VERSION 5.8 ;
BUSBITCHARS "[]" ;
DIVIDERCHAR "/" ;
UNITS
    DATABASE MICRONS 1000 ;
END UNITS

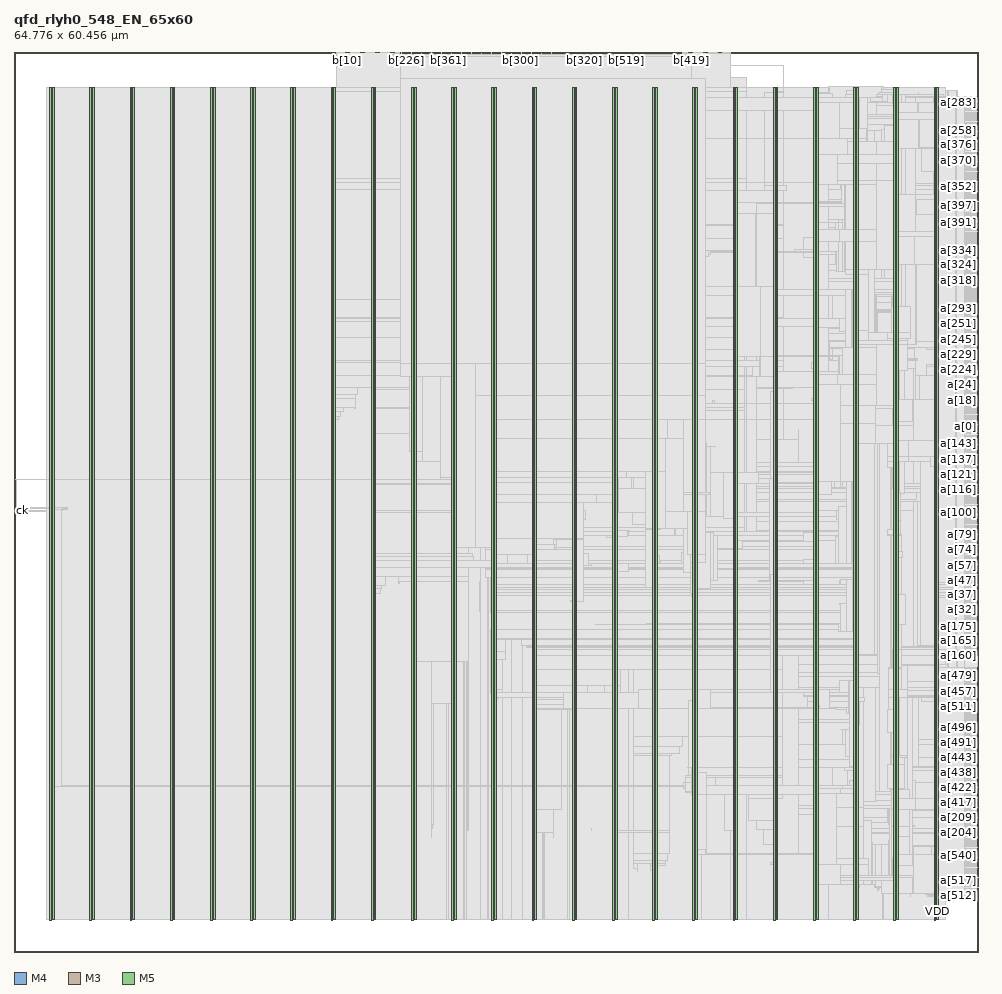
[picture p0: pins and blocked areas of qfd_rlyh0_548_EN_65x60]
MACRO qfd_rlyh0_548_EN_65x60
  FOREIGN qfd_rlyh0_548_EN_65x60 0 0 ;
  CLASS BLOCK ;
  SIZE 64.776 BY 60.456 ;
  PIN a[0]
    DIRECTION INPUT ;
    USE SIGNAL ;
    PORT
      LAYER M4 ;
        RECT  64.692 35.28 64.776 35.304 ;
    END
  END a[0]
  PIN a[100]
    DIRECTION INPUT ;
    USE SIGNAL ;
    PORT
      LAYER M4 ;
        RECT  64.692 29.52 64.776 29.544 ;
    END
  END a[100]
  PIN a[101]
    DIRECTION INPUT ;
    USE SIGNAL ;
    PORT
      LAYER M4 ;
        RECT  64.692 29.616 64.776 29.64 ;
    END
  END a[101]
  PIN a[102]
    DIRECTION INPUT ;
    USE SIGNAL ;
    PORT
      LAYER M4 ;
        RECT  64.692 29.712 64.776 29.736 ;
    END
  END a[102]
  PIN a[103]
    DIRECTION INPUT ;
    USE SIGNAL ;
    PORT
      LAYER M4 ;
        RECT  64.692 29.808 64.776 29.832 ;
    END
  END a[103]
  PIN a[104]
    DIRECTION INPUT ;
    USE SIGNAL ;
    PORT
      LAYER M4 ;
        RECT  64.692 29.904 64.776 29.928 ;
    END
  END a[104]
  PIN a[105]
    DIRECTION INPUT ;
    USE SIGNAL ;
    PORT
      LAYER M4 ;
        RECT  64.692 30 64.776 30.024 ;
    END
  END a[105]
  PIN a[106]
    DIRECTION INPUT ;
    USE SIGNAL ;
    PORT
      LAYER M4 ;
        RECT  64.692 30.096 64.776 30.12 ;
    END
  END a[106]
  PIN a[107]
    DIRECTION INPUT ;
    USE SIGNAL ;
    PORT
      LAYER M4 ;
        RECT  64.692 30.192 64.776 30.216 ;
    END
  END a[107]
  PIN a[108]
    DIRECTION INPUT ;
    USE SIGNAL ;
    PORT
      LAYER M4 ;
        RECT  64.692 30.288 64.776 30.312 ;
    END
  END a[108]
  PIN a[109]
    DIRECTION INPUT ;
    USE SIGNAL ;
    PORT
      LAYER M4 ;
        RECT  64.692 30.384 64.776 30.408 ;
    END
  END a[109]
  PIN a[10]
    DIRECTION INPUT ;
    USE SIGNAL ;
    PORT
      LAYER M4 ;
        RECT  64.692 36.24 64.776 36.264 ;
    END
  END a[10]
  PIN a[110]
    DIRECTION INPUT ;
    USE SIGNAL ;
    PORT
      LAYER M4 ;
        RECT  64.692 30.48 64.776 30.504 ;
    END
  END a[110]
  PIN a[111]
    DIRECTION INPUT ;
    USE SIGNAL ;
    PORT
      LAYER M4 ;
        RECT  64.692 30.576 64.776 30.6 ;
    END
  END a[111]
  PIN a[112]
    DIRECTION INPUT ;
    USE SIGNAL ;
    PORT
      LAYER M4 ;
        RECT  64.692 30.672 64.776 30.696 ;
    END
  END a[112]
  PIN a[113]
    DIRECTION INPUT ;
    USE SIGNAL ;
    PORT
      LAYER M4 ;
        RECT  64.692 30.768 64.776 30.792 ;
    END
  END a[113]
  PIN a[114]
    DIRECTION INPUT ;
    USE SIGNAL ;
    PORT
      LAYER M4 ;
        RECT  64.692 30.864 64.776 30.888 ;
    END
  END a[114]
  PIN a[115]
    DIRECTION INPUT ;
    USE SIGNAL ;
    PORT
      LAYER M4 ;
        RECT  64.692 30.96 64.776 30.984 ;
    END
  END a[115]
  PIN a[116]
    DIRECTION INPUT ;
    USE SIGNAL ;
    PORT
      LAYER M4 ;
        RECT  64.692 31.056 64.776 31.08 ;
    END
  END a[116]
  PIN a[117]
    DIRECTION INPUT ;
    USE SIGNAL ;
    PORT
      LAYER M4 ;
        RECT  64.692 31.152 64.776 31.176 ;
    END
  END a[117]
  PIN a[118]
    DIRECTION INPUT ;
    USE SIGNAL ;
    PORT
      LAYER M4 ;
        RECT  64.692 31.248 64.776 31.272 ;
    END
  END a[118]
  PIN a[119]
    DIRECTION INPUT ;
    USE SIGNAL ;
    PORT
      LAYER M4 ;
        RECT  64.692 31.344 64.776 31.368 ;
    END
  END a[119]
  PIN a[11]
    DIRECTION INPUT ;
    USE SIGNAL ;
    PORT
      LAYER M4 ;
        RECT  64.692 36.336 64.776 36.36 ;
    END
  END a[11]
  PIN a[120]
    DIRECTION INPUT ;
    USE SIGNAL ;
    PORT
      LAYER M4 ;
        RECT  64.692 31.44 64.776 31.464 ;
    END
  END a[120]
  PIN a[121]
    DIRECTION INPUT ;
    USE SIGNAL ;
    PORT
      LAYER M4 ;
        RECT  64.692 31.536 64.776 31.56 ;
    END
  END a[121]
  PIN a[122]
    DIRECTION INPUT ;
    USE SIGNAL ;
    PORT
      LAYER M4 ;
        RECT  64.692 31.632 64.776 31.656 ;
    END
  END a[122]
  PIN a[123]
    DIRECTION INPUT ;
    USE SIGNAL ;
    PORT
      LAYER M4 ;
        RECT  64.692 31.728 64.776 31.752 ;
    END
  END a[123]
  PIN a[124]
    DIRECTION INPUT ;
    USE SIGNAL ;
    PORT
      LAYER M4 ;
        RECT  64.692 31.824 64.776 31.848 ;
    END
  END a[124]
  PIN a[125]
    DIRECTION INPUT ;
    USE SIGNAL ;
    PORT
      LAYER M4 ;
        RECT  64.692 31.92 64.776 31.944 ;
    END
  END a[125]
  PIN a[126]
    DIRECTION INPUT ;
    USE SIGNAL ;
    PORT
      LAYER M4 ;
        RECT  64.692 32.016 64.776 32.04 ;
    END
  END a[126]
  PIN a[127]
    DIRECTION INPUT ;
    USE SIGNAL ;
    PORT
      LAYER M4 ;
        RECT  64.692 32.112 64.776 32.136 ;
    END
  END a[127]
  PIN a[128]
    DIRECTION INPUT ;
    USE SIGNAL ;
    PORT
      LAYER M4 ;
        RECT  64.692 32.208 64.776 32.232 ;
    END
  END a[128]
  PIN a[129]
    DIRECTION INPUT ;
    USE SIGNAL ;
    PORT
      LAYER M4 ;
        RECT  64.692 32.304 64.776 32.328 ;
    END
  END a[129]
  PIN a[12]
    DIRECTION INPUT ;
    USE SIGNAL ;
    PORT
      LAYER M4 ;
        RECT  64.692 36.432 64.776 36.456 ;
    END
  END a[12]
  PIN a[130]
    DIRECTION INPUT ;
    USE SIGNAL ;
    PORT
      LAYER M4 ;
        RECT  64.692 32.4 64.776 32.424 ;
    END
  END a[130]
  PIN a[131]
    DIRECTION INPUT ;
    USE SIGNAL ;
    PORT
      LAYER M4 ;
        RECT  64.692 32.496 64.776 32.52 ;
    END
  END a[131]
  PIN a[132]
    DIRECTION INPUT ;
    USE SIGNAL ;
    PORT
      LAYER M4 ;
        RECT  64.692 32.592 64.776 32.616 ;
    END
  END a[132]
  PIN a[133]
    DIRECTION INPUT ;
    USE SIGNAL ;
    PORT
      LAYER M4 ;
        RECT  64.692 32.688 64.776 32.712 ;
    END
  END a[133]
  PIN a[134]
    DIRECTION INPUT ;
    USE SIGNAL ;
    PORT
      LAYER M4 ;
        RECT  64.692 32.784 64.776 32.808 ;
    END
  END a[134]
  PIN a[135]
    DIRECTION INPUT ;
    USE SIGNAL ;
    PORT
      LAYER M4 ;
        RECT  64.692 32.88 64.776 32.904 ;
    END
  END a[135]
  PIN a[136]
    DIRECTION INPUT ;
    USE SIGNAL ;
    PORT
      LAYER M4 ;
        RECT  64.692 32.976 64.776 33 ;
    END
  END a[136]
  PIN a[137]
    DIRECTION INPUT ;
    USE SIGNAL ;
    PORT
      LAYER M4 ;
        RECT  64.692 33.072 64.776 33.096 ;
    END
  END a[137]
  PIN a[138]
    DIRECTION INPUT ;
    USE SIGNAL ;
    PORT
      LAYER M4 ;
        RECT  64.692 33.168 64.776 33.192 ;
    END
  END a[138]
  PIN a[139]
    DIRECTION INPUT ;
    USE SIGNAL ;
    PORT
      LAYER M4 ;
        RECT  64.692 33.264 64.776 33.288 ;
    END
  END a[139]
  PIN a[13]
    DIRECTION INPUT ;
    USE SIGNAL ;
    PORT
      LAYER M4 ;
        RECT  64.692 36.528 64.776 36.552 ;
    END
  END a[13]
  PIN a[140]
    DIRECTION INPUT ;
    USE SIGNAL ;
    PORT
      LAYER M4 ;
        RECT  64.692 33.36 64.776 33.384 ;
    END
  END a[140]
  PIN a[141]
    DIRECTION INPUT ;
    USE SIGNAL ;
    PORT
      LAYER M4 ;
        RECT  64.692 33.456 64.776 33.48 ;
    END
  END a[141]
  PIN a[142]
    DIRECTION INPUT ;
    USE SIGNAL ;
    PORT
      LAYER M4 ;
        RECT  64.692 33.552 64.776 33.576 ;
    END
  END a[142]
  PIN a[143]
    DIRECTION INPUT ;
    USE SIGNAL ;
    PORT
      LAYER M4 ;
        RECT  64.692 33.648 64.776 33.672 ;
    END
  END a[143]
  PIN a[144]
    DIRECTION INPUT ;
    USE SIGNAL ;
    PORT
      LAYER M4 ;
        RECT  64.692 33.744 64.776 33.768 ;
    END
  END a[144]
  PIN a[145]
    DIRECTION INPUT ;
    USE SIGNAL ;
    PORT
      LAYER M4 ;
        RECT  64.692 33.84 64.776 33.864 ;
    END
  END a[145]
  PIN a[146]
    DIRECTION INPUT ;
    USE SIGNAL ;
    PORT
      LAYER M4 ;
        RECT  64.692 33.936 64.776 33.96 ;
    END
  END a[146]
  PIN a[147]
    DIRECTION INPUT ;
    USE SIGNAL ;
    PORT
      LAYER M4 ;
        RECT  64.692 34.032 64.776 34.056 ;
    END
  END a[147]
  PIN a[148]
    DIRECTION INPUT ;
    USE SIGNAL ;
    PORT
      LAYER M4 ;
        RECT  64.692 34.128 64.776 34.152 ;
    END
  END a[148]
  PIN a[149]
    DIRECTION INPUT ;
    USE SIGNAL ;
    PORT
      LAYER M4 ;
        RECT  64.692 34.224 64.776 34.248 ;
    END
  END a[149]
  PIN a[14]
    DIRECTION INPUT ;
    USE SIGNAL ;
    PORT
      LAYER M4 ;
        RECT  64.692 36.624 64.776 36.648 ;
    END
  END a[14]
  PIN a[150]
    DIRECTION INPUT ;
    USE SIGNAL ;
    PORT
      LAYER M4 ;
        RECT  64.692 34.32 64.776 34.344 ;
    END
  END a[150]
  PIN a[151]
    DIRECTION INPUT ;
    USE SIGNAL ;
    PORT
      LAYER M4 ;
        RECT  64.692 34.416 64.776 34.44 ;
    END
  END a[151]
  PIN a[152]
    DIRECTION INPUT ;
    USE SIGNAL ;
    PORT
      LAYER M4 ;
        RECT  64.692 34.512 64.776 34.536 ;
    END
  END a[152]
  PIN a[153]
    DIRECTION INPUT ;
    USE SIGNAL ;
    PORT
      LAYER M4 ;
        RECT  64.692 34.608 64.776 34.632 ;
    END
  END a[153]
  PIN a[154]
    DIRECTION INPUT ;
    USE SIGNAL ;
    PORT
      LAYER M4 ;
        RECT  64.692 34.704 64.776 34.728 ;
    END
  END a[154]
  PIN a[155]
    DIRECTION INPUT ;
    USE SIGNAL ;
    PORT
      LAYER M4 ;
        RECT  64.692 34.8 64.776 34.824 ;
    END
  END a[155]
  PIN a[156]
    DIRECTION INPUT ;
    USE SIGNAL ;
    PORT
      LAYER M4 ;
        RECT  64.692 34.896 64.776 34.92 ;
    END
  END a[156]
  PIN a[157]
    DIRECTION INPUT ;
    USE SIGNAL ;
    PORT
      LAYER M4 ;
        RECT  64.692 34.992 64.776 35.016 ;
    END
  END a[157]
  PIN a[158]
    DIRECTION INPUT ;
    USE SIGNAL ;
    PORT
      LAYER M4 ;
        RECT  64.692 35.088 64.776 35.112 ;
    END
  END a[158]
  PIN a[159]
    DIRECTION INPUT ;
    USE SIGNAL ;
    PORT
      LAYER M4 ;
        RECT  64.692 35.184 64.776 35.208 ;
    END
  END a[159]
  PIN a[15]
    DIRECTION INPUT ;
    USE SIGNAL ;
    PORT
      LAYER M4 ;
        RECT  64.692 36.72 64.776 36.744 ;
    END
  END a[15]
  PIN a[160]
    DIRECTION INPUT ;
    USE SIGNAL ;
    PORT
      LAYER M4 ;
        RECT  64.692 19.92 64.776 19.944 ;
    END
  END a[160]
  PIN a[161]
    DIRECTION INPUT ;
    USE SIGNAL ;
    PORT
      LAYER M4 ;
        RECT  64.692 20.016 64.776 20.04 ;
    END
  END a[161]
  PIN a[162]
    DIRECTION INPUT ;
    USE SIGNAL ;
    PORT
      LAYER M4 ;
        RECT  64.692 20.112 64.776 20.136 ;
    END
  END a[162]
  PIN a[163]
    DIRECTION INPUT ;
    USE SIGNAL ;
    PORT
      LAYER M4 ;
        RECT  64.692 20.208 64.776 20.232 ;
    END
  END a[163]
  PIN a[164]
    DIRECTION INPUT ;
    USE SIGNAL ;
    PORT
      LAYER M4 ;
        RECT  64.692 20.304 64.776 20.328 ;
    END
  END a[164]
  PIN a[165]
    DIRECTION INPUT ;
    USE SIGNAL ;
    PORT
      LAYER M4 ;
        RECT  64.692 20.4 64.776 20.424 ;
    END
  END a[165]
  PIN a[166]
    DIRECTION INPUT ;
    USE SIGNAL ;
    PORT
      LAYER M4 ;
        RECT  64.692 20.496 64.776 20.52 ;
    END
  END a[166]
  PIN a[167]
    DIRECTION INPUT ;
    USE SIGNAL ;
    PORT
      LAYER M4 ;
        RECT  64.692 20.592 64.776 20.616 ;
    END
  END a[167]
  PIN a[168]
    DIRECTION INPUT ;
    USE SIGNAL ;
    PORT
      LAYER M4 ;
        RECT  64.692 20.688 64.776 20.712 ;
    END
  END a[168]
  PIN a[169]
    DIRECTION INPUT ;
    USE SIGNAL ;
    PORT
      LAYER M4 ;
        RECT  64.692 20.784 64.776 20.808 ;
    END
  END a[169]
  PIN a[16]
    DIRECTION INPUT ;
    USE SIGNAL ;
    PORT
      LAYER M4 ;
        RECT  64.692 36.816 64.776 36.84 ;
    END
  END a[16]
  PIN a[170]
    DIRECTION INPUT ;
    USE SIGNAL ;
    PORT
      LAYER M4 ;
        RECT  64.692 20.88 64.776 20.904 ;
    END
  END a[170]
  PIN a[171]
    DIRECTION INPUT ;
    USE SIGNAL ;
    PORT
      LAYER M4 ;
        RECT  64.692 20.976 64.776 21 ;
    END
  END a[171]
  PIN a[172]
    DIRECTION INPUT ;
    USE SIGNAL ;
    PORT
      LAYER M4 ;
        RECT  64.692 21.072 64.776 21.096 ;
    END
  END a[172]
  PIN a[173]
    DIRECTION INPUT ;
    USE SIGNAL ;
    PORT
      LAYER M4 ;
        RECT  64.692 21.168 64.776 21.192 ;
    END
  END a[173]
  PIN a[174]
    DIRECTION INPUT ;
    USE SIGNAL ;
    PORT
      LAYER M4 ;
        RECT  64.692 21.264 64.776 21.288 ;
    END
  END a[174]
  PIN a[175]
    DIRECTION INPUT ;
    USE SIGNAL ;
    PORT
      LAYER M4 ;
        RECT  64.692 21.36 64.776 21.384 ;
    END
  END a[175]
  PIN a[176]
    DIRECTION INPUT ;
    USE SIGNAL ;
    PORT
      LAYER M4 ;
        RECT  64.692 21.456 64.776 21.48 ;
    END
  END a[176]
  PIN a[177]
    DIRECTION INPUT ;
    USE SIGNAL ;
    PORT
      LAYER M4 ;
        RECT  64.692 21.552 64.776 21.576 ;
    END
  END a[177]
  PIN a[178]
    DIRECTION INPUT ;
    USE SIGNAL ;
    PORT
      LAYER M4 ;
        RECT  64.692 21.648 64.776 21.672 ;
    END
  END a[178]
  PIN a[179]
    DIRECTION INPUT ;
    USE SIGNAL ;
    PORT
      LAYER M4 ;
        RECT  64.692 21.744 64.776 21.768 ;
    END
  END a[179]
  PIN a[17]
    DIRECTION INPUT ;
    USE SIGNAL ;
    PORT
      LAYER M4 ;
        RECT  64.692 36.912 64.776 36.936 ;
    END
  END a[17]
  PIN a[180]
    DIRECTION INPUT ;
    USE SIGNAL ;
    PORT
      LAYER M4 ;
        RECT  64.692 21.84 64.776 21.864 ;
    END
  END a[180]
  PIN a[181]
    DIRECTION INPUT ;
    USE SIGNAL ;
    PORT
      LAYER M4 ;
        RECT  64.692 21.936 64.776 21.96 ;
    END
  END a[181]
  PIN a[182]
    DIRECTION INPUT ;
    USE SIGNAL ;
    PORT
      LAYER M4 ;
        RECT  64.692 22.032 64.776 22.056 ;
    END
  END a[182]
  PIN a[183]
    DIRECTION INPUT ;
    USE SIGNAL ;
    PORT
      LAYER M4 ;
        RECT  64.692 22.128 64.776 22.152 ;
    END
  END a[183]
  PIN a[184]
    DIRECTION INPUT ;
    USE SIGNAL ;
    PORT
      LAYER M4 ;
        RECT  64.692 22.224 64.776 22.248 ;
    END
  END a[184]
  PIN a[185]
    DIRECTION INPUT ;
    USE SIGNAL ;
    PORT
      LAYER M4 ;
        RECT  64.692 22.32 64.776 22.344 ;
    END
  END a[185]
  PIN a[186]
    DIRECTION INPUT ;
    USE SIGNAL ;
    PORT
      LAYER M4 ;
        RECT  64.692 22.416 64.776 22.44 ;
    END
  END a[186]
  PIN a[187]
    DIRECTION INPUT ;
    USE SIGNAL ;
    PORT
      LAYER M4 ;
        RECT  64.692 22.512 64.776 22.536 ;
    END
  END a[187]
  PIN a[188]
    DIRECTION INPUT ;
    USE SIGNAL ;
    PORT
      LAYER M4 ;
        RECT  64.692 22.608 64.776 22.632 ;
    END
  END a[188]
  PIN a[189]
    DIRECTION INPUT ;
    USE SIGNAL ;
    PORT
      LAYER M4 ;
        RECT  64.692 22.704 64.776 22.728 ;
    END
  END a[189]
  PIN a[18]
    DIRECTION INPUT ;
    USE SIGNAL ;
    PORT
      LAYER M4 ;
        RECT  64.692 37.008 64.776 37.032 ;
    END
  END a[18]
  PIN a[190]
    DIRECTION INPUT ;
    USE SIGNAL ;
    PORT
      LAYER M4 ;
        RECT  64.692 22.8 64.776 22.824 ;
    END
  END a[190]
  PIN a[191]
    DIRECTION INPUT ;
    USE SIGNAL ;
    PORT
      LAYER M4 ;
        RECT  64.692 22.896 64.776 22.92 ;
    END
  END a[191]
  PIN a[192]
    DIRECTION INPUT ;
    USE SIGNAL ;
    PORT
      LAYER M4 ;
        RECT  64.692 6.864 64.776 6.888 ;
    END
  END a[192]
  PIN a[193]
    DIRECTION INPUT ;
    USE SIGNAL ;
    PORT
      LAYER M4 ;
        RECT  64.692 6.96 64.776 6.984 ;
    END
  END a[193]
  PIN a[194]
    DIRECTION INPUT ;
    USE SIGNAL ;
    PORT
      LAYER M4 ;
        RECT  64.692 7.056 64.776 7.08 ;
    END
  END a[194]
  PIN a[195]
    DIRECTION INPUT ;
    USE SIGNAL ;
    PORT
      LAYER M4 ;
        RECT  64.692 7.152 64.776 7.176 ;
    END
  END a[195]
  PIN a[196]
    DIRECTION INPUT ;
    USE SIGNAL ;
    PORT
      LAYER M4 ;
        RECT  64.692 7.248 64.776 7.272 ;
    END
  END a[196]
  PIN a[197]
    DIRECTION INPUT ;
    USE SIGNAL ;
    PORT
      LAYER M4 ;
        RECT  64.692 7.344 64.776 7.368 ;
    END
  END a[197]
  PIN a[198]
    DIRECTION INPUT ;
    USE SIGNAL ;
    PORT
      LAYER M4 ;
        RECT  64.692 7.44 64.776 7.464 ;
    END
  END a[198]
  PIN a[199]
    DIRECTION INPUT ;
    USE SIGNAL ;
    PORT
      LAYER M4 ;
        RECT  64.692 7.536 64.776 7.56 ;
    END
  END a[199]
  PIN a[19]
    DIRECTION INPUT ;
    USE SIGNAL ;
    PORT
      LAYER M4 ;
        RECT  64.692 37.104 64.776 37.128 ;
    END
  END a[19]
  PIN a[1]
    DIRECTION INPUT ;
    USE SIGNAL ;
    PORT
      LAYER M4 ;
        RECT  64.692 35.376 64.776 35.4 ;
    END
  END a[1]
  PIN a[200]
    DIRECTION INPUT ;
    USE SIGNAL ;
    PORT
      LAYER M4 ;
        RECT  64.692 7.632 64.776 7.656 ;
    END
  END a[200]
  PIN a[201]
    DIRECTION INPUT ;
    USE SIGNAL ;
    PORT
      LAYER M4 ;
        RECT  64.692 7.728 64.776 7.752 ;
    END
  END a[201]
  PIN a[202]
    DIRECTION INPUT ;
    USE SIGNAL ;
    PORT
      LAYER M4 ;
        RECT  64.692 7.824 64.776 7.848 ;
    END
  END a[202]
  PIN a[203]
    DIRECTION INPUT ;
    USE SIGNAL ;
    PORT
      LAYER M4 ;
        RECT  64.692 7.92 64.776 7.944 ;
    END
  END a[203]
  PIN a[204]
    DIRECTION INPUT ;
    USE SIGNAL ;
    PORT
      LAYER M4 ;
        RECT  64.692 8.016 64.776 8.04 ;
    END
  END a[204]
  PIN a[205]
    DIRECTION INPUT ;
    USE SIGNAL ;
    PORT
      LAYER M4 ;
        RECT  64.692 8.112 64.776 8.136 ;
    END
  END a[205]
  PIN a[206]
    DIRECTION INPUT ;
    USE SIGNAL ;
    PORT
      LAYER M4 ;
        RECT  64.692 8.208 64.776 8.232 ;
    END
  END a[206]
  PIN a[207]
    DIRECTION INPUT ;
    USE SIGNAL ;
    PORT
      LAYER M4 ;
        RECT  64.692 8.304 64.776 8.328 ;
    END
  END a[207]
  PIN a[208]
    DIRECTION INPUT ;
    USE SIGNAL ;
    PORT
      LAYER M4 ;
        RECT  64.692 8.4 64.776 8.424 ;
    END
  END a[208]
  PIN a[209]
    DIRECTION INPUT ;
    USE SIGNAL ;
    PORT
      LAYER M4 ;
        RECT  64.692 8.496 64.776 8.52 ;
    END
  END a[209]
  PIN a[20]
    DIRECTION INPUT ;
    USE SIGNAL ;
    PORT
      LAYER M4 ;
        RECT  64.692 37.2 64.776 37.224 ;
    END
  END a[20]
  PIN a[210]
    DIRECTION INPUT ;
    USE SIGNAL ;
    PORT
      LAYER M4 ;
        RECT  64.692 8.592 64.776 8.616 ;
    END
  END a[210]
  PIN a[211]
    DIRECTION INPUT ;
    USE SIGNAL ;
    PORT
      LAYER M4 ;
        RECT  64.692 8.688 64.776 8.712 ;
    END
  END a[211]
  PIN a[212]
    DIRECTION INPUT ;
    USE SIGNAL ;
    PORT
      LAYER M4 ;
        RECT  64.692 8.784 64.776 8.808 ;
    END
  END a[212]
  PIN a[213]
    DIRECTION INPUT ;
    USE SIGNAL ;
    PORT
      LAYER M4 ;
        RECT  64.692 8.88 64.776 8.904 ;
    END
  END a[213]
  PIN a[214]
    DIRECTION INPUT ;
    USE SIGNAL ;
    PORT
      LAYER M4 ;
        RECT  64.692 8.976 64.776 9 ;
    END
  END a[214]
  PIN a[215]
    DIRECTION INPUT ;
    USE SIGNAL ;
    PORT
      LAYER M4 ;
        RECT  64.692 9.072 64.776 9.096 ;
    END
  END a[215]
  PIN a[216]
    DIRECTION INPUT ;
    USE SIGNAL ;
    PORT
      LAYER M4 ;
        RECT  64.692 9.168 64.776 9.192 ;
    END
  END a[216]
  PIN a[217]
    DIRECTION INPUT ;
    USE SIGNAL ;
    PORT
      LAYER M4 ;
        RECT  64.692 9.264 64.776 9.288 ;
    END
  END a[217]
  PIN a[218]
    DIRECTION INPUT ;
    USE SIGNAL ;
    PORT
      LAYER M4 ;
        RECT  64.692 9.36 64.776 9.384 ;
    END
  END a[218]
  PIN a[219]
    DIRECTION INPUT ;
    USE SIGNAL ;
    PORT
      LAYER M4 ;
        RECT  64.692 9.456 64.776 9.48 ;
    END
  END a[219]
  PIN a[21]
    DIRECTION INPUT ;
    USE SIGNAL ;
    PORT
      LAYER M4 ;
        RECT  64.692 37.296 64.776 37.32 ;
    END
  END a[21]
  PIN a[220]
    DIRECTION INPUT ;
    USE SIGNAL ;
    PORT
      LAYER M4 ;
        RECT  64.692 9.552 64.776 9.576 ;
    END
  END a[220]
  PIN a[221]
    DIRECTION INPUT ;
    USE SIGNAL ;
    PORT
      LAYER M4 ;
        RECT  64.692 9.648 64.776 9.672 ;
    END
  END a[221]
  PIN a[222]
    DIRECTION INPUT ;
    USE SIGNAL ;
    PORT
      LAYER M4 ;
        RECT  64.692 9.744 64.776 9.768 ;
    END
  END a[222]
  PIN a[223]
    DIRECTION INPUT ;
    USE SIGNAL ;
    PORT
      LAYER M4 ;
        RECT  64.692 9.84 64.776 9.864 ;
    END
  END a[223]
  PIN a[224]
    DIRECTION INPUT ;
    USE SIGNAL ;
    PORT
      LAYER M4 ;
        RECT  64.692 39.12 64.776 39.144 ;
    END
  END a[224]
  PIN a[225]
    DIRECTION INPUT ;
    USE SIGNAL ;
    PORT
      LAYER M4 ;
        RECT  64.692 39.216 64.776 39.24 ;
    END
  END a[225]
  PIN a[226]
    DIRECTION INPUT ;
    USE SIGNAL ;
    PORT
      LAYER M4 ;
        RECT  64.692 39.312 64.776 39.336 ;
    END
  END a[226]
  PIN a[227]
    DIRECTION INPUT ;
    USE SIGNAL ;
    PORT
      LAYER M4 ;
        RECT  64.692 39.408 64.776 39.432 ;
    END
  END a[227]
  PIN a[228]
    DIRECTION INPUT ;
    USE SIGNAL ;
    PORT
      LAYER M4 ;
        RECT  64.692 39.504 64.776 39.528 ;
    END
  END a[228]
  PIN a[229]
    DIRECTION INPUT ;
    USE SIGNAL ;
    PORT
      LAYER M4 ;
        RECT  64.692 39.6 64.776 39.624 ;
    END
  END a[229]
  PIN a[22]
    DIRECTION INPUT ;
    USE SIGNAL ;
    PORT
      LAYER M4 ;
        RECT  64.692 37.392 64.776 37.416 ;
    END
  END a[22]
  PIN a[230]
    DIRECTION INPUT ;
    USE SIGNAL ;
    PORT
      LAYER M4 ;
        RECT  64.692 39.696 64.776 39.72 ;
    END
  END a[230]
  PIN a[231]
    DIRECTION INPUT ;
    USE SIGNAL ;
    PORT
      LAYER M4 ;
        RECT  64.692 39.792 64.776 39.816 ;
    END
  END a[231]
  PIN a[232]
    DIRECTION INPUT ;
    USE SIGNAL ;
    PORT
      LAYER M4 ;
        RECT  64.692 39.888 64.776 39.912 ;
    END
  END a[232]
  PIN a[233]
    DIRECTION INPUT ;
    USE SIGNAL ;
    PORT
      LAYER M4 ;
        RECT  64.692 39.984 64.776 40.008 ;
    END
  END a[233]
  PIN a[234]
    DIRECTION INPUT ;
    USE SIGNAL ;
    PORT
      LAYER M4 ;
        RECT  64.692 40.08 64.776 40.104 ;
    END
  END a[234]
  PIN a[235]
    DIRECTION INPUT ;
    USE SIGNAL ;
    PORT
      LAYER M4 ;
        RECT  64.692 40.176 64.776 40.2 ;
    END
  END a[235]
  PIN a[236]
    DIRECTION INPUT ;
    USE SIGNAL ;
    PORT
      LAYER M4 ;
        RECT  64.692 40.272 64.776 40.296 ;
    END
  END a[236]
  PIN a[237]
    DIRECTION INPUT ;
    USE SIGNAL ;
    PORT
      LAYER M4 ;
        RECT  64.692 40.368 64.776 40.392 ;
    END
  END a[237]
  PIN a[238]
    DIRECTION INPUT ;
    USE SIGNAL ;
    PORT
      LAYER M4 ;
        RECT  64.692 40.464 64.776 40.488 ;
    END
  END a[238]
  PIN a[239]
    DIRECTION INPUT ;
    USE SIGNAL ;
    PORT
      LAYER M4 ;
        RECT  64.692 40.56 64.776 40.584 ;
    END
  END a[239]
  PIN a[23]
    DIRECTION INPUT ;
    USE SIGNAL ;
    PORT
      LAYER M4 ;
        RECT  64.692 37.488 64.776 37.512 ;
    END
  END a[23]
  PIN a[240]
    DIRECTION INPUT ;
    USE SIGNAL ;
    PORT
      LAYER M4 ;
        RECT  64.692 40.656 64.776 40.68 ;
    END
  END a[240]
  PIN a[241]
    DIRECTION INPUT ;
    USE SIGNAL ;
    PORT
      LAYER M4 ;
        RECT  64.692 40.752 64.776 40.776 ;
    END
  END a[241]
  PIN a[242]
    DIRECTION INPUT ;
    USE SIGNAL ;
    PORT
      LAYER M4 ;
        RECT  64.692 40.848 64.776 40.872 ;
    END
  END a[242]
  PIN a[243]
    DIRECTION INPUT ;
    USE SIGNAL ;
    PORT
      LAYER M4 ;
        RECT  64.692 40.944 64.776 40.968 ;
    END
  END a[243]
  PIN a[244]
    DIRECTION INPUT ;
    USE SIGNAL ;
    PORT
      LAYER M4 ;
        RECT  64.692 41.04 64.776 41.064 ;
    END
  END a[244]
  PIN a[245]
    DIRECTION INPUT ;
    USE SIGNAL ;
    PORT
      LAYER M4 ;
        RECT  64.692 41.136 64.776 41.16 ;
    END
  END a[245]
  PIN a[246]
    DIRECTION INPUT ;
    USE SIGNAL ;
    PORT
      LAYER M4 ;
        RECT  64.692 41.232 64.776 41.256 ;
    END
  END a[246]
  PIN a[247]
    DIRECTION INPUT ;
    USE SIGNAL ;
    PORT
      LAYER M4 ;
        RECT  64.692 41.328 64.776 41.352 ;
    END
  END a[247]
  PIN a[248]
    DIRECTION INPUT ;
    USE SIGNAL ;
    PORT
      LAYER M4 ;
        RECT  64.692 41.424 64.776 41.448 ;
    END
  END a[248]
  PIN a[249]
    DIRECTION INPUT ;
    USE SIGNAL ;
    PORT
      LAYER M4 ;
        RECT  64.692 41.52 64.776 41.544 ;
    END
  END a[249]
  PIN a[24]
    DIRECTION INPUT ;
    USE SIGNAL ;
    PORT
      LAYER M4 ;
        RECT  64.692 37.584 64.776 37.608 ;
    END
  END a[24]
  PIN a[250]
    DIRECTION INPUT ;
    USE SIGNAL ;
    PORT
      LAYER M4 ;
        RECT  64.692 41.616 64.776 41.64 ;
    END
  END a[250]
  PIN a[251]
    DIRECTION INPUT ;
    USE SIGNAL ;
    PORT
      LAYER M4 ;
        RECT  64.692 41.712 64.776 41.736 ;
    END
  END a[251]
  PIN a[252]
    DIRECTION INPUT ;
    USE SIGNAL ;
    PORT
      LAYER M4 ;
        RECT  64.692 41.808 64.776 41.832 ;
    END
  END a[252]
  PIN a[253]
    DIRECTION INPUT ;
    USE SIGNAL ;
    PORT
      LAYER M4 ;
        RECT  64.692 41.904 64.776 41.928 ;
    END
  END a[253]
  PIN a[254]
    DIRECTION INPUT ;
    USE SIGNAL ;
    PORT
      LAYER M4 ;
        RECT  64.692 42 64.776 42.024 ;
    END
  END a[254]
  PIN a[255]
    DIRECTION INPUT ;
    USE SIGNAL ;
    PORT
      LAYER M4 ;
        RECT  64.692 42.096 64.776 42.12 ;
    END
  END a[255]
  PIN a[256]
    DIRECTION INPUT ;
    USE SIGNAL ;
    PORT
      LAYER M4 ;
        RECT  64.692 54.48 64.776 54.504 ;
    END
  END a[256]
  PIN a[257]
    DIRECTION INPUT ;
    USE SIGNAL ;
    PORT
      LAYER M4 ;
        RECT  64.692 54.576 64.776 54.6 ;
    END
  END a[257]
  PIN a[258]
    DIRECTION INPUT ;
    USE SIGNAL ;
    PORT
      LAYER M4 ;
        RECT  64.692 54.672 64.776 54.696 ;
    END
  END a[258]
  PIN a[259]
    DIRECTION INPUT ;
    USE SIGNAL ;
    PORT
      LAYER M4 ;
        RECT  64.692 54.768 64.776 54.792 ;
    END
  END a[259]
  PIN a[25]
    DIRECTION INPUT ;
    USE SIGNAL ;
    PORT
      LAYER M4 ;
        RECT  64.692 37.68 64.776 37.704 ;
    END
  END a[25]
  PIN a[260]
    DIRECTION INPUT ;
    USE SIGNAL ;
    PORT
      LAYER M4 ;
        RECT  64.692 54.864 64.776 54.888 ;
    END
  END a[260]
  PIN a[261]
    DIRECTION INPUT ;
    USE SIGNAL ;
    PORT
      LAYER M4 ;
        RECT  64.692 54.96 64.776 54.984 ;
    END
  END a[261]
  PIN a[262]
    DIRECTION INPUT ;
    USE SIGNAL ;
    PORT
      LAYER M4 ;
        RECT  64.692 55.056 64.776 55.08 ;
    END
  END a[262]
  PIN a[263]
    DIRECTION INPUT ;
    USE SIGNAL ;
    PORT
      LAYER M4 ;
        RECT  64.692 55.152 64.776 55.176 ;
    END
  END a[263]
  PIN a[264]
    DIRECTION INPUT ;
    USE SIGNAL ;
    PORT
      LAYER M4 ;
        RECT  64.692 55.248 64.776 55.272 ;
    END
  END a[264]
  PIN a[265]
    DIRECTION INPUT ;
    USE SIGNAL ;
    PORT
      LAYER M4 ;
        RECT  64.692 55.344 64.776 55.368 ;
    END
  END a[265]
  PIN a[266]
    DIRECTION INPUT ;
    USE SIGNAL ;
    PORT
      LAYER M4 ;
        RECT  64.692 55.44 64.776 55.464 ;
    END
  END a[266]
  PIN a[267]
    DIRECTION INPUT ;
    USE SIGNAL ;
    PORT
      LAYER M4 ;
        RECT  64.692 55.536 64.776 55.56 ;
    END
  END a[267]
  PIN a[268]
    DIRECTION INPUT ;
    USE SIGNAL ;
    PORT
      LAYER M4 ;
        RECT  64.692 55.632 64.776 55.656 ;
    END
  END a[268]
  PIN a[269]
    DIRECTION INPUT ;
    USE SIGNAL ;
    PORT
      LAYER M4 ;
        RECT  64.692 55.728 64.776 55.752 ;
    END
  END a[269]
  PIN a[26]
    DIRECTION INPUT ;
    USE SIGNAL ;
    PORT
      LAYER M4 ;
        RECT  64.692 37.776 64.776 37.8 ;
    END
  END a[26]
  PIN a[270]
    DIRECTION INPUT ;
    USE SIGNAL ;
    PORT
      LAYER M4 ;
        RECT  64.692 55.824 64.776 55.848 ;
    END
  END a[270]
  PIN a[271]
    DIRECTION INPUT ;
    USE SIGNAL ;
    PORT
      LAYER M4 ;
        RECT  64.692 55.92 64.776 55.944 ;
    END
  END a[271]
  PIN a[272]
    DIRECTION INPUT ;
    USE SIGNAL ;
    PORT
      LAYER M4 ;
        RECT  64.692 56.016 64.776 56.04 ;
    END
  END a[272]
  PIN a[273]
    DIRECTION INPUT ;
    USE SIGNAL ;
    PORT
      LAYER M4 ;
        RECT  64.692 56.112 64.776 56.136 ;
    END
  END a[273]
  PIN a[274]
    DIRECTION INPUT ;
    USE SIGNAL ;
    PORT
      LAYER M4 ;
        RECT  64.692 56.208 64.776 56.232 ;
    END
  END a[274]
  PIN a[275]
    DIRECTION INPUT ;
    USE SIGNAL ;
    PORT
      LAYER M4 ;
        RECT  64.692 56.304 64.776 56.328 ;
    END
  END a[275]
  PIN a[276]
    DIRECTION INPUT ;
    USE SIGNAL ;
    PORT
      LAYER M4 ;
        RECT  64.692 56.4 64.776 56.424 ;
    END
  END a[276]
  PIN a[277]
    DIRECTION INPUT ;
    USE SIGNAL ;
    PORT
      LAYER M4 ;
        RECT  64.692 56.496 64.776 56.52 ;
    END
  END a[277]
  PIN a[278]
    DIRECTION INPUT ;
    USE SIGNAL ;
    PORT
      LAYER M4 ;
        RECT  64.692 56.592 64.776 56.616 ;
    END
  END a[278]
  PIN a[279]
    DIRECTION INPUT ;
    USE SIGNAL ;
    PORT
      LAYER M4 ;
        RECT  64.692 56.688 64.776 56.712 ;
    END
  END a[279]
  PIN a[27]
    DIRECTION INPUT ;
    USE SIGNAL ;
    PORT
      LAYER M4 ;
        RECT  64.692 37.872 64.776 37.896 ;
    END
  END a[27]
  PIN a[280]
    DIRECTION INPUT ;
    USE SIGNAL ;
    PORT
      LAYER M4 ;
        RECT  64.692 56.784 64.776 56.808 ;
    END
  END a[280]
  PIN a[281]
    DIRECTION INPUT ;
    USE SIGNAL ;
    PORT
      LAYER M4 ;
        RECT  64.692 56.88 64.776 56.904 ;
    END
  END a[281]
  PIN a[282]
    DIRECTION INPUT ;
    USE SIGNAL ;
    PORT
      LAYER M4 ;
        RECT  64.692 56.976 64.776 57 ;
    END
  END a[282]
  PIN a[283]
    DIRECTION INPUT ;
    USE SIGNAL ;
    PORT
      LAYER M4 ;
        RECT  64.692 57.072 64.776 57.096 ;
    END
  END a[283]
  PIN a[284]
    DIRECTION INPUT ;
    USE SIGNAL ;
    PORT
      LAYER M4 ;
        RECT  64.692 57.168 64.776 57.192 ;
    END
  END a[284]
  PIN a[285]
    DIRECTION INPUT ;
    USE SIGNAL ;
    PORT
      LAYER M4 ;
        RECT  64.692 57.264 64.776 57.288 ;
    END
  END a[285]
  PIN a[286]
    DIRECTION INPUT ;
    USE SIGNAL ;
    PORT
      LAYER M4 ;
        RECT  64.692 57.36 64.776 57.384 ;
    END
  END a[286]
  PIN a[287]
    DIRECTION INPUT ;
    USE SIGNAL ;
    PORT
      LAYER M4 ;
        RECT  64.692 57.456 64.776 57.48 ;
    END
  END a[287]
  PIN a[288]
    DIRECTION INPUT ;
    USE SIGNAL ;
    PORT
      LAYER M4 ;
        RECT  64.692 42.192 64.776 42.216 ;
    END
  END a[288]
  PIN a[289]
    DIRECTION INPUT ;
    USE SIGNAL ;
    PORT
      LAYER M4 ;
        RECT  64.692 42.288 64.776 42.312 ;
    END
  END a[289]
  PIN a[28]
    DIRECTION INPUT ;
    USE SIGNAL ;
    PORT
      LAYER M4 ;
        RECT  64.692 37.968 64.776 37.992 ;
    END
  END a[28]
  PIN a[290]
    DIRECTION INPUT ;
    USE SIGNAL ;
    PORT
      LAYER M4 ;
        RECT  64.692 42.384 64.776 42.408 ;
    END
  END a[290]
  PIN a[291]
    DIRECTION INPUT ;
    USE SIGNAL ;
    PORT
      LAYER M4 ;
        RECT  64.692 42.48 64.776 42.504 ;
    END
  END a[291]
  PIN a[292]
    DIRECTION INPUT ;
    USE SIGNAL ;
    PORT
      LAYER M4 ;
        RECT  64.692 42.576 64.776 42.6 ;
    END
  END a[292]
  PIN a[293]
    DIRECTION INPUT ;
    USE SIGNAL ;
    PORT
      LAYER M4 ;
        RECT  64.692 42.672 64.776 42.696 ;
    END
  END a[293]
  PIN a[294]
    DIRECTION INPUT ;
    USE SIGNAL ;
    PORT
      LAYER M4 ;
        RECT  64.692 42.768 64.776 42.792 ;
    END
  END a[294]
  PIN a[295]
    DIRECTION INPUT ;
    USE SIGNAL ;
    PORT
      LAYER M4 ;
        RECT  64.692 42.864 64.776 42.888 ;
    END
  END a[295]
  PIN a[296]
    DIRECTION INPUT ;
    USE SIGNAL ;
    PORT
      LAYER M4 ;
        RECT  64.692 42.96 64.776 42.984 ;
    END
  END a[296]
  PIN a[297]
    DIRECTION INPUT ;
    USE SIGNAL ;
    PORT
      LAYER M4 ;
        RECT  64.692 43.056 64.776 43.08 ;
    END
  END a[297]
  PIN a[298]
    DIRECTION INPUT ;
    USE SIGNAL ;
    PORT
      LAYER M4 ;
        RECT  64.692 43.152 64.776 43.176 ;
    END
  END a[298]
  PIN a[299]
    DIRECTION INPUT ;
    USE SIGNAL ;
    PORT
      LAYER M4 ;
        RECT  64.692 43.248 64.776 43.272 ;
    END
  END a[299]
  PIN a[29]
    DIRECTION INPUT ;
    USE SIGNAL ;
    PORT
      LAYER M4 ;
        RECT  64.692 38.064 64.776 38.088 ;
    END
  END a[29]
  PIN a[2]
    DIRECTION INPUT ;
    USE SIGNAL ;
    PORT
      LAYER M4 ;
        RECT  64.692 35.472 64.776 35.496 ;
    END
  END a[2]
  PIN a[300]
    DIRECTION INPUT ;
    USE SIGNAL ;
    PORT
      LAYER M4 ;
        RECT  64.692 43.344 64.776 43.368 ;
    END
  END a[300]
  PIN a[301]
    DIRECTION INPUT ;
    USE SIGNAL ;
    PORT
      LAYER M4 ;
        RECT  64.692 43.44 64.776 43.464 ;
    END
  END a[301]
  PIN a[302]
    DIRECTION INPUT ;
    USE SIGNAL ;
    PORT
      LAYER M4 ;
        RECT  64.692 43.536 64.776 43.56 ;
    END
  END a[302]
  PIN a[303]
    DIRECTION INPUT ;
    USE SIGNAL ;
    PORT
      LAYER M4 ;
        RECT  64.692 43.632 64.776 43.656 ;
    END
  END a[303]
  PIN a[304]
    DIRECTION INPUT ;
    USE SIGNAL ;
    PORT
      LAYER M4 ;
        RECT  64.692 43.728 64.776 43.752 ;
    END
  END a[304]
  PIN a[305]
    DIRECTION INPUT ;
    USE SIGNAL ;
    PORT
      LAYER M4 ;
        RECT  64.692 43.824 64.776 43.848 ;
    END
  END a[305]
  PIN a[306]
    DIRECTION INPUT ;
    USE SIGNAL ;
    PORT
      LAYER M4 ;
        RECT  64.692 43.92 64.776 43.944 ;
    END
  END a[306]
  PIN a[307]
    DIRECTION INPUT ;
    USE SIGNAL ;
    PORT
      LAYER M4 ;
        RECT  64.692 44.016 64.776 44.04 ;
    END
  END a[307]
  PIN a[308]
    DIRECTION INPUT ;
    USE SIGNAL ;
    PORT
      LAYER M4 ;
        RECT  64.692 44.112 64.776 44.136 ;
    END
  END a[308]
  PIN a[309]
    DIRECTION INPUT ;
    USE SIGNAL ;
    PORT
      LAYER M4 ;
        RECT  64.692 44.208 64.776 44.232 ;
    END
  END a[309]
  PIN a[30]
    DIRECTION INPUT ;
    USE SIGNAL ;
    PORT
      LAYER M4 ;
        RECT  64.692 38.16 64.776 38.184 ;
    END
  END a[30]
  PIN a[310]
    DIRECTION INPUT ;
    USE SIGNAL ;
    PORT
      LAYER M4 ;
        RECT  64.692 44.304 64.776 44.328 ;
    END
  END a[310]
  PIN a[311]
    DIRECTION INPUT ;
    USE SIGNAL ;
    PORT
      LAYER M4 ;
        RECT  64.692 44.4 64.776 44.424 ;
    END
  END a[311]
  PIN a[312]
    DIRECTION INPUT ;
    USE SIGNAL ;
    PORT
      LAYER M4 ;
        RECT  64.692 44.496 64.776 44.52 ;
    END
  END a[312]
  PIN a[313]
    DIRECTION INPUT ;
    USE SIGNAL ;
    PORT
      LAYER M4 ;
        RECT  64.692 44.592 64.776 44.616 ;
    END
  END a[313]
  PIN a[314]
    DIRECTION INPUT ;
    USE SIGNAL ;
    PORT
      LAYER M4 ;
        RECT  64.692 44.688 64.776 44.712 ;
    END
  END a[314]
  PIN a[315]
    DIRECTION INPUT ;
    USE SIGNAL ;
    PORT
      LAYER M4 ;
        RECT  64.692 44.784 64.776 44.808 ;
    END
  END a[315]
  PIN a[316]
    DIRECTION INPUT ;
    USE SIGNAL ;
    PORT
      LAYER M4 ;
        RECT  64.692 44.88 64.776 44.904 ;
    END
  END a[316]
  PIN a[317]
    DIRECTION INPUT ;
    USE SIGNAL ;
    PORT
      LAYER M4 ;
        RECT  64.692 44.976 64.776 45 ;
    END
  END a[317]
  PIN a[318]
    DIRECTION INPUT ;
    USE SIGNAL ;
    PORT
      LAYER M4 ;
        RECT  64.692 45.072 64.776 45.096 ;
    END
  END a[318]
  PIN a[319]
    DIRECTION INPUT ;
    USE SIGNAL ;
    PORT
      LAYER M4 ;
        RECT  64.692 45.168 64.776 45.192 ;
    END
  END a[319]
  PIN a[31]
    DIRECTION INPUT ;
    USE SIGNAL ;
    PORT
      LAYER M4 ;
        RECT  64.692 38.256 64.776 38.28 ;
    END
  END a[31]
  PIN a[320]
    DIRECTION INPUT ;
    USE SIGNAL ;
    PORT
      LAYER M4 ;
        RECT  64.692 45.264 64.776 45.288 ;
    END
  END a[320]
  PIN a[321]
    DIRECTION INPUT ;
    USE SIGNAL ;
    PORT
      LAYER M4 ;
        RECT  64.692 45.36 64.776 45.384 ;
    END
  END a[321]
  PIN a[322]
    DIRECTION INPUT ;
    USE SIGNAL ;
    PORT
      LAYER M4 ;
        RECT  64.692 45.456 64.776 45.48 ;
    END
  END a[322]
  PIN a[323]
    DIRECTION INPUT ;
    USE SIGNAL ;
    PORT
      LAYER M4 ;
        RECT  64.692 45.552 64.776 45.576 ;
    END
  END a[323]
  PIN a[324]
    DIRECTION INPUT ;
    USE SIGNAL ;
    PORT
      LAYER M4 ;
        RECT  64.692 45.648 64.776 45.672 ;
    END
  END a[324]
  PIN a[325]
    DIRECTION INPUT ;
    USE SIGNAL ;
    PORT
      LAYER M4 ;
        RECT  64.692 45.744 64.776 45.768 ;
    END
  END a[325]
  PIN a[326]
    DIRECTION INPUT ;
    USE SIGNAL ;
    PORT
      LAYER M4 ;
        RECT  64.692 45.84 64.776 45.864 ;
    END
  END a[326]
  PIN a[327]
    DIRECTION INPUT ;
    USE SIGNAL ;
    PORT
      LAYER M4 ;
        RECT  64.692 45.936 64.776 45.96 ;
    END
  END a[327]
  PIN a[328]
    DIRECTION INPUT ;
    USE SIGNAL ;
    PORT
      LAYER M4 ;
        RECT  64.692 46.032 64.776 46.056 ;
    END
  END a[328]
  PIN a[329]
    DIRECTION INPUT ;
    USE SIGNAL ;
    PORT
      LAYER M4 ;
        RECT  64.692 46.128 64.776 46.152 ;
    END
  END a[329]
  PIN a[32]
    DIRECTION INPUT ;
    USE SIGNAL ;
    PORT
      LAYER M4 ;
        RECT  64.692 22.992 64.776 23.016 ;
    END
  END a[32]
  PIN a[330]
    DIRECTION INPUT ;
    USE SIGNAL ;
    PORT
      LAYER M4 ;
        RECT  64.692 46.224 64.776 46.248 ;
    END
  END a[330]
  PIN a[331]
    DIRECTION INPUT ;
    USE SIGNAL ;
    PORT
      LAYER M4 ;
        RECT  64.692 46.32 64.776 46.344 ;
    END
  END a[331]
  PIN a[332]
    DIRECTION INPUT ;
    USE SIGNAL ;
    PORT
      LAYER M4 ;
        RECT  64.692 46.416 64.776 46.44 ;
    END
  END a[332]
  PIN a[333]
    DIRECTION INPUT ;
    USE SIGNAL ;
    PORT
      LAYER M4 ;
        RECT  64.692 46.512 64.776 46.536 ;
    END
  END a[333]
  PIN a[334]
    DIRECTION INPUT ;
    USE SIGNAL ;
    PORT
      LAYER M4 ;
        RECT  64.692 46.608 64.776 46.632 ;
    END
  END a[334]
  PIN a[335]
    DIRECTION INPUT ;
    USE SIGNAL ;
    PORT
      LAYER M4 ;
        RECT  64.692 46.704 64.776 46.728 ;
    END
  END a[335]
  PIN a[336]
    DIRECTION INPUT ;
    USE SIGNAL ;
    PORT
      LAYER M4 ;
        RECT  64.692 46.8 64.776 46.824 ;
    END
  END a[336]
  PIN a[337]
    DIRECTION INPUT ;
    USE SIGNAL ;
    PORT
      LAYER M4 ;
        RECT  64.692 46.896 64.776 46.92 ;
    END
  END a[337]
  PIN a[338]
    DIRECTION INPUT ;
    USE SIGNAL ;
    PORT
      LAYER M4 ;
        RECT  64.692 46.992 64.776 47.016 ;
    END
  END a[338]
  PIN a[339]
    DIRECTION INPUT ;
    USE SIGNAL ;
    PORT
      LAYER M4 ;
        RECT  64.692 47.088 64.776 47.112 ;
    END
  END a[339]
  PIN a[33]
    DIRECTION INPUT ;
    USE SIGNAL ;
    PORT
      LAYER M4 ;
        RECT  64.692 23.088 64.776 23.112 ;
    END
  END a[33]
  PIN a[340]
    DIRECTION INPUT ;
    USE SIGNAL ;
    PORT
      LAYER M4 ;
        RECT  64.692 47.184 64.776 47.208 ;
    END
  END a[340]
  PIN a[341]
    DIRECTION INPUT ;
    USE SIGNAL ;
    PORT
      LAYER M4 ;
        RECT  64.692 47.28 64.776 47.304 ;
    END
  END a[341]
  PIN a[342]
    DIRECTION INPUT ;
    USE SIGNAL ;
    PORT
      LAYER M4 ;
        RECT  64.692 47.376 64.776 47.4 ;
    END
  END a[342]
  PIN a[343]
    DIRECTION INPUT ;
    USE SIGNAL ;
    PORT
      LAYER M4 ;
        RECT  64.692 47.472 64.776 47.496 ;
    END
  END a[343]
  PIN a[344]
    DIRECTION INPUT ;
    USE SIGNAL ;
    PORT
      LAYER M4 ;
        RECT  64.692 47.568 64.776 47.592 ;
    END
  END a[344]
  PIN a[345]
    DIRECTION INPUT ;
    USE SIGNAL ;
    PORT
      LAYER M4 ;
        RECT  64.692 47.664 64.776 47.688 ;
    END
  END a[345]
  PIN a[346]
    DIRECTION INPUT ;
    USE SIGNAL ;
    PORT
      LAYER M4 ;
        RECT  64.692 47.76 64.776 47.784 ;
    END
  END a[346]
  PIN a[347]
    DIRECTION INPUT ;
    USE SIGNAL ;
    PORT
      LAYER M4 ;
        RECT  64.692 47.856 64.776 47.88 ;
    END
  END a[347]
  PIN a[348]
    DIRECTION INPUT ;
    USE SIGNAL ;
    PORT
      LAYER M4 ;
        RECT  64.692 47.952 64.776 47.976 ;
    END
  END a[348]
  PIN a[349]
    DIRECTION INPUT ;
    USE SIGNAL ;
    PORT
      LAYER M4 ;
        RECT  64.692 48.048 64.776 48.072 ;
    END
  END a[349]
  PIN a[34]
    DIRECTION INPUT ;
    USE SIGNAL ;
    PORT
      LAYER M4 ;
        RECT  64.692 23.184 64.776 23.208 ;
    END
  END a[34]
  PIN a[350]
    DIRECTION INPUT ;
    USE SIGNAL ;
    PORT
      LAYER M4 ;
        RECT  64.692 48.144 64.776 48.168 ;
    END
  END a[350]
  PIN a[351]
    DIRECTION INPUT ;
    USE SIGNAL ;
    PORT
      LAYER M4 ;
        RECT  64.692 48.24 64.776 48.264 ;
    END
  END a[351]
  PIN a[352]
    DIRECTION INPUT ;
    USE SIGNAL ;
    PORT
      LAYER M4 ;
        RECT  64.692 51.408 64.776 51.432 ;
    END
  END a[352]
  PIN a[353]
    DIRECTION INPUT ;
    USE SIGNAL ;
    PORT
      LAYER M4 ;
        RECT  64.692 51.504 64.776 51.528 ;
    END
  END a[353]
  PIN a[354]
    DIRECTION INPUT ;
    USE SIGNAL ;
    PORT
      LAYER M4 ;
        RECT  64.692 51.6 64.776 51.624 ;
    END
  END a[354]
  PIN a[355]
    DIRECTION INPUT ;
    USE SIGNAL ;
    PORT
      LAYER M4 ;
        RECT  64.692 51.696 64.776 51.72 ;
    END
  END a[355]
  PIN a[356]
    DIRECTION INPUT ;
    USE SIGNAL ;
    PORT
      LAYER M4 ;
        RECT  64.692 51.792 64.776 51.816 ;
    END
  END a[356]
  PIN a[357]
    DIRECTION INPUT ;
    USE SIGNAL ;
    PORT
      LAYER M4 ;
        RECT  64.692 51.888 64.776 51.912 ;
    END
  END a[357]
  PIN a[358]
    DIRECTION INPUT ;
    USE SIGNAL ;
    PORT
      LAYER M4 ;
        RECT  64.692 51.984 64.776 52.008 ;
    END
  END a[358]
  PIN a[359]
    DIRECTION INPUT ;
    USE SIGNAL ;
    PORT
      LAYER M4 ;
        RECT  64.692 52.08 64.776 52.104 ;
    END
  END a[359]
  PIN a[35]
    DIRECTION INPUT ;
    USE SIGNAL ;
    PORT
      LAYER M4 ;
        RECT  64.692 23.28 64.776 23.304 ;
    END
  END a[35]
  PIN a[360]
    DIRECTION INPUT ;
    USE SIGNAL ;
    PORT
      LAYER M4 ;
        RECT  64.692 52.176 64.776 52.2 ;
    END
  END a[360]
  PIN a[361]
    DIRECTION INPUT ;
    USE SIGNAL ;
    PORT
      LAYER M4 ;
        RECT  64.692 52.272 64.776 52.296 ;
    END
  END a[361]
  PIN a[362]
    DIRECTION INPUT ;
    USE SIGNAL ;
    PORT
      LAYER M4 ;
        RECT  64.692 52.368 64.776 52.392 ;
    END
  END a[362]
  PIN a[363]
    DIRECTION INPUT ;
    USE SIGNAL ;
    PORT
      LAYER M4 ;
        RECT  64.692 52.464 64.776 52.488 ;
    END
  END a[363]
  PIN a[364]
    DIRECTION INPUT ;
    USE SIGNAL ;
    PORT
      LAYER M4 ;
        RECT  64.692 52.56 64.776 52.584 ;
    END
  END a[364]
  PIN a[365]
    DIRECTION INPUT ;
    USE SIGNAL ;
    PORT
      LAYER M4 ;
        RECT  64.692 52.656 64.776 52.68 ;
    END
  END a[365]
  PIN a[366]
    DIRECTION INPUT ;
    USE SIGNAL ;
    PORT
      LAYER M4 ;
        RECT  64.692 52.752 64.776 52.776 ;
    END
  END a[366]
  PIN a[367]
    DIRECTION INPUT ;
    USE SIGNAL ;
    PORT
      LAYER M4 ;
        RECT  64.692 52.848 64.776 52.872 ;
    END
  END a[367]
  PIN a[368]
    DIRECTION INPUT ;
    USE SIGNAL ;
    PORT
      LAYER M4 ;
        RECT  64.692 52.944 64.776 52.968 ;
    END
  END a[368]
  PIN a[369]
    DIRECTION INPUT ;
    USE SIGNAL ;
    PORT
      LAYER M4 ;
        RECT  64.692 53.04 64.776 53.064 ;
    END
  END a[369]
  PIN a[36]
    DIRECTION INPUT ;
    USE SIGNAL ;
    PORT
      LAYER M4 ;
        RECT  64.692 23.376 64.776 23.4 ;
    END
  END a[36]
  PIN a[370]
    DIRECTION INPUT ;
    USE SIGNAL ;
    PORT
      LAYER M4 ;
        RECT  64.692 53.136 64.776 53.16 ;
    END
  END a[370]
  PIN a[371]
    DIRECTION INPUT ;
    USE SIGNAL ;
    PORT
      LAYER M4 ;
        RECT  64.692 53.232 64.776 53.256 ;
    END
  END a[371]
  PIN a[372]
    DIRECTION INPUT ;
    USE SIGNAL ;
    PORT
      LAYER M4 ;
        RECT  64.692 53.328 64.776 53.352 ;
    END
  END a[372]
  PIN a[373]
    DIRECTION INPUT ;
    USE SIGNAL ;
    PORT
      LAYER M4 ;
        RECT  64.692 53.424 64.776 53.448 ;
    END
  END a[373]
  PIN a[374]
    DIRECTION INPUT ;
    USE SIGNAL ;
    PORT
      LAYER M4 ;
        RECT  64.692 53.52 64.776 53.544 ;
    END
  END a[374]
  PIN a[375]
    DIRECTION INPUT ;
    USE SIGNAL ;
    PORT
      LAYER M4 ;
        RECT  64.692 53.616 64.776 53.64 ;
    END
  END a[375]
  PIN a[376]
    DIRECTION INPUT ;
    USE SIGNAL ;
    PORT
      LAYER M4 ;
        RECT  64.692 53.712 64.776 53.736 ;
    END
  END a[376]
  PIN a[377]
    DIRECTION INPUT ;
    USE SIGNAL ;
    PORT
      LAYER M4 ;
        RECT  64.692 53.808 64.776 53.832 ;
    END
  END a[377]
  PIN a[378]
    DIRECTION INPUT ;
    USE SIGNAL ;
    PORT
      LAYER M4 ;
        RECT  64.692 53.904 64.776 53.928 ;
    END
  END a[378]
  PIN a[379]
    DIRECTION INPUT ;
    USE SIGNAL ;
    PORT
      LAYER M4 ;
        RECT  64.692 54 64.776 54.024 ;
    END
  END a[379]
  PIN a[37]
    DIRECTION INPUT ;
    USE SIGNAL ;
    PORT
      LAYER M4 ;
        RECT  64.692 23.472 64.776 23.496 ;
    END
  END a[37]
  PIN a[380]
    DIRECTION INPUT ;
    USE SIGNAL ;
    PORT
      LAYER M4 ;
        RECT  64.692 54.096 64.776 54.12 ;
    END
  END a[380]
  PIN a[381]
    DIRECTION INPUT ;
    USE SIGNAL ;
    PORT
      LAYER M4 ;
        RECT  64.692 54.192 64.776 54.216 ;
    END
  END a[381]
  PIN a[382]
    DIRECTION INPUT ;
    USE SIGNAL ;
    PORT
      LAYER M4 ;
        RECT  64.692 54.288 64.776 54.312 ;
    END
  END a[382]
  PIN a[383]
    DIRECTION INPUT ;
    USE SIGNAL ;
    PORT
      LAYER M4 ;
        RECT  64.692 54.384 64.776 54.408 ;
    END
  END a[383]
  PIN a[384]
    DIRECTION INPUT ;
    USE SIGNAL ;
    PORT
      LAYER M4 ;
        RECT  64.692 48.336 64.776 48.36 ;
    END
  END a[384]
  PIN a[385]
    DIRECTION INPUT ;
    USE SIGNAL ;
    PORT
      LAYER M4 ;
        RECT  64.692 48.432 64.776 48.456 ;
    END
  END a[385]
  PIN a[386]
    DIRECTION INPUT ;
    USE SIGNAL ;
    PORT
      LAYER M4 ;
        RECT  64.692 48.528 64.776 48.552 ;
    END
  END a[386]
  PIN a[387]
    DIRECTION INPUT ;
    USE SIGNAL ;
    PORT
      LAYER M4 ;
        RECT  64.692 48.624 64.776 48.648 ;
    END
  END a[387]
  PIN a[388]
    DIRECTION INPUT ;
    USE SIGNAL ;
    PORT
      LAYER M4 ;
        RECT  64.692 48.72 64.776 48.744 ;
    END
  END a[388]
  PIN a[389]
    DIRECTION INPUT ;
    USE SIGNAL ;
    PORT
      LAYER M4 ;
        RECT  64.692 48.816 64.776 48.84 ;
    END
  END a[389]
  PIN a[38]
    DIRECTION INPUT ;
    USE SIGNAL ;
    PORT
      LAYER M4 ;
        RECT  64.692 23.568 64.776 23.592 ;
    END
  END a[38]
  PIN a[390]
    DIRECTION INPUT ;
    USE SIGNAL ;
    PORT
      LAYER M4 ;
        RECT  64.692 48.912 64.776 48.936 ;
    END
  END a[390]
  PIN a[391]
    DIRECTION INPUT ;
    USE SIGNAL ;
    PORT
      LAYER M4 ;
        RECT  64.692 49.008 64.776 49.032 ;
    END
  END a[391]
  PIN a[392]
    DIRECTION INPUT ;
    USE SIGNAL ;
    PORT
      LAYER M4 ;
        RECT  64.692 49.104 64.776 49.128 ;
    END
  END a[392]
  PIN a[393]
    DIRECTION INPUT ;
    USE SIGNAL ;
    PORT
      LAYER M4 ;
        RECT  64.692 49.2 64.776 49.224 ;
    END
  END a[393]
  PIN a[394]
    DIRECTION INPUT ;
    USE SIGNAL ;
    PORT
      LAYER M4 ;
        RECT  64.692 49.296 64.776 49.32 ;
    END
  END a[394]
  PIN a[395]
    DIRECTION INPUT ;
    USE SIGNAL ;
    PORT
      LAYER M4 ;
        RECT  64.692 49.392 64.776 49.416 ;
    END
  END a[395]
  PIN a[396]
    DIRECTION INPUT ;
    USE SIGNAL ;
    PORT
      LAYER M4 ;
        RECT  64.692 49.488 64.776 49.512 ;
    END
  END a[396]
  PIN a[397]
    DIRECTION INPUT ;
    USE SIGNAL ;
    PORT
      LAYER M4 ;
        RECT  64.692 49.584 64.776 49.608 ;
    END
  END a[397]
  PIN a[398]
    DIRECTION INPUT ;
    USE SIGNAL ;
    PORT
      LAYER M4 ;
        RECT  64.692 49.68 64.776 49.704 ;
    END
  END a[398]
  PIN a[399]
    DIRECTION INPUT ;
    USE SIGNAL ;
    PORT
      LAYER M4 ;
        RECT  64.692 49.776 64.776 49.8 ;
    END
  END a[399]
  PIN a[39]
    DIRECTION INPUT ;
    USE SIGNAL ;
    PORT
      LAYER M4 ;
        RECT  64.692 23.664 64.776 23.688 ;
    END
  END a[39]
  PIN a[3]
    DIRECTION INPUT ;
    USE SIGNAL ;
    PORT
      LAYER M4 ;
        RECT  64.692 35.568 64.776 35.592 ;
    END
  END a[3]
  PIN a[400]
    DIRECTION INPUT ;
    USE SIGNAL ;
    PORT
      LAYER M4 ;
        RECT  64.692 49.872 64.776 49.896 ;
    END
  END a[400]
  PIN a[401]
    DIRECTION INPUT ;
    USE SIGNAL ;
    PORT
      LAYER M4 ;
        RECT  64.692 49.968 64.776 49.992 ;
    END
  END a[401]
  PIN a[402]
    DIRECTION INPUT ;
    USE SIGNAL ;
    PORT
      LAYER M4 ;
        RECT  64.692 50.064 64.776 50.088 ;
    END
  END a[402]
  PIN a[403]
    DIRECTION INPUT ;
    USE SIGNAL ;
    PORT
      LAYER M4 ;
        RECT  64.692 50.16 64.776 50.184 ;
    END
  END a[403]
  PIN a[404]
    DIRECTION INPUT ;
    USE SIGNAL ;
    PORT
      LAYER M4 ;
        RECT  64.692 50.256 64.776 50.28 ;
    END
  END a[404]
  PIN a[405]
    DIRECTION INPUT ;
    USE SIGNAL ;
    PORT
      LAYER M4 ;
        RECT  64.692 50.352 64.776 50.376 ;
    END
  END a[405]
  PIN a[406]
    DIRECTION INPUT ;
    USE SIGNAL ;
    PORT
      LAYER M4 ;
        RECT  64.692 50.448 64.776 50.472 ;
    END
  END a[406]
  PIN a[407]
    DIRECTION INPUT ;
    USE SIGNAL ;
    PORT
      LAYER M4 ;
        RECT  64.692 50.544 64.776 50.568 ;
    END
  END a[407]
  PIN a[408]
    DIRECTION INPUT ;
    USE SIGNAL ;
    PORT
      LAYER M4 ;
        RECT  64.692 50.64 64.776 50.664 ;
    END
  END a[408]
  PIN a[409]
    DIRECTION INPUT ;
    USE SIGNAL ;
    PORT
      LAYER M4 ;
        RECT  64.692 50.736 64.776 50.76 ;
    END
  END a[409]
  PIN a[40]
    DIRECTION INPUT ;
    USE SIGNAL ;
    PORT
      LAYER M4 ;
        RECT  64.692 23.76 64.776 23.784 ;
    END
  END a[40]
  PIN a[410]
    DIRECTION INPUT ;
    USE SIGNAL ;
    PORT
      LAYER M4 ;
        RECT  64.692 50.832 64.776 50.856 ;
    END
  END a[410]
  PIN a[411]
    DIRECTION INPUT ;
    USE SIGNAL ;
    PORT
      LAYER M4 ;
        RECT  64.692 50.928 64.776 50.952 ;
    END
  END a[411]
  PIN a[412]
    DIRECTION INPUT ;
    USE SIGNAL ;
    PORT
      LAYER M4 ;
        RECT  64.692 51.024 64.776 51.048 ;
    END
  END a[412]
  PIN a[413]
    DIRECTION INPUT ;
    USE SIGNAL ;
    PORT
      LAYER M4 ;
        RECT  64.692 51.12 64.776 51.144 ;
    END
  END a[413]
  PIN a[414]
    DIRECTION INPUT ;
    USE SIGNAL ;
    PORT
      LAYER M4 ;
        RECT  64.692 51.216 64.776 51.24 ;
    END
  END a[414]
  PIN a[415]
    DIRECTION INPUT ;
    USE SIGNAL ;
    PORT
      LAYER M4 ;
        RECT  64.692 51.312 64.776 51.336 ;
    END
  END a[415]
  PIN a[416]
    DIRECTION INPUT ;
    USE SIGNAL ;
    PORT
      LAYER M4 ;
        RECT  64.692 9.936 64.776 9.96 ;
    END
  END a[416]
  PIN a[417]
    DIRECTION INPUT ;
    USE SIGNAL ;
    PORT
      LAYER M4 ;
        RECT  64.692 10.032 64.776 10.056 ;
    END
  END a[417]
  PIN a[418]
    DIRECTION INPUT ;
    USE SIGNAL ;
    PORT
      LAYER M4 ;
        RECT  64.692 10.128 64.776 10.152 ;
    END
  END a[418]
  PIN a[419]
    DIRECTION INPUT ;
    USE SIGNAL ;
    PORT
      LAYER M4 ;
        RECT  64.692 10.224 64.776 10.248 ;
    END
  END a[419]
  PIN a[41]
    DIRECTION INPUT ;
    USE SIGNAL ;
    PORT
      LAYER M4 ;
        RECT  64.692 23.856 64.776 23.88 ;
    END
  END a[41]
  PIN a[420]
    DIRECTION INPUT ;
    USE SIGNAL ;
    PORT
      LAYER M4 ;
        RECT  64.692 10.32 64.776 10.344 ;
    END
  END a[420]
  PIN a[421]
    DIRECTION INPUT ;
    USE SIGNAL ;
    PORT
      LAYER M4 ;
        RECT  64.692 10.416 64.776 10.44 ;
    END
  END a[421]
  PIN a[422]
    DIRECTION INPUT ;
    USE SIGNAL ;
    PORT
      LAYER M4 ;
        RECT  64.692 10.512 64.776 10.536 ;
    END
  END a[422]
  PIN a[423]
    DIRECTION INPUT ;
    USE SIGNAL ;
    PORT
      LAYER M4 ;
        RECT  64.692 10.608 64.776 10.632 ;
    END
  END a[423]
  PIN a[424]
    DIRECTION INPUT ;
    USE SIGNAL ;
    PORT
      LAYER M4 ;
        RECT  64.692 10.704 64.776 10.728 ;
    END
  END a[424]
  PIN a[425]
    DIRECTION INPUT ;
    USE SIGNAL ;
    PORT
      LAYER M4 ;
        RECT  64.692 10.8 64.776 10.824 ;
    END
  END a[425]
  PIN a[426]
    DIRECTION INPUT ;
    USE SIGNAL ;
    PORT
      LAYER M4 ;
        RECT  64.692 10.896 64.776 10.92 ;
    END
  END a[426]
  PIN a[427]
    DIRECTION INPUT ;
    USE SIGNAL ;
    PORT
      LAYER M4 ;
        RECT  64.692 10.992 64.776 11.016 ;
    END
  END a[427]
  PIN a[428]
    DIRECTION INPUT ;
    USE SIGNAL ;
    PORT
      LAYER M4 ;
        RECT  64.692 11.088 64.776 11.112 ;
    END
  END a[428]
  PIN a[429]
    DIRECTION INPUT ;
    USE SIGNAL ;
    PORT
      LAYER M4 ;
        RECT  64.692 11.184 64.776 11.208 ;
    END
  END a[429]
  PIN a[42]
    DIRECTION INPUT ;
    USE SIGNAL ;
    PORT
      LAYER M4 ;
        RECT  64.692 23.952 64.776 23.976 ;
    END
  END a[42]
  PIN a[430]
    DIRECTION INPUT ;
    USE SIGNAL ;
    PORT
      LAYER M4 ;
        RECT  64.692 11.28 64.776 11.304 ;
    END
  END a[430]
  PIN a[431]
    DIRECTION INPUT ;
    USE SIGNAL ;
    PORT
      LAYER M4 ;
        RECT  64.692 11.376 64.776 11.4 ;
    END
  END a[431]
  PIN a[432]
    DIRECTION INPUT ;
    USE SIGNAL ;
    PORT
      LAYER M4 ;
        RECT  64.692 11.472 64.776 11.496 ;
    END
  END a[432]
  PIN a[433]
    DIRECTION INPUT ;
    USE SIGNAL ;
    PORT
      LAYER M4 ;
        RECT  64.692 11.568 64.776 11.592 ;
    END
  END a[433]
  PIN a[434]
    DIRECTION INPUT ;
    USE SIGNAL ;
    PORT
      LAYER M4 ;
        RECT  64.692 11.664 64.776 11.688 ;
    END
  END a[434]
  PIN a[435]
    DIRECTION INPUT ;
    USE SIGNAL ;
    PORT
      LAYER M4 ;
        RECT  64.692 11.76 64.776 11.784 ;
    END
  END a[435]
  PIN a[436]
    DIRECTION INPUT ;
    USE SIGNAL ;
    PORT
      LAYER M4 ;
        RECT  64.692 11.856 64.776 11.88 ;
    END
  END a[436]
  PIN a[437]
    DIRECTION INPUT ;
    USE SIGNAL ;
    PORT
      LAYER M4 ;
        RECT  64.692 11.952 64.776 11.976 ;
    END
  END a[437]
  PIN a[438]
    DIRECTION INPUT ;
    USE SIGNAL ;
    PORT
      LAYER M4 ;
        RECT  64.692 12.048 64.776 12.072 ;
    END
  END a[438]
  PIN a[439]
    DIRECTION INPUT ;
    USE SIGNAL ;
    PORT
      LAYER M4 ;
        RECT  64.692 12.144 64.776 12.168 ;
    END
  END a[439]
  PIN a[43]
    DIRECTION INPUT ;
    USE SIGNAL ;
    PORT
      LAYER M4 ;
        RECT  64.692 24.048 64.776 24.072 ;
    END
  END a[43]
  PIN a[440]
    DIRECTION INPUT ;
    USE SIGNAL ;
    PORT
      LAYER M4 ;
        RECT  64.692 12.24 64.776 12.264 ;
    END
  END a[440]
  PIN a[441]
    DIRECTION INPUT ;
    USE SIGNAL ;
    PORT
      LAYER M4 ;
        RECT  64.692 12.336 64.776 12.36 ;
    END
  END a[441]
  PIN a[442]
    DIRECTION INPUT ;
    USE SIGNAL ;
    PORT
      LAYER M4 ;
        RECT  64.692 12.432 64.776 12.456 ;
    END
  END a[442]
  PIN a[443]
    DIRECTION INPUT ;
    USE SIGNAL ;
    PORT
      LAYER M4 ;
        RECT  64.692 12.528 64.776 12.552 ;
    END
  END a[443]
  PIN a[444]
    DIRECTION INPUT ;
    USE SIGNAL ;
    PORT
      LAYER M4 ;
        RECT  64.692 12.624 64.776 12.648 ;
    END
  END a[444]
  PIN a[445]
    DIRECTION INPUT ;
    USE SIGNAL ;
    PORT
      LAYER M4 ;
        RECT  64.692 12.72 64.776 12.744 ;
    END
  END a[445]
  PIN a[446]
    DIRECTION INPUT ;
    USE SIGNAL ;
    PORT
      LAYER M4 ;
        RECT  64.692 12.816 64.776 12.84 ;
    END
  END a[446]
  PIN a[447]
    DIRECTION INPUT ;
    USE SIGNAL ;
    PORT
      LAYER M4 ;
        RECT  64.692 12.912 64.776 12.936 ;
    END
  END a[447]
  PIN a[448]
    DIRECTION INPUT ;
    USE SIGNAL ;
    PORT
      LAYER M4 ;
        RECT  64.692 16.08 64.776 16.104 ;
    END
  END a[448]
  PIN a[449]
    DIRECTION INPUT ;
    USE SIGNAL ;
    PORT
      LAYER M4 ;
        RECT  64.692 16.176 64.776 16.2 ;
    END
  END a[449]
  PIN a[44]
    DIRECTION INPUT ;
    USE SIGNAL ;
    PORT
      LAYER M4 ;
        RECT  64.692 24.144 64.776 24.168 ;
    END
  END a[44]
  PIN a[450]
    DIRECTION INPUT ;
    USE SIGNAL ;
    PORT
      LAYER M4 ;
        RECT  64.692 16.272 64.776 16.296 ;
    END
  END a[450]
  PIN a[451]
    DIRECTION INPUT ;
    USE SIGNAL ;
    PORT
      LAYER M4 ;
        RECT  64.692 16.368 64.776 16.392 ;
    END
  END a[451]
  PIN a[452]
    DIRECTION INPUT ;
    USE SIGNAL ;
    PORT
      LAYER M4 ;
        RECT  64.692 16.464 64.776 16.488 ;
    END
  END a[452]
  PIN a[453]
    DIRECTION INPUT ;
    USE SIGNAL ;
    PORT
      LAYER M4 ;
        RECT  64.692 16.56 64.776 16.584 ;
    END
  END a[453]
  PIN a[454]
    DIRECTION INPUT ;
    USE SIGNAL ;
    PORT
      LAYER M4 ;
        RECT  64.692 16.656 64.776 16.68 ;
    END
  END a[454]
  PIN a[455]
    DIRECTION INPUT ;
    USE SIGNAL ;
    PORT
      LAYER M4 ;
        RECT  64.692 16.752 64.776 16.776 ;
    END
  END a[455]
  PIN a[456]
    DIRECTION INPUT ;
    USE SIGNAL ;
    PORT
      LAYER M4 ;
        RECT  64.692 16.848 64.776 16.872 ;
    END
  END a[456]
  PIN a[457]
    DIRECTION INPUT ;
    USE SIGNAL ;
    PORT
      LAYER M4 ;
        RECT  64.692 16.944 64.776 16.968 ;
    END
  END a[457]
  PIN a[458]
    DIRECTION INPUT ;
    USE SIGNAL ;
    PORT
      LAYER M4 ;
        RECT  64.692 17.04 64.776 17.064 ;
    END
  END a[458]
  PIN a[459]
    DIRECTION INPUT ;
    USE SIGNAL ;
    PORT
      LAYER M4 ;
        RECT  64.692 17.136 64.776 17.16 ;
    END
  END a[459]
  PIN a[45]
    DIRECTION INPUT ;
    USE SIGNAL ;
    PORT
      LAYER M4 ;
        RECT  64.692 24.24 64.776 24.264 ;
    END
  END a[45]
  PIN a[460]
    DIRECTION INPUT ;
    USE SIGNAL ;
    PORT
      LAYER M4 ;
        RECT  64.692 17.232 64.776 17.256 ;
    END
  END a[460]
  PIN a[461]
    DIRECTION INPUT ;
    USE SIGNAL ;
    PORT
      LAYER M4 ;
        RECT  64.692 17.328 64.776 17.352 ;
    END
  END a[461]
  PIN a[462]
    DIRECTION INPUT ;
    USE SIGNAL ;
    PORT
      LAYER M4 ;
        RECT  64.692 17.424 64.776 17.448 ;
    END
  END a[462]
  PIN a[463]
    DIRECTION INPUT ;
    USE SIGNAL ;
    PORT
      LAYER M4 ;
        RECT  64.692 17.52 64.776 17.544 ;
    END
  END a[463]
  PIN a[464]
    DIRECTION INPUT ;
    USE SIGNAL ;
    PORT
      LAYER M4 ;
        RECT  64.692 17.616 64.776 17.64 ;
    END
  END a[464]
  PIN a[465]
    DIRECTION INPUT ;
    USE SIGNAL ;
    PORT
      LAYER M4 ;
        RECT  64.692 17.712 64.776 17.736 ;
    END
  END a[465]
  PIN a[466]
    DIRECTION INPUT ;
    USE SIGNAL ;
    PORT
      LAYER M4 ;
        RECT  64.692 17.808 64.776 17.832 ;
    END
  END a[466]
  PIN a[467]
    DIRECTION INPUT ;
    USE SIGNAL ;
    PORT
      LAYER M4 ;
        RECT  64.692 17.904 64.776 17.928 ;
    END
  END a[467]
  PIN a[468]
    DIRECTION INPUT ;
    USE SIGNAL ;
    PORT
      LAYER M4 ;
        RECT  64.692 18 64.776 18.024 ;
    END
  END a[468]
  PIN a[469]
    DIRECTION INPUT ;
    USE SIGNAL ;
    PORT
      LAYER M4 ;
        RECT  64.692 18.096 64.776 18.12 ;
    END
  END a[469]
  PIN a[46]
    DIRECTION INPUT ;
    USE SIGNAL ;
    PORT
      LAYER M4 ;
        RECT  64.692 24.336 64.776 24.36 ;
    END
  END a[46]
  PIN a[470]
    DIRECTION INPUT ;
    USE SIGNAL ;
    PORT
      LAYER M4 ;
        RECT  64.692 18.192 64.776 18.216 ;
    END
  END a[470]
  PIN a[471]
    DIRECTION INPUT ;
    USE SIGNAL ;
    PORT
      LAYER M4 ;
        RECT  64.692 18.288 64.776 18.312 ;
    END
  END a[471]
  PIN a[472]
    DIRECTION INPUT ;
    USE SIGNAL ;
    PORT
      LAYER M4 ;
        RECT  64.692 18.384 64.776 18.408 ;
    END
  END a[472]
  PIN a[473]
    DIRECTION INPUT ;
    USE SIGNAL ;
    PORT
      LAYER M4 ;
        RECT  64.692 18.48 64.776 18.504 ;
    END
  END a[473]
  PIN a[474]
    DIRECTION INPUT ;
    USE SIGNAL ;
    PORT
      LAYER M4 ;
        RECT  64.692 18.576 64.776 18.6 ;
    END
  END a[474]
  PIN a[475]
    DIRECTION INPUT ;
    USE SIGNAL ;
    PORT
      LAYER M4 ;
        RECT  64.692 18.672 64.776 18.696 ;
    END
  END a[475]
  PIN a[476]
    DIRECTION INPUT ;
    USE SIGNAL ;
    PORT
      LAYER M4 ;
        RECT  64.692 18.768 64.776 18.792 ;
    END
  END a[476]
  PIN a[477]
    DIRECTION INPUT ;
    USE SIGNAL ;
    PORT
      LAYER M4 ;
        RECT  64.692 18.864 64.776 18.888 ;
    END
  END a[477]
  PIN a[478]
    DIRECTION INPUT ;
    USE SIGNAL ;
    PORT
      LAYER M4 ;
        RECT  64.692 18.96 64.776 18.984 ;
    END
  END a[478]
  PIN a[479]
    DIRECTION INPUT ;
    USE SIGNAL ;
    PORT
      LAYER M4 ;
        RECT  64.692 19.056 64.776 19.08 ;
    END
  END a[479]
  PIN a[47]
    DIRECTION INPUT ;
    USE SIGNAL ;
    PORT
      LAYER M4 ;
        RECT  64.692 24.432 64.776 24.456 ;
    END
  END a[47]
  PIN a[480]
    DIRECTION INPUT ;
    USE SIGNAL ;
    PORT
      LAYER M4 ;
        RECT  64.692 13.008 64.776 13.032 ;
    END
  END a[480]
  PIN a[481]
    DIRECTION INPUT ;
    USE SIGNAL ;
    PORT
      LAYER M4 ;
        RECT  64.692 13.104 64.776 13.128 ;
    END
  END a[481]
  PIN a[482]
    DIRECTION INPUT ;
    USE SIGNAL ;
    PORT
      LAYER M4 ;
        RECT  64.692 13.2 64.776 13.224 ;
    END
  END a[482]
  PIN a[483]
    DIRECTION INPUT ;
    USE SIGNAL ;
    PORT
      LAYER M4 ;
        RECT  64.692 13.296 64.776 13.32 ;
    END
  END a[483]
  PIN a[484]
    DIRECTION INPUT ;
    USE SIGNAL ;
    PORT
      LAYER M4 ;
        RECT  64.692 13.392 64.776 13.416 ;
    END
  END a[484]
  PIN a[485]
    DIRECTION INPUT ;
    USE SIGNAL ;
    PORT
      LAYER M4 ;
        RECT  64.692 13.488 64.776 13.512 ;
    END
  END a[485]
  PIN a[486]
    DIRECTION INPUT ;
    USE SIGNAL ;
    PORT
      LAYER M4 ;
        RECT  64.692 13.584 64.776 13.608 ;
    END
  END a[486]
  PIN a[487]
    DIRECTION INPUT ;
    USE SIGNAL ;
    PORT
      LAYER M4 ;
        RECT  64.692 13.68 64.776 13.704 ;
    END
  END a[487]
  PIN a[488]
    DIRECTION INPUT ;
    USE SIGNAL ;
    PORT
      LAYER M4 ;
        RECT  64.692 13.776 64.776 13.8 ;
    END
  END a[488]
  PIN a[489]
    DIRECTION INPUT ;
    USE SIGNAL ;
    PORT
      LAYER M4 ;
        RECT  64.692 13.872 64.776 13.896 ;
    END
  END a[489]
  PIN a[48]
    DIRECTION INPUT ;
    USE SIGNAL ;
    PORT
      LAYER M4 ;
        RECT  64.692 24.528 64.776 24.552 ;
    END
  END a[48]
  PIN a[490]
    DIRECTION INPUT ;
    USE SIGNAL ;
    PORT
      LAYER M4 ;
        RECT  64.692 13.968 64.776 13.992 ;
    END
  END a[490]
  PIN a[491]
    DIRECTION INPUT ;
    USE SIGNAL ;
    PORT
      LAYER M4 ;
        RECT  64.692 14.064 64.776 14.088 ;
    END
  END a[491]
  PIN a[492]
    DIRECTION INPUT ;
    USE SIGNAL ;
    PORT
      LAYER M4 ;
        RECT  64.692 14.16 64.776 14.184 ;
    END
  END a[492]
  PIN a[493]
    DIRECTION INPUT ;
    USE SIGNAL ;
    PORT
      LAYER M4 ;
        RECT  64.692 14.256 64.776 14.28 ;
    END
  END a[493]
  PIN a[494]
    DIRECTION INPUT ;
    USE SIGNAL ;
    PORT
      LAYER M4 ;
        RECT  64.692 14.352 64.776 14.376 ;
    END
  END a[494]
  PIN a[495]
    DIRECTION INPUT ;
    USE SIGNAL ;
    PORT
      LAYER M4 ;
        RECT  64.692 14.448 64.776 14.472 ;
    END
  END a[495]
  PIN a[496]
    DIRECTION INPUT ;
    USE SIGNAL ;
    PORT
      LAYER M4 ;
        RECT  64.692 14.544 64.776 14.568 ;
    END
  END a[496]
  PIN a[497]
    DIRECTION INPUT ;
    USE SIGNAL ;
    PORT
      LAYER M4 ;
        RECT  64.692 14.64 64.776 14.664 ;
    END
  END a[497]
  PIN a[498]
    DIRECTION INPUT ;
    USE SIGNAL ;
    PORT
      LAYER M4 ;
        RECT  64.692 14.736 64.776 14.76 ;
    END
  END a[498]
  PIN a[499]
    DIRECTION INPUT ;
    USE SIGNAL ;
    PORT
      LAYER M4 ;
        RECT  64.692 14.832 64.776 14.856 ;
    END
  END a[499]
  PIN a[49]
    DIRECTION INPUT ;
    USE SIGNAL ;
    PORT
      LAYER M4 ;
        RECT  64.692 24.624 64.776 24.648 ;
    END
  END a[49]
  PIN a[4]
    DIRECTION INPUT ;
    USE SIGNAL ;
    PORT
      LAYER M4 ;
        RECT  64.692 35.664 64.776 35.688 ;
    END
  END a[4]
  PIN a[500]
    DIRECTION INPUT ;
    USE SIGNAL ;
    PORT
      LAYER M4 ;
        RECT  64.692 14.928 64.776 14.952 ;
    END
  END a[500]
  PIN a[501]
    DIRECTION INPUT ;
    USE SIGNAL ;
    PORT
      LAYER M4 ;
        RECT  64.692 15.024 64.776 15.048 ;
    END
  END a[501]
  PIN a[502]
    DIRECTION INPUT ;
    USE SIGNAL ;
    PORT
      LAYER M4 ;
        RECT  64.692 15.12 64.776 15.144 ;
    END
  END a[502]
  PIN a[503]
    DIRECTION INPUT ;
    USE SIGNAL ;
    PORT
      LAYER M4 ;
        RECT  64.692 15.216 64.776 15.24 ;
    END
  END a[503]
  PIN a[504]
    DIRECTION INPUT ;
    USE SIGNAL ;
    PORT
      LAYER M4 ;
        RECT  64.692 15.312 64.776 15.336 ;
    END
  END a[504]
  PIN a[505]
    DIRECTION INPUT ;
    USE SIGNAL ;
    PORT
      LAYER M4 ;
        RECT  64.692 15.408 64.776 15.432 ;
    END
  END a[505]
  PIN a[506]
    DIRECTION INPUT ;
    USE SIGNAL ;
    PORT
      LAYER M4 ;
        RECT  64.692 15.504 64.776 15.528 ;
    END
  END a[506]
  PIN a[507]
    DIRECTION INPUT ;
    USE SIGNAL ;
    PORT
      LAYER M4 ;
        RECT  64.692 15.6 64.776 15.624 ;
    END
  END a[507]
  PIN a[508]
    DIRECTION INPUT ;
    USE SIGNAL ;
    PORT
      LAYER M4 ;
        RECT  64.692 15.696 64.776 15.72 ;
    END
  END a[508]
  PIN a[509]
    DIRECTION INPUT ;
    USE SIGNAL ;
    PORT
      LAYER M4 ;
        RECT  64.692 15.792 64.776 15.816 ;
    END
  END a[509]
  PIN a[50]
    DIRECTION INPUT ;
    USE SIGNAL ;
    PORT
      LAYER M4 ;
        RECT  64.692 24.72 64.776 24.744 ;
    END
  END a[50]
  PIN a[510]
    DIRECTION INPUT ;
    USE SIGNAL ;
    PORT
      LAYER M4 ;
        RECT  64.692 15.888 64.776 15.912 ;
    END
  END a[510]
  PIN a[511]
    DIRECTION INPUT ;
    USE SIGNAL ;
    PORT
      LAYER M4 ;
        RECT  64.692 15.984 64.776 16.008 ;
    END
  END a[511]
  PIN a[512]
    DIRECTION INPUT ;
    USE SIGNAL ;
    PORT
      LAYER M4 ;
        RECT  64.692 3.792 64.776 3.816 ;
    END
  END a[512]
  PIN a[513]
    DIRECTION INPUT ;
    USE SIGNAL ;
    PORT
      LAYER M4 ;
        RECT  64.692 3.888 64.776 3.912 ;
    END
  END a[513]
  PIN a[514]
    DIRECTION INPUT ;
    USE SIGNAL ;
    PORT
      LAYER M4 ;
        RECT  64.692 3.984 64.776 4.008 ;
    END
  END a[514]
  PIN a[515]
    DIRECTION INPUT ;
    USE SIGNAL ;
    PORT
      LAYER M4 ;
        RECT  64.692 4.08 64.776 4.104 ;
    END
  END a[515]
  PIN a[516]
    DIRECTION INPUT ;
    USE SIGNAL ;
    PORT
      LAYER M4 ;
        RECT  64.692 4.176 64.776 4.2 ;
    END
  END a[516]
  PIN a[517]
    DIRECTION INPUT ;
    USE SIGNAL ;
    PORT
      LAYER M4 ;
        RECT  64.692 4.272 64.776 4.296 ;
    END
  END a[517]
  PIN a[518]
    DIRECTION INPUT ;
    USE SIGNAL ;
    PORT
      LAYER M4 ;
        RECT  64.692 4.368 64.776 4.392 ;
    END
  END a[518]
  PIN a[519]
    DIRECTION INPUT ;
    USE SIGNAL ;
    PORT
      LAYER M4 ;
        RECT  64.692 4.464 64.776 4.488 ;
    END
  END a[519]
  PIN a[51]
    DIRECTION INPUT ;
    USE SIGNAL ;
    PORT
      LAYER M4 ;
        RECT  64.692 24.816 64.776 24.84 ;
    END
  END a[51]
  PIN a[520]
    DIRECTION INPUT ;
    USE SIGNAL ;
    PORT
      LAYER M4 ;
        RECT  64.692 4.56 64.776 4.584 ;
    END
  END a[520]
  PIN a[521]
    DIRECTION INPUT ;
    USE SIGNAL ;
    PORT
      LAYER M4 ;
        RECT  64.692 4.656 64.776 4.68 ;
    END
  END a[521]
  PIN a[522]
    DIRECTION INPUT ;
    USE SIGNAL ;
    PORT
      LAYER M4 ;
        RECT  64.692 4.752 64.776 4.776 ;
    END
  END a[522]
  PIN a[523]
    DIRECTION INPUT ;
    USE SIGNAL ;
    PORT
      LAYER M4 ;
        RECT  64.692 4.848 64.776 4.872 ;
    END
  END a[523]
  PIN a[524]
    DIRECTION INPUT ;
    USE SIGNAL ;
    PORT
      LAYER M4 ;
        RECT  64.692 4.944 64.776 4.968 ;
    END
  END a[524]
  PIN a[525]
    DIRECTION INPUT ;
    USE SIGNAL ;
    PORT
      LAYER M4 ;
        RECT  64.692 5.04 64.776 5.064 ;
    END
  END a[525]
  PIN a[526]
    DIRECTION INPUT ;
    USE SIGNAL ;
    PORT
      LAYER M4 ;
        RECT  64.692 5.136 64.776 5.16 ;
    END
  END a[526]
  PIN a[527]
    DIRECTION INPUT ;
    USE SIGNAL ;
    PORT
      LAYER M4 ;
        RECT  64.692 5.232 64.776 5.256 ;
    END
  END a[527]
  PIN a[528]
    DIRECTION INPUT ;
    USE SIGNAL ;
    PORT
      LAYER M4 ;
        RECT  64.692 5.328 64.776 5.352 ;
    END
  END a[528]
  PIN a[529]
    DIRECTION INPUT ;
    USE SIGNAL ;
    PORT
      LAYER M4 ;
        RECT  64.692 5.424 64.776 5.448 ;
    END
  END a[529]
  PIN a[52]
    DIRECTION INPUT ;
    USE SIGNAL ;
    PORT
      LAYER M4 ;
        RECT  64.692 24.912 64.776 24.936 ;
    END
  END a[52]
  PIN a[530]
    DIRECTION INPUT ;
    USE SIGNAL ;
    PORT
      LAYER M4 ;
        RECT  64.692 5.52 64.776 5.544 ;
    END
  END a[530]
  PIN a[531]
    DIRECTION INPUT ;
    USE SIGNAL ;
    PORT
      LAYER M4 ;
        RECT  64.692 5.616 64.776 5.64 ;
    END
  END a[531]
  PIN a[532]
    DIRECTION INPUT ;
    USE SIGNAL ;
    PORT
      LAYER M4 ;
        RECT  64.692 5.712 64.776 5.736 ;
    END
  END a[532]
  PIN a[533]
    DIRECTION INPUT ;
    USE SIGNAL ;
    PORT
      LAYER M4 ;
        RECT  64.692 5.808 64.776 5.832 ;
    END
  END a[533]
  PIN a[534]
    DIRECTION INPUT ;
    USE SIGNAL ;
    PORT
      LAYER M4 ;
        RECT  64.692 5.904 64.776 5.928 ;
    END
  END a[534]
  PIN a[535]
    DIRECTION INPUT ;
    USE SIGNAL ;
    PORT
      LAYER M4 ;
        RECT  64.692 6 64.776 6.024 ;
    END
  END a[535]
  PIN a[536]
    DIRECTION INPUT ;
    USE SIGNAL ;
    PORT
      LAYER M4 ;
        RECT  64.692 6.096 64.776 6.12 ;
    END
  END a[536]
  PIN a[537]
    DIRECTION INPUT ;
    USE SIGNAL ;
    PORT
      LAYER M4 ;
        RECT  64.692 6.192 64.776 6.216 ;
    END
  END a[537]
  PIN a[538]
    DIRECTION INPUT ;
    USE SIGNAL ;
    PORT
      LAYER M4 ;
        RECT  64.692 6.288 64.776 6.312 ;
    END
  END a[538]
  PIN a[539]
    DIRECTION INPUT ;
    USE SIGNAL ;
    PORT
      LAYER M4 ;
        RECT  64.692 6.384 64.776 6.408 ;
    END
  END a[539]
  PIN a[53]
    DIRECTION INPUT ;
    USE SIGNAL ;
    PORT
      LAYER M4 ;
        RECT  64.692 25.008 64.776 25.032 ;
    END
  END a[53]
  PIN a[540]
    DIRECTION INPUT ;
    USE SIGNAL ;
    PORT
      LAYER M4 ;
        RECT  64.692 6.48 64.776 6.504 ;
    END
  END a[540]
  PIN a[541]
    DIRECTION INPUT ;
    USE SIGNAL ;
    PORT
      LAYER M4 ;
        RECT  64.692 6.576 64.776 6.6 ;
    END
  END a[541]
  PIN a[542]
    DIRECTION INPUT ;
    USE SIGNAL ;
    PORT
      LAYER M4 ;
        RECT  64.692 6.672 64.776 6.696 ;
    END
  END a[542]
  PIN a[543]
    DIRECTION INPUT ;
    USE SIGNAL ;
    PORT
      LAYER M4 ;
        RECT  64.692 6.768 64.776 6.792 ;
    END
  END a[543]
  PIN a[544]
    DIRECTION INPUT ;
    USE SIGNAL ;
    PORT
      LAYER M4 ;
        RECT  64.692 38.352 64.776 38.376 ;
    END
  END a[544]
  PIN a[545]
    DIRECTION INPUT ;
    USE SIGNAL ;
    PORT
      LAYER M4 ;
        RECT  64.692 38.448 64.776 38.472 ;
    END
  END a[545]
  PIN a[546]
    DIRECTION INPUT ;
    USE SIGNAL ;
    PORT
      LAYER M4 ;
        RECT  64.692 38.544 64.776 38.568 ;
    END
  END a[546]
  PIN a[547]
    DIRECTION INPUT ;
    USE SIGNAL ;
    PORT
      LAYER M4 ;
        RECT  64.692 38.64 64.776 38.664 ;
    END
  END a[547]
  PIN a[54]
    DIRECTION INPUT ;
    USE SIGNAL ;
    PORT
      LAYER M4 ;
        RECT  64.692 25.104 64.776 25.128 ;
    END
  END a[54]
  PIN a[55]
    DIRECTION INPUT ;
    USE SIGNAL ;
    PORT
      LAYER M4 ;
        RECT  64.692 25.2 64.776 25.224 ;
    END
  END a[55]
  PIN a[56]
    DIRECTION INPUT ;
    USE SIGNAL ;
    PORT
      LAYER M4 ;
        RECT  64.692 25.296 64.776 25.32 ;
    END
  END a[56]
  PIN a[57]
    DIRECTION INPUT ;
    USE SIGNAL ;
    PORT
      LAYER M4 ;
        RECT  64.692 25.392 64.776 25.416 ;
    END
  END a[57]
  PIN a[58]
    DIRECTION INPUT ;
    USE SIGNAL ;
    PORT
      LAYER M4 ;
        RECT  64.692 25.488 64.776 25.512 ;
    END
  END a[58]
  PIN a[59]
    DIRECTION INPUT ;
    USE SIGNAL ;
    PORT
      LAYER M4 ;
        RECT  64.692 25.584 64.776 25.608 ;
    END
  END a[59]
  PIN a[5]
    DIRECTION INPUT ;
    USE SIGNAL ;
    PORT
      LAYER M4 ;
        RECT  64.692 35.76 64.776 35.784 ;
    END
  END a[5]
  PIN a[60]
    DIRECTION INPUT ;
    USE SIGNAL ;
    PORT
      LAYER M4 ;
        RECT  64.692 25.68 64.776 25.704 ;
    END
  END a[60]
  PIN a[61]
    DIRECTION INPUT ;
    USE SIGNAL ;
    PORT
      LAYER M4 ;
        RECT  64.692 25.776 64.776 25.8 ;
    END
  END a[61]
  PIN a[62]
    DIRECTION INPUT ;
    USE SIGNAL ;
    PORT
      LAYER M4 ;
        RECT  64.692 25.872 64.776 25.896 ;
    END
  END a[62]
  PIN a[63]
    DIRECTION INPUT ;
    USE SIGNAL ;
    PORT
      LAYER M4 ;
        RECT  64.692 25.968 64.776 25.992 ;
    END
  END a[63]
  PIN a[64]
    DIRECTION INPUT ;
    USE SIGNAL ;
    PORT
      LAYER M4 ;
        RECT  64.692 26.064 64.776 26.088 ;
    END
  END a[64]
  PIN a[65]
    DIRECTION INPUT ;
    USE SIGNAL ;
    PORT
      LAYER M4 ;
        RECT  64.692 26.16 64.776 26.184 ;
    END
  END a[65]
  PIN a[66]
    DIRECTION INPUT ;
    USE SIGNAL ;
    PORT
      LAYER M4 ;
        RECT  64.692 26.256 64.776 26.28 ;
    END
  END a[66]
  PIN a[67]
    DIRECTION INPUT ;
    USE SIGNAL ;
    PORT
      LAYER M4 ;
        RECT  64.692 26.352 64.776 26.376 ;
    END
  END a[67]
  PIN a[68]
    DIRECTION INPUT ;
    USE SIGNAL ;
    PORT
      LAYER M4 ;
        RECT  64.692 26.448 64.776 26.472 ;
    END
  END a[68]
  PIN a[69]
    DIRECTION INPUT ;
    USE SIGNAL ;
    PORT
      LAYER M4 ;
        RECT  64.692 26.544 64.776 26.568 ;
    END
  END a[69]
  PIN a[6]
    DIRECTION INPUT ;
    USE SIGNAL ;
    PORT
      LAYER M4 ;
        RECT  64.692 35.856 64.776 35.88 ;
    END
  END a[6]
  PIN a[70]
    DIRECTION INPUT ;
    USE SIGNAL ;
    PORT
      LAYER M4 ;
        RECT  64.692 26.64 64.776 26.664 ;
    END
  END a[70]
  PIN a[71]
    DIRECTION INPUT ;
    USE SIGNAL ;
    PORT
      LAYER M4 ;
        RECT  64.692 26.736 64.776 26.76 ;
    END
  END a[71]
  PIN a[72]
    DIRECTION INPUT ;
    USE SIGNAL ;
    PORT
      LAYER M4 ;
        RECT  64.692 26.832 64.776 26.856 ;
    END
  END a[72]
  PIN a[73]
    DIRECTION INPUT ;
    USE SIGNAL ;
    PORT
      LAYER M4 ;
        RECT  64.692 26.928 64.776 26.952 ;
    END
  END a[73]
  PIN a[74]
    DIRECTION INPUT ;
    USE SIGNAL ;
    PORT
      LAYER M4 ;
        RECT  64.692 27.024 64.776 27.048 ;
    END
  END a[74]
  PIN a[75]
    DIRECTION INPUT ;
    USE SIGNAL ;
    PORT
      LAYER M4 ;
        RECT  64.692 27.12 64.776 27.144 ;
    END
  END a[75]
  PIN a[76]
    DIRECTION INPUT ;
    USE SIGNAL ;
    PORT
      LAYER M4 ;
        RECT  64.692 27.216 64.776 27.24 ;
    END
  END a[76]
  PIN a[77]
    DIRECTION INPUT ;
    USE SIGNAL ;
    PORT
      LAYER M4 ;
        RECT  64.692 27.312 64.776 27.336 ;
    END
  END a[77]
  PIN a[78]
    DIRECTION INPUT ;
    USE SIGNAL ;
    PORT
      LAYER M4 ;
        RECT  64.692 27.408 64.776 27.432 ;
    END
  END a[78]
  PIN a[79]
    DIRECTION INPUT ;
    USE SIGNAL ;
    PORT
      LAYER M4 ;
        RECT  64.692 27.504 64.776 27.528 ;
    END
  END a[79]
  PIN a[7]
    DIRECTION INPUT ;
    USE SIGNAL ;
    PORT
      LAYER M4 ;
        RECT  64.692 35.952 64.776 35.976 ;
    END
  END a[7]
  PIN a[80]
    DIRECTION INPUT ;
    USE SIGNAL ;
    PORT
      LAYER M4 ;
        RECT  64.692 27.6 64.776 27.624 ;
    END
  END a[80]
  PIN a[81]
    DIRECTION INPUT ;
    USE SIGNAL ;
    PORT
      LAYER M4 ;
        RECT  64.692 27.696 64.776 27.72 ;
    END
  END a[81]
  PIN a[82]
    DIRECTION INPUT ;
    USE SIGNAL ;
    PORT
      LAYER M4 ;
        RECT  64.692 27.792 64.776 27.816 ;
    END
  END a[82]
  PIN a[83]
    DIRECTION INPUT ;
    USE SIGNAL ;
    PORT
      LAYER M4 ;
        RECT  64.692 27.888 64.776 27.912 ;
    END
  END a[83]
  PIN a[84]
    DIRECTION INPUT ;
    USE SIGNAL ;
    PORT
      LAYER M4 ;
        RECT  64.692 27.984 64.776 28.008 ;
    END
  END a[84]
  PIN a[85]
    DIRECTION INPUT ;
    USE SIGNAL ;
    PORT
      LAYER M4 ;
        RECT  64.692 28.08 64.776 28.104 ;
    END
  END a[85]
  PIN a[86]
    DIRECTION INPUT ;
    USE SIGNAL ;
    PORT
      LAYER M4 ;
        RECT  64.692 28.176 64.776 28.2 ;
    END
  END a[86]
  PIN a[87]
    DIRECTION INPUT ;
    USE SIGNAL ;
    PORT
      LAYER M4 ;
        RECT  64.692 28.272 64.776 28.296 ;
    END
  END a[87]
  PIN a[88]
    DIRECTION INPUT ;
    USE SIGNAL ;
    PORT
      LAYER M4 ;
        RECT  64.692 28.368 64.776 28.392 ;
    END
  END a[88]
  PIN a[89]
    DIRECTION INPUT ;
    USE SIGNAL ;
    PORT
      LAYER M4 ;
        RECT  64.692 28.464 64.776 28.488 ;
    END
  END a[89]
  PIN a[8]
    DIRECTION INPUT ;
    USE SIGNAL ;
    PORT
      LAYER M4 ;
        RECT  64.692 36.048 64.776 36.072 ;
    END
  END a[8]
  PIN a[90]
    DIRECTION INPUT ;
    USE SIGNAL ;
    PORT
      LAYER M4 ;
        RECT  64.692 28.56 64.776 28.584 ;
    END
  END a[90]
  PIN a[91]
    DIRECTION INPUT ;
    USE SIGNAL ;
    PORT
      LAYER M4 ;
        RECT  64.692 28.656 64.776 28.68 ;
    END
  END a[91]
  PIN a[92]
    DIRECTION INPUT ;
    USE SIGNAL ;
    PORT
      LAYER M4 ;
        RECT  64.692 28.752 64.776 28.776 ;
    END
  END a[92]
  PIN a[93]
    DIRECTION INPUT ;
    USE SIGNAL ;
    PORT
      LAYER M4 ;
        RECT  64.692 28.848 64.776 28.872 ;
    END
  END a[93]
  PIN a[94]
    DIRECTION INPUT ;
    USE SIGNAL ;
    PORT
      LAYER M4 ;
        RECT  64.692 28.944 64.776 28.968 ;
    END
  END a[94]
  PIN a[95]
    DIRECTION INPUT ;
    USE SIGNAL ;
    PORT
      LAYER M4 ;
        RECT  64.692 29.04 64.776 29.064 ;
    END
  END a[95]
  PIN a[96]
    DIRECTION INPUT ;
    USE SIGNAL ;
    PORT
      LAYER M4 ;
        RECT  64.692 29.136 64.776 29.16 ;
    END
  END a[96]
  PIN a[97]
    DIRECTION INPUT ;
    USE SIGNAL ;
    PORT
      LAYER M4 ;
        RECT  64.692 29.232 64.776 29.256 ;
    END
  END a[97]
  PIN a[98]
    DIRECTION INPUT ;
    USE SIGNAL ;
    PORT
      LAYER M4 ;
        RECT  64.692 29.328 64.776 29.352 ;
    END
  END a[98]
  PIN a[99]
    DIRECTION INPUT ;
    USE SIGNAL ;
    PORT
      LAYER M4 ;
        RECT  64.692 29.424 64.776 29.448 ;
    END
  END a[99]
  PIN a[9]
    DIRECTION INPUT ;
    USE SIGNAL ;
    PORT
      LAYER M4 ;
        RECT  64.692 36.144 64.776 36.168 ;
    END
  END a[9]
  PIN b[0]
    DIRECTION OUTPUT ;
    USE SIGNAL ;
    PORT
      LAYER M3 ;
        RECT  21.636 60.419 21.654 60.456 ;
    END
  END b[0]
  PIN b[100]
    DIRECTION OUTPUT ;
    USE SIGNAL ;
    PORT
      LAYER M5 ;
        RECT  39.12 60.372 39.144 60.456 ;
    END
  END b[100]
  PIN b[101]
    DIRECTION OUTPUT ;
    USE SIGNAL ;
    PORT
      LAYER M5 ;
        RECT  39.216 60.372 39.24 60.456 ;
    END
  END b[101]
  PIN b[102]
    DIRECTION OUTPUT ;
    USE SIGNAL ;
    PORT
      LAYER M5 ;
        RECT  39.312 60.372 39.336 60.456 ;
    END
  END b[102]
  PIN b[103]
    DIRECTION OUTPUT ;
    USE SIGNAL ;
    PORT
      LAYER M5 ;
        RECT  39.408 60.372 39.432 60.456 ;
    END
  END b[103]
  PIN b[104]
    DIRECTION OUTPUT ;
    USE SIGNAL ;
    PORT
      LAYER M5 ;
        RECT  39.504 60.372 39.528 60.456 ;
    END
  END b[104]
  PIN b[105]
    DIRECTION OUTPUT ;
    USE SIGNAL ;
    PORT
      LAYER M5 ;
        RECT  39.6 60.372 39.624 60.456 ;
    END
  END b[105]
  PIN b[106]
    DIRECTION OUTPUT ;
    USE SIGNAL ;
    PORT
      LAYER M5 ;
        RECT  39.696 60.372 39.72 60.456 ;
    END
  END b[106]
  PIN b[107]
    DIRECTION OUTPUT ;
    USE SIGNAL ;
    PORT
      LAYER M5 ;
        RECT  39.792 60.372 39.816 60.456 ;
    END
  END b[107]
  PIN b[108]
    DIRECTION OUTPUT ;
    USE SIGNAL ;
    PORT
      LAYER M5 ;
        RECT  39.888 60.372 39.912 60.456 ;
    END
  END b[108]
  PIN b[109]
    DIRECTION OUTPUT ;
    USE SIGNAL ;
    PORT
      LAYER M5 ;
        RECT  39.984 60.372 40.008 60.456 ;
    END
  END b[109]
  PIN b[10]
    DIRECTION OUTPUT ;
    USE SIGNAL ;
    PORT
      LAYER M3 ;
        RECT  22.356 60.419 22.374 60.456 ;
    END
  END b[10]
  PIN b[110]
    DIRECTION OUTPUT ;
    USE SIGNAL ;
    PORT
      LAYER M5 ;
        RECT  40.08 60.372 40.104 60.456 ;
    END
  END b[110]
  PIN b[111]
    DIRECTION OUTPUT ;
    USE SIGNAL ;
    PORT
      LAYER M5 ;
        RECT  40.176 60.372 40.2 60.456 ;
    END
  END b[111]
  PIN b[112]
    DIRECTION OUTPUT ;
    USE SIGNAL ;
    PORT
      LAYER M5 ;
        RECT  40.272 60.372 40.296 60.456 ;
    END
  END b[112]
  PIN b[113]
    DIRECTION OUTPUT ;
    USE SIGNAL ;
    PORT
      LAYER M5 ;
        RECT  40.368 60.372 40.392 60.456 ;
    END
  END b[113]
  PIN b[114]
    DIRECTION OUTPUT ;
    USE SIGNAL ;
    PORT
      LAYER M5 ;
        RECT  40.464 60.372 40.488 60.456 ;
    END
  END b[114]
  PIN b[115]
    DIRECTION OUTPUT ;
    USE SIGNAL ;
    PORT
      LAYER M5 ;
        RECT  40.56 60.372 40.584 60.456 ;
    END
  END b[115]
  PIN b[116]
    DIRECTION OUTPUT ;
    USE SIGNAL ;
    PORT
      LAYER M5 ;
        RECT  40.656 60.372 40.68 60.456 ;
    END
  END b[116]
  PIN b[117]
    DIRECTION OUTPUT ;
    USE SIGNAL ;
    PORT
      LAYER M5 ;
        RECT  40.752 60.372 40.776 60.456 ;
    END
  END b[117]
  PIN b[118]
    DIRECTION OUTPUT ;
    USE SIGNAL ;
    PORT
      LAYER M5 ;
        RECT  40.848 60.372 40.872 60.456 ;
    END
  END b[118]
  PIN b[119]
    DIRECTION OUTPUT ;
    USE SIGNAL ;
    PORT
      LAYER M5 ;
        RECT  40.944 60.372 40.968 60.456 ;
    END
  END b[119]
  PIN b[11]
    DIRECTION OUTPUT ;
    USE SIGNAL ;
    PORT
      LAYER M3 ;
        RECT  22.428 60.419 22.446 60.456 ;
    END
  END b[11]
  PIN b[120]
    DIRECTION OUTPUT ;
    USE SIGNAL ;
    PORT
      LAYER M5 ;
        RECT  41.04 60.372 41.064 60.456 ;
    END
  END b[120]
  PIN b[121]
    DIRECTION OUTPUT ;
    USE SIGNAL ;
    PORT
      LAYER M5 ;
        RECT  41.136 60.372 41.16 60.456 ;
    END
  END b[121]
  PIN b[122]
    DIRECTION OUTPUT ;
    USE SIGNAL ;
    PORT
      LAYER M5 ;
        RECT  41.232 60.372 41.256 60.456 ;
    END
  END b[122]
  PIN b[123]
    DIRECTION OUTPUT ;
    USE SIGNAL ;
    PORT
      LAYER M5 ;
        RECT  41.328 60.372 41.352 60.456 ;
    END
  END b[123]
  PIN b[124]
    DIRECTION OUTPUT ;
    USE SIGNAL ;
    PORT
      LAYER M5 ;
        RECT  41.424 60.372 41.448 60.456 ;
    END
  END b[124]
  PIN b[125]
    DIRECTION OUTPUT ;
    USE SIGNAL ;
    PORT
      LAYER M5 ;
        RECT  41.52 60.372 41.544 60.456 ;
    END
  END b[125]
  PIN b[126]
    DIRECTION OUTPUT ;
    USE SIGNAL ;
    PORT
      LAYER M5 ;
        RECT  41.616 60.372 41.64 60.456 ;
    END
  END b[126]
  PIN b[127]
    DIRECTION OUTPUT ;
    USE SIGNAL ;
    PORT
      LAYER M5 ;
        RECT  41.712 60.372 41.736 60.456 ;
    END
  END b[127]
  PIN b[128]
    DIRECTION OUTPUT ;
    USE SIGNAL ;
    PORT
      LAYER M5 ;
        RECT  41.808 60.372 41.832 60.456 ;
    END
  END b[128]
  PIN b[129]
    DIRECTION OUTPUT ;
    USE SIGNAL ;
    PORT
      LAYER M5 ;
        RECT  41.904 60.372 41.928 60.456 ;
    END
  END b[129]
  PIN b[12]
    DIRECTION OUTPUT ;
    USE SIGNAL ;
    PORT
      LAYER M3 ;
        RECT  22.5 60.419 22.518 60.456 ;
    END
  END b[12]
  PIN b[130]
    DIRECTION OUTPUT ;
    USE SIGNAL ;
    PORT
      LAYER M5 ;
        RECT  42 60.372 42.024 60.456 ;
    END
  END b[130]
  PIN b[131]
    DIRECTION OUTPUT ;
    USE SIGNAL ;
    PORT
      LAYER M5 ;
        RECT  42.096 60.372 42.12 60.456 ;
    END
  END b[131]
  PIN b[132]
    DIRECTION OUTPUT ;
    USE SIGNAL ;
    PORT
      LAYER M5 ;
        RECT  42.192 60.372 42.216 60.456 ;
    END
  END b[132]
  PIN b[133]
    DIRECTION OUTPUT ;
    USE SIGNAL ;
    PORT
      LAYER M5 ;
        RECT  42.288 60.372 42.312 60.456 ;
    END
  END b[133]
  PIN b[134]
    DIRECTION OUTPUT ;
    USE SIGNAL ;
    PORT
      LAYER M5 ;
        RECT  42.384 60.372 42.408 60.456 ;
    END
  END b[134]
  PIN b[135]
    DIRECTION OUTPUT ;
    USE SIGNAL ;
    PORT
      LAYER M5 ;
        RECT  42.48 60.372 42.504 60.456 ;
    END
  END b[135]
  PIN b[136]
    DIRECTION OUTPUT ;
    USE SIGNAL ;
    PORT
      LAYER M5 ;
        RECT  42.576 60.372 42.6 60.456 ;
    END
  END b[136]
  PIN b[137]
    DIRECTION OUTPUT ;
    USE SIGNAL ;
    PORT
      LAYER M5 ;
        RECT  42.672 60.372 42.696 60.456 ;
    END
  END b[137]
  PIN b[138]
    DIRECTION OUTPUT ;
    USE SIGNAL ;
    PORT
      LAYER M5 ;
        RECT  42.768 60.372 42.792 60.456 ;
    END
  END b[138]
  PIN b[139]
    DIRECTION OUTPUT ;
    USE SIGNAL ;
    PORT
      LAYER M5 ;
        RECT  42.864 60.372 42.888 60.456 ;
    END
  END b[139]
  PIN b[13]
    DIRECTION OUTPUT ;
    USE SIGNAL ;
    PORT
      LAYER M3 ;
        RECT  22.572 60.419 22.59 60.456 ;
    END
  END b[13]
  PIN b[140]
    DIRECTION OUTPUT ;
    USE SIGNAL ;
    PORT
      LAYER M5 ;
        RECT  42.96 60.372 42.984 60.456 ;
    END
  END b[140]
  PIN b[141]
    DIRECTION OUTPUT ;
    USE SIGNAL ;
    PORT
      LAYER M5 ;
        RECT  43.056 60.372 43.08 60.456 ;
    END
  END b[141]
  PIN b[142]
    DIRECTION OUTPUT ;
    USE SIGNAL ;
    PORT
      LAYER M5 ;
        RECT  43.152 60.372 43.176 60.456 ;
    END
  END b[142]
  PIN b[143]
    DIRECTION OUTPUT ;
    USE SIGNAL ;
    PORT
      LAYER M5 ;
        RECT  43.248 60.372 43.272 60.456 ;
    END
  END b[143]
  PIN b[144]
    DIRECTION OUTPUT ;
    USE SIGNAL ;
    PORT
      LAYER M5 ;
        RECT  43.344 60.372 43.368 60.456 ;
    END
  END b[144]
  PIN b[145]
    DIRECTION OUTPUT ;
    USE SIGNAL ;
    PORT
      LAYER M5 ;
        RECT  43.44 60.372 43.464 60.456 ;
    END
  END b[145]
  PIN b[146]
    DIRECTION OUTPUT ;
    USE SIGNAL ;
    PORT
      LAYER M5 ;
        RECT  43.536 60.372 43.56 60.456 ;
    END
  END b[146]
  PIN b[147]
    DIRECTION OUTPUT ;
    USE SIGNAL ;
    PORT
      LAYER M5 ;
        RECT  43.632 60.372 43.656 60.456 ;
    END
  END b[147]
  PIN b[148]
    DIRECTION OUTPUT ;
    USE SIGNAL ;
    PORT
      LAYER M5 ;
        RECT  43.728 60.372 43.752 60.456 ;
    END
  END b[148]
  PIN b[149]
    DIRECTION OUTPUT ;
    USE SIGNAL ;
    PORT
      LAYER M5 ;
        RECT  43.824 60.372 43.848 60.456 ;
    END
  END b[149]
  PIN b[14]
    DIRECTION OUTPUT ;
    USE SIGNAL ;
    PORT
      LAYER M3 ;
        RECT  22.644 60.419 22.662 60.456 ;
    END
  END b[14]
  PIN b[150]
    DIRECTION OUTPUT ;
    USE SIGNAL ;
    PORT
      LAYER M5 ;
        RECT  43.92 60.372 43.944 60.456 ;
    END
  END b[150]
  PIN b[151]
    DIRECTION OUTPUT ;
    USE SIGNAL ;
    PORT
      LAYER M5 ;
        RECT  44.016 60.372 44.04 60.456 ;
    END
  END b[151]
  PIN b[152]
    DIRECTION OUTPUT ;
    USE SIGNAL ;
    PORT
      LAYER M5 ;
        RECT  44.112 60.372 44.136 60.456 ;
    END
  END b[152]
  PIN b[153]
    DIRECTION OUTPUT ;
    USE SIGNAL ;
    PORT
      LAYER M5 ;
        RECT  44.208 60.372 44.232 60.456 ;
    END
  END b[153]
  PIN b[154]
    DIRECTION OUTPUT ;
    USE SIGNAL ;
    PORT
      LAYER M5 ;
        RECT  44.304 60.372 44.328 60.456 ;
    END
  END b[154]
  PIN b[155]
    DIRECTION OUTPUT ;
    USE SIGNAL ;
    PORT
      LAYER M5 ;
        RECT  44.4 60.372 44.424 60.456 ;
    END
  END b[155]
  PIN b[156]
    DIRECTION OUTPUT ;
    USE SIGNAL ;
    PORT
      LAYER M5 ;
        RECT  44.496 60.372 44.52 60.456 ;
    END
  END b[156]
  PIN b[157]
    DIRECTION OUTPUT ;
    USE SIGNAL ;
    PORT
      LAYER M5 ;
        RECT  44.592 60.372 44.616 60.456 ;
    END
  END b[157]
  PIN b[158]
    DIRECTION OUTPUT ;
    USE SIGNAL ;
    PORT
      LAYER M5 ;
        RECT  44.688 60.372 44.712 60.456 ;
    END
  END b[158]
  PIN b[159]
    DIRECTION OUTPUT ;
    USE SIGNAL ;
    PORT
      LAYER M5 ;
        RECT  44.784 60.372 44.808 60.456 ;
    END
  END b[159]
  PIN b[15]
    DIRECTION OUTPUT ;
    USE SIGNAL ;
    PORT
      LAYER M3 ;
        RECT  22.716 60.419 22.734 60.456 ;
    END
  END b[15]
  PIN b[160]
    DIRECTION OUTPUT ;
    USE SIGNAL ;
    PORT
      LAYER M5 ;
        RECT  32.592 60.372 32.616 60.456 ;
    END
  END b[160]
  PIN b[161]
    DIRECTION OUTPUT ;
    USE SIGNAL ;
    PORT
      LAYER M5 ;
        RECT  32.688 60.372 32.712 60.456 ;
    END
  END b[161]
  PIN b[162]
    DIRECTION OUTPUT ;
    USE SIGNAL ;
    PORT
      LAYER M5 ;
        RECT  32.784 60.372 32.808 60.456 ;
    END
  END b[162]
  PIN b[163]
    DIRECTION OUTPUT ;
    USE SIGNAL ;
    PORT
      LAYER M5 ;
        RECT  32.88 60.372 32.904 60.456 ;
    END
  END b[163]
  PIN b[164]
    DIRECTION OUTPUT ;
    USE SIGNAL ;
    PORT
      LAYER M5 ;
        RECT  32.976 60.372 33 60.456 ;
    END
  END b[164]
  PIN b[165]
    DIRECTION OUTPUT ;
    USE SIGNAL ;
    PORT
      LAYER M5 ;
        RECT  33.072 60.372 33.096 60.456 ;
    END
  END b[165]
  PIN b[166]
    DIRECTION OUTPUT ;
    USE SIGNAL ;
    PORT
      LAYER M5 ;
        RECT  33.168 60.372 33.192 60.456 ;
    END
  END b[166]
  PIN b[167]
    DIRECTION OUTPUT ;
    USE SIGNAL ;
    PORT
      LAYER M5 ;
        RECT  33.264 60.372 33.288 60.456 ;
    END
  END b[167]
  PIN b[168]
    DIRECTION OUTPUT ;
    USE SIGNAL ;
    PORT
      LAYER M5 ;
        RECT  33.36 60.372 33.384 60.456 ;
    END
  END b[168]
  PIN b[169]
    DIRECTION OUTPUT ;
    USE SIGNAL ;
    PORT
      LAYER M5 ;
        RECT  33.456 60.372 33.48 60.456 ;
    END
  END b[169]
  PIN b[16]
    DIRECTION OUTPUT ;
    USE SIGNAL ;
    PORT
      LAYER M3 ;
        RECT  22.788 60.419 22.806 60.456 ;
    END
  END b[16]
  PIN b[170]
    DIRECTION OUTPUT ;
    USE SIGNAL ;
    PORT
      LAYER M5 ;
        RECT  33.552 60.372 33.576 60.456 ;
    END
  END b[170]
  PIN b[171]
    DIRECTION OUTPUT ;
    USE SIGNAL ;
    PORT
      LAYER M5 ;
        RECT  33.648 60.372 33.672 60.456 ;
    END
  END b[171]
  PIN b[172]
    DIRECTION OUTPUT ;
    USE SIGNAL ;
    PORT
      LAYER M5 ;
        RECT  33.744 60.372 33.768 60.456 ;
    END
  END b[172]
  PIN b[173]
    DIRECTION OUTPUT ;
    USE SIGNAL ;
    PORT
      LAYER M5 ;
        RECT  33.84 60.372 33.864 60.456 ;
    END
  END b[173]
  PIN b[174]
    DIRECTION OUTPUT ;
    USE SIGNAL ;
    PORT
      LAYER M5 ;
        RECT  33.936 60.372 33.96 60.456 ;
    END
  END b[174]
  PIN b[175]
    DIRECTION OUTPUT ;
    USE SIGNAL ;
    PORT
      LAYER M5 ;
        RECT  34.032 60.372 34.056 60.456 ;
    END
  END b[175]
  PIN b[176]
    DIRECTION OUTPUT ;
    USE SIGNAL ;
    PORT
      LAYER M5 ;
        RECT  34.128 60.372 34.152 60.456 ;
    END
  END b[176]
  PIN b[177]
    DIRECTION OUTPUT ;
    USE SIGNAL ;
    PORT
      LAYER M5 ;
        RECT  34.224 60.372 34.248 60.456 ;
    END
  END b[177]
  PIN b[178]
    DIRECTION OUTPUT ;
    USE SIGNAL ;
    PORT
      LAYER M5 ;
        RECT  34.32 60.372 34.344 60.456 ;
    END
  END b[178]
  PIN b[179]
    DIRECTION OUTPUT ;
    USE SIGNAL ;
    PORT
      LAYER M5 ;
        RECT  34.416 60.372 34.44 60.456 ;
    END
  END b[179]
  PIN b[17]
    DIRECTION OUTPUT ;
    USE SIGNAL ;
    PORT
      LAYER M3 ;
        RECT  22.86 60.419 22.878 60.456 ;
    END
  END b[17]
  PIN b[180]
    DIRECTION OUTPUT ;
    USE SIGNAL ;
    PORT
      LAYER M5 ;
        RECT  34.512 60.372 34.536 60.456 ;
    END
  END b[180]
  PIN b[181]
    DIRECTION OUTPUT ;
    USE SIGNAL ;
    PORT
      LAYER M5 ;
        RECT  34.608 60.372 34.632 60.456 ;
    END
  END b[181]
  PIN b[182]
    DIRECTION OUTPUT ;
    USE SIGNAL ;
    PORT
      LAYER M5 ;
        RECT  34.704 60.372 34.728 60.456 ;
    END
  END b[182]
  PIN b[183]
    DIRECTION OUTPUT ;
    USE SIGNAL ;
    PORT
      LAYER M5 ;
        RECT  34.8 60.372 34.824 60.456 ;
    END
  END b[183]
  PIN b[184]
    DIRECTION OUTPUT ;
    USE SIGNAL ;
    PORT
      LAYER M5 ;
        RECT  34.896 60.372 34.92 60.456 ;
    END
  END b[184]
  PIN b[185]
    DIRECTION OUTPUT ;
    USE SIGNAL ;
    PORT
      LAYER M5 ;
        RECT  34.992 60.372 35.016 60.456 ;
    END
  END b[185]
  PIN b[186]
    DIRECTION OUTPUT ;
    USE SIGNAL ;
    PORT
      LAYER M5 ;
        RECT  35.088 60.372 35.112 60.456 ;
    END
  END b[186]
  PIN b[187]
    DIRECTION OUTPUT ;
    USE SIGNAL ;
    PORT
      LAYER M5 ;
        RECT  35.184 60.372 35.208 60.456 ;
    END
  END b[187]
  PIN b[188]
    DIRECTION OUTPUT ;
    USE SIGNAL ;
    PORT
      LAYER M5 ;
        RECT  35.28 60.372 35.304 60.456 ;
    END
  END b[188]
  PIN b[189]
    DIRECTION OUTPUT ;
    USE SIGNAL ;
    PORT
      LAYER M5 ;
        RECT  35.376 60.372 35.4 60.456 ;
    END
  END b[189]
  PIN b[18]
    DIRECTION OUTPUT ;
    USE SIGNAL ;
    PORT
      LAYER M3 ;
        RECT  22.932 60.419 22.95 60.456 ;
    END
  END b[18]
  PIN b[190]
    DIRECTION OUTPUT ;
    USE SIGNAL ;
    PORT
      LAYER M5 ;
        RECT  35.472 60.372 35.496 60.456 ;
    END
  END b[190]
  PIN b[191]
    DIRECTION OUTPUT ;
    USE SIGNAL ;
    PORT
      LAYER M5 ;
        RECT  35.568 60.372 35.592 60.456 ;
    END
  END b[191]
  PIN b[192]
    DIRECTION OUTPUT ;
    USE SIGNAL ;
    PORT
      LAYER M5 ;
        RECT  26.448 60.372 26.472 60.456 ;
    END
  END b[192]
  PIN b[193]
    DIRECTION OUTPUT ;
    USE SIGNAL ;
    PORT
      LAYER M5 ;
        RECT  26.544 60.372 26.568 60.456 ;
    END
  END b[193]
  PIN b[194]
    DIRECTION OUTPUT ;
    USE SIGNAL ;
    PORT
      LAYER M5 ;
        RECT  26.64 60.372 26.664 60.456 ;
    END
  END b[194]
  PIN b[195]
    DIRECTION OUTPUT ;
    USE SIGNAL ;
    PORT
      LAYER M5 ;
        RECT  26.736 60.372 26.76 60.456 ;
    END
  END b[195]
  PIN b[196]
    DIRECTION OUTPUT ;
    USE SIGNAL ;
    PORT
      LAYER M5 ;
        RECT  26.832 60.372 26.856 60.456 ;
    END
  END b[196]
  PIN b[197]
    DIRECTION OUTPUT ;
    USE SIGNAL ;
    PORT
      LAYER M5 ;
        RECT  26.928 60.372 26.952 60.456 ;
    END
  END b[197]
  PIN b[198]
    DIRECTION OUTPUT ;
    USE SIGNAL ;
    PORT
      LAYER M5 ;
        RECT  27.024 60.372 27.048 60.456 ;
    END
  END b[198]
  PIN b[199]
    DIRECTION OUTPUT ;
    USE SIGNAL ;
    PORT
      LAYER M5 ;
        RECT  27.12 60.372 27.144 60.456 ;
    END
  END b[199]
  PIN b[19]
    DIRECTION OUTPUT ;
    USE SIGNAL ;
    PORT
      LAYER M3 ;
        RECT  23.004 60.419 23.022 60.456 ;
    END
  END b[19]
  PIN b[1]
    DIRECTION OUTPUT ;
    USE SIGNAL ;
    PORT
      LAYER M3 ;
        RECT  21.708 60.419 21.726 60.456 ;
    END
  END b[1]
  PIN b[200]
    DIRECTION OUTPUT ;
    USE SIGNAL ;
    PORT
      LAYER M5 ;
        RECT  27.216 60.372 27.24 60.456 ;
    END
  END b[200]
  PIN b[201]
    DIRECTION OUTPUT ;
    USE SIGNAL ;
    PORT
      LAYER M5 ;
        RECT  27.312 60.372 27.336 60.456 ;
    END
  END b[201]
  PIN b[202]
    DIRECTION OUTPUT ;
    USE SIGNAL ;
    PORT
      LAYER M5 ;
        RECT  27.408 60.372 27.432 60.456 ;
    END
  END b[202]
  PIN b[203]
    DIRECTION OUTPUT ;
    USE SIGNAL ;
    PORT
      LAYER M5 ;
        RECT  27.504 60.372 27.528 60.456 ;
    END
  END b[203]
  PIN b[204]
    DIRECTION OUTPUT ;
    USE SIGNAL ;
    PORT
      LAYER M5 ;
        RECT  27.6 60.372 27.624 60.456 ;
    END
  END b[204]
  PIN b[205]
    DIRECTION OUTPUT ;
    USE SIGNAL ;
    PORT
      LAYER M5 ;
        RECT  27.696 60.372 27.72 60.456 ;
    END
  END b[205]
  PIN b[206]
    DIRECTION OUTPUT ;
    USE SIGNAL ;
    PORT
      LAYER M5 ;
        RECT  27.792 60.372 27.816 60.456 ;
    END
  END b[206]
  PIN b[207]
    DIRECTION OUTPUT ;
    USE SIGNAL ;
    PORT
      LAYER M5 ;
        RECT  27.888 60.372 27.912 60.456 ;
    END
  END b[207]
  PIN b[208]
    DIRECTION OUTPUT ;
    USE SIGNAL ;
    PORT
      LAYER M5 ;
        RECT  27.984 60.372 28.008 60.456 ;
    END
  END b[208]
  PIN b[209]
    DIRECTION OUTPUT ;
    USE SIGNAL ;
    PORT
      LAYER M5 ;
        RECT  28.08 60.372 28.104 60.456 ;
    END
  END b[209]
  PIN b[20]
    DIRECTION OUTPUT ;
    USE SIGNAL ;
    PORT
      LAYER M3 ;
        RECT  23.076 60.419 23.094 60.456 ;
    END
  END b[20]
  PIN b[210]
    DIRECTION OUTPUT ;
    USE SIGNAL ;
    PORT
      LAYER M5 ;
        RECT  28.176 60.372 28.2 60.456 ;
    END
  END b[210]
  PIN b[211]
    DIRECTION OUTPUT ;
    USE SIGNAL ;
    PORT
      LAYER M5 ;
        RECT  28.272 60.372 28.296 60.456 ;
    END
  END b[211]
  PIN b[212]
    DIRECTION OUTPUT ;
    USE SIGNAL ;
    PORT
      LAYER M5 ;
        RECT  28.368 60.372 28.392 60.456 ;
    END
  END b[212]
  PIN b[213]
    DIRECTION OUTPUT ;
    USE SIGNAL ;
    PORT
      LAYER M5 ;
        RECT  28.464 60.372 28.488 60.456 ;
    END
  END b[213]
  PIN b[214]
    DIRECTION OUTPUT ;
    USE SIGNAL ;
    PORT
      LAYER M5 ;
        RECT  28.56 60.372 28.584 60.456 ;
    END
  END b[214]
  PIN b[215]
    DIRECTION OUTPUT ;
    USE SIGNAL ;
    PORT
      LAYER M5 ;
        RECT  28.656 60.372 28.68 60.456 ;
    END
  END b[215]
  PIN b[216]
    DIRECTION OUTPUT ;
    USE SIGNAL ;
    PORT
      LAYER M5 ;
        RECT  28.752 60.372 28.776 60.456 ;
    END
  END b[216]
  PIN b[217]
    DIRECTION OUTPUT ;
    USE SIGNAL ;
    PORT
      LAYER M5 ;
        RECT  28.848 60.372 28.872 60.456 ;
    END
  END b[217]
  PIN b[218]
    DIRECTION OUTPUT ;
    USE SIGNAL ;
    PORT
      LAYER M5 ;
        RECT  28.944 60.372 28.968 60.456 ;
    END
  END b[218]
  PIN b[219]
    DIRECTION OUTPUT ;
    USE SIGNAL ;
    PORT
      LAYER M5 ;
        RECT  29.04 60.372 29.064 60.456 ;
    END
  END b[219]
  PIN b[21]
    DIRECTION OUTPUT ;
    USE SIGNAL ;
    PORT
      LAYER M3 ;
        RECT  23.148 60.419 23.166 60.456 ;
    END
  END b[21]
  PIN b[220]
    DIRECTION OUTPUT ;
    USE SIGNAL ;
    PORT
      LAYER M5 ;
        RECT  29.136 60.372 29.16 60.456 ;
    END
  END b[220]
  PIN b[221]
    DIRECTION OUTPUT ;
    USE SIGNAL ;
    PORT
      LAYER M5 ;
        RECT  29.232 60.372 29.256 60.456 ;
    END
  END b[221]
  PIN b[222]
    DIRECTION OUTPUT ;
    USE SIGNAL ;
    PORT
      LAYER M5 ;
        RECT  29.328 60.372 29.352 60.456 ;
    END
  END b[222]
  PIN b[223]
    DIRECTION OUTPUT ;
    USE SIGNAL ;
    PORT
      LAYER M5 ;
        RECT  29.424 60.372 29.448 60.456 ;
    END
  END b[223]
  PIN b[224]
    DIRECTION OUTPUT ;
    USE SIGNAL ;
    PORT
      LAYER M3 ;
        RECT  26.244 60.419 26.262 60.456 ;
    END
  END b[224]
  PIN b[225]
    DIRECTION OUTPUT ;
    USE SIGNAL ;
    PORT
      LAYER M3 ;
        RECT  26.316 60.419 26.334 60.456 ;
    END
  END b[225]
  PIN b[226]
    DIRECTION OUTPUT ;
    USE SIGNAL ;
    PORT
      LAYER M3 ;
        RECT  26.388 60.419 26.406 60.456 ;
    END
  END b[226]
  PIN b[227]
    DIRECTION OUTPUT ;
    USE SIGNAL ;
    PORT
      LAYER M3 ;
        RECT  26.46 60.419 26.478 60.456 ;
    END
  END b[227]
  PIN b[228]
    DIRECTION OUTPUT ;
    USE SIGNAL ;
    PORT
      LAYER M3 ;
        RECT  26.532 60.419 26.55 60.456 ;
    END
  END b[228]
  PIN b[229]
    DIRECTION OUTPUT ;
    USE SIGNAL ;
    PORT
      LAYER M3 ;
        RECT  26.604 60.419 26.622 60.456 ;
    END
  END b[229]
  PIN b[22]
    DIRECTION OUTPUT ;
    USE SIGNAL ;
    PORT
      LAYER M3 ;
        RECT  23.22 60.419 23.238 60.456 ;
    END
  END b[22]
  PIN b[230]
    DIRECTION OUTPUT ;
    USE SIGNAL ;
    PORT
      LAYER M3 ;
        RECT  26.676 60.419 26.694 60.456 ;
    END
  END b[230]
  PIN b[231]
    DIRECTION OUTPUT ;
    USE SIGNAL ;
    PORT
      LAYER M3 ;
        RECT  26.748 60.419 26.766 60.456 ;
    END
  END b[231]
  PIN b[232]
    DIRECTION OUTPUT ;
    USE SIGNAL ;
    PORT
      LAYER M3 ;
        RECT  26.82 60.419 26.838 60.456 ;
    END
  END b[232]
  PIN b[233]
    DIRECTION OUTPUT ;
    USE SIGNAL ;
    PORT
      LAYER M3 ;
        RECT  26.892 60.419 26.91 60.456 ;
    END
  END b[233]
  PIN b[234]
    DIRECTION OUTPUT ;
    USE SIGNAL ;
    PORT
      LAYER M3 ;
        RECT  26.964 60.419 26.982 60.456 ;
    END
  END b[234]
  PIN b[235]
    DIRECTION OUTPUT ;
    USE SIGNAL ;
    PORT
      LAYER M3 ;
        RECT  27.036 60.419 27.054 60.456 ;
    END
  END b[235]
  PIN b[236]
    DIRECTION OUTPUT ;
    USE SIGNAL ;
    PORT
      LAYER M3 ;
        RECT  27.108 60.419 27.126 60.456 ;
    END
  END b[236]
  PIN b[237]
    DIRECTION OUTPUT ;
    USE SIGNAL ;
    PORT
      LAYER M3 ;
        RECT  27.18 60.419 27.198 60.456 ;
    END
  END b[237]
  PIN b[238]
    DIRECTION OUTPUT ;
    USE SIGNAL ;
    PORT
      LAYER M3 ;
        RECT  27.252 60.419 27.27 60.456 ;
    END
  END b[238]
  PIN b[239]
    DIRECTION OUTPUT ;
    USE SIGNAL ;
    PORT
      LAYER M3 ;
        RECT  27.324 60.419 27.342 60.456 ;
    END
  END b[239]
  PIN b[23]
    DIRECTION OUTPUT ;
    USE SIGNAL ;
    PORT
      LAYER M3 ;
        RECT  23.292 60.419 23.31 60.456 ;
    END
  END b[23]
  PIN b[240]
    DIRECTION OUTPUT ;
    USE SIGNAL ;
    PORT
      LAYER M3 ;
        RECT  27.396 60.419 27.414 60.456 ;
    END
  END b[240]
  PIN b[241]
    DIRECTION OUTPUT ;
    USE SIGNAL ;
    PORT
      LAYER M3 ;
        RECT  27.468 60.419 27.486 60.456 ;
    END
  END b[241]
  PIN b[242]
    DIRECTION OUTPUT ;
    USE SIGNAL ;
    PORT
      LAYER M3 ;
        RECT  27.54 60.419 27.558 60.456 ;
    END
  END b[242]
  PIN b[243]
    DIRECTION OUTPUT ;
    USE SIGNAL ;
    PORT
      LAYER M3 ;
        RECT  27.612 60.419 27.63 60.456 ;
    END
  END b[243]
  PIN b[244]
    DIRECTION OUTPUT ;
    USE SIGNAL ;
    PORT
      LAYER M3 ;
        RECT  27.684 60.419 27.702 60.456 ;
    END
  END b[244]
  PIN b[245]
    DIRECTION OUTPUT ;
    USE SIGNAL ;
    PORT
      LAYER M3 ;
        RECT  27.756 60.419 27.774 60.456 ;
    END
  END b[245]
  PIN b[246]
    DIRECTION OUTPUT ;
    USE SIGNAL ;
    PORT
      LAYER M3 ;
        RECT  27.828 60.419 27.846 60.456 ;
    END
  END b[246]
  PIN b[247]
    DIRECTION OUTPUT ;
    USE SIGNAL ;
    PORT
      LAYER M3 ;
        RECT  27.9 60.419 27.918 60.456 ;
    END
  END b[247]
  PIN b[248]
    DIRECTION OUTPUT ;
    USE SIGNAL ;
    PORT
      LAYER M3 ;
        RECT  27.972 60.419 27.99 60.456 ;
    END
  END b[248]
  PIN b[249]
    DIRECTION OUTPUT ;
    USE SIGNAL ;
    PORT
      LAYER M3 ;
        RECT  28.044 60.419 28.062 60.456 ;
    END
  END b[249]
  PIN b[24]
    DIRECTION OUTPUT ;
    USE SIGNAL ;
    PORT
      LAYER M3 ;
        RECT  23.364 60.419 23.382 60.456 ;
    END
  END b[24]
  PIN b[250]
    DIRECTION OUTPUT ;
    USE SIGNAL ;
    PORT
      LAYER M3 ;
        RECT  28.116 60.419 28.134 60.456 ;
    END
  END b[250]
  PIN b[251]
    DIRECTION OUTPUT ;
    USE SIGNAL ;
    PORT
      LAYER M3 ;
        RECT  28.188 60.419 28.206 60.456 ;
    END
  END b[251]
  PIN b[252]
    DIRECTION OUTPUT ;
    USE SIGNAL ;
    PORT
      LAYER M3 ;
        RECT  28.26 60.419 28.278 60.456 ;
    END
  END b[252]
  PIN b[253]
    DIRECTION OUTPUT ;
    USE SIGNAL ;
    PORT
      LAYER M3 ;
        RECT  28.332 60.419 28.35 60.456 ;
    END
  END b[253]
  PIN b[254]
    DIRECTION OUTPUT ;
    USE SIGNAL ;
    PORT
      LAYER M3 ;
        RECT  28.404 60.419 28.422 60.456 ;
    END
  END b[254]
  PIN b[255]
    DIRECTION OUTPUT ;
    USE SIGNAL ;
    PORT
      LAYER M3 ;
        RECT  28.476 60.419 28.494 60.456 ;
    END
  END b[255]
  PIN b[256]
    DIRECTION OUTPUT ;
    USE SIGNAL ;
    PORT
      LAYER M5 ;
        RECT  29.52 60.372 29.544 60.456 ;
    END
  END b[256]
  PIN b[257]
    DIRECTION OUTPUT ;
    USE SIGNAL ;
    PORT
      LAYER M5 ;
        RECT  29.616 60.372 29.64 60.456 ;
    END
  END b[257]
  PIN b[258]
    DIRECTION OUTPUT ;
    USE SIGNAL ;
    PORT
      LAYER M5 ;
        RECT  29.712 60.372 29.736 60.456 ;
    END
  END b[258]
  PIN b[259]
    DIRECTION OUTPUT ;
    USE SIGNAL ;
    PORT
      LAYER M5 ;
        RECT  29.808 60.372 29.832 60.456 ;
    END
  END b[259]
  PIN b[25]
    DIRECTION OUTPUT ;
    USE SIGNAL ;
    PORT
      LAYER M3 ;
        RECT  23.436 60.419 23.454 60.456 ;
    END
  END b[25]
  PIN b[260]
    DIRECTION OUTPUT ;
    USE SIGNAL ;
    PORT
      LAYER M5 ;
        RECT  29.904 60.372 29.928 60.456 ;
    END
  END b[260]
  PIN b[261]
    DIRECTION OUTPUT ;
    USE SIGNAL ;
    PORT
      LAYER M5 ;
        RECT  30 60.372 30.024 60.456 ;
    END
  END b[261]
  PIN b[262]
    DIRECTION OUTPUT ;
    USE SIGNAL ;
    PORT
      LAYER M5 ;
        RECT  30.096 60.372 30.12 60.456 ;
    END
  END b[262]
  PIN b[263]
    DIRECTION OUTPUT ;
    USE SIGNAL ;
    PORT
      LAYER M5 ;
        RECT  30.192 60.372 30.216 60.456 ;
    END
  END b[263]
  PIN b[264]
    DIRECTION OUTPUT ;
    USE SIGNAL ;
    PORT
      LAYER M5 ;
        RECT  30.288 60.372 30.312 60.456 ;
    END
  END b[264]
  PIN b[265]
    DIRECTION OUTPUT ;
    USE SIGNAL ;
    PORT
      LAYER M5 ;
        RECT  30.384 60.372 30.408 60.456 ;
    END
  END b[265]
  PIN b[266]
    DIRECTION OUTPUT ;
    USE SIGNAL ;
    PORT
      LAYER M5 ;
        RECT  30.48 60.372 30.504 60.456 ;
    END
  END b[266]
  PIN b[267]
    DIRECTION OUTPUT ;
    USE SIGNAL ;
    PORT
      LAYER M5 ;
        RECT  30.576 60.372 30.6 60.456 ;
    END
  END b[267]
  PIN b[268]
    DIRECTION OUTPUT ;
    USE SIGNAL ;
    PORT
      LAYER M5 ;
        RECT  30.672 60.372 30.696 60.456 ;
    END
  END b[268]
  PIN b[269]
    DIRECTION OUTPUT ;
    USE SIGNAL ;
    PORT
      LAYER M5 ;
        RECT  30.768 60.372 30.792 60.456 ;
    END
  END b[269]
  PIN b[26]
    DIRECTION OUTPUT ;
    USE SIGNAL ;
    PORT
      LAYER M3 ;
        RECT  23.508 60.419 23.526 60.456 ;
    END
  END b[26]
  PIN b[270]
    DIRECTION OUTPUT ;
    USE SIGNAL ;
    PORT
      LAYER M5 ;
        RECT  30.864 60.372 30.888 60.456 ;
    END
  END b[270]
  PIN b[271]
    DIRECTION OUTPUT ;
    USE SIGNAL ;
    PORT
      LAYER M5 ;
        RECT  30.96 60.372 30.984 60.456 ;
    END
  END b[271]
  PIN b[272]
    DIRECTION OUTPUT ;
    USE SIGNAL ;
    PORT
      LAYER M5 ;
        RECT  31.056 60.372 31.08 60.456 ;
    END
  END b[272]
  PIN b[273]
    DIRECTION OUTPUT ;
    USE SIGNAL ;
    PORT
      LAYER M5 ;
        RECT  31.152 60.372 31.176 60.456 ;
    END
  END b[273]
  PIN b[274]
    DIRECTION OUTPUT ;
    USE SIGNAL ;
    PORT
      LAYER M5 ;
        RECT  31.248 60.372 31.272 60.456 ;
    END
  END b[274]
  PIN b[275]
    DIRECTION OUTPUT ;
    USE SIGNAL ;
    PORT
      LAYER M5 ;
        RECT  31.344 60.372 31.368 60.456 ;
    END
  END b[275]
  PIN b[276]
    DIRECTION OUTPUT ;
    USE SIGNAL ;
    PORT
      LAYER M5 ;
        RECT  31.44 60.372 31.464 60.456 ;
    END
  END b[276]
  PIN b[277]
    DIRECTION OUTPUT ;
    USE SIGNAL ;
    PORT
      LAYER M5 ;
        RECT  31.536 60.372 31.56 60.456 ;
    END
  END b[277]
  PIN b[278]
    DIRECTION OUTPUT ;
    USE SIGNAL ;
    PORT
      LAYER M5 ;
        RECT  31.632 60.372 31.656 60.456 ;
    END
  END b[278]
  PIN b[279]
    DIRECTION OUTPUT ;
    USE SIGNAL ;
    PORT
      LAYER M5 ;
        RECT  31.728 60.372 31.752 60.456 ;
    END
  END b[279]
  PIN b[27]
    DIRECTION OUTPUT ;
    USE SIGNAL ;
    PORT
      LAYER M3 ;
        RECT  23.58 60.419 23.598 60.456 ;
    END
  END b[27]
  PIN b[280]
    DIRECTION OUTPUT ;
    USE SIGNAL ;
    PORT
      LAYER M5 ;
        RECT  31.824 60.372 31.848 60.456 ;
    END
  END b[280]
  PIN b[281]
    DIRECTION OUTPUT ;
    USE SIGNAL ;
    PORT
      LAYER M5 ;
        RECT  31.92 60.372 31.944 60.456 ;
    END
  END b[281]
  PIN b[282]
    DIRECTION OUTPUT ;
    USE SIGNAL ;
    PORT
      LAYER M5 ;
        RECT  32.016 60.372 32.04 60.456 ;
    END
  END b[282]
  PIN b[283]
    DIRECTION OUTPUT ;
    USE SIGNAL ;
    PORT
      LAYER M5 ;
        RECT  32.112 60.372 32.136 60.456 ;
    END
  END b[283]
  PIN b[284]
    DIRECTION OUTPUT ;
    USE SIGNAL ;
    PORT
      LAYER M5 ;
        RECT  32.208 60.372 32.232 60.456 ;
    END
  END b[284]
  PIN b[285]
    DIRECTION OUTPUT ;
    USE SIGNAL ;
    PORT
      LAYER M5 ;
        RECT  32.304 60.372 32.328 60.456 ;
    END
  END b[285]
  PIN b[286]
    DIRECTION OUTPUT ;
    USE SIGNAL ;
    PORT
      LAYER M5 ;
        RECT  32.4 60.372 32.424 60.456 ;
    END
  END b[286]
  PIN b[287]
    DIRECTION OUTPUT ;
    USE SIGNAL ;
    PORT
      LAYER M5 ;
        RECT  32.496 60.372 32.52 60.456 ;
    END
  END b[287]
  PIN b[288]
    DIRECTION OUTPUT ;
    USE SIGNAL ;
    PORT
      LAYER M3 ;
        RECT  33.156 60.419 33.174 60.456 ;
    END
  END b[288]
  PIN b[289]
    DIRECTION OUTPUT ;
    USE SIGNAL ;
    PORT
      LAYER M3 ;
        RECT  33.228 60.419 33.246 60.456 ;
    END
  END b[289]
  PIN b[28]
    DIRECTION OUTPUT ;
    USE SIGNAL ;
    PORT
      LAYER M3 ;
        RECT  23.652 60.419 23.67 60.456 ;
    END
  END b[28]
  PIN b[290]
    DIRECTION OUTPUT ;
    USE SIGNAL ;
    PORT
      LAYER M3 ;
        RECT  33.3 60.419 33.318 60.456 ;
    END
  END b[290]
  PIN b[291]
    DIRECTION OUTPUT ;
    USE SIGNAL ;
    PORT
      LAYER M3 ;
        RECT  33.372 60.419 33.39 60.456 ;
    END
  END b[291]
  PIN b[292]
    DIRECTION OUTPUT ;
    USE SIGNAL ;
    PORT
      LAYER M3 ;
        RECT  33.444 60.419 33.462 60.456 ;
    END
  END b[292]
  PIN b[293]
    DIRECTION OUTPUT ;
    USE SIGNAL ;
    PORT
      LAYER M3 ;
        RECT  33.516 60.419 33.534 60.456 ;
    END
  END b[293]
  PIN b[294]
    DIRECTION OUTPUT ;
    USE SIGNAL ;
    PORT
      LAYER M3 ;
        RECT  33.588 60.419 33.606 60.456 ;
    END
  END b[294]
  PIN b[295]
    DIRECTION OUTPUT ;
    USE SIGNAL ;
    PORT
      LAYER M3 ;
        RECT  33.66 60.419 33.678 60.456 ;
    END
  END b[295]
  PIN b[296]
    DIRECTION OUTPUT ;
    USE SIGNAL ;
    PORT
      LAYER M3 ;
        RECT  33.732 60.419 33.75 60.456 ;
    END
  END b[296]
  PIN b[297]
    DIRECTION OUTPUT ;
    USE SIGNAL ;
    PORT
      LAYER M3 ;
        RECT  33.804 60.419 33.822 60.456 ;
    END
  END b[297]
  PIN b[298]
    DIRECTION OUTPUT ;
    USE SIGNAL ;
    PORT
      LAYER M3 ;
        RECT  33.876 60.419 33.894 60.456 ;
    END
  END b[298]
  PIN b[299]
    DIRECTION OUTPUT ;
    USE SIGNAL ;
    PORT
      LAYER M3 ;
        RECT  33.948 60.419 33.966 60.456 ;
    END
  END b[299]
  PIN b[29]
    DIRECTION OUTPUT ;
    USE SIGNAL ;
    PORT
      LAYER M3 ;
        RECT  23.724 60.419 23.742 60.456 ;
    END
  END b[29]
  PIN b[2]
    DIRECTION OUTPUT ;
    USE SIGNAL ;
    PORT
      LAYER M3 ;
        RECT  21.78 60.419 21.798 60.456 ;
    END
  END b[2]
  PIN b[300]
    DIRECTION OUTPUT ;
    USE SIGNAL ;
    PORT
      LAYER M3 ;
        RECT  34.02 60.419 34.038 60.456 ;
    END
  END b[300]
  PIN b[301]
    DIRECTION OUTPUT ;
    USE SIGNAL ;
    PORT
      LAYER M3 ;
        RECT  34.092 60.419 34.11 60.456 ;
    END
  END b[301]
  PIN b[302]
    DIRECTION OUTPUT ;
    USE SIGNAL ;
    PORT
      LAYER M3 ;
        RECT  34.164 60.419 34.182 60.456 ;
    END
  END b[302]
  PIN b[303]
    DIRECTION OUTPUT ;
    USE SIGNAL ;
    PORT
      LAYER M3 ;
        RECT  34.236 60.419 34.254 60.456 ;
    END
  END b[303]
  PIN b[304]
    DIRECTION OUTPUT ;
    USE SIGNAL ;
    PORT
      LAYER M3 ;
        RECT  34.308 60.419 34.326 60.456 ;
    END
  END b[304]
  PIN b[305]
    DIRECTION OUTPUT ;
    USE SIGNAL ;
    PORT
      LAYER M3 ;
        RECT  34.38 60.419 34.398 60.456 ;
    END
  END b[305]
  PIN b[306]
    DIRECTION OUTPUT ;
    USE SIGNAL ;
    PORT
      LAYER M3 ;
        RECT  34.452 60.419 34.47 60.456 ;
    END
  END b[306]
  PIN b[307]
    DIRECTION OUTPUT ;
    USE SIGNAL ;
    PORT
      LAYER M3 ;
        RECT  34.524 60.419 34.542 60.456 ;
    END
  END b[307]
  PIN b[308]
    DIRECTION OUTPUT ;
    USE SIGNAL ;
    PORT
      LAYER M3 ;
        RECT  34.596 60.419 34.614 60.456 ;
    END
  END b[308]
  PIN b[309]
    DIRECTION OUTPUT ;
    USE SIGNAL ;
    PORT
      LAYER M3 ;
        RECT  34.668 60.419 34.686 60.456 ;
    END
  END b[309]
  PIN b[30]
    DIRECTION OUTPUT ;
    USE SIGNAL ;
    PORT
      LAYER M3 ;
        RECT  23.796 60.419 23.814 60.456 ;
    END
  END b[30]
  PIN b[310]
    DIRECTION OUTPUT ;
    USE SIGNAL ;
    PORT
      LAYER M3 ;
        RECT  34.74 60.419 34.758 60.456 ;
    END
  END b[310]
  PIN b[311]
    DIRECTION OUTPUT ;
    USE SIGNAL ;
    PORT
      LAYER M3 ;
        RECT  34.812 60.419 34.83 60.456 ;
    END
  END b[311]
  PIN b[312]
    DIRECTION OUTPUT ;
    USE SIGNAL ;
    PORT
      LAYER M3 ;
        RECT  34.884 60.419 34.902 60.456 ;
    END
  END b[312]
  PIN b[313]
    DIRECTION OUTPUT ;
    USE SIGNAL ;
    PORT
      LAYER M3 ;
        RECT  34.956 60.419 34.974 60.456 ;
    END
  END b[313]
  PIN b[314]
    DIRECTION OUTPUT ;
    USE SIGNAL ;
    PORT
      LAYER M3 ;
        RECT  35.028 60.419 35.046 60.456 ;
    END
  END b[314]
  PIN b[315]
    DIRECTION OUTPUT ;
    USE SIGNAL ;
    PORT
      LAYER M3 ;
        RECT  35.1 60.419 35.118 60.456 ;
    END
  END b[315]
  PIN b[316]
    DIRECTION OUTPUT ;
    USE SIGNAL ;
    PORT
      LAYER M3 ;
        RECT  35.172 60.419 35.19 60.456 ;
    END
  END b[316]
  PIN b[317]
    DIRECTION OUTPUT ;
    USE SIGNAL ;
    PORT
      LAYER M3 ;
        RECT  35.244 60.419 35.262 60.456 ;
    END
  END b[317]
  PIN b[318]
    DIRECTION OUTPUT ;
    USE SIGNAL ;
    PORT
      LAYER M3 ;
        RECT  35.316 60.419 35.334 60.456 ;
    END
  END b[318]
  PIN b[319]
    DIRECTION OUTPUT ;
    USE SIGNAL ;
    PORT
      LAYER M3 ;
        RECT  35.388 60.419 35.406 60.456 ;
    END
  END b[319]
  PIN b[31]
    DIRECTION OUTPUT ;
    USE SIGNAL ;
    PORT
      LAYER M3 ;
        RECT  23.868 60.419 23.886 60.456 ;
    END
  END b[31]
  PIN b[320]
    DIRECTION OUTPUT ;
    USE SIGNAL ;
    PORT
      LAYER M3 ;
        RECT  38.34 60.419 38.358 60.456 ;
    END
  END b[320]
  PIN b[321]
    DIRECTION OUTPUT ;
    USE SIGNAL ;
    PORT
      LAYER M3 ;
        RECT  38.412 60.419 38.43 60.456 ;
    END
  END b[321]
  PIN b[322]
    DIRECTION OUTPUT ;
    USE SIGNAL ;
    PORT
      LAYER M3 ;
        RECT  38.484 60.419 38.502 60.456 ;
    END
  END b[322]
  PIN b[323]
    DIRECTION OUTPUT ;
    USE SIGNAL ;
    PORT
      LAYER M3 ;
        RECT  38.556 60.419 38.574 60.456 ;
    END
  END b[323]
  PIN b[324]
    DIRECTION OUTPUT ;
    USE SIGNAL ;
    PORT
      LAYER M3 ;
        RECT  38.628 60.419 38.646 60.456 ;
    END
  END b[324]
  PIN b[325]
    DIRECTION OUTPUT ;
    USE SIGNAL ;
    PORT
      LAYER M3 ;
        RECT  38.7 60.419 38.718 60.456 ;
    END
  END b[325]
  PIN b[326]
    DIRECTION OUTPUT ;
    USE SIGNAL ;
    PORT
      LAYER M3 ;
        RECT  38.772 60.419 38.79 60.456 ;
    END
  END b[326]
  PIN b[327]
    DIRECTION OUTPUT ;
    USE SIGNAL ;
    PORT
      LAYER M3 ;
        RECT  38.844 60.419 38.862 60.456 ;
    END
  END b[327]
  PIN b[328]
    DIRECTION OUTPUT ;
    USE SIGNAL ;
    PORT
      LAYER M3 ;
        RECT  38.916 60.419 38.934 60.456 ;
    END
  END b[328]
  PIN b[329]
    DIRECTION OUTPUT ;
    USE SIGNAL ;
    PORT
      LAYER M3 ;
        RECT  38.988 60.419 39.006 60.456 ;
    END
  END b[329]
  PIN b[32]
    DIRECTION OUTPUT ;
    USE SIGNAL ;
    PORT
      LAYER M3 ;
        RECT  23.94 60.419 23.958 60.456 ;
    END
  END b[32]
  PIN b[330]
    DIRECTION OUTPUT ;
    USE SIGNAL ;
    PORT
      LAYER M3 ;
        RECT  39.06 60.419 39.078 60.456 ;
    END
  END b[330]
  PIN b[331]
    DIRECTION OUTPUT ;
    USE SIGNAL ;
    PORT
      LAYER M3 ;
        RECT  39.132 60.419 39.15 60.456 ;
    END
  END b[331]
  PIN b[332]
    DIRECTION OUTPUT ;
    USE SIGNAL ;
    PORT
      LAYER M3 ;
        RECT  39.204 60.419 39.222 60.456 ;
    END
  END b[332]
  PIN b[333]
    DIRECTION OUTPUT ;
    USE SIGNAL ;
    PORT
      LAYER M3 ;
        RECT  39.276 60.419 39.294 60.456 ;
    END
  END b[333]
  PIN b[334]
    DIRECTION OUTPUT ;
    USE SIGNAL ;
    PORT
      LAYER M3 ;
        RECT  39.348 60.419 39.366 60.456 ;
    END
  END b[334]
  PIN b[335]
    DIRECTION OUTPUT ;
    USE SIGNAL ;
    PORT
      LAYER M3 ;
        RECT  39.42 60.419 39.438 60.456 ;
    END
  END b[335]
  PIN b[336]
    DIRECTION OUTPUT ;
    USE SIGNAL ;
    PORT
      LAYER M3 ;
        RECT  39.492 60.419 39.51 60.456 ;
    END
  END b[336]
  PIN b[337]
    DIRECTION OUTPUT ;
    USE SIGNAL ;
    PORT
      LAYER M3 ;
        RECT  39.564 60.419 39.582 60.456 ;
    END
  END b[337]
  PIN b[338]
    DIRECTION OUTPUT ;
    USE SIGNAL ;
    PORT
      LAYER M3 ;
        RECT  39.636 60.419 39.654 60.456 ;
    END
  END b[338]
  PIN b[339]
    DIRECTION OUTPUT ;
    USE SIGNAL ;
    PORT
      LAYER M3 ;
        RECT  39.708 60.419 39.726 60.456 ;
    END
  END b[339]
  PIN b[33]
    DIRECTION OUTPUT ;
    USE SIGNAL ;
    PORT
      LAYER M3 ;
        RECT  24.012 60.419 24.03 60.456 ;
    END
  END b[33]
  PIN b[340]
    DIRECTION OUTPUT ;
    USE SIGNAL ;
    PORT
      LAYER M3 ;
        RECT  39.78 60.419 39.798 60.456 ;
    END
  END b[340]
  PIN b[341]
    DIRECTION OUTPUT ;
    USE SIGNAL ;
    PORT
      LAYER M3 ;
        RECT  39.852 60.419 39.87 60.456 ;
    END
  END b[341]
  PIN b[342]
    DIRECTION OUTPUT ;
    USE SIGNAL ;
    PORT
      LAYER M3 ;
        RECT  39.924 60.419 39.942 60.456 ;
    END
  END b[342]
  PIN b[343]
    DIRECTION OUTPUT ;
    USE SIGNAL ;
    PORT
      LAYER M3 ;
        RECT  39.996 60.419 40.014 60.456 ;
    END
  END b[343]
  PIN b[344]
    DIRECTION OUTPUT ;
    USE SIGNAL ;
    PORT
      LAYER M3 ;
        RECT  40.068 60.419 40.086 60.456 ;
    END
  END b[344]
  PIN b[345]
    DIRECTION OUTPUT ;
    USE SIGNAL ;
    PORT
      LAYER M3 ;
        RECT  40.14 60.419 40.158 60.456 ;
    END
  END b[345]
  PIN b[346]
    DIRECTION OUTPUT ;
    USE SIGNAL ;
    PORT
      LAYER M3 ;
        RECT  40.212 60.419 40.23 60.456 ;
    END
  END b[346]
  PIN b[347]
    DIRECTION OUTPUT ;
    USE SIGNAL ;
    PORT
      LAYER M3 ;
        RECT  40.284 60.419 40.302 60.456 ;
    END
  END b[347]
  PIN b[348]
    DIRECTION OUTPUT ;
    USE SIGNAL ;
    PORT
      LAYER M3 ;
        RECT  40.356 60.419 40.374 60.456 ;
    END
  END b[348]
  PIN b[349]
    DIRECTION OUTPUT ;
    USE SIGNAL ;
    PORT
      LAYER M3 ;
        RECT  40.428 60.419 40.446 60.456 ;
    END
  END b[349]
  PIN b[34]
    DIRECTION OUTPUT ;
    USE SIGNAL ;
    PORT
      LAYER M3 ;
        RECT  24.084 60.419 24.102 60.456 ;
    END
  END b[34]
  PIN b[350]
    DIRECTION OUTPUT ;
    USE SIGNAL ;
    PORT
      LAYER M3 ;
        RECT  40.5 60.419 40.518 60.456 ;
    END
  END b[350]
  PIN b[351]
    DIRECTION OUTPUT ;
    USE SIGNAL ;
    PORT
      LAYER M3 ;
        RECT  40.572 60.419 40.59 60.456 ;
    END
  END b[351]
  PIN b[352]
    DIRECTION OUTPUT ;
    USE SIGNAL ;
    PORT
      LAYER M3 ;
        RECT  28.548 60.419 28.566 60.456 ;
    END
  END b[352]
  PIN b[353]
    DIRECTION OUTPUT ;
    USE SIGNAL ;
    PORT
      LAYER M3 ;
        RECT  28.62 60.419 28.638 60.456 ;
    END
  END b[353]
  PIN b[354]
    DIRECTION OUTPUT ;
    USE SIGNAL ;
    PORT
      LAYER M3 ;
        RECT  28.692 60.419 28.71 60.456 ;
    END
  END b[354]
  PIN b[355]
    DIRECTION OUTPUT ;
    USE SIGNAL ;
    PORT
      LAYER M3 ;
        RECT  28.764 60.419 28.782 60.456 ;
    END
  END b[355]
  PIN b[356]
    DIRECTION OUTPUT ;
    USE SIGNAL ;
    PORT
      LAYER M3 ;
        RECT  28.836 60.419 28.854 60.456 ;
    END
  END b[356]
  PIN b[357]
    DIRECTION OUTPUT ;
    USE SIGNAL ;
    PORT
      LAYER M3 ;
        RECT  28.908 60.419 28.926 60.456 ;
    END
  END b[357]
  PIN b[358]
    DIRECTION OUTPUT ;
    USE SIGNAL ;
    PORT
      LAYER M3 ;
        RECT  28.98 60.419 28.998 60.456 ;
    END
  END b[358]
  PIN b[359]
    DIRECTION OUTPUT ;
    USE SIGNAL ;
    PORT
      LAYER M3 ;
        RECT  29.052 60.419 29.07 60.456 ;
    END
  END b[359]
  PIN b[35]
    DIRECTION OUTPUT ;
    USE SIGNAL ;
    PORT
      LAYER M3 ;
        RECT  24.156 60.419 24.174 60.456 ;
    END
  END b[35]
  PIN b[360]
    DIRECTION OUTPUT ;
    USE SIGNAL ;
    PORT
      LAYER M3 ;
        RECT  29.124 60.419 29.142 60.456 ;
    END
  END b[360]
  PIN b[361]
    DIRECTION OUTPUT ;
    USE SIGNAL ;
    PORT
      LAYER M3 ;
        RECT  29.196 60.419 29.214 60.456 ;
    END
  END b[361]
  PIN b[362]
    DIRECTION OUTPUT ;
    USE SIGNAL ;
    PORT
      LAYER M3 ;
        RECT  29.268 60.419 29.286 60.456 ;
    END
  END b[362]
  PIN b[363]
    DIRECTION OUTPUT ;
    USE SIGNAL ;
    PORT
      LAYER M3 ;
        RECT  29.34 60.419 29.358 60.456 ;
    END
  END b[363]
  PIN b[364]
    DIRECTION OUTPUT ;
    USE SIGNAL ;
    PORT
      LAYER M3 ;
        RECT  29.412 60.419 29.43 60.456 ;
    END
  END b[364]
  PIN b[365]
    DIRECTION OUTPUT ;
    USE SIGNAL ;
    PORT
      LAYER M3 ;
        RECT  29.484 60.419 29.502 60.456 ;
    END
  END b[365]
  PIN b[366]
    DIRECTION OUTPUT ;
    USE SIGNAL ;
    PORT
      LAYER M3 ;
        RECT  29.556 60.419 29.574 60.456 ;
    END
  END b[366]
  PIN b[367]
    DIRECTION OUTPUT ;
    USE SIGNAL ;
    PORT
      LAYER M3 ;
        RECT  29.628 60.419 29.646 60.456 ;
    END
  END b[367]
  PIN b[368]
    DIRECTION OUTPUT ;
    USE SIGNAL ;
    PORT
      LAYER M3 ;
        RECT  29.7 60.419 29.718 60.456 ;
    END
  END b[368]
  PIN b[369]
    DIRECTION OUTPUT ;
    USE SIGNAL ;
    PORT
      LAYER M3 ;
        RECT  29.772 60.419 29.79 60.456 ;
    END
  END b[369]
  PIN b[36]
    DIRECTION OUTPUT ;
    USE SIGNAL ;
    PORT
      LAYER M3 ;
        RECT  24.228 60.419 24.246 60.456 ;
    END
  END b[36]
  PIN b[370]
    DIRECTION OUTPUT ;
    USE SIGNAL ;
    PORT
      LAYER M3 ;
        RECT  29.844 60.419 29.862 60.456 ;
    END
  END b[370]
  PIN b[371]
    DIRECTION OUTPUT ;
    USE SIGNAL ;
    PORT
      LAYER M3 ;
        RECT  29.916 60.419 29.934 60.456 ;
    END
  END b[371]
  PIN b[372]
    DIRECTION OUTPUT ;
    USE SIGNAL ;
    PORT
      LAYER M3 ;
        RECT  29.988 60.419 30.006 60.456 ;
    END
  END b[372]
  PIN b[373]
    DIRECTION OUTPUT ;
    USE SIGNAL ;
    PORT
      LAYER M3 ;
        RECT  30.06 60.419 30.078 60.456 ;
    END
  END b[373]
  PIN b[374]
    DIRECTION OUTPUT ;
    USE SIGNAL ;
    PORT
      LAYER M3 ;
        RECT  30.132 60.419 30.15 60.456 ;
    END
  END b[374]
  PIN b[375]
    DIRECTION OUTPUT ;
    USE SIGNAL ;
    PORT
      LAYER M3 ;
        RECT  30.204 60.419 30.222 60.456 ;
    END
  END b[375]
  PIN b[376]
    DIRECTION OUTPUT ;
    USE SIGNAL ;
    PORT
      LAYER M3 ;
        RECT  30.276 60.419 30.294 60.456 ;
    END
  END b[376]
  PIN b[377]
    DIRECTION OUTPUT ;
    USE SIGNAL ;
    PORT
      LAYER M3 ;
        RECT  30.348 60.419 30.366 60.456 ;
    END
  END b[377]
  PIN b[378]
    DIRECTION OUTPUT ;
    USE SIGNAL ;
    PORT
      LAYER M3 ;
        RECT  30.42 60.419 30.438 60.456 ;
    END
  END b[378]
  PIN b[379]
    DIRECTION OUTPUT ;
    USE SIGNAL ;
    PORT
      LAYER M3 ;
        RECT  30.492 60.419 30.51 60.456 ;
    END
  END b[379]
  PIN b[37]
    DIRECTION OUTPUT ;
    USE SIGNAL ;
    PORT
      LAYER M3 ;
        RECT  24.3 60.419 24.318 60.456 ;
    END
  END b[37]
  PIN b[380]
    DIRECTION OUTPUT ;
    USE SIGNAL ;
    PORT
      LAYER M3 ;
        RECT  30.564 60.419 30.582 60.456 ;
    END
  END b[380]
  PIN b[381]
    DIRECTION OUTPUT ;
    USE SIGNAL ;
    PORT
      LAYER M3 ;
        RECT  30.636 60.419 30.654 60.456 ;
    END
  END b[381]
  PIN b[382]
    DIRECTION OUTPUT ;
    USE SIGNAL ;
    PORT
      LAYER M3 ;
        RECT  30.708 60.419 30.726 60.456 ;
    END
  END b[382]
  PIN b[383]
    DIRECTION OUTPUT ;
    USE SIGNAL ;
    PORT
      LAYER M3 ;
        RECT  30.78 60.419 30.798 60.456 ;
    END
  END b[383]
  PIN b[384]
    DIRECTION OUTPUT ;
    USE SIGNAL ;
    PORT
      LAYER M3 ;
        RECT  30.852 60.419 30.87 60.456 ;
    END
  END b[384]
  PIN b[385]
    DIRECTION OUTPUT ;
    USE SIGNAL ;
    PORT
      LAYER M3 ;
        RECT  30.924 60.419 30.942 60.456 ;
    END
  END b[385]
  PIN b[386]
    DIRECTION OUTPUT ;
    USE SIGNAL ;
    PORT
      LAYER M3 ;
        RECT  30.996 60.419 31.014 60.456 ;
    END
  END b[386]
  PIN b[387]
    DIRECTION OUTPUT ;
    USE SIGNAL ;
    PORT
      LAYER M3 ;
        RECT  31.068 60.419 31.086 60.456 ;
    END
  END b[387]
  PIN b[388]
    DIRECTION OUTPUT ;
    USE SIGNAL ;
    PORT
      LAYER M3 ;
        RECT  31.14 60.419 31.158 60.456 ;
    END
  END b[388]
  PIN b[389]
    DIRECTION OUTPUT ;
    USE SIGNAL ;
    PORT
      LAYER M3 ;
        RECT  31.212 60.419 31.23 60.456 ;
    END
  END b[389]
  PIN b[38]
    DIRECTION OUTPUT ;
    USE SIGNAL ;
    PORT
      LAYER M3 ;
        RECT  24.372 60.419 24.39 60.456 ;
    END
  END b[38]
  PIN b[390]
    DIRECTION OUTPUT ;
    USE SIGNAL ;
    PORT
      LAYER M3 ;
        RECT  31.284 60.419 31.302 60.456 ;
    END
  END b[390]
  PIN b[391]
    DIRECTION OUTPUT ;
    USE SIGNAL ;
    PORT
      LAYER M3 ;
        RECT  31.356 60.419 31.374 60.456 ;
    END
  END b[391]
  PIN b[392]
    DIRECTION OUTPUT ;
    USE SIGNAL ;
    PORT
      LAYER M3 ;
        RECT  31.428 60.419 31.446 60.456 ;
    END
  END b[392]
  PIN b[393]
    DIRECTION OUTPUT ;
    USE SIGNAL ;
    PORT
      LAYER M3 ;
        RECT  31.5 60.419 31.518 60.456 ;
    END
  END b[393]
  PIN b[394]
    DIRECTION OUTPUT ;
    USE SIGNAL ;
    PORT
      LAYER M3 ;
        RECT  31.572 60.419 31.59 60.456 ;
    END
  END b[394]
  PIN b[395]
    DIRECTION OUTPUT ;
    USE SIGNAL ;
    PORT
      LAYER M3 ;
        RECT  31.644 60.419 31.662 60.456 ;
    END
  END b[395]
  PIN b[396]
    DIRECTION OUTPUT ;
    USE SIGNAL ;
    PORT
      LAYER M3 ;
        RECT  31.716 60.419 31.734 60.456 ;
    END
  END b[396]
  PIN b[397]
    DIRECTION OUTPUT ;
    USE SIGNAL ;
    PORT
      LAYER M3 ;
        RECT  31.788 60.419 31.806 60.456 ;
    END
  END b[397]
  PIN b[398]
    DIRECTION OUTPUT ;
    USE SIGNAL ;
    PORT
      LAYER M3 ;
        RECT  31.86 60.419 31.878 60.456 ;
    END
  END b[398]
  PIN b[399]
    DIRECTION OUTPUT ;
    USE SIGNAL ;
    PORT
      LAYER M3 ;
        RECT  31.932 60.419 31.95 60.456 ;
    END
  END b[399]
  PIN b[39]
    DIRECTION OUTPUT ;
    USE SIGNAL ;
    PORT
      LAYER M3 ;
        RECT  24.444 60.419 24.462 60.456 ;
    END
  END b[39]
  PIN b[3]
    DIRECTION OUTPUT ;
    USE SIGNAL ;
    PORT
      LAYER M3 ;
        RECT  21.852 60.419 21.87 60.456 ;
    END
  END b[3]
  PIN b[400]
    DIRECTION OUTPUT ;
    USE SIGNAL ;
    PORT
      LAYER M3 ;
        RECT  32.004 60.419 32.022 60.456 ;
    END
  END b[400]
  PIN b[401]
    DIRECTION OUTPUT ;
    USE SIGNAL ;
    PORT
      LAYER M3 ;
        RECT  32.076 60.419 32.094 60.456 ;
    END
  END b[401]
  PIN b[402]
    DIRECTION OUTPUT ;
    USE SIGNAL ;
    PORT
      LAYER M3 ;
        RECT  32.148 60.419 32.166 60.456 ;
    END
  END b[402]
  PIN b[403]
    DIRECTION OUTPUT ;
    USE SIGNAL ;
    PORT
      LAYER M3 ;
        RECT  32.22 60.419 32.238 60.456 ;
    END
  END b[403]
  PIN b[404]
    DIRECTION OUTPUT ;
    USE SIGNAL ;
    PORT
      LAYER M3 ;
        RECT  32.292 60.419 32.31 60.456 ;
    END
  END b[404]
  PIN b[405]
    DIRECTION OUTPUT ;
    USE SIGNAL ;
    PORT
      LAYER M3 ;
        RECT  32.364 60.419 32.382 60.456 ;
    END
  END b[405]
  PIN b[406]
    DIRECTION OUTPUT ;
    USE SIGNAL ;
    PORT
      LAYER M3 ;
        RECT  32.436 60.419 32.454 60.456 ;
    END
  END b[406]
  PIN b[407]
    DIRECTION OUTPUT ;
    USE SIGNAL ;
    PORT
      LAYER M3 ;
        RECT  32.508 60.419 32.526 60.456 ;
    END
  END b[407]
  PIN b[408]
    DIRECTION OUTPUT ;
    USE SIGNAL ;
    PORT
      LAYER M3 ;
        RECT  32.58 60.419 32.598 60.456 ;
    END
  END b[408]
  PIN b[409]
    DIRECTION OUTPUT ;
    USE SIGNAL ;
    PORT
      LAYER M3 ;
        RECT  32.652 60.419 32.67 60.456 ;
    END
  END b[409]
  PIN b[40]
    DIRECTION OUTPUT ;
    USE SIGNAL ;
    PORT
      LAYER M3 ;
        RECT  24.516 60.419 24.534 60.456 ;
    END
  END b[40]
  PIN b[410]
    DIRECTION OUTPUT ;
    USE SIGNAL ;
    PORT
      LAYER M3 ;
        RECT  32.724 60.419 32.742 60.456 ;
    END
  END b[410]
  PIN b[411]
    DIRECTION OUTPUT ;
    USE SIGNAL ;
    PORT
      LAYER M3 ;
        RECT  32.796 60.419 32.814 60.456 ;
    END
  END b[411]
  PIN b[412]
    DIRECTION OUTPUT ;
    USE SIGNAL ;
    PORT
      LAYER M3 ;
        RECT  32.868 60.419 32.886 60.456 ;
    END
  END b[412]
  PIN b[413]
    DIRECTION OUTPUT ;
    USE SIGNAL ;
    PORT
      LAYER M3 ;
        RECT  32.94 60.419 32.958 60.456 ;
    END
  END b[413]
  PIN b[414]
    DIRECTION OUTPUT ;
    USE SIGNAL ;
    PORT
      LAYER M3 ;
        RECT  33.012 60.419 33.03 60.456 ;
    END
  END b[414]
  PIN b[415]
    DIRECTION OUTPUT ;
    USE SIGNAL ;
    PORT
      LAYER M3 ;
        RECT  33.084 60.419 33.102 60.456 ;
    END
  END b[415]
  PIN b[416]
    DIRECTION OUTPUT ;
    USE SIGNAL ;
    PORT
      LAYER M3 ;
        RECT  45.252 60.419 45.27 60.456 ;
    END
  END b[416]
  PIN b[417]
    DIRECTION OUTPUT ;
    USE SIGNAL ;
    PORT
      LAYER M3 ;
        RECT  45.324 60.419 45.342 60.456 ;
    END
  END b[417]
  PIN b[418]
    DIRECTION OUTPUT ;
    USE SIGNAL ;
    PORT
      LAYER M3 ;
        RECT  45.396 60.419 45.414 60.456 ;
    END
  END b[418]
  PIN b[419]
    DIRECTION OUTPUT ;
    USE SIGNAL ;
    PORT
      LAYER M3 ;
        RECT  45.468 60.419 45.486 60.456 ;
    END
  END b[419]
  PIN b[41]
    DIRECTION OUTPUT ;
    USE SIGNAL ;
    PORT
      LAYER M3 ;
        RECT  24.588 60.419 24.606 60.456 ;
    END
  END b[41]
  PIN b[420]
    DIRECTION OUTPUT ;
    USE SIGNAL ;
    PORT
      LAYER M3 ;
        RECT  45.54 60.419 45.558 60.456 ;
    END
  END b[420]
  PIN b[421]
    DIRECTION OUTPUT ;
    USE SIGNAL ;
    PORT
      LAYER M3 ;
        RECT  45.612 60.419 45.63 60.456 ;
    END
  END b[421]
  PIN b[422]
    DIRECTION OUTPUT ;
    USE SIGNAL ;
    PORT
      LAYER M3 ;
        RECT  45.684 60.419 45.702 60.456 ;
    END
  END b[422]
  PIN b[423]
    DIRECTION OUTPUT ;
    USE SIGNAL ;
    PORT
      LAYER M3 ;
        RECT  45.756 60.419 45.774 60.456 ;
    END
  END b[423]
  PIN b[424]
    DIRECTION OUTPUT ;
    USE SIGNAL ;
    PORT
      LAYER M3 ;
        RECT  45.828 60.419 45.846 60.456 ;
    END
  END b[424]
  PIN b[425]
    DIRECTION OUTPUT ;
    USE SIGNAL ;
    PORT
      LAYER M3 ;
        RECT  45.9 60.419 45.918 60.456 ;
    END
  END b[425]
  PIN b[426]
    DIRECTION OUTPUT ;
    USE SIGNAL ;
    PORT
      LAYER M3 ;
        RECT  45.972 60.419 45.99 60.456 ;
    END
  END b[426]
  PIN b[427]
    DIRECTION OUTPUT ;
    USE SIGNAL ;
    PORT
      LAYER M3 ;
        RECT  46.044 60.419 46.062 60.456 ;
    END
  END b[427]
  PIN b[428]
    DIRECTION OUTPUT ;
    USE SIGNAL ;
    PORT
      LAYER M3 ;
        RECT  46.116 60.419 46.134 60.456 ;
    END
  END b[428]
  PIN b[429]
    DIRECTION OUTPUT ;
    USE SIGNAL ;
    PORT
      LAYER M3 ;
        RECT  46.188 60.419 46.206 60.456 ;
    END
  END b[429]
  PIN b[42]
    DIRECTION OUTPUT ;
    USE SIGNAL ;
    PORT
      LAYER M3 ;
        RECT  24.66 60.419 24.678 60.456 ;
    END
  END b[42]
  PIN b[430]
    DIRECTION OUTPUT ;
    USE SIGNAL ;
    PORT
      LAYER M3 ;
        RECT  46.26 60.419 46.278 60.456 ;
    END
  END b[430]
  PIN b[431]
    DIRECTION OUTPUT ;
    USE SIGNAL ;
    PORT
      LAYER M3 ;
        RECT  46.332 60.419 46.35 60.456 ;
    END
  END b[431]
  PIN b[432]
    DIRECTION OUTPUT ;
    USE SIGNAL ;
    PORT
      LAYER M3 ;
        RECT  46.404 60.419 46.422 60.456 ;
    END
  END b[432]
  PIN b[433]
    DIRECTION OUTPUT ;
    USE SIGNAL ;
    PORT
      LAYER M3 ;
        RECT  46.476 60.419 46.494 60.456 ;
    END
  END b[433]
  PIN b[434]
    DIRECTION OUTPUT ;
    USE SIGNAL ;
    PORT
      LAYER M3 ;
        RECT  46.548 60.419 46.566 60.456 ;
    END
  END b[434]
  PIN b[435]
    DIRECTION OUTPUT ;
    USE SIGNAL ;
    PORT
      LAYER M3 ;
        RECT  46.62 60.419 46.638 60.456 ;
    END
  END b[435]
  PIN b[436]
    DIRECTION OUTPUT ;
    USE SIGNAL ;
    PORT
      LAYER M3 ;
        RECT  46.692 60.419 46.71 60.456 ;
    END
  END b[436]
  PIN b[437]
    DIRECTION OUTPUT ;
    USE SIGNAL ;
    PORT
      LAYER M3 ;
        RECT  46.764 60.419 46.782 60.456 ;
    END
  END b[437]
  PIN b[438]
    DIRECTION OUTPUT ;
    USE SIGNAL ;
    PORT
      LAYER M3 ;
        RECT  46.836 60.419 46.854 60.456 ;
    END
  END b[438]
  PIN b[439]
    DIRECTION OUTPUT ;
    USE SIGNAL ;
    PORT
      LAYER M3 ;
        RECT  46.908 60.419 46.926 60.456 ;
    END
  END b[439]
  PIN b[43]
    DIRECTION OUTPUT ;
    USE SIGNAL ;
    PORT
      LAYER M3 ;
        RECT  24.732 60.419 24.75 60.456 ;
    END
  END b[43]
  PIN b[440]
    DIRECTION OUTPUT ;
    USE SIGNAL ;
    PORT
      LAYER M3 ;
        RECT  46.98 60.419 46.998 60.456 ;
    END
  END b[440]
  PIN b[441]
    DIRECTION OUTPUT ;
    USE SIGNAL ;
    PORT
      LAYER M3 ;
        RECT  47.052 60.419 47.07 60.456 ;
    END
  END b[441]
  PIN b[442]
    DIRECTION OUTPUT ;
    USE SIGNAL ;
    PORT
      LAYER M3 ;
        RECT  47.124 60.419 47.142 60.456 ;
    END
  END b[442]
  PIN b[443]
    DIRECTION OUTPUT ;
    USE SIGNAL ;
    PORT
      LAYER M3 ;
        RECT  47.196 60.419 47.214 60.456 ;
    END
  END b[443]
  PIN b[444]
    DIRECTION OUTPUT ;
    USE SIGNAL ;
    PORT
      LAYER M3 ;
        RECT  47.268 60.419 47.286 60.456 ;
    END
  END b[444]
  PIN b[445]
    DIRECTION OUTPUT ;
    USE SIGNAL ;
    PORT
      LAYER M3 ;
        RECT  47.34 60.419 47.358 60.456 ;
    END
  END b[445]
  PIN b[446]
    DIRECTION OUTPUT ;
    USE SIGNAL ;
    PORT
      LAYER M3 ;
        RECT  47.412 60.419 47.43 60.456 ;
    END
  END b[446]
  PIN b[447]
    DIRECTION OUTPUT ;
    USE SIGNAL ;
    PORT
      LAYER M3 ;
        RECT  47.484 60.419 47.502 60.456 ;
    END
  END b[447]
  PIN b[448]
    DIRECTION OUTPUT ;
    USE SIGNAL ;
    PORT
      LAYER M3 ;
        RECT  36.036 60.419 36.054 60.456 ;
    END
  END b[448]
  PIN b[449]
    DIRECTION OUTPUT ;
    USE SIGNAL ;
    PORT
      LAYER M3 ;
        RECT  36.108 60.419 36.126 60.456 ;
    END
  END b[449]
  PIN b[44]
    DIRECTION OUTPUT ;
    USE SIGNAL ;
    PORT
      LAYER M3 ;
        RECT  24.804 60.419 24.822 60.456 ;
    END
  END b[44]
  PIN b[450]
    DIRECTION OUTPUT ;
    USE SIGNAL ;
    PORT
      LAYER M3 ;
        RECT  36.18 60.419 36.198 60.456 ;
    END
  END b[450]
  PIN b[451]
    DIRECTION OUTPUT ;
    USE SIGNAL ;
    PORT
      LAYER M3 ;
        RECT  36.252 60.419 36.27 60.456 ;
    END
  END b[451]
  PIN b[452]
    DIRECTION OUTPUT ;
    USE SIGNAL ;
    PORT
      LAYER M3 ;
        RECT  36.324 60.419 36.342 60.456 ;
    END
  END b[452]
  PIN b[453]
    DIRECTION OUTPUT ;
    USE SIGNAL ;
    PORT
      LAYER M3 ;
        RECT  36.396 60.419 36.414 60.456 ;
    END
  END b[453]
  PIN b[454]
    DIRECTION OUTPUT ;
    USE SIGNAL ;
    PORT
      LAYER M3 ;
        RECT  36.468 60.419 36.486 60.456 ;
    END
  END b[454]
  PIN b[455]
    DIRECTION OUTPUT ;
    USE SIGNAL ;
    PORT
      LAYER M3 ;
        RECT  36.54 60.419 36.558 60.456 ;
    END
  END b[455]
  PIN b[456]
    DIRECTION OUTPUT ;
    USE SIGNAL ;
    PORT
      LAYER M3 ;
        RECT  36.612 60.419 36.63 60.456 ;
    END
  END b[456]
  PIN b[457]
    DIRECTION OUTPUT ;
    USE SIGNAL ;
    PORT
      LAYER M3 ;
        RECT  36.684 60.419 36.702 60.456 ;
    END
  END b[457]
  PIN b[458]
    DIRECTION OUTPUT ;
    USE SIGNAL ;
    PORT
      LAYER M3 ;
        RECT  36.756 60.419 36.774 60.456 ;
    END
  END b[458]
  PIN b[459]
    DIRECTION OUTPUT ;
    USE SIGNAL ;
    PORT
      LAYER M3 ;
        RECT  36.828 60.419 36.846 60.456 ;
    END
  END b[459]
  PIN b[45]
    DIRECTION OUTPUT ;
    USE SIGNAL ;
    PORT
      LAYER M3 ;
        RECT  24.876 60.419 24.894 60.456 ;
    END
  END b[45]
  PIN b[460]
    DIRECTION OUTPUT ;
    USE SIGNAL ;
    PORT
      LAYER M3 ;
        RECT  36.9 60.419 36.918 60.456 ;
    END
  END b[460]
  PIN b[461]
    DIRECTION OUTPUT ;
    USE SIGNAL ;
    PORT
      LAYER M3 ;
        RECT  36.972 60.419 36.99 60.456 ;
    END
  END b[461]
  PIN b[462]
    DIRECTION OUTPUT ;
    USE SIGNAL ;
    PORT
      LAYER M3 ;
        RECT  37.044 60.419 37.062 60.456 ;
    END
  END b[462]
  PIN b[463]
    DIRECTION OUTPUT ;
    USE SIGNAL ;
    PORT
      LAYER M3 ;
        RECT  37.116 60.419 37.134 60.456 ;
    END
  END b[463]
  PIN b[464]
    DIRECTION OUTPUT ;
    USE SIGNAL ;
    PORT
      LAYER M3 ;
        RECT  37.188 60.419 37.206 60.456 ;
    END
  END b[464]
  PIN b[465]
    DIRECTION OUTPUT ;
    USE SIGNAL ;
    PORT
      LAYER M3 ;
        RECT  37.26 60.419 37.278 60.456 ;
    END
  END b[465]
  PIN b[466]
    DIRECTION OUTPUT ;
    USE SIGNAL ;
    PORT
      LAYER M3 ;
        RECT  37.332 60.419 37.35 60.456 ;
    END
  END b[466]
  PIN b[467]
    DIRECTION OUTPUT ;
    USE SIGNAL ;
    PORT
      LAYER M3 ;
        RECT  37.404 60.419 37.422 60.456 ;
    END
  END b[467]
  PIN b[468]
    DIRECTION OUTPUT ;
    USE SIGNAL ;
    PORT
      LAYER M3 ;
        RECT  37.476 60.419 37.494 60.456 ;
    END
  END b[468]
  PIN b[469]
    DIRECTION OUTPUT ;
    USE SIGNAL ;
    PORT
      LAYER M3 ;
        RECT  37.548 60.419 37.566 60.456 ;
    END
  END b[469]
  PIN b[46]
    DIRECTION OUTPUT ;
    USE SIGNAL ;
    PORT
      LAYER M3 ;
        RECT  24.948 60.419 24.966 60.456 ;
    END
  END b[46]
  PIN b[470]
    DIRECTION OUTPUT ;
    USE SIGNAL ;
    PORT
      LAYER M3 ;
        RECT  37.62 60.419 37.638 60.456 ;
    END
  END b[470]
  PIN b[471]
    DIRECTION OUTPUT ;
    USE SIGNAL ;
    PORT
      LAYER M3 ;
        RECT  37.692 60.419 37.71 60.456 ;
    END
  END b[471]
  PIN b[472]
    DIRECTION OUTPUT ;
    USE SIGNAL ;
    PORT
      LAYER M3 ;
        RECT  37.764 60.419 37.782 60.456 ;
    END
  END b[472]
  PIN b[473]
    DIRECTION OUTPUT ;
    USE SIGNAL ;
    PORT
      LAYER M3 ;
        RECT  37.836 60.419 37.854 60.456 ;
    END
  END b[473]
  PIN b[474]
    DIRECTION OUTPUT ;
    USE SIGNAL ;
    PORT
      LAYER M3 ;
        RECT  37.908 60.419 37.926 60.456 ;
    END
  END b[474]
  PIN b[475]
    DIRECTION OUTPUT ;
    USE SIGNAL ;
    PORT
      LAYER M3 ;
        RECT  37.98 60.419 37.998 60.456 ;
    END
  END b[475]
  PIN b[476]
    DIRECTION OUTPUT ;
    USE SIGNAL ;
    PORT
      LAYER M3 ;
        RECT  38.052 60.419 38.07 60.456 ;
    END
  END b[476]
  PIN b[477]
    DIRECTION OUTPUT ;
    USE SIGNAL ;
    PORT
      LAYER M3 ;
        RECT  38.124 60.419 38.142 60.456 ;
    END
  END b[477]
  PIN b[478]
    DIRECTION OUTPUT ;
    USE SIGNAL ;
    PORT
      LAYER M3 ;
        RECT  38.196 60.419 38.214 60.456 ;
    END
  END b[478]
  PIN b[479]
    DIRECTION OUTPUT ;
    USE SIGNAL ;
    PORT
      LAYER M3 ;
        RECT  38.268 60.419 38.286 60.456 ;
    END
  END b[479]
  PIN b[47]
    DIRECTION OUTPUT ;
    USE SIGNAL ;
    PORT
      LAYER M3 ;
        RECT  25.02 60.419 25.038 60.456 ;
    END
  END b[47]
  PIN b[480]
    DIRECTION OUTPUT ;
    USE SIGNAL ;
    PORT
      LAYER M3 ;
        RECT  42.948 60.419 42.966 60.456 ;
    END
  END b[480]
  PIN b[481]
    DIRECTION OUTPUT ;
    USE SIGNAL ;
    PORT
      LAYER M3 ;
        RECT  43.02 60.419 43.038 60.456 ;
    END
  END b[481]
  PIN b[482]
    DIRECTION OUTPUT ;
    USE SIGNAL ;
    PORT
      LAYER M3 ;
        RECT  43.092 60.419 43.11 60.456 ;
    END
  END b[482]
  PIN b[483]
    DIRECTION OUTPUT ;
    USE SIGNAL ;
    PORT
      LAYER M3 ;
        RECT  43.164 60.419 43.182 60.456 ;
    END
  END b[483]
  PIN b[484]
    DIRECTION OUTPUT ;
    USE SIGNAL ;
    PORT
      LAYER M3 ;
        RECT  43.236 60.419 43.254 60.456 ;
    END
  END b[484]
  PIN b[485]
    DIRECTION OUTPUT ;
    USE SIGNAL ;
    PORT
      LAYER M3 ;
        RECT  43.308 60.419 43.326 60.456 ;
    END
  END b[485]
  PIN b[486]
    DIRECTION OUTPUT ;
    USE SIGNAL ;
    PORT
      LAYER M3 ;
        RECT  43.38 60.419 43.398 60.456 ;
    END
  END b[486]
  PIN b[487]
    DIRECTION OUTPUT ;
    USE SIGNAL ;
    PORT
      LAYER M3 ;
        RECT  43.452 60.419 43.47 60.456 ;
    END
  END b[487]
  PIN b[488]
    DIRECTION OUTPUT ;
    USE SIGNAL ;
    PORT
      LAYER M3 ;
        RECT  43.524 60.419 43.542 60.456 ;
    END
  END b[488]
  PIN b[489]
    DIRECTION OUTPUT ;
    USE SIGNAL ;
    PORT
      LAYER M3 ;
        RECT  43.596 60.419 43.614 60.456 ;
    END
  END b[489]
  PIN b[48]
    DIRECTION OUTPUT ;
    USE SIGNAL ;
    PORT
      LAYER M3 ;
        RECT  25.092 60.419 25.11 60.456 ;
    END
  END b[48]
  PIN b[490]
    DIRECTION OUTPUT ;
    USE SIGNAL ;
    PORT
      LAYER M3 ;
        RECT  43.668 60.419 43.686 60.456 ;
    END
  END b[490]
  PIN b[491]
    DIRECTION OUTPUT ;
    USE SIGNAL ;
    PORT
      LAYER M3 ;
        RECT  43.74 60.419 43.758 60.456 ;
    END
  END b[491]
  PIN b[492]
    DIRECTION OUTPUT ;
    USE SIGNAL ;
    PORT
      LAYER M3 ;
        RECT  43.812 60.419 43.83 60.456 ;
    END
  END b[492]
  PIN b[493]
    DIRECTION OUTPUT ;
    USE SIGNAL ;
    PORT
      LAYER M3 ;
        RECT  43.884 60.419 43.902 60.456 ;
    END
  END b[493]
  PIN b[494]
    DIRECTION OUTPUT ;
    USE SIGNAL ;
    PORT
      LAYER M3 ;
        RECT  43.956 60.419 43.974 60.456 ;
    END
  END b[494]
  PIN b[495]
    DIRECTION OUTPUT ;
    USE SIGNAL ;
    PORT
      LAYER M3 ;
        RECT  44.028 60.419 44.046 60.456 ;
    END
  END b[495]
  PIN b[496]
    DIRECTION OUTPUT ;
    USE SIGNAL ;
    PORT
      LAYER M3 ;
        RECT  44.1 60.419 44.118 60.456 ;
    END
  END b[496]
  PIN b[497]
    DIRECTION OUTPUT ;
    USE SIGNAL ;
    PORT
      LAYER M3 ;
        RECT  44.172 60.419 44.19 60.456 ;
    END
  END b[497]
  PIN b[498]
    DIRECTION OUTPUT ;
    USE SIGNAL ;
    PORT
      LAYER M3 ;
        RECT  44.244 60.419 44.262 60.456 ;
    END
  END b[498]
  PIN b[499]
    DIRECTION OUTPUT ;
    USE SIGNAL ;
    PORT
      LAYER M3 ;
        RECT  44.316 60.419 44.334 60.456 ;
    END
  END b[499]
  PIN b[49]
    DIRECTION OUTPUT ;
    USE SIGNAL ;
    PORT
      LAYER M3 ;
        RECT  25.164 60.419 25.182 60.456 ;
    END
  END b[49]
  PIN b[4]
    DIRECTION OUTPUT ;
    USE SIGNAL ;
    PORT
      LAYER M3 ;
        RECT  21.924 60.419 21.942 60.456 ;
    END
  END b[4]
  PIN b[500]
    DIRECTION OUTPUT ;
    USE SIGNAL ;
    PORT
      LAYER M3 ;
        RECT  44.388 60.419 44.406 60.456 ;
    END
  END b[500]
  PIN b[501]
    DIRECTION OUTPUT ;
    USE SIGNAL ;
    PORT
      LAYER M3 ;
        RECT  44.46 60.419 44.478 60.456 ;
    END
  END b[501]
  PIN b[502]
    DIRECTION OUTPUT ;
    USE SIGNAL ;
    PORT
      LAYER M3 ;
        RECT  44.532 60.419 44.55 60.456 ;
    END
  END b[502]
  PIN b[503]
    DIRECTION OUTPUT ;
    USE SIGNAL ;
    PORT
      LAYER M3 ;
        RECT  44.604 60.419 44.622 60.456 ;
    END
  END b[503]
  PIN b[504]
    DIRECTION OUTPUT ;
    USE SIGNAL ;
    PORT
      LAYER M3 ;
        RECT  44.676 60.419 44.694 60.456 ;
    END
  END b[504]
  PIN b[505]
    DIRECTION OUTPUT ;
    USE SIGNAL ;
    PORT
      LAYER M3 ;
        RECT  44.748 60.419 44.766 60.456 ;
    END
  END b[505]
  PIN b[506]
    DIRECTION OUTPUT ;
    USE SIGNAL ;
    PORT
      LAYER M3 ;
        RECT  44.82 60.419 44.838 60.456 ;
    END
  END b[506]
  PIN b[507]
    DIRECTION OUTPUT ;
    USE SIGNAL ;
    PORT
      LAYER M3 ;
        RECT  44.892 60.419 44.91 60.456 ;
    END
  END b[507]
  PIN b[508]
    DIRECTION OUTPUT ;
    USE SIGNAL ;
    PORT
      LAYER M3 ;
        RECT  44.964 60.419 44.982 60.456 ;
    END
  END b[508]
  PIN b[509]
    DIRECTION OUTPUT ;
    USE SIGNAL ;
    PORT
      LAYER M3 ;
        RECT  45.036 60.419 45.054 60.456 ;
    END
  END b[509]
  PIN b[50]
    DIRECTION OUTPUT ;
    USE SIGNAL ;
    PORT
      LAYER M3 ;
        RECT  25.236 60.419 25.254 60.456 ;
    END
  END b[50]
  PIN b[510]
    DIRECTION OUTPUT ;
    USE SIGNAL ;
    PORT
      LAYER M3 ;
        RECT  45.108 60.419 45.126 60.456 ;
    END
  END b[510]
  PIN b[511]
    DIRECTION OUTPUT ;
    USE SIGNAL ;
    PORT
      LAYER M3 ;
        RECT  45.18 60.419 45.198 60.456 ;
    END
  END b[511]
  PIN b[512]
    DIRECTION OUTPUT ;
    USE SIGNAL ;
    PORT
      LAYER M3 ;
        RECT  40.644 60.419 40.662 60.456 ;
    END
  END b[512]
  PIN b[513]
    DIRECTION OUTPUT ;
    USE SIGNAL ;
    PORT
      LAYER M3 ;
        RECT  40.716 60.419 40.734 60.456 ;
    END
  END b[513]
  PIN b[514]
    DIRECTION OUTPUT ;
    USE SIGNAL ;
    PORT
      LAYER M3 ;
        RECT  40.788 60.419 40.806 60.456 ;
    END
  END b[514]
  PIN b[515]
    DIRECTION OUTPUT ;
    USE SIGNAL ;
    PORT
      LAYER M3 ;
        RECT  40.86 60.419 40.878 60.456 ;
    END
  END b[515]
  PIN b[516]
    DIRECTION OUTPUT ;
    USE SIGNAL ;
    PORT
      LAYER M3 ;
        RECT  40.932 60.419 40.95 60.456 ;
    END
  END b[516]
  PIN b[517]
    DIRECTION OUTPUT ;
    USE SIGNAL ;
    PORT
      LAYER M3 ;
        RECT  41.004 60.419 41.022 60.456 ;
    END
  END b[517]
  PIN b[518]
    DIRECTION OUTPUT ;
    USE SIGNAL ;
    PORT
      LAYER M3 ;
        RECT  41.076 60.419 41.094 60.456 ;
    END
  END b[518]
  PIN b[519]
    DIRECTION OUTPUT ;
    USE SIGNAL ;
    PORT
      LAYER M3 ;
        RECT  41.148 60.419 41.166 60.456 ;
    END
  END b[519]
  PIN b[51]
    DIRECTION OUTPUT ;
    USE SIGNAL ;
    PORT
      LAYER M3 ;
        RECT  25.308 60.419 25.326 60.456 ;
    END
  END b[51]
  PIN b[520]
    DIRECTION OUTPUT ;
    USE SIGNAL ;
    PORT
      LAYER M3 ;
        RECT  41.22 60.419 41.238 60.456 ;
    END
  END b[520]
  PIN b[521]
    DIRECTION OUTPUT ;
    USE SIGNAL ;
    PORT
      LAYER M3 ;
        RECT  41.292 60.419 41.31 60.456 ;
    END
  END b[521]
  PIN b[522]
    DIRECTION OUTPUT ;
    USE SIGNAL ;
    PORT
      LAYER M3 ;
        RECT  41.364 60.419 41.382 60.456 ;
    END
  END b[522]
  PIN b[523]
    DIRECTION OUTPUT ;
    USE SIGNAL ;
    PORT
      LAYER M3 ;
        RECT  41.436 60.419 41.454 60.456 ;
    END
  END b[523]
  PIN b[524]
    DIRECTION OUTPUT ;
    USE SIGNAL ;
    PORT
      LAYER M3 ;
        RECT  41.508 60.419 41.526 60.456 ;
    END
  END b[524]
  PIN b[525]
    DIRECTION OUTPUT ;
    USE SIGNAL ;
    PORT
      LAYER M3 ;
        RECT  41.58 60.419 41.598 60.456 ;
    END
  END b[525]
  PIN b[526]
    DIRECTION OUTPUT ;
    USE SIGNAL ;
    PORT
      LAYER M3 ;
        RECT  41.652 60.419 41.67 60.456 ;
    END
  END b[526]
  PIN b[527]
    DIRECTION OUTPUT ;
    USE SIGNAL ;
    PORT
      LAYER M3 ;
        RECT  41.724 60.419 41.742 60.456 ;
    END
  END b[527]
  PIN b[528]
    DIRECTION OUTPUT ;
    USE SIGNAL ;
    PORT
      LAYER M3 ;
        RECT  41.796 60.419 41.814 60.456 ;
    END
  END b[528]
  PIN b[529]
    DIRECTION OUTPUT ;
    USE SIGNAL ;
    PORT
      LAYER M3 ;
        RECT  41.868 60.419 41.886 60.456 ;
    END
  END b[529]
  PIN b[52]
    DIRECTION OUTPUT ;
    USE SIGNAL ;
    PORT
      LAYER M3 ;
        RECT  25.38 60.419 25.398 60.456 ;
    END
  END b[52]
  PIN b[530]
    DIRECTION OUTPUT ;
    USE SIGNAL ;
    PORT
      LAYER M3 ;
        RECT  41.94 60.419 41.958 60.456 ;
    END
  END b[530]
  PIN b[531]
    DIRECTION OUTPUT ;
    USE SIGNAL ;
    PORT
      LAYER M3 ;
        RECT  42.012 60.419 42.03 60.456 ;
    END
  END b[531]
  PIN b[532]
    DIRECTION OUTPUT ;
    USE SIGNAL ;
    PORT
      LAYER M3 ;
        RECT  42.084 60.419 42.102 60.456 ;
    END
  END b[532]
  PIN b[533]
    DIRECTION OUTPUT ;
    USE SIGNAL ;
    PORT
      LAYER M3 ;
        RECT  42.156 60.419 42.174 60.456 ;
    END
  END b[533]
  PIN b[534]
    DIRECTION OUTPUT ;
    USE SIGNAL ;
    PORT
      LAYER M3 ;
        RECT  42.228 60.419 42.246 60.456 ;
    END
  END b[534]
  PIN b[535]
    DIRECTION OUTPUT ;
    USE SIGNAL ;
    PORT
      LAYER M3 ;
        RECT  42.3 60.419 42.318 60.456 ;
    END
  END b[535]
  PIN b[536]
    DIRECTION OUTPUT ;
    USE SIGNAL ;
    PORT
      LAYER M3 ;
        RECT  42.372 60.419 42.39 60.456 ;
    END
  END b[536]
  PIN b[537]
    DIRECTION OUTPUT ;
    USE SIGNAL ;
    PORT
      LAYER M3 ;
        RECT  42.444 60.419 42.462 60.456 ;
    END
  END b[537]
  PIN b[538]
    DIRECTION OUTPUT ;
    USE SIGNAL ;
    PORT
      LAYER M3 ;
        RECT  42.516 60.419 42.534 60.456 ;
    END
  END b[538]
  PIN b[539]
    DIRECTION OUTPUT ;
    USE SIGNAL ;
    PORT
      LAYER M3 ;
        RECT  42.588 60.419 42.606 60.456 ;
    END
  END b[539]
  PIN b[53]
    DIRECTION OUTPUT ;
    USE SIGNAL ;
    PORT
      LAYER M3 ;
        RECT  25.452 60.419 25.47 60.456 ;
    END
  END b[53]
  PIN b[540]
    DIRECTION OUTPUT ;
    USE SIGNAL ;
    PORT
      LAYER M3 ;
        RECT  42.66 60.419 42.678 60.456 ;
    END
  END b[540]
  PIN b[541]
    DIRECTION OUTPUT ;
    USE SIGNAL ;
    PORT
      LAYER M3 ;
        RECT  42.732 60.419 42.75 60.456 ;
    END
  END b[541]
  PIN b[542]
    DIRECTION OUTPUT ;
    USE SIGNAL ;
    PORT
      LAYER M3 ;
        RECT  42.804 60.419 42.822 60.456 ;
    END
  END b[542]
  PIN b[543]
    DIRECTION OUTPUT ;
    USE SIGNAL ;
    PORT
      LAYER M3 ;
        RECT  42.876 60.419 42.894 60.456 ;
    END
  END b[543]
  PIN b[544]
    DIRECTION OUTPUT ;
    USE SIGNAL ;
    PORT
      LAYER M5 ;
        RECT  25.968 60.372 25.992 60.456 ;
    END
  END b[544]
  PIN b[545]
    DIRECTION OUTPUT ;
    USE SIGNAL ;
    PORT
      LAYER M5 ;
        RECT  26.064 60.372 26.088 60.456 ;
    END
  END b[545]
  PIN b[546]
    DIRECTION OUTPUT ;
    USE SIGNAL ;
    PORT
      LAYER M5 ;
        RECT  26.16 60.372 26.184 60.456 ;
    END
  END b[546]
  PIN b[547]
    DIRECTION OUTPUT ;
    USE SIGNAL ;
    PORT
      LAYER M5 ;
        RECT  26.256 60.372 26.28 60.456 ;
    END
  END b[547]
  PIN b[54]
    DIRECTION OUTPUT ;
    USE SIGNAL ;
    PORT
      LAYER M3 ;
        RECT  25.524 60.419 25.542 60.456 ;
    END
  END b[54]
  PIN b[55]
    DIRECTION OUTPUT ;
    USE SIGNAL ;
    PORT
      LAYER M3 ;
        RECT  25.596 60.419 25.614 60.456 ;
    END
  END b[55]
  PIN b[56]
    DIRECTION OUTPUT ;
    USE SIGNAL ;
    PORT
      LAYER M3 ;
        RECT  25.668 60.419 25.686 60.456 ;
    END
  END b[56]
  PIN b[57]
    DIRECTION OUTPUT ;
    USE SIGNAL ;
    PORT
      LAYER M3 ;
        RECT  25.74 60.419 25.758 60.456 ;
    END
  END b[57]
  PIN b[58]
    DIRECTION OUTPUT ;
    USE SIGNAL ;
    PORT
      LAYER M3 ;
        RECT  25.812 60.419 25.83 60.456 ;
    END
  END b[58]
  PIN b[59]
    DIRECTION OUTPUT ;
    USE SIGNAL ;
    PORT
      LAYER M3 ;
        RECT  25.884 60.419 25.902 60.456 ;
    END
  END b[59]
  PIN b[5]
    DIRECTION OUTPUT ;
    USE SIGNAL ;
    PORT
      LAYER M3 ;
        RECT  21.996 60.419 22.014 60.456 ;
    END
  END b[5]
  PIN b[60]
    DIRECTION OUTPUT ;
    USE SIGNAL ;
    PORT
      LAYER M3 ;
        RECT  25.956 60.419 25.974 60.456 ;
    END
  END b[60]
  PIN b[61]
    DIRECTION OUTPUT ;
    USE SIGNAL ;
    PORT
      LAYER M3 ;
        RECT  26.028 60.419 26.046 60.456 ;
    END
  END b[61]
  PIN b[62]
    DIRECTION OUTPUT ;
    USE SIGNAL ;
    PORT
      LAYER M3 ;
        RECT  26.1 60.419 26.118 60.456 ;
    END
  END b[62]
  PIN b[63]
    DIRECTION OUTPUT ;
    USE SIGNAL ;
    PORT
      LAYER M3 ;
        RECT  26.172 60.419 26.19 60.456 ;
    END
  END b[63]
  PIN b[64]
    DIRECTION OUTPUT ;
    USE SIGNAL ;
    PORT
      LAYER M5 ;
        RECT  35.664 60.372 35.688 60.456 ;
    END
  END b[64]
  PIN b[65]
    DIRECTION OUTPUT ;
    USE SIGNAL ;
    PORT
      LAYER M5 ;
        RECT  35.76 60.372 35.784 60.456 ;
    END
  END b[65]
  PIN b[66]
    DIRECTION OUTPUT ;
    USE SIGNAL ;
    PORT
      LAYER M5 ;
        RECT  35.856 60.372 35.88 60.456 ;
    END
  END b[66]
  PIN b[67]
    DIRECTION OUTPUT ;
    USE SIGNAL ;
    PORT
      LAYER M5 ;
        RECT  35.952 60.372 35.976 60.456 ;
    END
  END b[67]
  PIN b[68]
    DIRECTION OUTPUT ;
    USE SIGNAL ;
    PORT
      LAYER M5 ;
        RECT  36.048 60.372 36.072 60.456 ;
    END
  END b[68]
  PIN b[69]
    DIRECTION OUTPUT ;
    USE SIGNAL ;
    PORT
      LAYER M5 ;
        RECT  36.144 60.372 36.168 60.456 ;
    END
  END b[69]
  PIN b[6]
    DIRECTION OUTPUT ;
    USE SIGNAL ;
    PORT
      LAYER M3 ;
        RECT  22.068 60.419 22.086 60.456 ;
    END
  END b[6]
  PIN b[70]
    DIRECTION OUTPUT ;
    USE SIGNAL ;
    PORT
      LAYER M5 ;
        RECT  36.24 60.372 36.264 60.456 ;
    END
  END b[70]
  PIN b[71]
    DIRECTION OUTPUT ;
    USE SIGNAL ;
    PORT
      LAYER M5 ;
        RECT  36.336 60.372 36.36 60.456 ;
    END
  END b[71]
  PIN b[72]
    DIRECTION OUTPUT ;
    USE SIGNAL ;
    PORT
      LAYER M5 ;
        RECT  36.432 60.372 36.456 60.456 ;
    END
  END b[72]
  PIN b[73]
    DIRECTION OUTPUT ;
    USE SIGNAL ;
    PORT
      LAYER M5 ;
        RECT  36.528 60.372 36.552 60.456 ;
    END
  END b[73]
  PIN b[74]
    DIRECTION OUTPUT ;
    USE SIGNAL ;
    PORT
      LAYER M5 ;
        RECT  36.624 60.372 36.648 60.456 ;
    END
  END b[74]
  PIN b[75]
    DIRECTION OUTPUT ;
    USE SIGNAL ;
    PORT
      LAYER M5 ;
        RECT  36.72 60.372 36.744 60.456 ;
    END
  END b[75]
  PIN b[76]
    DIRECTION OUTPUT ;
    USE SIGNAL ;
    PORT
      LAYER M5 ;
        RECT  36.816 60.372 36.84 60.456 ;
    END
  END b[76]
  PIN b[77]
    DIRECTION OUTPUT ;
    USE SIGNAL ;
    PORT
      LAYER M5 ;
        RECT  36.912 60.372 36.936 60.456 ;
    END
  END b[77]
  PIN b[78]
    DIRECTION OUTPUT ;
    USE SIGNAL ;
    PORT
      LAYER M5 ;
        RECT  37.008 60.372 37.032 60.456 ;
    END
  END b[78]
  PIN b[79]
    DIRECTION OUTPUT ;
    USE SIGNAL ;
    PORT
      LAYER M5 ;
        RECT  37.104 60.372 37.128 60.456 ;
    END
  END b[79]
  PIN b[7]
    DIRECTION OUTPUT ;
    USE SIGNAL ;
    PORT
      LAYER M3 ;
        RECT  22.14 60.419 22.158 60.456 ;
    END
  END b[7]
  PIN b[80]
    DIRECTION OUTPUT ;
    USE SIGNAL ;
    PORT
      LAYER M5 ;
        RECT  37.2 60.372 37.224 60.456 ;
    END
  END b[80]
  PIN b[81]
    DIRECTION OUTPUT ;
    USE SIGNAL ;
    PORT
      LAYER M5 ;
        RECT  37.296 60.372 37.32 60.456 ;
    END
  END b[81]
  PIN b[82]
    DIRECTION OUTPUT ;
    USE SIGNAL ;
    PORT
      LAYER M5 ;
        RECT  37.392 60.372 37.416 60.456 ;
    END
  END b[82]
  PIN b[83]
    DIRECTION OUTPUT ;
    USE SIGNAL ;
    PORT
      LAYER M5 ;
        RECT  37.488 60.372 37.512 60.456 ;
    END
  END b[83]
  PIN b[84]
    DIRECTION OUTPUT ;
    USE SIGNAL ;
    PORT
      LAYER M5 ;
        RECT  37.584 60.372 37.608 60.456 ;
    END
  END b[84]
  PIN b[85]
    DIRECTION OUTPUT ;
    USE SIGNAL ;
    PORT
      LAYER M5 ;
        RECT  37.68 60.372 37.704 60.456 ;
    END
  END b[85]
  PIN b[86]
    DIRECTION OUTPUT ;
    USE SIGNAL ;
    PORT
      LAYER M5 ;
        RECT  37.776 60.372 37.8 60.456 ;
    END
  END b[86]
  PIN b[87]
    DIRECTION OUTPUT ;
    USE SIGNAL ;
    PORT
      LAYER M5 ;
        RECT  37.872 60.372 37.896 60.456 ;
    END
  END b[87]
  PIN b[88]
    DIRECTION OUTPUT ;
    USE SIGNAL ;
    PORT
      LAYER M5 ;
        RECT  37.968 60.372 37.992 60.456 ;
    END
  END b[88]
  PIN b[89]
    DIRECTION OUTPUT ;
    USE SIGNAL ;
    PORT
      LAYER M5 ;
        RECT  38.064 60.372 38.088 60.456 ;
    END
  END b[89]
  PIN b[8]
    DIRECTION OUTPUT ;
    USE SIGNAL ;
    PORT
      LAYER M3 ;
        RECT  22.212 60.419 22.23 60.456 ;
    END
  END b[8]
  PIN b[90]
    DIRECTION OUTPUT ;
    USE SIGNAL ;
    PORT
      LAYER M5 ;
        RECT  38.16 60.372 38.184 60.456 ;
    END
  END b[90]
  PIN b[91]
    DIRECTION OUTPUT ;
    USE SIGNAL ;
    PORT
      LAYER M5 ;
        RECT  38.256 60.372 38.28 60.456 ;
    END
  END b[91]
  PIN b[92]
    DIRECTION OUTPUT ;
    USE SIGNAL ;
    PORT
      LAYER M5 ;
        RECT  38.352 60.372 38.376 60.456 ;
    END
  END b[92]
  PIN b[93]
    DIRECTION OUTPUT ;
    USE SIGNAL ;
    PORT
      LAYER M5 ;
        RECT  38.448 60.372 38.472 60.456 ;
    END
  END b[93]
  PIN b[94]
    DIRECTION OUTPUT ;
    USE SIGNAL ;
    PORT
      LAYER M5 ;
        RECT  38.544 60.372 38.568 60.456 ;
    END
  END b[94]
  PIN b[95]
    DIRECTION OUTPUT ;
    USE SIGNAL ;
    PORT
      LAYER M5 ;
        RECT  38.64 60.372 38.664 60.456 ;
    END
  END b[95]
  PIN b[96]
    DIRECTION OUTPUT ;
    USE SIGNAL ;
    PORT
      LAYER M5 ;
        RECT  38.736 60.372 38.76 60.456 ;
    END
  END b[96]
  PIN b[97]
    DIRECTION OUTPUT ;
    USE SIGNAL ;
    PORT
      LAYER M5 ;
        RECT  38.832 60.372 38.856 60.456 ;
    END
  END b[97]
  PIN b[98]
    DIRECTION OUTPUT ;
    USE SIGNAL ;
    PORT
      LAYER M5 ;
        RECT  38.928 60.372 38.952 60.456 ;
    END
  END b[98]
  PIN b[99]
    DIRECTION OUTPUT ;
    USE SIGNAL ;
    PORT
      LAYER M5 ;
        RECT  39.024 60.372 39.048 60.456 ;
    END
  END b[99]
  PIN b[9]
    DIRECTION OUTPUT ;
    USE SIGNAL ;
    PORT
      LAYER M3 ;
        RECT  22.284 60.419 22.302 60.456 ;
    END
  END b[9]
  PIN ck
    DIRECTION INPUT ;
    USE SIGNAL ;
    PORT
      LAYER M4 ;
        RECT  0 29.616 0.084 29.64 ;
    END
  END ck
  PIN ck_o
    DIRECTION OUTPUT ;
    USE SIGNAL ;
    PORT
      LAYER M4 ;
        RECT  0 29.712 0.084 29.736 ;
    END
  END ck_o
  PIN eb
    DIRECTION OUTPUT ;
    USE SIGNAL ;
    PORT
      LAYER M5 ;
        RECT  26.352 60.372 26.376 60.456 ;
    END
  END eb
  PIN en
    DIRECTION INPUT ;
    USE SIGNAL ;
    PORT
      LAYER M4 ;
        RECT  0 29.808 0.084 29.832 ;
    END
  END en
  PIN VDD
    DIRECTION INOUT ;
    USE POWER ;
    PORT
      LAYER M5 ;
        RECT  61.992 2.151 62.112 58.073 ;
        RECT  59.292 2.151 59.412 58.073 ;
        RECT  56.592 2.151 56.712 58.073 ;
        RECT  53.892 2.151 54.012 58.073 ;
        RECT  51.192 2.151 51.312 58.073 ;
        RECT  48.492 2.151 48.612 58.073 ;
        RECT  45.792 2.151 45.912 58.073 ;
        RECT  43.092 2.151 43.212 58.073 ;
        RECT  40.392 2.151 40.512 58.073 ;
        RECT  37.692 2.151 37.812 58.073 ;
        RECT  34.992 2.151 35.112 58.073 ;
        RECT  32.292 2.151 32.412 58.073 ;
        RECT  29.592 2.151 29.712 58.073 ;
        RECT  26.892 2.151 27.012 58.073 ;
        RECT  24.192 2.151 24.312 58.073 ;
        RECT  21.492 2.151 21.612 58.073 ;
        RECT  18.792 2.151 18.912 58.073 ;
        RECT  16.092 2.151 16.212 58.073 ;
        RECT  13.392 2.151 13.512 58.073 ;
        RECT  10.692 2.151 10.812 58.073 ;
        RECT  7.992 2.151 8.112 58.073 ;
        RECT  5.292 2.151 5.412 58.073 ;
        RECT  2.592 2.151 2.712 58.073 ;
    END
  END VDD
  PIN VSS
    DIRECTION INOUT ;
    USE GROUND ;
    PORT
      LAYER M5 ;
        RECT  61.8 2.137 61.92 58.059 ;
        RECT  59.1 2.137 59.22 58.059 ;
        RECT  56.4 2.137 56.52 58.059 ;
        RECT  53.7 2.137 53.82 58.059 ;
        RECT  51 2.137 51.12 58.059 ;
        RECT  48.3 2.137 48.42 58.059 ;
        RECT  45.6 2.137 45.72 58.059 ;
        RECT  42.9 2.137 43.02 58.059 ;
        RECT  40.2 2.137 40.32 58.059 ;
        RECT  37.5 2.137 37.62 58.059 ;
        RECT  34.8 2.137 34.92 58.059 ;
        RECT  32.1 2.137 32.22 58.059 ;
        RECT  29.4 2.137 29.52 58.059 ;
        RECT  26.7 2.137 26.82 58.059 ;
        RECT  24 2.137 24.12 58.059 ;
        RECT  21.3 2.137 21.42 58.059 ;
        RECT  18.6 2.137 18.72 58.059 ;
        RECT  15.9 2.137 16.02 58.059 ;
        RECT  13.2 2.137 13.32 58.059 ;
        RECT  10.5 2.137 10.62 58.059 ;
        RECT  7.8 2.137 7.92 58.059 ;
        RECT  5.1 2.137 5.22 58.059 ;
        RECT  2.4 2.137 2.52 58.059 ;
    END
  END VSS
  # OT_OBS_CLOSED layer=M5 d_um=1.536 added=57
  OBS
    LAYER RVTN ;
     RECT  2.16 2.16 62.586 2.295 ;
     RECT  2.16 2.565 62.586 2.835 ;
     RECT  2.16 3.105 62.586 3.375 ;
     RECT  2.16 3.645 62.586 3.915 ;
     RECT  2.16 4.185 62.586 4.455 ;
     RECT  2.16 4.725 62.586 4.995 ;
     RECT  2.16 5.265 62.586 5.535 ;
     RECT  2.16 5.805 62.586 6.075 ;
     RECT  2.16 6.345 62.586 6.615 ;
     RECT  2.16 6.885 62.586 7.155 ;
     RECT  2.16 7.425 62.586 7.695 ;
     RECT  2.16 7.965 62.586 8.235 ;
     RECT  2.16 8.505 62.586 8.775 ;
     RECT  2.16 9.045 62.586 9.315 ;
     RECT  2.16 9.585 62.586 9.855 ;
     RECT  2.16 10.125 62.586 10.395 ;
     RECT  2.16 10.665 62.586 10.935 ;
     RECT  2.16 11.205 62.586 11.475 ;
     RECT  2.16 11.745 62.586 12.015 ;
     RECT  2.16 12.285 62.586 12.555 ;
     RECT  2.16 12.825 62.586 13.095 ;
     RECT  2.16 13.365 62.586 13.635 ;
     RECT  2.16 13.905 62.586 14.175 ;
     RECT  2.16 14.445 62.586 14.715 ;
     RECT  2.16 14.985 62.586 15.255 ;
     RECT  2.16 15.525 62.586 15.795 ;
     RECT  2.16 16.065 62.586 16.335 ;
     RECT  2.16 16.605 62.586 16.875 ;
     RECT  2.16 17.145 62.586 17.415 ;
     RECT  2.16 17.685 62.586 17.955 ;
     RECT  2.16 18.225 62.586 18.495 ;
     RECT  2.16 18.765 62.586 19.035 ;
     RECT  2.16 19.305 62.586 19.575 ;
     RECT  2.16 19.845 62.586 20.115 ;
     RECT  2.16 20.385 62.586 20.655 ;
     RECT  2.16 20.925 62.586 21.195 ;
     RECT  2.16 21.465 62.586 21.735 ;
     RECT  2.16 22.005 62.586 22.275 ;
     RECT  2.16 22.545 62.586 22.815 ;
     RECT  2.16 23.085 62.586 23.355 ;
     RECT  2.16 23.625 62.586 23.895 ;
     RECT  2.16 24.165 62.586 24.435 ;
     RECT  2.16 24.705 62.586 24.975 ;
     RECT  2.16 25.245 62.586 25.515 ;
     RECT  2.16 25.785 62.586 26.055 ;
     RECT  2.16 26.325 62.586 26.595 ;
     RECT  2.16 26.865 62.586 27.135 ;
     RECT  2.16 27.405 62.586 27.675 ;
     RECT  2.16 27.945 62.586 28.215 ;
     RECT  2.16 28.485 62.586 28.755 ;
     RECT  2.16 29.025 62.586 29.295 ;
     RECT  2.16 29.565 62.586 29.835 ;
     RECT  2.16 30.105 62.586 30.375 ;
     RECT  2.16 30.645 62.586 30.915 ;
     RECT  2.16 31.185 62.586 31.455 ;
     RECT  2.16 31.725 62.586 31.995 ;
     RECT  2.16 32.265 62.586 32.535 ;
     RECT  2.16 32.805 62.586 33.075 ;
     RECT  2.16 33.345 62.586 33.615 ;
     RECT  2.16 33.885 62.586 34.155 ;
     RECT  2.16 34.425 62.586 34.695 ;
     RECT  2.16 34.965 62.586 35.235 ;
     RECT  2.16 35.505 62.586 35.775 ;
     RECT  2.16 36.045 62.586 36.315 ;
     RECT  2.16 36.585 62.586 36.855 ;
     RECT  2.16 37.125 62.586 37.395 ;
     RECT  2.16 37.665 62.586 37.935 ;
     RECT  2.16 38.205 62.586 38.475 ;
     RECT  2.16 38.745 62.586 39.015 ;
     RECT  2.16 39.285 62.586 39.555 ;
     RECT  2.16 39.825 62.586 40.095 ;
     RECT  2.16 40.365 62.586 40.635 ;
     RECT  2.16 40.905 62.586 41.175 ;
     RECT  2.16 41.445 62.586 41.715 ;
     RECT  2.16 41.985 62.586 42.255 ;
     RECT  2.16 42.525 62.586 42.795 ;
     RECT  2.16 43.065 62.586 43.335 ;
     RECT  2.16 43.605 62.586 43.875 ;
     RECT  2.16 44.145 62.586 44.415 ;
     RECT  2.16 44.685 62.586 44.955 ;
     RECT  2.16 45.225 62.586 45.495 ;
     RECT  2.16 45.765 62.586 46.035 ;
     RECT  2.16 46.305 62.586 46.575 ;
     RECT  2.16 46.845 62.586 47.115 ;
     RECT  2.16 47.385 62.586 47.655 ;
     RECT  2.16 47.925 62.586 48.195 ;
     RECT  2.16 48.465 62.586 48.735 ;
     RECT  2.16 49.005 62.586 49.275 ;
     RECT  2.16 49.545 62.586 49.815 ;
     RECT  2.16 50.085 62.586 50.355 ;
     RECT  2.16 50.625 62.586 50.895 ;
     RECT  2.16 51.165 62.586 51.435 ;
     RECT  2.16 51.705 62.586 51.975 ;
     RECT  2.16 52.245 62.586 52.515 ;
     RECT  2.16 52.785 62.586 53.055 ;
     RECT  2.16 53.325 62.586 53.595 ;
     RECT  2.16 53.865 62.586 54.135 ;
     RECT  2.16 54.405 62.586 54.675 ;
     RECT  2.16 54.945 62.586 55.215 ;
     RECT  2.16 55.485 62.586 55.755 ;
     RECT  2.16 56.025 62.586 56.295 ;
     RECT  2.16 56.565 62.586 56.835 ;
     RECT  2.16 57.105 62.586 57.375 ;
     RECT  2.16 57.645 62.586 57.915 ;
    LAYER RVTP ;
     RECT  2.16 2.295 62.586 2.565 ;
     RECT  2.16 2.835 62.586 3.105 ;
     RECT  2.16 3.375 62.586 3.645 ;
     RECT  2.16 3.915 62.586 4.185 ;
     RECT  2.16 4.455 62.586 4.725 ;
     RECT  2.16 4.995 62.586 5.265 ;
     RECT  2.16 5.535 62.586 5.805 ;
     RECT  2.16 6.075 62.586 6.345 ;
     RECT  2.16 6.615 62.586 6.885 ;
     RECT  2.16 7.155 62.586 7.425 ;
     RECT  2.16 7.695 62.586 7.965 ;
     RECT  2.16 8.235 62.586 8.505 ;
     RECT  2.16 8.775 62.586 9.045 ;
     RECT  2.16 9.315 62.586 9.585 ;
     RECT  2.16 9.855 62.586 10.125 ;
     RECT  2.16 10.395 62.586 10.665 ;
     RECT  2.16 10.935 62.586 11.205 ;
     RECT  2.16 11.475 62.586 11.745 ;
     RECT  2.16 12.015 62.586 12.285 ;
     RECT  2.16 12.555 62.586 12.825 ;
     RECT  2.16 13.095 62.586 13.365 ;
     RECT  2.16 13.635 62.586 13.905 ;
     RECT  2.16 14.175 62.586 14.445 ;
     RECT  2.16 14.715 62.586 14.985 ;
     RECT  2.16 15.255 62.586 15.525 ;
     RECT  2.16 15.795 62.586 16.065 ;
     RECT  2.16 16.335 62.586 16.605 ;
     RECT  2.16 16.875 62.586 17.145 ;
     RECT  2.16 17.415 62.586 17.685 ;
     RECT  2.16 17.955 62.586 18.225 ;
     RECT  2.16 18.495 62.586 18.765 ;
     RECT  2.16 19.035 62.586 19.305 ;
     RECT  2.16 19.575 62.586 19.845 ;
     RECT  2.16 20.115 62.586 20.385 ;
     RECT  2.16 20.655 62.586 20.925 ;
     RECT  2.16 21.195 62.586 21.465 ;
     RECT  2.16 21.735 62.586 22.005 ;
     RECT  2.16 22.275 62.586 22.545 ;
     RECT  2.16 22.815 62.586 23.085 ;
     RECT  2.16 23.355 62.586 23.625 ;
     RECT  2.16 23.895 62.586 24.165 ;
     RECT  2.16 24.435 62.586 24.705 ;
     RECT  2.16 24.975 62.586 25.245 ;
     RECT  2.16 25.515 62.586 25.785 ;
     RECT  2.16 26.055 62.586 26.325 ;
     RECT  2.16 26.595 62.586 26.865 ;
     RECT  2.16 27.135 62.586 27.405 ;
     RECT  2.16 27.675 62.586 27.945 ;
     RECT  2.16 28.215 62.586 28.485 ;
     RECT  2.16 28.755 62.586 29.025 ;
     RECT  2.16 29.295 62.586 29.565 ;
     RECT  2.16 29.835 62.586 30.105 ;
     RECT  2.16 30.375 62.586 30.645 ;
     RECT  2.16 30.915 62.586 31.185 ;
     RECT  2.16 31.455 62.586 31.725 ;
     RECT  2.16 31.995 62.586 32.265 ;
     RECT  2.16 32.535 62.586 32.805 ;
     RECT  2.16 33.075 62.586 33.345 ;
     RECT  2.16 33.615 62.586 33.885 ;
     RECT  2.16 34.155 62.586 34.425 ;
     RECT  2.16 34.695 62.586 34.965 ;
     RECT  2.16 35.235 62.586 35.505 ;
     RECT  2.16 35.775 62.586 36.045 ;
     RECT  2.16 36.315 62.586 36.585 ;
     RECT  2.16 36.855 62.586 37.125 ;
     RECT  2.16 37.395 62.586 37.665 ;
     RECT  2.16 37.935 62.586 38.205 ;
     RECT  2.16 38.475 62.586 38.745 ;
     RECT  2.16 39.015 62.586 39.285 ;
     RECT  2.16 39.555 62.586 39.825 ;
     RECT  2.16 40.095 62.586 40.365 ;
     RECT  2.16 40.635 62.586 40.905 ;
     RECT  2.16 41.175 62.586 41.445 ;
     RECT  2.16 41.715 62.586 41.985 ;
     RECT  2.16 42.255 62.586 42.525 ;
     RECT  2.16 42.795 62.586 43.065 ;
     RECT  2.16 43.335 62.586 43.605 ;
     RECT  2.16 43.875 62.586 44.145 ;
     RECT  2.16 44.415 62.586 44.685 ;
     RECT  2.16 44.955 62.586 45.225 ;
     RECT  2.16 45.495 62.586 45.765 ;
     RECT  2.16 46.035 62.586 46.305 ;
     RECT  2.16 46.575 62.586 46.845 ;
     RECT  2.16 47.115 62.586 47.385 ;
     RECT  2.16 47.655 62.586 47.925 ;
     RECT  2.16 48.195 62.586 48.465 ;
     RECT  2.16 48.735 62.586 49.005 ;
     RECT  2.16 49.275 62.586 49.545 ;
     RECT  2.16 49.815 62.586 50.085 ;
     RECT  2.16 50.355 62.586 50.625 ;
     RECT  2.16 50.895 62.586 51.165 ;
     RECT  2.16 51.435 62.586 51.705 ;
     RECT  2.16 51.975 62.586 52.245 ;
     RECT  2.16 52.515 62.586 52.785 ;
     RECT  2.16 53.055 62.586 53.325 ;
     RECT  2.16 53.595 62.586 53.865 ;
     RECT  2.16 54.135 62.586 54.405 ;
     RECT  2.16 54.675 62.586 54.945 ;
     RECT  2.16 55.215 62.586 55.485 ;
     RECT  2.16 55.755 62.586 56.025 ;
     RECT  2.16 56.295 62.586 56.565 ;
     RECT  2.16 56.835 62.586 57.105 ;
     RECT  2.16 57.375 62.586 57.645 ;
     RECT  2.16 57.915 62.586 58.05 ;
    LAYER M1 ;
     RECT  2.16 2.151 62.586 58.059 ;
    LAYER M2 ;
     RECT  0.103 29.61 2.16 29.628 ;
     RECT  23.935 60.39 24.007 60.408 ;
     RECT  24.007 60.354 24.079 60.408 ;
     RECT  24.079 60.282 24.295 60.408 ;
     RECT  24.295 60.246 24.431 60.408 ;
     RECT  24.431 60.282 25.159 60.408 ;
     RECT  25.159 60.156 25.475 60.408 ;
     RECT  25.475 60.201 26.671 60.408 ;
     RECT  26.671 60.12 26.771 60.408 ;
     RECT  26.771 60.201 27.203 60.408 ;
     RECT  27.203 60.246 27.275 60.408 ;
     RECT  27.275 60.318 28.039 60.408 ;
     RECT  28.039 60.246 28.543 60.408 ;
     RECT  2.16 2.151 29.083 58.059 ;
     RECT  29.083 2.151 29.183 58.716 ;
     RECT  29.183 2.151 29.219 58.599 ;
     RECT  28.543 60.201 29.371 60.408 ;
     RECT  29.371 60.156 29.507 60.408 ;
     RECT  29.507 60.201 29.651 60.408 ;
     RECT  29.651 60.39 29.759 60.408 ;
     RECT  29.219 2.151 30.199 58.212 ;
     RECT  30.199 2.151 30.271 58.644 ;
     RECT  30.271 2.151 30.407 58.716 ;
     RECT  30.559 60.201 30.631 60.219 ;
     RECT  30.631 60.201 30.659 60.408 ;
     RECT  30.659 60.282 30.767 60.408 ;
     RECT  30.407 2.151 31.351 58.14 ;
     RECT  31.351 2.151 31.811 58.716 ;
     RECT  31.811 2.151 31.883 58.374 ;
     RECT  30.767 60.39 31.927 60.408 ;
     RECT  31.927 60.156 32.287 60.408 ;
     RECT  32.287 60.084 32.459 60.408 ;
     RECT  32.459 60.156 32.495 60.408 ;
     RECT  31.883 2.151 32.791 58.284 ;
     RECT  32.495 60.201 33.295 60.408 ;
     RECT  32.791 2.151 33.431 58.716 ;
     RECT  33.295 60.156 33.655 60.408 ;
     RECT  33.655 60.084 33.971 60.408 ;
     RECT  33.431 2.151 34.187 58.374 ;
     RECT  33.971 60.156 34.619 60.408 ;
     RECT  34.619 60.201 35.303 60.408 ;
     RECT  35.303 60.201 35.447 60.336 ;
     RECT  34.187 2.151 35.491 58.14 ;
     RECT  35.491 2.151 35.591 58.716 ;
     RECT  35.591 2.151 35.627 58.14 ;
     RECT  35.447 60.318 36.031 60.336 ;
     RECT  35.627 2.151 37.147 58.104 ;
     RECT  37.147 2.151 37.283 58.752 ;
     RECT  36.031 60.318 37.759 60.408 ;
     RECT  37.759 60.201 38.579 60.408 ;
     RECT  38.579 60.282 38.615 60.408 ;
     RECT  38.615 60.318 39.451 60.408 ;
     RECT  39.451 60.156 40.063 60.408 ;
     RECT  37.283 2.151 40.243 58.104 ;
     RECT  40.063 59.742 40.271 60.408 ;
     RECT  40.243 2.151 41.279 58.716 ;
     RECT  40.271 59.814 41.539 60.408 ;
     RECT  41.539 59.238 41.603 60.408 ;
     RECT  41.603 59.238 41.675 59.292 ;
     RECT  41.675 59.274 42.835 59.292 ;
     RECT  41.603 60.084 42.835 60.408 ;
     RECT  42.835 59.274 42.935 60.408 ;
     RECT  41.279 2.151 43.159 58.104 ;
     RECT  43.159 2.151 43.259 58.716 ;
     RECT  42.935 59.544 43.763 60.408 ;
     RECT  43.763 59.544 44.527 59.562 ;
     RECT  43.763 60.318 44.527 60.408 ;
     RECT  43.259 2.151 45.607 58.104 ;
     RECT  45.607 2.151 46.211 58.716 ;
     RECT  44.527 59.544 46.435 60.408 ;
     RECT  46.435 59.544 47.543 60.444 ;
     RECT  47.543 60.318 47.795 60.444 ;
     RECT  47.795 60.426 47.903 60.444 ;
     RECT  46.211 2.151 48.127 58.104 ;
     RECT  48.127 2.151 49.199 58.716 ;
     RECT  47.543 59.544 51.683 59.562 ;
     RECT  49.199 2.151 54.715 58.104 ;
     RECT  54.715 2.151 58.307 58.14 ;
     RECT  58.307 2.151 58.379 58.104 ;
     RECT  58.379 2.151 62.586 58.059 ;
     RECT  62.586 3.888 62.735 57.87 ;
     RECT  62.735 4.194 62.771 57.87 ;
     RECT  62.771 4.194 62.843 18.216 ;
     RECT  62.843 4.194 63.311 11.034 ;
     RECT  62.771 19.044 63.311 46.026 ;
     RECT  62.771 46.818 63.311 57.87 ;
     RECT  63.311 4.194 63.347 5.562 ;
     RECT  62.843 11.826 63.347 18.216 ;
     RECT  63.311 19.044 63.347 22.914 ;
     RECT  63.311 25.686 63.347 28.044 ;
     RECT  63.311 28.962 63.347 29.934 ;
     RECT  63.311 46.854 63.347 49.266 ;
     RECT  63.311 56.106 63.347 56.358 ;
     RECT  63.311 57.186 63.347 57.87 ;
     RECT  63.347 22.086 63.383 22.914 ;
     RECT  63.347 11.826 63.491 17.1 ;
     RECT  63.311 6.354 63.779 10.926 ;
     RECT  63.347 46.854 63.815 48.294 ;
     RECT  63.347 19.044 63.851 21.15 ;
     RECT  63.347 26.028 63.851 26.424 ;
     RECT  63.347 4.194 63.887 4.212 ;
     RECT  63.779 6.354 63.887 10.62 ;
     RECT  63.491 11.826 63.887 14.634 ;
     RECT  63.491 15.426 63.887 17.1 ;
     RECT  63.347 17.892 63.887 18.216 ;
     RECT  63.851 20.052 63.887 21.15 ;
     RECT  63.383 22.356 63.887 22.914 ;
     RECT  63.311 23.976 63.887 24.696 ;
     RECT  63.851 26.028 63.887 26.388 ;
     RECT  63.347 27.72 63.887 28.044 ;
     RECT  63.347 28.962 63.887 29.826 ;
     RECT  63.311 31.194 63.887 46.026 ;
     RECT  63.815 47.394 63.887 48.294 ;
     RECT  63.347 49.248 63.887 49.266 ;
     RECT  63.311 50.364 63.887 51.732 ;
     RECT  63.311 52.524 63.887 55.314 ;
     RECT  63.347 56.106 63.887 56.124 ;
     RECT  63.347 57.186 63.887 57.438 ;
     RECT  63.347 4.968 63.923 5.562 ;
     RECT  63.887 7.164 63.923 7.794 ;
     RECT  63.887 9.594 63.923 10.386 ;
     RECT  63.887 11.988 63.923 13.698 ;
     RECT  63.887 15.804 63.923 17.019 ;
     RECT  63.887 18.162 63.923 18.18 ;
     RECT  63.851 19.044 63.923 19.26 ;
     RECT  63.887 20.052 63.923 20.34 ;
     RECT  63.887 23.976 63.923 24.66 ;
     RECT  63.887 26.334 63.923 26.352 ;
     RECT  63.887 28.962 63.923 28.98 ;
     RECT  63.887 32.076 63.923 34.524 ;
     RECT  63.887 35.28 63.923 43.056 ;
     RECT  63.887 45.432 63.923 45.864 ;
     RECT  63.887 50.364 63.923 50.382 ;
     RECT  63.887 51.21 63.923 51.426 ;
     RECT  63.887 53.406 63.923 53.424 ;
     RECT  63.887 55.026 63.923 55.206 ;
     RECT  63.887 57.186 63.923 57.249 ;
     RECT  63.887 6.39 63.959 6.408 ;
     RECT  63.923 10.206 63.959 10.224 ;
     RECT  63.923 11.988 63.959 12.744 ;
     RECT  63.923 13.68 63.959 13.698 ;
     RECT  63.923 17.001 63.959 17.019 ;
     RECT  63.923 19.044 63.959 19.062 ;
     RECT  63.923 20.088 63.959 20.34 ;
     RECT  63.887 21.096 63.959 21.114 ;
     RECT  63.923 24.336 63.959 24.426 ;
     RECT  63.887 27.99 63.959 28.008 ;
     RECT  63.923 33.39 63.959 33.408 ;
     RECT  63.923 35.55 63.959 36.342 ;
     RECT  63.923 38.484 63.959 38.502 ;
     RECT  63.923 39.366 63.959 41.508 ;
     RECT  63.923 42.264 63.959 43.056 ;
     RECT  63.923 45.774 63.959 45.792 ;
     RECT  63.887 48.276 63.959 48.294 ;
     RECT  63.923 51.408 63.959 51.426 ;
     RECT  63.923 55.026 63.959 55.044 ;
     RECT  63.923 57.186 63.959 57.204 ;
     RECT  63.959 20.088 63.995 20.106 ;
     RECT  63.959 24.336 63.995 24.354 ;
     RECT  63.959 35.856 63.995 35.874 ;
     RECT  63.959 40.95 63.995 40.968 ;
     RECT  63.887 31.194 64.615 31.212 ;
     RECT  63.959 43.038 64.643 43.056 ;
     RECT  64.615 31.086 64.679 31.212 ;
     RECT  64.651 4.122 64.751 5.598 ;
     RECT  64.651 9.486 64.751 9.504 ;
     RECT  63.959 12.456 64.751 12.474 ;
     RECT  64.651 18.126 64.751 18.144 ;
     RECT  64.651 20.898 64.751 20.916 ;
     RECT  64.651 23.328 64.751 23.346 ;
     RECT  64.651 25.146 64.751 25.164 ;
     RECT  64.651 27.756 64.751 27.774 ;
     RECT  64.651 30.15 64.751 30.168 ;
     RECT  64.679 31.086 64.751 31.104 ;
     RECT  64.651 50.436 64.751 50.454 ;
    LAYER M3 ;
     RECT  2.415 2.143 2.505 2.413 ;
     RECT  5.115 2.143 5.205 2.413 ;
     RECT  7.815 2.143 7.905 2.413 ;
     RECT  10.515 2.143 10.605 2.413 ;
     RECT  13.215 2.143 13.305 2.413 ;
     RECT  15.915 2.143 16.005 2.413 ;
     RECT  18.615 2.143 18.705 2.413 ;
     RECT  21.315 2.143 21.405 2.413 ;
     RECT  24.015 2.143 24.105 2.413 ;
     RECT  26.715 2.143 26.805 2.413 ;
     RECT  29.415 2.143 29.505 2.413 ;
     RECT  32.115 2.143 32.205 2.413 ;
     RECT  34.815 2.143 34.905 2.413 ;
     RECT  37.515 2.143 37.605 2.413 ;
     RECT  40.215 2.143 40.305 2.413 ;
     RECT  42.915 2.143 43.005 2.413 ;
     RECT  45.615 2.143 45.705 2.413 ;
     RECT  48.315 2.143 48.405 2.413 ;
     RECT  51.015 2.143 51.105 2.413 ;
     RECT  53.715 2.143 53.805 2.413 ;
     RECT  56.415 2.143 56.505 2.413 ;
     RECT  59.115 2.143 59.205 2.413 ;
     RECT  61.815 2.143 61.905 2.413 ;
     RECT  61.815 2.413 62.097 3.721 ;
     RECT  61.344 3.721 62.097 3.787 ;
     RECT  61.344 3.787 62.73 3.847 ;
     RECT  59.115 2.413 59.397 3.883 ;
     RECT  61.2 3.847 62.73 3.883 ;
     RECT  59.115 3.883 59.454 3.931 ;
     RECT  60.228 3.721 60.246 3.931 ;
     RECT  61.2 3.883 63.306 3.979 ;
     RECT  61.2 3.979 63.882 3.983 ;
     RECT  59.112 3.931 59.454 3.991 ;
     RECT  60.228 3.931 60.426 3.991 ;
     RECT  64.656 4.075 64.674 4.117 ;
     RECT  56.415 2.413 56.697 4.261 ;
     RECT  58.032 4.117 58.05 4.261 ;
     RECT  59.112 3.991 60.426 4.261 ;
     RECT  56.415 4.261 56.754 4.351 ;
     RECT  58.032 4.261 58.122 4.351 ;
     RECT  59.112 4.261 60.822 4.351 ;
     RECT  56.415 4.351 56.826 4.507 ;
     RECT  57.78 4.351 60.822 4.507 ;
     RECT  56.415 4.507 60.822 4.531 ;
     RECT  55.404 4.507 55.422 4.559 ;
     RECT  61.668 3.983 63.882 4.747 ;
     RECT  61.668 4.747 63.918 4.891 ;
     RECT  56.34 4.531 60.822 4.927 ;
     RECT  61.56 4.891 63.918 4.927 ;
     RECT  54.72 4.729 54.738 5.305 ;
     RECT  55.476 5.269 55.494 5.305 ;
     RECT  42.915 2.413 43.197 5.503 ;
     RECT  54.72 5.305 55.494 5.575 ;
     RECT  56.34 4.927 63.918 5.575 ;
     RECT  64.656 4.117 64.746 5.603 ;
     RECT  41.868 5.431 41.886 5.611 ;
     RECT  64.656 5.603 64.674 5.645 ;
     RECT  42.732 5.503 43.197 5.809 ;
     RECT  51.015 2.413 51.297 5.881 ;
     RECT  41.616 5.611 41.886 5.971 ;
     RECT  42.732 5.809 43.794 5.971 ;
     RECT  50.796 5.881 51.297 5.999 ;
     RECT  54.72 5.575 63.918 6.091 ;
     RECT  41.616 5.971 43.794 6.151 ;
     RECT  54.72 6.091 63.954 6.221 ;
     RECT  53.715 2.413 53.997 6.241 ;
     RECT  54.72 6.221 62.766 6.241 ;
     RECT  63.828 6.221 63.954 6.413 ;
     RECT  41.616 6.151 43.866 6.583 ;
     RECT  53.715 6.241 62.766 6.845 ;
     RECT  55.908 6.845 62.766 6.961 ;
     RECT  63.828 6.413 63.882 6.961 ;
     RECT  55.908 6.961 63.882 7.079 ;
     RECT  56.34 7.079 63.882 7.159 ;
     RECT  51.015 5.999 51.297 7.195 ;
     RECT  56.34 7.159 63.918 7.949 ;
     RECT  56.34 7.949 63.882 7.963 ;
     RECT  34.815 2.413 35.097 8.005 ;
     RECT  36.216 7.663 36.234 8.005 ;
     RECT  56.304 7.963 63.882 8.005 ;
     RECT  40.215 2.413 40.497 8.041 ;
     RECT  41.616 6.583 44.046 8.041 ;
     RECT  48.315 2.413 48.597 8.131 ;
     RECT  40.215 8.041 44.046 8.159 ;
     RECT  53.715 6.845 54.81 8.195 ;
     RECT  50.364 7.195 51.297 8.203 ;
     RECT  38.772 8.167 38.79 8.267 ;
     RECT  53.715 8.195 54.666 8.267 ;
     RECT  55.944 8.005 63.882 8.275 ;
     RECT  28.044 7.699 28.062 8.311 ;
     RECT  28.044 8.311 28.134 8.581 ;
     RECT  49.86 8.203 51.297 8.851 ;
     RECT  55.872 8.275 63.882 9.067 ;
     RECT  52.704 6.691 52.722 9.211 ;
     RECT  53.715 8.267 54.63 9.211 ;
     RECT  52.704 9.211 54.63 9.247 ;
     RECT  29.415 2.413 29.697 9.319 ;
     RECT  64.656 9.451 64.674 9.481 ;
     RECT  64.656 9.481 64.746 9.509 ;
     RECT  64.728 9.509 64.746 9.533 ;
     RECT  34.815 8.005 36.234 9.589 ;
     RECT  52.704 9.247 54.99 9.625 ;
     RECT  55.872 9.067 63.918 9.625 ;
     RECT  52.704 9.625 63.918 9.851 ;
     RECT  45.615 2.413 45.897 10.201 ;
     RECT  55.8 9.851 63.918 10.201 ;
     RECT  49.32 8.851 51.297 10.327 ;
     RECT  52.704 9.851 54.99 10.597 ;
     RECT  55.8 10.201 63.954 10.597 ;
     RECT  45.615 10.201 46.062 10.741 ;
     RECT  47.7 8.131 48.597 10.741 ;
     RECT  49.32 10.327 51.642 10.741 ;
     RECT  52.704 10.597 63.954 10.829 ;
     RECT  45.108 10.741 46.062 10.843 ;
     RECT  52.704 10.829 63.882 10.859 ;
     RECT  45.108 10.843 46.782 10.973 ;
     RECT  45.108 10.973 46.062 11.011 ;
     RECT  47.7 10.741 51.642 11.011 ;
     RECT  56.016 10.859 63.882 11.039 ;
     RECT  45 11.011 46.062 11.131 ;
     RECT  44.964 11.131 46.062 11.171 ;
     RECT  45 11.171 46.062 11.405 ;
     RECT  45.108 11.405 46.062 11.749 ;
     RECT  47.124 11.011 51.642 11.749 ;
     RECT  45.108 11.749 51.642 11.849 ;
     RECT  63.864 11.039 63.882 11.983 ;
     RECT  56.016 11.039 62.838 12.181 ;
     RECT  52.704 10.859 54.99 12.361 ;
     RECT  55.764 12.181 62.838 12.361 ;
     RECT  45.288 11.849 51.642 12.413 ;
     RECT  63.864 11.983 63.954 12.427 ;
     RECT  63.864 12.427 64.674 12.451 ;
     RECT  63.864 12.451 64.746 12.479 ;
     RECT  64.728 12.479 64.746 12.509 ;
     RECT  52.704 12.361 62.838 12.941 ;
     RECT  41.616 8.159 44.046 13.171 ;
     RECT  41.616 13.171 44.154 13.333 ;
     RECT  63.864 12.479 63.954 13.567 ;
     RECT  63.828 13.567 63.954 13.703 ;
     RECT  41.616 13.333 44.73 13.837 ;
     RECT  52.704 12.941 62.766 13.963 ;
     RECT  63.828 13.703 63.882 13.963 ;
     RECT  41.616 13.837 44.874 14.449 ;
     RECT  45.615 12.413 51.642 14.449 ;
     RECT  52.704 13.963 63.882 15.403 ;
     RECT  52.704 15.403 63.918 15.593 ;
     RECT  63.828 15.593 63.918 15.821 ;
     RECT  34.815 9.589 36.774 16.267 ;
     RECT  37.515 2.413 37.797 16.267 ;
     RECT  34.815 16.267 37.797 16.363 ;
     RECT  52.704 15.593 62.766 16.367 ;
     RECT  34.815 16.363 37.89 16.375 ;
     RECT  34.815 16.375 37.998 16.609 ;
     RECT  38.772 16.363 38.79 16.609 ;
     RECT  28.044 8.581 28.206 16.681 ;
     RECT  29.376 9.319 29.697 16.681 ;
     RECT  53.28 16.367 62.766 16.843 ;
     RECT  34.815 16.609 38.79 16.973 ;
     RECT  63.864 15.821 63.918 16.978 ;
     RECT  32.115 2.413 32.397 17.041 ;
     RECT  32.115 17.041 32.526 17.077 ;
     RECT  32.115 17.077 33.138 17.117 ;
     RECT  53.28 16.843 62.802 17.149 ;
     RECT  63.864 16.978 63.954 17.165 ;
     RECT  40.215 8.159 40.497 17.185 ;
     RECT  39.636 17.185 40.497 17.221 ;
     RECT  53.028 17.149 62.802 17.221 ;
     RECT  63.864 17.165 63.918 17.221 ;
     RECT  32.115 17.117 32.814 17.347 ;
     RECT  32.112 17.347 32.814 17.383 ;
     RECT  53.028 17.221 63.918 17.581 ;
     RECT  32.04 17.383 32.814 17.609 ;
     RECT  52.704 17.581 63.918 17.741 ;
     RECT  34.815 16.973 38.502 17.923 ;
     RECT  39.636 17.221 40.734 17.923 ;
     RECT  64.656 18.091 64.674 18.121 ;
     RECT  64.656 18.121 64.746 18.149 ;
     RECT  64.728 18.149 64.746 18.173 ;
     RECT  52.704 17.741 62.73 18.475 ;
     RECT  63.864 17.741 63.918 18.571 ;
     RECT  52.704 18.475 62.766 18.797 ;
     RECT  63.828 18.571 63.918 18.859 ;
     RECT  34.815 17.923 40.734 19.003 ;
     RECT  41.616 14.449 51.642 19.003 ;
     RECT  63.828 18.859 63.954 19.067 ;
     RECT  63.828 19.067 63.918 19.265 ;
     RECT  52.704 18.797 62.694 19.337 ;
     RECT  63.828 19.265 63.882 19.373 ;
     RECT  28.044 16.681 29.697 19.507 ;
     RECT  30.492 8.167 30.51 19.507 ;
     RECT  26.715 2.413 26.997 19.543 ;
     RECT  28.044 19.507 30.51 19.543 ;
     RECT  32.04 17.609 32.397 19.615 ;
     RECT  34.815 19.003 51.642 19.885 ;
     RECT  52.704 19.337 62.097 19.885 ;
     RECT  63.864 19.373 63.882 20.011 ;
     RECT  63.864 20.011 63.918 20.083 ;
     RECT  32.04 19.615 32.994 20.191 ;
     RECT  34.815 19.885 62.097 20.299 ;
     RECT  63.864 20.083 63.99 20.345 ;
     RECT  34.815 20.299 62.73 20.425 ;
     RECT  34.416 20.425 62.73 20.491 ;
     RECT  63.864 20.345 63.882 20.491 ;
     RECT  34.416 20.491 63.882 20.587 ;
     RECT  64.656 20.875 64.674 20.893 ;
     RECT  64.656 20.893 64.746 20.921 ;
     RECT  64.728 20.921 64.746 20.957 ;
     RECT  32.04 20.191 33.03 21.001 ;
     RECT  34.092 20.587 63.882 21.001 ;
     RECT  32.04 21.001 63.882 21.091 ;
     RECT  32.04 21.091 63.954 21.677 ;
     RECT  32.04 21.677 63.882 21.695 ;
     RECT  32.076 21.695 63.882 22.819 ;
     RECT  32.004 22.819 63.882 22.925 ;
     RECT  64.656 23.275 64.674 23.323 ;
     RECT  64.656 23.323 64.746 23.351 ;
     RECT  64.728 23.351 64.746 23.36 ;
     RECT  32.004 22.925 63.306 23.947 ;
     RECT  32.004 23.947 63.882 23.971 ;
     RECT  24.015 2.413 24.297 24.061 ;
     RECT  32.004 23.971 63.918 24.139 ;
     RECT  32.004 24.139 63.954 24.331 ;
     RECT  24.015 24.061 24.606 24.403 ;
     RECT  32.004 24.331 63.99 24.461 ;
     RECT  24.015 24.403 24.678 24.601 ;
     RECT  32.004 24.461 63.918 24.665 ;
     RECT  32.004 24.665 63.882 24.701 ;
     RECT  25.848 24.781 25.866 24.871 ;
     RECT  26.715 19.543 30.51 24.871 ;
     RECT  31.248 22.855 31.266 24.899 ;
     RECT  32.004 24.701 63.306 25.141 ;
     RECT  64.656 25.099 64.674 25.141 ;
     RECT  64.656 25.141 64.746 25.169 ;
     RECT  64.728 25.169 64.746 25.181 ;
     RECT  24.015 24.601 24.966 25.249 ;
     RECT  25.848 24.871 30.51 25.249 ;
     RECT  31.68 25.141 63.306 25.675 ;
     RECT  31.68 25.675 63.342 25.771 ;
     RECT  31.68 25.771 63.882 25.853 ;
     RECT  24.015 25.249 30.51 25.861 ;
     RECT  31.68 25.853 62.766 25.861 ;
     RECT  63.828 25.853 63.882 26.05 ;
     RECT  24.015 25.861 62.766 26.285 ;
     RECT  63.828 26.05 63.918 26.357 ;
     RECT  63.828 26.357 63.882 26.393 ;
     RECT  63.828 26.393 63.846 26.429 ;
     RECT  24.015 26.285 30.834 26.591 ;
     RECT  24.015 26.591 30.798 26.789 ;
     RECT  31.68 26.285 62.766 27.019 ;
     RECT  31.68 27.019 63.342 27.211 ;
     RECT  64.728 27.739 64.746 27.751 ;
     RECT  64.656 27.751 64.746 27.779 ;
     RECT  64.656 27.779 64.674 27.821 ;
     RECT  31.68 27.211 63.882 27.985 ;
     RECT  31.68 27.985 63.954 28.247 ;
     RECT  49.86 28.247 63.954 28.301 ;
     RECT  49.86 28.301 63.918 28.319 ;
     RECT  31.68 28.247 49.086 28.489 ;
     RECT  49.86 28.319 62.73 28.949 ;
     RECT  61.2 28.949 62.73 29.131 ;
     RECT  63.864 28.319 63.918 29.131 ;
     RECT  61.2 29.131 63.918 29.255 ;
     RECT  61.524 29.255 63.918 29.261 ;
     RECT  24.015 26.789 30.51 29.533 ;
     RECT  24.015 29.533 30.798 29.633 ;
     RECT  2.415 2.413 2.697 29.659 ;
     RECT  0.108 29.605 0.126 29.707 ;
     RECT  2.415 29.659 3.186 29.731 ;
     RECT  2.415 29.731 3.582 29.759 ;
     RECT  3.42 29.759 3.582 29.831 ;
     RECT  61.524 29.261 63.882 29.831 ;
     RECT  0.108 29.707 0.342 29.837 ;
     RECT  3.564 29.831 3.582 29.837 ;
     RECT  2.415 29.759 2.697 29.911 ;
     RECT  2.376 29.911 2.697 30.065 ;
     RECT  61.524 29.831 63.342 30.125 ;
     RECT  61.524 30.125 63.306 30.139 ;
     RECT  64.728 30.136 64.746 30.145 ;
     RECT  64.656 30.145 64.746 30.173 ;
     RECT  49.86 28.949 60.426 30.235 ;
     RECT  49.86 30.235 60.498 30.415 ;
     RECT  49.86 30.415 60.642 30.883 ;
     RECT  61.416 30.139 63.306 30.883 ;
     RECT  64.656 30.173 64.674 31.051 ;
     RECT  64.62 31.051 64.674 31.081 ;
     RECT  64.62 31.081 64.746 31.109 ;
     RECT  64.656 31.109 64.746 31.133 ;
     RECT  49.86 30.883 63.306 31.147 ;
     RECT  64.656 31.133 64.674 31.217 ;
     RECT  49.86 31.147 63.378 31.243 ;
     RECT  24.015 29.633 30.51 31.387 ;
     RECT  24.015 31.387 30.798 31.487 ;
     RECT  49.86 31.243 63.882 32.071 ;
     RECT  31.608 28.489 49.086 32.225 ;
     RECT  49.86 32.071 63.918 32.225 ;
     RECT  49.86 32.225 62.802 32.297 ;
     RECT  49.86 32.297 62.73 32.639 ;
     RECT  49.86 32.639 53.997 32.873 ;
     RECT  54.72 32.639 62.73 33.259 ;
     RECT  63.864 32.225 63.918 33.385 ;
     RECT  54.72 33.259 62.766 33.413 ;
     RECT  53.715 32.873 53.997 33.421 ;
     RECT  54.72 33.413 60.534 33.421 ;
     RECT  61.272 33.413 62.766 33.449 ;
     RECT  53.715 33.421 60.534 33.647 ;
     RECT  54.72 33.647 60.534 33.725 ;
     RECT  54.72 33.725 60.426 33.809 ;
     RECT  63.864 33.385 63.954 33.869 ;
     RECT  54.72 33.809 60.39 33.989 ;
     RECT  54.792 33.989 60.39 34.151 ;
     RECT  54.972 34.151 60.39 34.205 ;
     RECT  61.272 33.449 62.73 34.259 ;
     RECT  61.815 34.259 62.73 34.315 ;
     RECT  63.864 33.869 63.918 34.315 ;
     RECT  61.815 34.315 63.918 34.385 ;
     RECT  49.86 32.873 52.722 34.421 ;
     RECT  56.124 34.205 60.39 34.627 ;
     RECT  24.015 31.487 30.51 34.799 ;
     RECT  56.124 34.627 61.002 34.799 ;
     RECT  61.815 34.385 62.766 34.961 ;
     RECT  54.972 34.205 54.99 34.969 ;
     RECT  54.828 34.969 54.99 35.005 ;
     RECT  52.704 34.421 52.722 35.069 ;
     RECT  63.864 34.385 63.918 35.083 ;
     RECT  56.196 34.799 61.002 35.437 ;
     RECT  61.815 34.961 62.73 35.437 ;
     RECT  56.196 35.437 62.73 35.453 ;
     RECT  63.864 35.083 63.954 35.467 ;
     RECT  56.196 35.453 56.826 35.671 ;
     RECT  63.864 35.467 63.99 35.707 ;
     RECT  21.315 2.413 21.597 35.743 ;
     RECT  21.315 35.743 21.654 35.779 ;
     RECT  63.828 35.707 63.99 35.879 ;
     RECT  21.315 35.779 21.798 35.941 ;
     RECT  57.564 35.453 62.73 35.947 ;
     RECT  63.828 35.879 63.954 35.947 ;
     RECT  55.872 35.671 56.826 35.995 ;
     RECT  55.728 35.995 56.826 36.041 ;
     RECT  57.564 35.947 63.954 36.239 ;
     RECT  21.315 35.941 21.942 36.283 ;
     RECT  55.8 36.041 56.826 36.331 ;
     RECT  57.564 36.239 62.766 36.331 ;
     RECT  63.864 36.239 63.954 36.347 ;
     RECT  31.68 32.225 49.086 36.391 ;
     RECT  24.015 34.799 30.438 36.481 ;
     RECT  55.8 36.331 62.766 36.509 ;
     RECT  24.015 36.481 30.726 36.553 ;
     RECT  31.464 36.391 49.086 36.553 ;
     RECT  21.315 36.283 22.158 36.589 ;
     RECT  22.896 36.517 22.914 36.589 ;
     RECT  54.72 35.005 54.99 36.931 ;
     RECT  55.8 36.509 60.426 36.931 ;
     RECT  53.715 33.647 53.997 37.021 ;
     RECT  61.2 36.509 62.766 37.099 ;
     RECT  63.864 36.347 63.918 37.099 ;
     RECT  53.604 37.021 53.997 37.193 ;
     RECT  21.315 36.589 22.914 37.201 ;
     RECT  54.72 36.931 60.426 37.435 ;
     RECT  61.2 37.099 63.918 37.435 ;
     RECT  54.72 37.435 63.918 37.463 ;
     RECT  21.315 37.201 22.95 37.471 ;
     RECT  24.015 36.553 49.086 37.769 ;
     RECT  49.86 34.421 51.678 37.831 ;
     RECT  54.72 37.463 62.73 37.859 ;
     RECT  54.756 37.859 62.73 37.931 ;
     RECT  21.315 37.471 23.094 37.939 ;
     RECT  24.015 37.769 30.582 37.939 ;
     RECT  49.86 37.831 52.29 37.949 ;
     RECT  63.864 37.463 63.918 38.059 ;
     RECT  54.972 37.931 62.73 38.251 ;
     RECT  63.864 38.059 63.954 38.251 ;
     RECT  54.972 38.251 63.954 38.471 ;
     RECT  54.972 38.471 62.19 38.477 ;
     RECT  63.288 38.471 63.954 38.507 ;
     RECT  61.308 38.477 62.19 38.573 ;
     RECT  21.315 37.939 30.582 38.741 ;
     RECT  31.356 37.769 49.086 38.741 ;
     RECT  30.492 38.741 30.582 38.785 ;
     RECT  54.972 38.477 60.534 38.821 ;
     RECT  30.492 38.785 30.942 39.119 ;
     RECT  53.715 37.193 53.997 39.181 ;
     RECT  31.68 38.741 49.086 39.307 ;
     RECT  49.86 37.949 51.678 39.307 ;
     RECT  61.308 38.573 62.097 39.325 ;
     RECT  61.308 39.325 62.154 39.361 ;
     RECT  63.288 38.507 63.918 39.361 ;
     RECT  61.308 39.361 62.226 39.479 ;
     RECT  21.315 38.741 29.697 39.595 ;
     RECT  30.492 39.119 30.762 39.595 ;
     RECT  53.604 39.181 53.997 39.623 ;
     RECT  54.72 38.821 60.534 39.721 ;
     RECT  21.315 39.595 30.762 39.749 ;
     RECT  31.68 39.307 51.678 39.749 ;
     RECT  54.72 39.721 60.714 39.749 ;
     RECT  54.756 39.749 54.99 39.785 ;
     RECT  55.872 39.749 60.714 39.785 ;
     RECT  57.6 39.785 60.714 39.857 ;
     RECT  30.492 39.749 30.762 39.901 ;
     RECT  63.288 39.361 63.954 40.163 ;
     RECT  61.815 39.479 62.226 40.171 ;
     RECT  30.492 39.901 30.87 40.441 ;
     RECT  31.68 39.749 49.086 40.441 ;
     RECT  61.815 40.171 62.73 40.441 ;
     RECT  55.872 39.785 56.754 40.531 ;
     RECT  57.6 39.857 60.498 40.531 ;
     RECT  54.792 39.785 54.99 40.555 ;
     RECT  55.872 40.531 60.498 40.555 ;
     RECT  54.792 40.555 60.498 40.603 ;
     RECT  61.272 40.441 62.73 40.603 ;
     RECT  63.864 40.163 63.954 40.651 ;
     RECT  63.864 40.651 63.99 40.973 ;
     RECT  54.792 40.603 62.73 41.035 ;
     RECT  63.864 40.973 63.954 41.035 ;
     RECT  54.792 41.035 63.954 41.071 ;
     RECT  21.315 39.749 29.697 41.251 ;
     RECT  30.492 40.441 49.086 41.251 ;
     RECT  54.72 41.071 63.954 41.549 ;
     RECT  54.72 41.549 62.097 41.909 ;
     RECT  55.728 41.909 62.097 41.981 ;
     RECT  21.315 41.251 49.086 42.323 ;
     RECT  53.715 39.623 53.997 42.427 ;
     RECT  54.72 41.909 54.99 42.427 ;
     RECT  21.315 42.323 30.798 42.557 ;
     RECT  53.715 42.427 54.99 42.557 ;
     RECT  63.288 41.549 63.954 42.571 ;
     RECT  21.315 42.557 30.51 42.593 ;
     RECT  31.68 42.323 49.086 42.601 ;
     RECT  49.86 39.749 51.678 42.601 ;
     RECT  55.944 41.981 62.097 42.691 ;
     RECT  63.288 42.571 64.638 42.691 ;
     RECT  55.944 42.691 64.638 43.033 ;
     RECT  55.872 43.033 64.638 43.061 ;
     RECT  55.872 43.061 63.954 43.181 ;
     RECT  55.872 43.181 63.882 43.661 ;
     RECT  21.315 42.593 29.697 43.835 ;
     RECT  54.72 42.557 54.99 44.311 ;
     RECT  55.872 43.661 62.334 44.311 ;
     RECT  54.72 44.311 62.334 44.491 ;
     RECT  63.288 43.661 63.882 44.491 ;
     RECT  54.72 44.491 63.882 45.067 ;
     RECT  54.72 45.067 63.918 45.259 ;
     RECT  54.72 45.259 63.954 45.797 ;
     RECT  54.72 45.797 63.918 46.157 ;
     RECT  53.715 42.557 53.997 46.651 ;
     RECT  54.72 46.157 63.81 46.891 ;
     RECT  31.68 42.601 51.678 47.011 ;
     RECT  53.028 46.651 53.997 47.011 ;
     RECT  31.68 47.011 53.997 47.075 ;
     RECT  29.376 43.835 29.697 47.083 ;
     RECT  30.492 42.593 30.51 47.083 ;
     RECT  52.416 47.075 53.997 47.183 ;
     RECT  29.376 47.083 30.51 47.213 ;
     RECT  54.72 46.891 63.882 47.741 ;
     RECT  55.728 47.741 63.882 47.849 ;
     RECT  31.68 47.075 51.678 47.929 ;
     RECT  53.028 47.183 53.997 47.993 ;
     RECT  56.016 47.849 63.882 48.271 ;
     RECT  56.016 48.271 63.954 48.389 ;
     RECT  56.124 48.389 63.954 48.461 ;
     RECT  54.72 47.741 54.99 48.475 ;
     RECT  54.72 48.475 55.242 48.667 ;
     RECT  31.5 47.929 51.678 48.811 ;
     RECT  30.492 47.213 30.51 48.901 ;
     RECT  31.248 48.811 51.678 48.901 ;
     RECT  54.72 48.667 55.386 49.171 ;
     RECT  56.124 48.461 63.918 49.171 ;
     RECT  53.715 47.993 53.997 50.089 ;
     RECT  54.72 49.171 63.918 50.089 ;
     RECT  53.715 50.089 63.918 50.387 ;
     RECT  64.728 50.395 64.746 50.431 ;
     RECT  64.656 50.431 64.746 50.459 ;
     RECT  64.656 50.459 64.674 50.477 ;
     RECT  54.72 50.387 63.918 50.573 ;
     RECT  63.864 50.573 63.918 51.019 ;
     RECT  30.492 48.901 51.678 51.125 ;
     RECT  50.436 51.125 51.678 51.169 ;
     RECT  54.72 50.573 62.946 51.197 ;
     RECT  21.315 43.835 28.494 51.241 ;
     RECT  63.864 51.019 63.954 51.431 ;
     RECT  56.415 51.197 62.946 51.499 ;
     RECT  63.864 51.431 63.882 51.499 ;
     RECT  50.436 51.169 51.894 51.503 ;
     RECT  54.72 51.197 55.53 51.581 ;
     RECT  21.315 51.241 28.53 51.691 ;
     RECT  29.376 47.213 29.697 51.691 ;
     RECT  21.315 51.691 29.697 51.943 ;
     RECT  30.492 51.125 49.194 51.943 ;
     RECT  56.415 51.499 63.882 52.171 ;
     RECT  56.088 52.171 63.882 52.439 ;
     RECT  54.72 51.581 54.99 52.459 ;
     RECT  56.088 52.439 62.766 52.507 ;
     RECT  54.72 52.459 55.098 52.549 ;
     RECT  54.72 52.549 55.242 52.555 ;
     RECT  56.052 52.507 62.766 52.555 ;
     RECT  63.828 52.439 63.882 52.589 ;
     RECT  54.72 52.555 62.766 52.619 ;
     RECT  55.728 52.619 62.766 53.087 ;
     RECT  63.864 52.589 63.882 53.131 ;
     RECT  63.864 53.131 63.918 53.429 ;
     RECT  54.72 52.619 54.99 53.563 ;
     RECT  55.728 53.087 60.894 53.563 ;
     RECT  61.815 53.087 62.766 53.611 ;
     RECT  63.864 53.429 63.882 53.611 ;
     RECT  54.72 53.563 60.894 53.995 ;
     RECT  54.72 53.995 61.002 54.211 ;
     RECT  61.815 53.611 63.882 54.211 ;
     RECT  54.72 54.211 63.882 54.365 ;
     RECT  61.815 54.365 63.882 54.401 ;
     RECT  54.72 54.365 61.038 54.653 ;
     RECT  54.72 54.653 60.894 54.671 ;
     RECT  61.815 54.401 62.766 54.701 ;
     RECT  63.864 54.401 63.882 54.955 ;
     RECT  54.72 54.671 60.858 54.977 ;
     RECT  63.864 54.955 63.918 55.021 ;
     RECT  55.728 54.977 60.858 55.175 ;
     RECT  63.864 55.021 63.954 55.373 ;
     RECT  61.815 54.701 62.73 55.531 ;
     RECT  63.864 55.373 63.882 55.531 ;
     RECT  55.764 55.175 60.858 55.553 ;
     RECT  61.815 55.531 63.882 55.921 ;
     RECT  55.944 55.553 60.858 55.957 ;
     RECT  61.596 55.921 63.882 55.957 ;
     RECT  55.944 55.957 63.882 56.129 ;
     RECT  55.944 56.129 63.342 56.255 ;
     RECT  53.715 50.387 53.997 56.569 ;
     RECT  53.604 56.569 53.997 56.641 ;
     RECT  54.72 54.977 54.99 56.641 ;
     RECT  57.924 56.255 63.342 56.875 ;
     RECT  53.604 56.641 54.99 57.001 ;
     RECT  55.944 56.255 57.15 57.001 ;
     RECT  53.604 57.001 57.15 57.067 ;
     RECT  57.924 56.875 63.882 57.067 ;
     RECT  53.604 57.067 63.882 57.101 ;
     RECT  53.715 57.101 63.882 57.163 ;
     RECT  53.715 57.163 63.918 57.181 ;
     RECT  53.715 57.181 63.954 57.299 ;
     RECT  55.8 57.299 56.697 57.371 ;
     RECT  57.564 57.299 63.954 57.371 ;
     RECT  57.924 57.371 63.954 57.389 ;
     RECT  57.924 57.389 63.882 57.443 ;
     RECT  63.288 57.443 63.342 57.479 ;
     RECT  55.836 57.371 56.697 57.569 ;
     RECT  57.924 57.443 62.442 57.569 ;
     RECT  58.104 57.569 59.85 57.629 ;
     RECT  53.715 57.299 54.99 57.641 ;
     RECT  50.436 51.503 51.678 57.713 ;
     RECT  58.104 57.629 59.397 57.713 ;
     RECT  60.732 57.569 60.75 57.713 ;
     RECT  53.715 57.641 54.81 57.749 ;
     RECT  2.415 30.065 2.697 57.797 ;
     RECT  5.115 2.413 5.397 57.797 ;
     RECT  7.815 2.413 8.097 57.797 ;
     RECT  10.515 2.413 10.797 57.797 ;
     RECT  13.215 2.413 13.497 57.797 ;
     RECT  15.915 2.413 16.197 57.797 ;
     RECT  18.615 2.413 18.897 57.797 ;
     RECT  21.315 51.943 49.194 57.797 ;
     RECT  51.015 57.713 51.678 57.797 ;
     RECT  53.715 57.749 53.997 57.797 ;
     RECT  61.815 57.569 62.097 57.797 ;
     RECT  55.944 57.569 56.697 57.875 ;
     RECT  63.324 57.479 63.342 57.875 ;
     RECT  58.284 57.713 59.397 57.947 ;
     RECT  54.72 57.749 54.81 58.019 ;
     RECT  2.607 57.797 2.697 58.067 ;
     RECT  5.307 57.797 5.397 58.067 ;
     RECT  8.007 57.797 8.097 58.067 ;
     RECT  10.707 57.797 10.797 58.067 ;
     RECT  13.407 57.797 13.497 58.067 ;
     RECT  16.107 57.797 16.197 58.067 ;
     RECT  18.807 57.797 18.897 58.067 ;
     RECT  21.507 57.797 49.194 58.067 ;
     RECT  51.207 57.797 51.678 58.067 ;
     RECT  53.907 57.797 53.997 58.067 ;
     RECT  56.607 57.875 56.697 58.067 ;
     RECT  59.307 57.947 59.397 58.067 ;
     RECT  62.007 57.797 62.097 58.067 ;
     RECT  58.284 57.947 58.374 58.109 ;
     RECT  54.72 58.019 54.738 58.145 ;
     RECT  58.284 58.109 58.302 58.145 ;
     RECT  49.176 58.067 49.194 58.721 ;
     RECT  51.66 58.067 51.678 59.567 ;
     RECT  21.636 58.067 48.15 60.413 ;
     RECT  21.636 60.413 47.898 60.419 ;
     RECT  21.654 60.419 21.708 60.444 ;
     RECT  21.726 60.419 21.78 60.444 ;
     RECT  21.798 60.419 21.852 60.444 ;
     RECT  21.87 60.419 21.924 60.444 ;
     RECT  21.942 60.419 21.996 60.444 ;
     RECT  22.014 60.419 22.068 60.444 ;
     RECT  22.086 60.419 22.14 60.444 ;
     RECT  22.158 60.419 22.212 60.444 ;
     RECT  22.23 60.419 22.284 60.444 ;
     RECT  22.302 60.419 22.356 60.444 ;
     RECT  22.374 60.419 22.428 60.444 ;
     RECT  22.446 60.419 22.5 60.444 ;
     RECT  22.518 60.419 22.572 60.444 ;
     RECT  22.59 60.419 22.644 60.444 ;
     RECT  22.662 60.419 22.716 60.444 ;
     RECT  22.734 60.419 22.788 60.444 ;
     RECT  22.806 60.419 22.86 60.444 ;
     RECT  22.878 60.419 22.932 60.444 ;
     RECT  22.95 60.419 23.004 60.444 ;
     RECT  23.022 60.419 23.076 60.444 ;
     RECT  23.094 60.419 23.148 60.444 ;
     RECT  23.166 60.419 23.22 60.444 ;
     RECT  23.238 60.419 23.292 60.444 ;
     RECT  23.31 60.419 23.364 60.444 ;
     RECT  23.382 60.419 23.436 60.444 ;
     RECT  23.454 60.419 23.508 60.444 ;
     RECT  23.526 60.419 23.58 60.444 ;
     RECT  23.598 60.419 23.652 60.444 ;
     RECT  23.67 60.419 23.724 60.444 ;
     RECT  23.742 60.419 23.796 60.444 ;
     RECT  23.814 60.419 23.868 60.444 ;
     RECT  23.886 60.419 23.94 60.444 ;
     RECT  23.958 60.419 24.012 60.444 ;
     RECT  24.03 60.419 24.084 60.444 ;
     RECT  24.102 60.419 24.156 60.444 ;
     RECT  24.174 60.419 24.228 60.444 ;
     RECT  24.246 60.419 24.3 60.444 ;
     RECT  24.318 60.419 24.372 60.444 ;
     RECT  24.39 60.419 24.444 60.444 ;
     RECT  24.462 60.419 24.516 60.444 ;
     RECT  24.534 60.419 24.588 60.444 ;
     RECT  24.606 60.419 24.66 60.444 ;
     RECT  24.678 60.419 24.732 60.444 ;
     RECT  24.75 60.419 24.804 60.444 ;
     RECT  24.822 60.419 24.876 60.444 ;
     RECT  24.894 60.419 24.948 60.444 ;
     RECT  24.966 60.419 25.02 60.444 ;
     RECT  25.038 60.419 25.092 60.444 ;
     RECT  25.11 60.419 25.164 60.444 ;
     RECT  25.182 60.419 25.236 60.444 ;
     RECT  25.254 60.419 25.308 60.444 ;
     RECT  25.326 60.419 25.38 60.444 ;
     RECT  25.398 60.419 25.452 60.444 ;
     RECT  25.47 60.419 25.524 60.444 ;
     RECT  25.542 60.419 25.596 60.444 ;
     RECT  25.614 60.419 25.668 60.444 ;
     RECT  25.686 60.419 25.74 60.444 ;
     RECT  25.758 60.419 25.812 60.444 ;
     RECT  25.83 60.419 25.884 60.444 ;
     RECT  25.902 60.419 25.956 60.444 ;
     RECT  25.974 60.419 26.028 60.444 ;
     RECT  26.046 60.419 26.1 60.444 ;
     RECT  26.118 60.419 26.172 60.444 ;
     RECT  26.19 60.419 26.244 60.444 ;
     RECT  26.262 60.419 26.316 60.444 ;
     RECT  26.334 60.419 26.388 60.444 ;
     RECT  26.406 60.419 26.46 60.444 ;
     RECT  26.478 60.419 26.532 60.444 ;
     RECT  26.55 60.419 26.604 60.444 ;
     RECT  26.622 60.419 26.676 60.444 ;
     RECT  26.694 60.419 26.748 60.444 ;
     RECT  26.766 60.419 26.82 60.444 ;
     RECT  26.838 60.419 26.892 60.444 ;
     RECT  26.91 60.419 26.964 60.444 ;
     RECT  26.982 60.419 27.036 60.444 ;
     RECT  27.054 60.419 27.108 60.444 ;
     RECT  27.126 60.419 27.18 60.444 ;
     RECT  27.198 60.419 27.252 60.444 ;
     RECT  27.27 60.419 27.324 60.444 ;
     RECT  27.342 60.419 27.396 60.444 ;
     RECT  27.414 60.419 27.468 60.444 ;
     RECT  27.486 60.419 27.54 60.444 ;
     RECT  27.558 60.419 27.612 60.444 ;
     RECT  27.63 60.419 27.684 60.444 ;
     RECT  27.702 60.419 27.756 60.444 ;
     RECT  27.774 60.419 27.828 60.444 ;
     RECT  27.846 60.419 27.9 60.444 ;
     RECT  27.918 60.419 27.972 60.444 ;
     RECT  27.99 60.419 28.044 60.444 ;
     RECT  28.062 60.419 28.116 60.444 ;
     RECT  28.134 60.419 28.188 60.444 ;
     RECT  28.206 60.419 28.26 60.444 ;
     RECT  28.278 60.419 28.332 60.444 ;
     RECT  28.35 60.419 28.404 60.444 ;
     RECT  28.422 60.419 28.476 60.444 ;
     RECT  28.494 60.419 28.548 60.444 ;
     RECT  28.566 60.419 28.62 60.444 ;
     RECT  28.638 60.419 28.692 60.444 ;
     RECT  28.71 60.419 28.764 60.444 ;
     RECT  28.782 60.419 28.836 60.444 ;
     RECT  28.854 60.419 28.908 60.444 ;
     RECT  28.926 60.419 28.98 60.444 ;
     RECT  28.998 60.419 29.052 60.444 ;
     RECT  29.07 60.419 29.124 60.444 ;
     RECT  29.142 60.419 29.196 60.444 ;
     RECT  29.214 60.419 29.268 60.444 ;
     RECT  29.286 60.419 29.34 60.444 ;
     RECT  29.358 60.419 29.412 60.444 ;
     RECT  29.43 60.419 29.484 60.444 ;
     RECT  29.502 60.419 29.556 60.444 ;
     RECT  29.574 60.419 29.628 60.444 ;
     RECT  29.646 60.419 29.7 60.444 ;
     RECT  29.718 60.419 29.772 60.444 ;
     RECT  29.79 60.419 29.844 60.444 ;
     RECT  29.862 60.419 29.916 60.444 ;
     RECT  29.934 60.419 29.988 60.444 ;
     RECT  30.006 60.419 30.06 60.444 ;
     RECT  30.078 60.419 30.132 60.444 ;
     RECT  30.15 60.419 30.204 60.444 ;
     RECT  30.222 60.419 30.276 60.444 ;
     RECT  30.294 60.419 30.348 60.444 ;
     RECT  30.366 60.419 30.42 60.444 ;
     RECT  30.438 60.419 30.492 60.444 ;
     RECT  30.51 60.419 30.564 60.444 ;
     RECT  30.582 60.419 30.636 60.444 ;
     RECT  30.654 60.419 30.708 60.444 ;
     RECT  30.726 60.419 30.78 60.444 ;
     RECT  30.798 60.419 30.852 60.444 ;
     RECT  30.87 60.419 30.924 60.444 ;
     RECT  30.942 60.419 30.996 60.444 ;
     RECT  31.014 60.419 31.068 60.444 ;
     RECT  31.086 60.419 31.14 60.444 ;
     RECT  31.158 60.419 31.212 60.444 ;
     RECT  31.23 60.419 31.284 60.444 ;
     RECT  31.302 60.419 31.356 60.444 ;
     RECT  31.374 60.419 31.428 60.444 ;
     RECT  31.446 60.419 31.5 60.444 ;
     RECT  31.518 60.419 31.572 60.444 ;
     RECT  31.59 60.419 31.644 60.444 ;
     RECT  31.662 60.419 31.716 60.444 ;
     RECT  31.734 60.419 31.788 60.444 ;
     RECT  31.806 60.419 31.86 60.444 ;
     RECT  31.878 60.419 31.932 60.444 ;
     RECT  31.95 60.419 32.004 60.444 ;
     RECT  32.022 60.419 32.076 60.444 ;
     RECT  32.094 60.419 32.148 60.444 ;
     RECT  32.166 60.419 32.22 60.444 ;
     RECT  32.238 60.419 32.292 60.444 ;
     RECT  32.31 60.419 32.364 60.444 ;
     RECT  32.382 60.419 32.436 60.444 ;
     RECT  32.454 60.419 32.508 60.444 ;
     RECT  32.526 60.419 32.58 60.444 ;
     RECT  32.598 60.419 32.652 60.444 ;
     RECT  32.67 60.419 32.724 60.444 ;
     RECT  32.742 60.419 32.796 60.444 ;
     RECT  32.814 60.419 32.868 60.444 ;
     RECT  32.886 60.419 32.94 60.444 ;
     RECT  32.958 60.419 33.012 60.444 ;
     RECT  33.03 60.419 33.084 60.444 ;
     RECT  33.102 60.419 33.156 60.444 ;
     RECT  33.174 60.419 33.228 60.444 ;
     RECT  33.246 60.419 33.3 60.444 ;
     RECT  33.318 60.419 33.372 60.444 ;
     RECT  33.39 60.419 33.444 60.444 ;
     RECT  33.462 60.419 33.516 60.444 ;
     RECT  33.534 60.419 33.588 60.444 ;
     RECT  33.606 60.419 33.66 60.444 ;
     RECT  33.678 60.419 33.732 60.444 ;
     RECT  33.75 60.419 33.804 60.444 ;
     RECT  33.822 60.419 33.876 60.444 ;
     RECT  33.894 60.419 33.948 60.444 ;
     RECT  33.966 60.419 34.02 60.444 ;
     RECT  34.038 60.419 34.092 60.444 ;
     RECT  34.11 60.419 34.164 60.444 ;
     RECT  34.182 60.419 34.236 60.444 ;
     RECT  34.254 60.419 34.308 60.444 ;
     RECT  34.326 60.419 34.38 60.444 ;
     RECT  34.398 60.419 34.452 60.444 ;
     RECT  34.47 60.419 34.524 60.444 ;
     RECT  34.542 60.419 34.596 60.444 ;
     RECT  34.614 60.419 34.668 60.444 ;
     RECT  34.686 60.419 34.74 60.444 ;
     RECT  34.758 60.419 34.812 60.444 ;
     RECT  34.83 60.419 34.884 60.444 ;
     RECT  34.902 60.419 34.956 60.444 ;
     RECT  34.974 60.419 35.028 60.444 ;
     RECT  35.046 60.419 35.1 60.444 ;
     RECT  35.118 60.419 35.172 60.444 ;
     RECT  35.19 60.419 35.244 60.444 ;
     RECT  35.262 60.419 35.316 60.444 ;
     RECT  35.334 60.419 35.388 60.444 ;
     RECT  35.406 60.419 36.036 60.444 ;
     RECT  36.054 60.419 36.108 60.444 ;
     RECT  36.126 60.419 36.18 60.444 ;
     RECT  36.198 60.419 36.252 60.444 ;
     RECT  36.27 60.419 36.324 60.444 ;
     RECT  36.342 60.419 36.396 60.444 ;
     RECT  36.414 60.419 36.468 60.444 ;
     RECT  36.486 60.419 36.54 60.444 ;
     RECT  36.558 60.419 36.612 60.444 ;
     RECT  36.63 60.419 36.684 60.444 ;
     RECT  36.702 60.419 36.756 60.444 ;
     RECT  36.774 60.419 36.828 60.444 ;
     RECT  36.846 60.419 36.9 60.444 ;
     RECT  36.918 60.419 36.972 60.444 ;
     RECT  36.99 60.419 37.044 60.444 ;
     RECT  37.062 60.419 37.116 60.444 ;
     RECT  37.134 60.419 37.188 60.444 ;
     RECT  37.206 60.419 37.26 60.444 ;
     RECT  37.278 60.419 37.332 60.444 ;
     RECT  37.35 60.419 37.404 60.444 ;
     RECT  37.422 60.419 37.476 60.444 ;
     RECT  37.494 60.419 37.548 60.444 ;
     RECT  37.566 60.419 37.62 60.444 ;
     RECT  37.638 60.419 37.692 60.444 ;
     RECT  37.71 60.419 37.764 60.444 ;
     RECT  37.782 60.419 37.836 60.444 ;
     RECT  37.854 60.419 37.908 60.444 ;
     RECT  37.926 60.419 37.98 60.444 ;
     RECT  37.998 60.419 38.052 60.444 ;
     RECT  38.07 60.419 38.124 60.444 ;
     RECT  38.142 60.419 38.196 60.444 ;
     RECT  38.214 60.419 38.268 60.444 ;
     RECT  38.286 60.419 38.34 60.444 ;
     RECT  38.358 60.419 38.412 60.444 ;
     RECT  38.43 60.419 38.484 60.444 ;
     RECT  38.502 60.419 38.556 60.444 ;
     RECT  38.574 60.419 38.628 60.444 ;
     RECT  38.646 60.419 38.7 60.444 ;
     RECT  38.718 60.419 38.772 60.444 ;
     RECT  38.79 60.419 38.844 60.444 ;
     RECT  38.862 60.419 38.916 60.444 ;
     RECT  38.934 60.419 38.988 60.444 ;
     RECT  39.006 60.419 39.06 60.444 ;
     RECT  39.078 60.419 39.132 60.444 ;
     RECT  39.15 60.419 39.204 60.444 ;
     RECT  39.222 60.419 39.276 60.444 ;
     RECT  39.294 60.419 39.348 60.444 ;
     RECT  39.366 60.419 39.42 60.444 ;
     RECT  39.438 60.419 39.492 60.444 ;
     RECT  39.51 60.419 39.564 60.444 ;
     RECT  39.582 60.419 39.636 60.444 ;
     RECT  39.654 60.419 39.708 60.444 ;
     RECT  39.726 60.419 39.78 60.444 ;
     RECT  39.798 60.419 39.852 60.444 ;
     RECT  39.87 60.419 39.924 60.444 ;
     RECT  39.942 60.419 39.996 60.444 ;
     RECT  40.014 60.419 40.068 60.444 ;
     RECT  40.086 60.419 40.14 60.444 ;
     RECT  40.158 60.419 40.212 60.444 ;
     RECT  40.23 60.419 40.284 60.444 ;
     RECT  40.302 60.419 40.356 60.444 ;
     RECT  40.374 60.419 40.428 60.444 ;
     RECT  40.446 60.419 40.5 60.444 ;
     RECT  40.518 60.419 40.572 60.444 ;
     RECT  40.59 60.419 40.644 60.444 ;
     RECT  40.662 60.419 40.716 60.444 ;
     RECT  40.734 60.419 40.788 60.444 ;
     RECT  40.806 60.419 40.86 60.444 ;
     RECT  40.878 60.419 40.932 60.444 ;
     RECT  40.95 60.419 41.004 60.444 ;
     RECT  41.022 60.419 41.076 60.444 ;
     RECT  41.094 60.419 41.148 60.444 ;
     RECT  41.166 60.419 41.22 60.444 ;
     RECT  41.238 60.419 41.292 60.444 ;
     RECT  41.31 60.419 41.364 60.444 ;
     RECT  41.382 60.419 41.436 60.444 ;
     RECT  41.454 60.419 41.508 60.444 ;
     RECT  41.526 60.419 41.58 60.444 ;
     RECT  41.598 60.419 41.652 60.444 ;
     RECT  41.67 60.419 41.724 60.444 ;
     RECT  41.742 60.419 41.796 60.444 ;
     RECT  41.814 60.419 41.868 60.444 ;
     RECT  41.886 60.419 41.94 60.444 ;
     RECT  41.958 60.419 42.012 60.444 ;
     RECT  42.03 60.419 42.084 60.444 ;
     RECT  42.102 60.419 42.156 60.444 ;
     RECT  42.174 60.419 42.228 60.444 ;
     RECT  42.246 60.419 42.3 60.444 ;
     RECT  42.318 60.419 42.372 60.444 ;
     RECT  42.39 60.419 42.444 60.444 ;
     RECT  42.462 60.419 42.516 60.444 ;
     RECT  42.534 60.419 42.588 60.444 ;
     RECT  42.606 60.419 42.66 60.444 ;
     RECT  42.678 60.419 42.732 60.444 ;
     RECT  42.75 60.419 42.804 60.444 ;
     RECT  42.822 60.419 42.876 60.444 ;
     RECT  42.894 60.419 42.948 60.444 ;
     RECT  42.966 60.419 43.02 60.444 ;
     RECT  43.038 60.419 43.092 60.444 ;
     RECT  43.11 60.419 43.164 60.444 ;
     RECT  43.182 60.419 43.236 60.444 ;
     RECT  43.254 60.419 43.308 60.444 ;
     RECT  43.326 60.419 43.38 60.444 ;
     RECT  43.398 60.419 43.452 60.444 ;
     RECT  43.47 60.419 43.524 60.444 ;
     RECT  43.542 60.419 43.596 60.444 ;
     RECT  43.614 60.419 43.668 60.444 ;
     RECT  43.686 60.419 43.74 60.444 ;
     RECT  43.758 60.419 43.812 60.444 ;
     RECT  43.83 60.419 43.884 60.444 ;
     RECT  43.902 60.419 43.956 60.444 ;
     RECT  43.974 60.419 44.028 60.444 ;
     RECT  44.046 60.419 44.1 60.444 ;
     RECT  44.118 60.419 44.172 60.444 ;
     RECT  44.19 60.419 44.244 60.444 ;
     RECT  44.262 60.419 44.316 60.444 ;
     RECT  44.334 60.419 44.388 60.444 ;
     RECT  44.406 60.419 44.46 60.444 ;
     RECT  44.478 60.419 44.532 60.444 ;
     RECT  44.55 60.419 44.604 60.444 ;
     RECT  44.622 60.419 44.676 60.444 ;
     RECT  44.694 60.419 44.748 60.444 ;
     RECT  44.766 60.419 44.82 60.444 ;
     RECT  44.838 60.419 44.892 60.444 ;
     RECT  44.91 60.419 44.964 60.444 ;
     RECT  44.982 60.419 45.036 60.444 ;
     RECT  45.054 60.419 45.108 60.444 ;
     RECT  45.126 60.419 45.18 60.444 ;
     RECT  45.198 60.419 45.252 60.444 ;
     RECT  45.27 60.419 45.324 60.444 ;
     RECT  45.342 60.419 45.396 60.444 ;
     RECT  45.414 60.419 45.468 60.444 ;
     RECT  45.486 60.419 45.54 60.444 ;
     RECT  45.558 60.419 45.612 60.444 ;
     RECT  45.63 60.419 45.684 60.444 ;
     RECT  45.702 60.419 45.756 60.444 ;
     RECT  45.774 60.419 45.828 60.444 ;
     RECT  45.846 60.419 45.9 60.444 ;
     RECT  45.918 60.419 45.972 60.444 ;
     RECT  45.99 60.419 46.044 60.444 ;
     RECT  46.062 60.419 46.116 60.444 ;
     RECT  46.134 60.419 46.188 60.444 ;
     RECT  46.206 60.419 46.26 60.444 ;
     RECT  46.278 60.419 46.332 60.444 ;
     RECT  46.35 60.419 46.404 60.444 ;
     RECT  46.422 60.419 46.476 60.444 ;
     RECT  46.494 60.419 46.548 60.444 ;
     RECT  46.566 60.419 46.62 60.444 ;
     RECT  46.638 60.419 46.692 60.444 ;
     RECT  46.71 60.419 46.764 60.444 ;
     RECT  46.782 60.419 46.836 60.444 ;
     RECT  46.854 60.419 46.908 60.444 ;
     RECT  46.926 60.419 46.98 60.444 ;
     RECT  46.998 60.419 47.052 60.444 ;
     RECT  47.07 60.419 47.124 60.444 ;
     RECT  47.142 60.419 47.196 60.444 ;
     RECT  47.214 60.419 47.268 60.444 ;
     RECT  47.286 60.419 47.34 60.444 ;
     RECT  47.358 60.419 47.412 60.444 ;
     RECT  47.43 60.419 47.484 60.444 ;
     RECT  47.502 60.419 47.898 60.444 ;
     RECT  46.44 60.444 46.458 60.449 ;
     RECT  47.88 60.444 47.898 60.449 ;
    LAYER M4 ;
     RECT  0.084 29.616 0.179 29.64 ;
     RECT  0.06 29.64 0.179 29.712 ;
     RECT  0.084 29.712 0.179 29.736 ;
     RECT  0.06 29.736 0.179 29.808 ;
     RECT  0.084 29.808 0.179 29.832 ;
     RECT  0.179 29.712 0.353 29.832 ;
     RECT  0.353 29.808 2.408 29.832 ;
     RECT  0.133 31.728 2.408 31.752 ;
     RECT  2.408 2.148 2.512 57.792 ;
     RECT  2.512 2.418 2.6 57.792 ;
     RECT  2.6 2.418 2.704 58.062 ;
     RECT  2.704 29.664 3.241 29.832 ;
     RECT  3.241 29.808 3.593 29.832 ;
     RECT  2.704 11.136 5.108 11.16 ;
     RECT  2.704 31.728 5.108 31.752 ;
     RECT  5.108 2.148 5.212 57.792 ;
     RECT  5.212 2.418 5.3 57.792 ;
     RECT  5.3 2.418 5.404 58.062 ;
     RECT  5.404 11.136 7.808 11.16 ;
     RECT  5.404 31.728 7.808 31.752 ;
     RECT  7.808 2.148 7.912 57.792 ;
     RECT  7.912 2.418 8 57.792 ;
     RECT  8 2.418 8.104 58.062 ;
     RECT  8.104 11.136 10.508 11.16 ;
     RECT  8.104 31.728 10.508 31.752 ;
     RECT  10.508 2.148 10.612 57.792 ;
     RECT  10.612 2.418 10.7 57.792 ;
     RECT  10.7 2.418 10.804 58.062 ;
     RECT  10.804 11.136 13.208 11.16 ;
     RECT  10.804 31.728 13.208 31.752 ;
     RECT  13.208 2.148 13.312 57.792 ;
     RECT  13.312 2.418 13.4 57.792 ;
     RECT  13.4 2.418 13.504 58.062 ;
     RECT  13.504 11.136 15.908 11.16 ;
     RECT  13.504 31.728 15.908 31.752 ;
     RECT  15.908 2.148 16.012 57.792 ;
     RECT  16.012 2.418 16.1 57.792 ;
     RECT  16.1 2.418 16.204 58.062 ;
     RECT  16.204 11.136 18.608 11.16 ;
     RECT  16.204 31.728 18.608 31.752 ;
     RECT  18.608 2.148 18.712 57.792 ;
     RECT  18.712 2.418 18.8 57.792 ;
     RECT  18.8 2.418 18.904 58.062 ;
     RECT  18.904 11.136 21.308 11.16 ;
     RECT  18.904 31.728 21.308 31.752 ;
     RECT  21.308 2.148 21.412 57.792 ;
     RECT  21.412 2.418 21.5 57.792 ;
     RECT  21.5 2.418 21.604 58.062 ;
     RECT  21.604 11.136 24.008 11.16 ;
     RECT  21.604 31.728 24.008 31.752 ;
     RECT  24.008 2.148 24.112 57.792 ;
     RECT  24.112 2.418 24.2 57.792 ;
     RECT  24.2 2.418 24.304 58.062 ;
     RECT  25.436 60.288 25.469 60.312 ;
     RECT  25.469 60.192 25.553 60.312 ;
     RECT  25.957 38.688 26.045 38.712 ;
     RECT  25.553 60.24 26.197 60.312 ;
     RECT  26.449 56.496 26.533 56.52 ;
     RECT  26.341 57.792 26.533 57.816 ;
     RECT  26.197 60.24 26.581 60.36 ;
     RECT  24.304 11.136 26.708 11.16 ;
     RECT  24.304 31.728 26.708 31.752 ;
     RECT  26.581 33.648 26.708 33.672 ;
     RECT  26.045 38.688 26.708 39.336 ;
     RECT  26.245 41.472 26.708 41.496 ;
     RECT  26.437 43.008 26.708 43.032 ;
     RECT  26.389 55.44 26.708 55.464 ;
     RECT  26.533 56.496 26.708 57.816 ;
     RECT  26.708 2.148 26.812 57.816 ;
     RECT  26.812 2.418 26.9 57.816 ;
     RECT  26.9 2.418 27.004 58.062 ;
     RECT  26.581 60.192 27.025 60.36 ;
     RECT  27.025 60.192 27.245 60.408 ;
     RECT  27.004 41.472 27.317 41.496 ;
     RECT  27.004 32.976 27.353 33.672 ;
     RECT  27.245 60.192 27.685 60.312 ;
     RECT  27.353 32.976 27.929 33 ;
     RECT  27.004 55.44 27.929 55.464 ;
     RECT  27.089 58.656 27.929 58.68 ;
     RECT  27.004 38.688 27.973 40.44 ;
     RECT  27.004 56.496 28.069 57.432 ;
     RECT  27.004 43.008 28.105 44.184 ;
     RECT  27.997 46.704 28.145 46.728 ;
     RECT  28.105 42.192 28.429 44.184 ;
     RECT  27.004 31.728 28.637 31.752 ;
     RECT  28.261 52.416 28.753 52.44 ;
     RECT  28.141 36.816 29.005 36.84 ;
     RECT  29.005 36.432 29.041 36.84 ;
     RECT  27.973 38.64 29.125 40.44 ;
     RECT  27.004 54.384 29.173 54.408 ;
     RECT  28.069 56.496 29.213 58.296 ;
     RECT  28.753 51.696 29.269 52.44 ;
     RECT  27.004 11.136 29.408 11.16 ;
     RECT  28.637 31.728 29.408 31.896 ;
     RECT  29.041 35.76 29.408 36.84 ;
     RECT  29.125 38.64 29.408 40.968 ;
     RECT  28.429 42 29.408 44.184 ;
     RECT  28.357 47.088 29.408 47.112 ;
     RECT  28.165 49.248 29.408 49.272 ;
     RECT  29.269 51.216 29.408 52.44 ;
     RECT  29.173 54.384 29.408 55.176 ;
     RECT  29.213 56.496 29.408 58.68 ;
     RECT  27.685 59.808 29.437 60.312 ;
     RECT  29.408 2.148 29.512 58.68 ;
     RECT  29.512 2.418 29.704 58.68 ;
     RECT  29.704 47.088 29.801 47.208 ;
     RECT  29.704 38.64 30.233 39.576 ;
     RECT  29.704 54.384 30.524 58.68 ;
     RECT  29.437 59.808 30.524 60.408 ;
     RECT  30.524 54.384 30.611 60.408 ;
     RECT  29.704 42 30.709 43.032 ;
     RECT  30.709 41.088 30.845 43.032 ;
     RECT  30.611 59.808 30.917 60.408 ;
     RECT  30.611 54.384 30.947 58.776 ;
     RECT  30.917 60.24 30.947 60.408 ;
     RECT  30.947 54.384 30.949 58.68 ;
     RECT  30.949 53.808 31.601 58.68 ;
     RECT  29.704 51.216 31.669 51.72 ;
     RECT  31.669 50.736 31.705 51.72 ;
     RECT  29.704 36.816 31.717 36.84 ;
     RECT  30.947 60.288 31.957 60.408 ;
     RECT  31.957 60.24 32.101 60.408 ;
     RECT  29.704 11.136 32.108 11.16 ;
     RECT  30.997 27.168 32.108 27.192 ;
     RECT  29.704 31.728 32.108 31.752 ;
     RECT  29.704 35.76 32.108 35.784 ;
     RECT  31.717 36.816 32.108 37.416 ;
     RECT  30.233 38.688 32.108 39.576 ;
     RECT  30.845 41.184 32.108 43.032 ;
     RECT  29.704 44.16 32.108 44.184 ;
     RECT  29.801 47.184 32.108 47.208 ;
     RECT  29.704 49.248 32.108 49.272 ;
     RECT  31.705 50.304 32.108 51.72 ;
     RECT  31.601 53.808 32.108 58.296 ;
     RECT  32.108 2.148 32.212 58.296 ;
     RECT  32.212 2.418 32.404 58.296 ;
     RECT  32.404 29.568 33.077 30.264 ;
     RECT  32.404 26.064 33.149 27.912 ;
     RECT  33.077 29.568 33.221 29.64 ;
     RECT  32.404 50.304 33.365 50.328 ;
     RECT  33.149 27.888 33.541 27.912 ;
     RECT  33.221 29.568 33.617 29.592 ;
     RECT  32.404 56.304 33.637 58.296 ;
     RECT  32.101 59.76 33.637 60.408 ;
     RECT  33.541 27.888 33.725 28.44 ;
     RECT  33.637 56.304 33.725 60.408 ;
     RECT  33.725 27.888 33.761 27.912 ;
     RECT  32.404 31.728 33.829 31.896 ;
     RECT  32.404 47.088 34.261 47.112 ;
     RECT  33.149 26.064 34.501 26.76 ;
     RECT  33.829 30.864 34.597 31.896 ;
     RECT  34.405 33.072 34.597 33.096 ;
     RECT  34.597 30.864 34.693 33.096 ;
     RECT  32.404 11.136 34.808 11.16 ;
     RECT  32.404 17.088 34.808 17.448 ;
     RECT  34.501 26.064 34.808 27.192 ;
     RECT  34.693 30.864 34.808 33.576 ;
     RECT  32.404 35.76 34.808 35.784 ;
     RECT  32.404 36.816 34.808 37.416 ;
     RECT  32.404 38.688 34.808 39.576 ;
     RECT  32.404 41.184 34.808 43.032 ;
     RECT  32.404 44.16 34.808 44.184 ;
     RECT  33.925 45.552 34.808 45.576 ;
     RECT  34.261 46.752 34.808 47.112 ;
     RECT  32.404 49.248 34.808 49.272 ;
     RECT  32.404 51.696 34.808 51.72 ;
     RECT  34.261 52.944 34.808 52.968 ;
     RECT  32.404 54.384 34.808 55.272 ;
     RECT  33.725 56.304 34.808 58.296 ;
     RECT  34.808 2.148 34.885 58.296 ;
     RECT  34.885 2.148 34.912 58.68 ;
     RECT  33.725 60.192 34.981 60.408 ;
     RECT  34.981 60.096 35.077 60.408 ;
     RECT  34.912 2.418 35.104 58.68 ;
     RECT  35.104 31.008 35.201 33.624 ;
     RECT  35.077 60 35.267 60.408 ;
     RECT  35.104 27.168 35.309 27.912 ;
     RECT  35.201 31.008 35.356 31.944 ;
     RECT  35.104 56.496 35.365 58.68 ;
     RECT  35.104 51.696 35.411 53.016 ;
     RECT  35.104 54.384 35.411 54.792 ;
     RECT  35.365 56.496 35.453 59.256 ;
     RECT  35.453 56.496 35.525 57.672 ;
     RECT  35.453 58.656 35.525 59.256 ;
     RECT  35.525 58.656 35.561 58.68 ;
     RECT  35.356 31.488 35.597 31.944 ;
     RECT  35.201 33.072 35.849 33.624 ;
     RECT  35.849 33.072 35.921 33.096 ;
     RECT  35.104 44.16 36.205 44.184 ;
     RECT  35.104 35.328 36.317 35.784 ;
     RECT  35.309 27.36 36.325 27.912 ;
     RECT  36.205 44.16 36.461 45 ;
     RECT  36.461 44.16 36.497 44.184 ;
     RECT  36.325 27.072 36.613 27.912 ;
     RECT  35.597 31.488 36.709 31.512 ;
     RECT  35.104 17.088 36.925 17.448 ;
     RECT  35.267 60.24 37.052 60.408 ;
     RECT  37.105 58.704 37.177 58.728 ;
     RECT  35.104 49.248 37.189 49.272 ;
     RECT  35.411 51.696 37.213 51.72 ;
     RECT  37.177 58.656 37.289 58.728 ;
     RECT  37.285 29.616 37.381 29.64 ;
     RECT  35.104 11.136 37.508 11.16 ;
     RECT  36.925 16.368 37.508 17.448 ;
     RECT  37.357 23.568 37.508 23.592 ;
     RECT  35.104 26.064 37.508 26.088 ;
     RECT  36.613 27.072 37.508 28.488 ;
     RECT  37.381 29.52 37.508 29.64 ;
     RECT  36.709 31.488 37.508 32.328 ;
     RECT  36.317 35.424 37.508 35.784 ;
     RECT  35.104 36.816 37.508 37.416 ;
     RECT  35.104 38.688 37.508 39.576 ;
     RECT  35.104 41.184 37.508 43.032 ;
     RECT  37.189 49.248 37.508 49.32 ;
     RECT  37.213 50.832 37.508 51.72 ;
     RECT  35.411 54.384 37.508 54.648 ;
     RECT  35.525 56.496 37.508 57.432 ;
     RECT  37.289 58.656 37.508 58.68 ;
     RECT  37.508 2.148 37.612 58.68 ;
     RECT  37.052 59.856 37.765 60.408 ;
     RECT  37.612 2.418 37.804 58.68 ;
     RECT  37.804 38.688 37.829 39.576 ;
     RECT  37.804 25.968 38.081 27.72 ;
     RECT  37.804 34.8 38.117 35.784 ;
     RECT  38.081 25.968 38.189 27.192 ;
     RECT  37.804 23.568 38.243 23.592 ;
     RECT  37.804 58.656 38.243 58.68 ;
     RECT  37.765 59.808 38.3 60.408 ;
     RECT  37.804 29.04 38.369 29.64 ;
     RECT  37.804 56.496 38.549 57.576 ;
     RECT  38.189 25.968 38.585 26.76 ;
     RECT  37.804 50.688 38.729 50.712 ;
     RECT  37.804 40.992 38.765 43.128 ;
     RECT  37.829 38.688 38.797 39.48 ;
     RECT  38.585 25.968 38.801 26.088 ;
     RECT  37.804 36.816 38.833 37.32 ;
     RECT  38.765 40.992 38.909 42.552 ;
     RECT  37.804 31.488 39.013 33.336 ;
     RECT  37.804 49.248 39.125 49.32 ;
     RECT  39.013 30.192 39.205 30.36 ;
     RECT  39.013 31.392 39.205 33.336 ;
     RECT  39.205 30.192 39.233 33.336 ;
     RECT  38.3 59.232 39.493 60.408 ;
     RECT  37.804 46.416 39.553 47.016 ;
     RECT  39.373 27.984 39.805 28.008 ;
     RECT  39.233 32.976 40.013 33.336 ;
     RECT  37.804 11.136 40.208 11.16 ;
     RECT  37.804 16.368 40.208 17.448 ;
     RECT  39.085 21.984 40.208 22.008 ;
     RECT  38.801 26.064 40.208 26.088 ;
     RECT  39.805 27.84 40.208 28.008 ;
     RECT  39.233 30.192 40.208 31.8 ;
     RECT  40.013 32.976 40.208 34.2 ;
     RECT  38.117 35.424 40.208 35.784 ;
     RECT  38.833 36.816 40.208 37.416 ;
     RECT  38.797 38.688 40.208 39.576 ;
     RECT  38.909 41.184 40.208 42.552 ;
     RECT  39.553 46.416 40.208 47.352 ;
     RECT  39.125 49.296 40.208 49.32 ;
     RECT  37.804 51.696 40.208 51.72 ;
     RECT  37.804 54.384 40.208 54.648 ;
     RECT  38.549 56.496 40.208 57.432 ;
     RECT  39.493 58.656 40.208 60.408 ;
     RECT  40.208 2.148 40.307 60.408 ;
     RECT  40.307 2.148 40.312 58.68 ;
     RECT  40.307 59.808 40.403 60.408 ;
     RECT  40.312 2.418 40.504 58.68 ;
     RECT  40.504 29.52 40.637 34.776 ;
     RECT  40.504 54.624 40.835 57.432 ;
     RECT  40.835 55.824 40.997 57.432 ;
     RECT  40.403 60.096 41.033 60.408 ;
     RECT  40.504 27.888 41.213 28.296 ;
     RECT  40.504 25.536 41.285 26.088 ;
     RECT  41.213 27.984 41.285 28.296 ;
     RECT  41.285 28.272 41.321 28.296 ;
     RECT  40.504 48.672 41.321 48.84 ;
     RECT  40.997 56.448 41.363 57.432 ;
     RECT  40.637 31.104 41.509 34.776 ;
     RECT  40.504 35.76 41.509 37.416 ;
     RECT  40.637 29.52 41.569 29.544 ;
     RECT  40.504 44.112 41.569 44.136 ;
     RECT  41.569 44.112 41.605 44.184 ;
     RECT  41.509 31.104 41.609 37.416 ;
     RECT  40.504 46.752 41.713 47.352 ;
     RECT  41.605 44.112 41.857 44.808 ;
     RECT  41.321 48.672 41.861 48.696 ;
     RECT  40.504 16.368 41.965 17.448 ;
     RECT  41.363 56.496 42.325 57.432 ;
     RECT  40.504 58.656 42.325 58.68 ;
     RECT  41.033 60.336 42.361 60.408 ;
     RECT  41.285 26.064 42.469 26.088 ;
     RECT  41.569 28.704 42.469 29.544 ;
     RECT  41.609 31.104 42.469 35.784 ;
     RECT  40.504 21.984 42.505 22.008 ;
     RECT  42.325 56.496 42.613 58.68 ;
     RECT  40.835 54.624 42.677 54.648 ;
     RECT  42.613 55.824 42.709 58.68 ;
     RECT  40.504 38.688 42.721 39.576 ;
     RECT  40.504 41.04 42.721 42.552 ;
     RECT  42.469 28.128 42.757 35.784 ;
     RECT  42.613 52.8 42.793 52.824 ;
     RECT  42.361 60.288 42.805 60.408 ;
     RECT  42.805 60.24 42.853 60.408 ;
     RECT  42.853 59.808 42.901 60.408 ;
     RECT  40.504 11.136 42.908 11.16 ;
     RECT  41.965 16.368 42.908 17.64 ;
     RECT  42.505 21.984 42.908 22.056 ;
     RECT  42.421 24.48 42.908 24.504 ;
     RECT  42.469 26.064 42.908 26.328 ;
     RECT  42.757 28.128 42.908 35.832 ;
     RECT  41.609 36.816 42.908 37.416 ;
     RECT  42.721 38.688 42.908 42.552 ;
     RECT  41.857 44.112 42.908 45.192 ;
     RECT  41.713 46.752 42.908 47.64 ;
     RECT  42.709 49.056 42.908 49.08 ;
     RECT  40.504 51.696 42.908 51.72 ;
     RECT  42.793 52.8 42.908 53.016 ;
     RECT  42.677 54.624 42.908 54.744 ;
     RECT  42.709 55.728 42.908 58.68 ;
     RECT  42.901 59.712 42.988 60.408 ;
     RECT  42.908 2.148 43.012 58.68 ;
     RECT  43.012 2.418 43.204 58.68 ;
     RECT  43.204 29.472 43.265 37.032 ;
     RECT  43.204 38.688 43.331 42.552 ;
     RECT  43.204 44.112 43.331 45.192 ;
     RECT  43.204 52.8 43.331 53.016 ;
     RECT  43.204 26.064 43.337 26.664 ;
     RECT  43.204 46.848 43.373 47.112 ;
     RECT  43.337 26.064 43.409 26.328 ;
     RECT  43.331 52.896 43.409 53.016 ;
     RECT  43.265 31.2 43.523 37.032 ;
     RECT  43.204 54.624 43.523 54.696 ;
     RECT  43.331 44.112 43.571 45.096 ;
     RECT  43.409 52.896 43.571 52.92 ;
     RECT  43.523 31.2 43.589 34.728 ;
     RECT  43.204 55.824 43.733 58.68 ;
     RECT  43.589 33.504 44.129 34.728 ;
     RECT  43.733 56.496 44.165 58.68 ;
     RECT  43.331 40.848 44.293 42.552 ;
     RECT  43.204 27.984 44.377 28.488 ;
     RECT  43.265 29.472 44.377 30.216 ;
     RECT  44.377 27.984 44.417 30.216 ;
     RECT  44.129 34.176 44.665 34.728 ;
     RECT  43.523 35.76 44.665 37.032 ;
     RECT  43.589 31.2 44.737 32.472 ;
     RECT  43.409 26.064 44.845 26.088 ;
     RECT  44.845 26.064 44.953 26.856 ;
     RECT  44.417 27.984 44.953 29.64 ;
     RECT  43.204 11.136 44.989 11.16 ;
     RECT  44.989 11.136 45.097 11.4 ;
     RECT  45.445 24.096 45.485 24.12 ;
     RECT  45.097 10.752 45.493 11.4 ;
     RECT  45.26 12.384 45.493 12.408 ;
     RECT  45.493 10.608 45.608 12.408 ;
     RECT  43.204 16.368 45.608 17.64 ;
     RECT  43.204 21.984 45.608 22.056 ;
     RECT  45.485 23.904 45.608 24.12 ;
     RECT  44.953 25.488 45.608 29.64 ;
     RECT  44.737 30.72 45.608 32.472 ;
     RECT  44.665 34.176 45.608 37.032 ;
     RECT  43.331 38.688 45.608 38.712 ;
     RECT  44.293 40.416 45.608 42.552 ;
     RECT  43.571 44.112 45.608 44.712 ;
     RECT  43.373 47.088 45.608 47.112 ;
     RECT  43.204 51.696 45.608 51.72 ;
     RECT  43.523 54.624 45.608 54.648 ;
     RECT  44.165 56.496 45.608 57.432 ;
     RECT  44.165 58.656 45.608 58.68 ;
     RECT  45.608 2.148 45.712 58.68 ;
     RECT  45.712 2.418 45.904 58.68 ;
     RECT  45.904 29.232 46.163 36.84 ;
     RECT  46.163 35.76 46.189 36.84 ;
     RECT  45.904 58.656 46.451 58.68 ;
     RECT  46.163 29.232 46.505 34.2 ;
     RECT  42.988 59.808 46.541 60.408 ;
     RECT  45.904 6.576 46.547 6.888 ;
     RECT  45.904 10.608 46.547 12.024 ;
     RECT  45.904 46.752 46.649 47.112 ;
     RECT  45.904 24.384 46.757 28.2 ;
     RECT  46.505 29.232 46.757 33.96 ;
     RECT  46.649 46.848 46.757 47.112 ;
     RECT  45.904 16.368 46.793 17.64 ;
     RECT  46.189 36.816 46.933 36.84 ;
     RECT  46.757 24.96 46.973 28.2 ;
     RECT  46.933 36.816 47.081 37.032 ;
     RECT  46.757 33.936 47.117 33.96 ;
     RECT  46.973 24.96 47.225 28.008 ;
     RECT  47.225 25.776 47.261 28.008 ;
     RECT  46.541 60.336 47.549 60.408 ;
     RECT  46.757 29.232 47.689 32.232 ;
     RECT  47.549 60.384 48.161 60.408 ;
     RECT  46.547 6.576 48.308 6.6 ;
     RECT  46.547 10.608 48.308 11.16 ;
     RECT  46.793 16.368 48.308 16.392 ;
     RECT  46.793 17.424 48.308 17.64 ;
     RECT  45.904 21.984 48.308 22.056 ;
     RECT  47.261 25.776 48.308 26.088 ;
     RECT  47.261 27.072 48.308 28.008 ;
     RECT  47.689 29.088 48.308 32.232 ;
     RECT  46.189 35.76 48.308 35.784 ;
     RECT  47.081 36.816 48.308 36.84 ;
     RECT  45.904 38.688 48.308 38.712 ;
     RECT  45.904 42 48.308 42.552 ;
     RECT  45.904 44.112 48.308 44.712 ;
     RECT  46.757 47.088 48.308 47.112 ;
     RECT  45.904 51.696 48.308 51.72 ;
     RECT  45.904 54.624 48.308 54.648 ;
     RECT  45.904 56.496 48.308 57.432 ;
     RECT  48.308 2.148 48.412 57.792 ;
     RECT  48.412 2.418 48.5 57.792 ;
     RECT  48.5 2.418 48.604 58.062 ;
     RECT  48.604 27.072 48.917 27.624 ;
     RECT  48.604 38.688 49.633 38.712 ;
     RECT  48.604 47.088 49.813 47.112 ;
     RECT  48.604 49.584 49.859 50.328 ;
     RECT  49.813 47.04 49.961 47.112 ;
     RECT  48.604 31.44 49.997 32.232 ;
     RECT  49.633 38.688 50.101 39.336 ;
     RECT  50.101 38.688 50.137 40.056 ;
     RECT  49.993 24.912 50.725 24.936 ;
     RECT  48.604 26.064 50.725 26.088 ;
     RECT  48.604 36.816 50.821 36.84 ;
     RECT  48.604 6.576 51.008 6.6 ;
     RECT  48.604 10.608 51.008 11.16 ;
     RECT  48.604 16.368 51.008 16.392 ;
     RECT  48.604 17.424 51.008 17.64 ;
     RECT  48.604 21.984 51.008 22.056 ;
     RECT  50.725 24.912 51.008 26.088 ;
     RECT  48.917 27.6 51.008 27.624 ;
     RECT  48.604 29.232 51.008 29.544 ;
     RECT  49.997 31.44 51.008 31.8 ;
     RECT  48.604 35.76 51.008 35.784 ;
     RECT  50.821 36.816 51.008 37.656 ;
     RECT  50.137 38.688 51.008 40.152 ;
     RECT  48.604 42 51.008 42.552 ;
     RECT  48.604 44.112 51.008 44.712 ;
     RECT  49.961 47.04 51.008 47.064 ;
     RECT  49.859 50.304 51.008 50.328 ;
     RECT  48.604 51.696 51.008 51.72 ;
     RECT  48.604 54.624 51.008 54.648 ;
     RECT  48.604 56.496 51.008 57.432 ;
     RECT  51.008 2.148 51.112 57.792 ;
     RECT  51.112 2.418 51.2 57.792 ;
     RECT  51.2 2.418 51.304 58.062 ;
     RECT  51.304 24.912 53.017 24.936 ;
     RECT  51.304 27.6 53.017 27.624 ;
     RECT  51.304 26.064 53.053 26.088 ;
     RECT  51.304 6.576 53.708 6.6 ;
     RECT  51.304 10.608 53.708 11.16 ;
     RECT  51.304 16.368 53.708 16.392 ;
     RECT  51.304 17.424 53.708 17.64 ;
     RECT  51.304 21.984 53.708 22.056 ;
     RECT  53.017 24.672 53.708 24.936 ;
     RECT  53.053 26.064 53.708 26.376 ;
     RECT  53.017 27.6 53.708 28.152 ;
     RECT  51.304 29.232 53.708 29.544 ;
     RECT  51.304 31.44 53.708 31.512 ;
     RECT  51.304 35.76 53.708 35.784 ;
     RECT  51.304 36.816 53.708 36.84 ;
     RECT  51.304 37.92 53.708 39 ;
     RECT  51.304 40.032 53.708 40.056 ;
     RECT  51.304 42 53.708 42.552 ;
     RECT  51.304 44.112 53.708 44.472 ;
     RECT  51.304 47.04 53.708 47.064 ;
     RECT  51.304 50.304 53.708 50.328 ;
     RECT  51.304 51.696 53.708 51.72 ;
     RECT  51.304 54.624 53.708 54.648 ;
     RECT  51.304 56.496 53.708 57.432 ;
     RECT  53.708 2.148 53.812 57.792 ;
     RECT  53.812 2.418 53.9 57.792 ;
     RECT  53.9 2.418 54.004 58.062 ;
     RECT  54.004 16.368 54.749 17.64 ;
     RECT  54.004 30.72 54.929 31.608 ;
     RECT  54.004 51.648 55.069 51.72 ;
     RECT  54.929 31.2 55.141 31.608 ;
     RECT  54.004 46.848 55.177 47.064 ;
     RECT  54.004 6.576 55.196 6.6 ;
     RECT  55.196 6.576 55.213 6.84 ;
     RECT  54.004 26.064 55.213 27.624 ;
     RECT  54.004 49.008 55.213 49.032 ;
     RECT  55.069 51.648 55.213 52.488 ;
     RECT  54.749 16.368 55.249 16.392 ;
     RECT  54.004 29.232 55.249 29.64 ;
     RECT  55.177 46.272 55.249 47.064 ;
     RECT  55.213 51.648 55.285 52.584 ;
     RECT  54.004 21.984 55.357 22.056 ;
     RECT  55.213 26.064 55.357 27.912 ;
     RECT  55.249 29.04 55.357 29.64 ;
     RECT  55.249 45.696 55.357 47.064 ;
     RECT  55.213 48.48 55.357 49.032 ;
     RECT  54.004 54.624 55.357 54.648 ;
     RECT  55.357 26.064 55.393 29.64 ;
     RECT  54.004 37.92 55.393 39 ;
     RECT  54.004 40.032 55.393 40.056 ;
     RECT  54.749 17.424 55.429 17.64 ;
     RECT  54.004 24.672 55.429 24.696 ;
     RECT  54.004 41.952 55.429 42.552 ;
     RECT  55.393 4.512 55.465 4.536 ;
     RECT  55.213 5.712 55.465 6.84 ;
     RECT  55.357 34.128 55.465 34.152 ;
     RECT  55.465 34.08 55.484 34.152 ;
     RECT  55.393 37.92 55.484 40.056 ;
     RECT  55.357 21.504 55.501 22.056 ;
     RECT  55.465 23.376 55.501 23.4 ;
     RECT  55.429 24.672 55.501 24.984 ;
     RECT  55.141 31.2 55.501 31.704 ;
     RECT  55.501 31.2 55.525 31.896 ;
     RECT  54.004 50.304 55.609 50.328 ;
     RECT  55.285 51.552 55.609 52.584 ;
     RECT  55.357 54.624 55.609 54.696 ;
     RECT  55.525 31.2 55.621 32.856 ;
     RECT  55.484 34.08 55.621 34.2 ;
     RECT  54.004 36.816 55.628 36.84 ;
     RECT  55.484 37.824 55.628 40.056 ;
     RECT  54.004 13.92 55.645 13.944 ;
     RECT  55.609 14.928 55.645 14.952 ;
     RECT  55.357 45.696 55.645 49.032 ;
     RECT  54.004 35.76 55.717 35.784 ;
     RECT  55.628 36.816 55.717 40.584 ;
     RECT  55.645 45.696 55.82 49.224 ;
     RECT  55.609 50.304 55.82 52.584 ;
     RECT  54.004 10.608 55.825 11.16 ;
     RECT  55.645 13.92 55.825 14.952 ;
     RECT  55.717 35.76 55.825 40.584 ;
     RECT  55.429 41.664 55.825 42.552 ;
     RECT  55.825 35.76 55.861 42.552 ;
     RECT  54.004 44.112 55.861 44.472 ;
     RECT  55.82 45.696 55.861 52.584 ;
     RECT  55.501 21.504 55.897 23.4 ;
     RECT  55.501 24.672 55.897 25.032 ;
     RECT  55.609 54.624 55.897 54.936 ;
     RECT  55.249 16.272 55.933 16.392 ;
     RECT  55.393 26.064 55.933 29.928 ;
     RECT  55.621 31.2 55.933 34.2 ;
     RECT  55.933 8.016 56.041 8.04 ;
     RECT  55.933 16.032 56.041 16.392 ;
     RECT  55.429 17.424 56.041 18.264 ;
     RECT  55.285 53.568 56.041 53.592 ;
     RECT  55.897 54.624 56.041 54.984 ;
     RECT  55.825 13.152 56.113 14.952 ;
     RECT  55.825 10.08 56.149 11.16 ;
     RECT  56.113 12.48 56.149 14.952 ;
     RECT  56.041 16.032 56.149 18.264 ;
     RECT  55.933 26.064 56.245 34.2 ;
     RECT  56.245 26.064 56.257 34.584 ;
     RECT  55.861 35.76 56.257 44.472 ;
     RECT  56.041 8.016 56.293 8.328 ;
     RECT  55.897 21.504 56.329 25.032 ;
     RECT  56.257 26.064 56.329 44.472 ;
     RECT  55.465 4.512 56.408 6.84 ;
     RECT  56.293 7.968 56.408 8.328 ;
     RECT  56.149 10.08 56.408 11.496 ;
     RECT  56.149 12.48 56.408 18.264 ;
     RECT  56.329 21.504 56.408 44.472 ;
     RECT  55.861 45.552 56.408 52.584 ;
     RECT  56.041 53.568 56.408 54.984 ;
     RECT  54.004 56.496 56.408 57.432 ;
     RECT  56.408 2.148 56.512 57.792 ;
     RECT  56.512 2.418 56.6 57.792 ;
     RECT  56.6 2.418 56.704 58.062 ;
     RECT  56.704 40.32 56.819 57.432 ;
     RECT  56.704 4.512 57.059 17.736 ;
     RECT  56.819 40.464 57.305 57.432 ;
     RECT  57.305 56.208 57.341 57.432 ;
     RECT  57.341 57.072 57.521 57.432 ;
     RECT  56.704 35.328 57.539 38.712 ;
     RECT  57.059 4.512 57.593 8.856 ;
     RECT  57.593 8.688 57.629 8.856 ;
     RECT  57.593 4.512 57.701 7.368 ;
     RECT  56.704 19.968 57.805 34.344 ;
     RECT  57.539 35.328 57.805 37.08 ;
     RECT  57.305 40.464 57.809 55.176 ;
     RECT  57.059 10.08 57.845 17.736 ;
     RECT  57.701 4.512 57.877 7.224 ;
     RECT  57.809 40.464 57.877 44.136 ;
     RECT  57.877 40.416 57.913 44.136 ;
     RECT  57.913 39.888 57.917 44.136 ;
     RECT  57.985 18.72 58.021 18.744 ;
     RECT  57.805 19.968 58.021 37.08 ;
     RECT  57.917 39.888 58.021 42.984 ;
     RECT  57.845 10.8 58.129 17.736 ;
     RECT  58.021 18.72 58.129 37.08 ;
     RECT  57.877 4.416 58.261 7.224 ;
     RECT  57.809 45.216 58.273 55.176 ;
     RECT  57.521 57.12 58.309 57.432 ;
     RECT  58.273 45.216 58.489 55.224 ;
     RECT  57.629 8.688 58.669 8.712 ;
     RECT  58.309 57.12 58.705 57.624 ;
     RECT  58.261 3.936 58.741 7.224 ;
     RECT  58.669 8.688 58.741 9.624 ;
     RECT  58.741 3.936 58.813 7.464 ;
     RECT  58.741 8.544 58.813 9.624 ;
     RECT  58.129 10.8 58.849 37.08 ;
     RECT  58.813 3.936 58.921 9.624 ;
     RECT  58.849 10.8 58.921 37.416 ;
     RECT  58.021 39.744 58.921 42.984 ;
     RECT  57.917 44.064 58.921 44.136 ;
     RECT  58.705 57.072 58.993 57.624 ;
     RECT  58.921 3.936 59.065 37.416 ;
     RECT  57.539 38.496 59.065 38.712 ;
     RECT  59.065 3.936 59.108 38.712 ;
     RECT  58.921 39.744 59.108 44.136 ;
     RECT  58.489 45.216 59.108 55.512 ;
     RECT  58.993 57.024 59.108 57.624 ;
     RECT  59.108 2.148 59.212 57.792 ;
     RECT  59.212 2.418 59.3 57.792 ;
     RECT  59.3 2.418 59.404 58.062 ;
     RECT  59.404 20.544 59.429 39.48 ;
     RECT  59.404 3.936 59.501 19.272 ;
     RECT  59.429 30.816 59.501 39.48 ;
     RECT  59.404 40.56 59.609 57.624 ;
     RECT  59.501 30.816 59.789 39.192 ;
     RECT  59.609 40.656 59.861 57.624 ;
     RECT  59.861 40.656 59.897 57.432 ;
     RECT  59.501 3.936 60.035 19.224 ;
     RECT  60.035 3.936 60.329 17.16 ;
     RECT  59.429 20.544 60.397 29.64 ;
     RECT  59.789 31.44 60.419 39.192 ;
     RECT  60.329 3.936 60.437 7.08 ;
     RECT  60.329 8.448 60.473 8.472 ;
     RECT  60.329 9.504 60.545 11.496 ;
     RECT  60.419 35.136 60.545 39.192 ;
     RECT  59.897 40.8 60.563 57.432 ;
     RECT  60.563 40.8 60.611 50.616 ;
     RECT  60.611 40.8 60.653 48.984 ;
     RECT  60.397 20.544 60.689 30.264 ;
     RECT  60.329 12.48 60.761 17.16 ;
     RECT  60.545 35.136 60.833 38.712 ;
     RECT  60.689 20.592 60.901 30.264 ;
     RECT  60.419 31.44 60.901 34.152 ;
     RECT  60.437 4.512 61.657 7.08 ;
     RECT  60.611 50.016 61.765 50.616 ;
     RECT  60.563 51.648 61.765 57.432 ;
     RECT  61.657 4.128 61.808 7.08 ;
     RECT  60.545 9.504 61.808 11.4 ;
     RECT  60.761 12.48 61.808 13.08 ;
     RECT  60.761 14.256 61.808 17.16 ;
     RECT  60.035 18.144 61.808 19.224 ;
     RECT  60.901 20.592 61.808 34.152 ;
     RECT  60.833 35.184 61.808 38.712 ;
     RECT  60.653 40.992 61.808 48.984 ;
     RECT  61.765 50.016 61.808 57.432 ;
     RECT  61.808 2.148 61.912 57.792 ;
     RECT  61.912 2.418 62 57.792 ;
     RECT  62 2.418 62.104 58.062 ;
     RECT  62.104 20.304 63.277 23.784 ;
     RECT  62.104 24.816 63.277 57.432 ;
     RECT  63.277 20.304 63.313 57.432 ;
     RECT  62.104 3.792 63.853 19.08 ;
     RECT  63.313 20.304 63.853 57.48 ;
     RECT  63.853 3.792 64.692 3.816 ;
     RECT  63.853 3.816 64.716 3.888 ;
     RECT  63.853 3.888 64.692 3.912 ;
     RECT  63.853 3.912 64.716 3.984 ;
     RECT  63.853 3.984 64.692 4.008 ;
     RECT  63.853 4.008 64.716 4.08 ;
     RECT  63.853 4.08 64.692 4.104 ;
     RECT  63.853 4.104 64.716 4.176 ;
     RECT  63.853 4.176 64.692 4.2 ;
     RECT  63.853 4.2 64.716 4.272 ;
     RECT  63.853 4.272 64.692 4.296 ;
     RECT  63.853 4.296 64.716 4.368 ;
     RECT  63.853 4.368 64.692 4.392 ;
     RECT  63.853 4.392 64.716 4.464 ;
     RECT  63.853 4.464 64.692 4.488 ;
     RECT  63.853 4.488 64.716 4.56 ;
     RECT  63.853 4.56 64.692 4.584 ;
     RECT  63.853 4.584 64.716 4.656 ;
     RECT  63.853 4.656 64.692 4.68 ;
     RECT  63.853 4.68 64.716 4.752 ;
     RECT  63.853 4.752 64.692 4.776 ;
     RECT  63.853 4.776 64.716 4.848 ;
     RECT  63.853 4.848 64.692 4.872 ;
     RECT  63.853 4.872 64.716 4.944 ;
     RECT  63.853 4.944 64.692 4.968 ;
     RECT  63.853 4.968 64.716 5.04 ;
     RECT  63.853 5.04 64.692 5.064 ;
     RECT  63.853 5.064 64.716 5.136 ;
     RECT  63.853 5.136 64.692 5.16 ;
     RECT  63.853 5.16 64.716 5.232 ;
     RECT  63.853 5.232 64.692 5.256 ;
     RECT  63.853 5.256 64.716 5.328 ;
     RECT  63.853 5.328 64.692 5.352 ;
     RECT  63.853 5.352 64.716 5.424 ;
     RECT  63.853 5.424 64.692 5.448 ;
     RECT  63.853 5.448 64.716 5.52 ;
     RECT  63.853 5.52 64.692 5.544 ;
     RECT  63.853 5.544 64.716 5.616 ;
     RECT  63.853 5.616 64.692 5.64 ;
     RECT  63.853 5.64 64.716 5.712 ;
     RECT  63.853 5.712 64.692 5.736 ;
     RECT  63.853 5.736 64.716 5.808 ;
     RECT  63.853 5.808 64.692 5.832 ;
     RECT  63.853 5.832 64.716 5.904 ;
     RECT  63.853 5.904 64.692 5.928 ;
     RECT  63.853 5.928 64.716 6 ;
     RECT  63.853 6 64.692 6.024 ;
     RECT  63.853 6.024 64.716 6.096 ;
     RECT  63.853 6.096 64.692 6.12 ;
     RECT  63.853 6.12 64.716 6.192 ;
     RECT  63.853 6.192 64.692 6.216 ;
     RECT  63.853 6.216 64.716 6.288 ;
     RECT  63.853 6.288 64.692 6.312 ;
     RECT  63.853 6.312 64.716 6.384 ;
     RECT  63.853 6.384 64.692 6.408 ;
     RECT  63.853 6.408 64.716 6.48 ;
     RECT  63.853 6.48 64.692 6.504 ;
     RECT  63.853 6.504 64.716 6.576 ;
     RECT  63.853 6.576 64.692 6.6 ;
     RECT  63.853 6.6 64.716 6.672 ;
     RECT  63.853 6.672 64.692 6.696 ;
     RECT  63.853 6.696 64.716 6.768 ;
     RECT  63.853 6.768 64.692 6.792 ;
     RECT  63.853 6.792 64.716 6.864 ;
     RECT  63.853 6.864 64.692 6.888 ;
     RECT  63.853 6.888 64.716 6.96 ;
     RECT  63.853 6.96 64.692 6.984 ;
     RECT  63.853 6.984 64.716 7.056 ;
     RECT  63.853 7.056 64.692 7.08 ;
     RECT  63.853 7.08 64.716 7.152 ;
     RECT  63.853 7.152 64.692 7.176 ;
     RECT  63.853 7.176 64.716 7.248 ;
     RECT  63.853 7.248 64.692 7.272 ;
     RECT  63.853 7.272 64.716 7.344 ;
     RECT  63.853 7.344 64.692 7.368 ;
     RECT  63.853 7.368 64.716 7.44 ;
     RECT  63.853 7.44 64.692 7.464 ;
     RECT  63.853 7.464 64.716 7.536 ;
     RECT  63.853 7.536 64.692 7.56 ;
     RECT  63.853 7.56 64.716 7.632 ;
     RECT  63.853 7.632 64.692 7.656 ;
     RECT  63.853 7.656 64.716 7.728 ;
     RECT  63.853 7.728 64.692 7.752 ;
     RECT  63.853 7.752 64.716 7.824 ;
     RECT  63.853 7.824 64.692 7.848 ;
     RECT  63.853 7.848 64.716 7.92 ;
     RECT  63.853 7.92 64.692 7.944 ;
     RECT  63.853 7.944 64.716 8.016 ;
     RECT  63.853 8.016 64.692 8.04 ;
     RECT  63.853 8.04 64.716 8.112 ;
     RECT  63.853 8.112 64.692 8.136 ;
     RECT  63.853 8.136 64.716 8.208 ;
     RECT  63.853 8.208 64.692 8.232 ;
     RECT  63.853 8.232 64.716 8.304 ;
     RECT  63.853 8.304 64.692 8.328 ;
     RECT  63.853 8.328 64.716 8.4 ;
     RECT  63.853 8.4 64.692 8.424 ;
     RECT  63.853 8.424 64.716 8.496 ;
     RECT  63.853 8.496 64.692 8.52 ;
     RECT  63.853 8.52 64.716 8.592 ;
     RECT  63.853 8.592 64.692 8.616 ;
     RECT  63.853 8.616 64.716 8.688 ;
     RECT  63.853 8.688 64.692 8.712 ;
     RECT  63.853 8.712 64.716 8.784 ;
     RECT  63.853 8.784 64.692 8.808 ;
     RECT  63.853 8.808 64.716 8.88 ;
     RECT  63.853 8.88 64.692 8.904 ;
     RECT  63.853 8.904 64.716 8.976 ;
     RECT  63.853 8.976 64.692 9 ;
     RECT  63.853 9 64.716 9.072 ;
     RECT  63.853 9.072 64.692 9.096 ;
     RECT  63.853 9.096 64.716 9.168 ;
     RECT  63.853 9.168 64.692 9.192 ;
     RECT  63.853 9.192 64.716 9.264 ;
     RECT  63.853 9.264 64.692 9.288 ;
     RECT  63.853 9.288 64.716 9.36 ;
     RECT  63.853 9.36 64.692 9.384 ;
     RECT  63.853 9.384 64.716 9.456 ;
     RECT  63.853 9.456 64.692 9.48 ;
     RECT  63.853 9.48 64.716 9.552 ;
     RECT  63.853 9.552 64.692 9.576 ;
     RECT  63.853 9.576 64.716 9.648 ;
     RECT  63.853 9.648 64.692 9.672 ;
     RECT  63.853 9.672 64.716 9.744 ;
     RECT  63.853 9.744 64.692 9.768 ;
     RECT  63.853 9.768 64.716 9.84 ;
     RECT  63.853 9.84 64.692 9.864 ;
     RECT  63.853 9.864 64.716 9.936 ;
     RECT  63.853 9.936 64.692 9.96 ;
     RECT  63.853 9.96 64.716 10.032 ;
     RECT  63.853 10.032 64.692 10.056 ;
     RECT  63.853 10.056 64.716 10.128 ;
     RECT  63.853 10.128 64.692 10.152 ;
     RECT  63.853 10.152 64.716 10.224 ;
     RECT  63.853 10.224 64.692 10.248 ;
     RECT  63.853 10.248 64.716 10.32 ;
     RECT  63.853 10.32 64.692 10.344 ;
     RECT  63.853 10.344 64.716 10.416 ;
     RECT  63.853 10.416 64.692 10.44 ;
     RECT  63.853 10.44 64.716 10.512 ;
     RECT  63.853 10.512 64.692 10.536 ;
     RECT  63.853 10.536 64.716 10.608 ;
     RECT  63.853 10.608 64.692 10.632 ;
     RECT  63.853 10.632 64.716 10.704 ;
     RECT  63.853 10.704 64.692 10.728 ;
     RECT  63.853 10.728 64.716 10.8 ;
     RECT  63.853 10.8 64.692 10.824 ;
     RECT  63.853 10.824 64.716 10.896 ;
     RECT  63.853 10.896 64.692 10.92 ;
     RECT  63.853 10.92 64.716 10.992 ;
     RECT  63.853 10.992 64.692 11.016 ;
     RECT  63.853 11.016 64.716 11.088 ;
     RECT  63.853 11.088 64.692 11.112 ;
     RECT  63.853 11.112 64.716 11.184 ;
     RECT  63.853 11.184 64.692 11.208 ;
     RECT  63.853 11.208 64.716 11.28 ;
     RECT  63.853 11.28 64.692 11.304 ;
     RECT  63.853 11.304 64.716 11.376 ;
     RECT  63.853 11.376 64.692 11.4 ;
     RECT  63.853 11.4 64.716 11.472 ;
     RECT  63.853 11.472 64.692 11.496 ;
     RECT  63.853 11.496 64.716 11.568 ;
     RECT  63.853 11.568 64.692 11.592 ;
     RECT  63.853 11.592 64.716 11.664 ;
     RECT  63.853 11.664 64.692 11.688 ;
     RECT  63.853 11.688 64.716 11.76 ;
     RECT  63.853 11.76 64.692 11.784 ;
     RECT  63.853 11.784 64.716 11.856 ;
     RECT  63.853 11.856 64.692 11.88 ;
     RECT  63.853 11.88 64.716 11.952 ;
     RECT  63.853 11.952 64.692 11.976 ;
     RECT  63.853 11.976 64.716 12.048 ;
     RECT  63.853 12.048 64.692 12.072 ;
     RECT  63.853 12.072 64.716 12.144 ;
     RECT  63.853 12.144 64.692 12.168 ;
     RECT  63.853 12.168 64.716 12.24 ;
     RECT  63.853 12.24 64.692 12.264 ;
     RECT  63.853 12.264 64.716 12.336 ;
     RECT  63.853 12.336 64.692 12.36 ;
     RECT  63.853 12.36 64.716 12.432 ;
     RECT  63.853 12.432 64.692 12.456 ;
     RECT  63.853 12.456 64.716 12.528 ;
     RECT  63.853 12.528 64.692 12.552 ;
     RECT  63.853 12.552 64.716 12.624 ;
     RECT  63.853 12.624 64.692 12.648 ;
     RECT  63.853 12.648 64.716 12.72 ;
     RECT  63.853 12.72 64.692 12.744 ;
     RECT  63.853 12.744 64.716 12.816 ;
     RECT  63.853 12.816 64.692 12.84 ;
     RECT  63.853 12.84 64.716 12.912 ;
     RECT  63.853 12.912 64.692 12.936 ;
     RECT  63.853 12.936 64.716 13.008 ;
     RECT  63.853 13.008 64.692 13.032 ;
     RECT  63.853 13.032 64.716 13.104 ;
     RECT  63.853 13.104 64.692 13.128 ;
     RECT  63.853 13.128 64.716 13.2 ;
     RECT  63.853 13.2 64.692 13.224 ;
     RECT  63.853 13.224 64.716 13.296 ;
     RECT  63.853 13.296 64.692 13.32 ;
     RECT  63.853 13.32 64.716 13.392 ;
     RECT  63.853 13.392 64.692 13.416 ;
     RECT  63.853 13.416 64.716 13.488 ;
     RECT  63.853 13.488 64.692 13.512 ;
     RECT  63.853 13.512 64.716 13.584 ;
     RECT  63.853 13.584 64.692 13.608 ;
     RECT  63.853 13.608 64.716 13.68 ;
     RECT  63.853 13.68 64.692 13.704 ;
     RECT  63.853 13.704 64.716 13.776 ;
     RECT  63.853 13.776 64.692 13.8 ;
     RECT  63.853 13.8 64.716 13.872 ;
     RECT  63.853 13.872 64.692 13.896 ;
     RECT  63.853 13.896 64.716 13.968 ;
     RECT  63.853 13.968 64.692 13.992 ;
     RECT  63.853 13.992 64.716 14.064 ;
     RECT  63.853 14.064 64.692 14.088 ;
     RECT  63.853 14.088 64.716 14.16 ;
     RECT  63.853 14.16 64.692 14.184 ;
     RECT  63.853 14.184 64.716 14.256 ;
     RECT  63.853 14.256 64.692 14.28 ;
     RECT  63.853 14.28 64.716 14.352 ;
     RECT  63.853 14.352 64.692 14.376 ;
     RECT  63.853 14.376 64.716 14.448 ;
     RECT  63.853 14.448 64.692 14.472 ;
     RECT  63.853 14.472 64.716 14.544 ;
     RECT  63.853 14.544 64.692 14.568 ;
     RECT  63.853 14.568 64.716 14.64 ;
     RECT  63.853 14.64 64.692 14.664 ;
     RECT  63.853 14.664 64.716 14.736 ;
     RECT  63.853 14.736 64.692 14.76 ;
     RECT  63.853 14.76 64.716 14.832 ;
     RECT  63.853 14.832 64.692 14.856 ;
     RECT  63.853 14.856 64.716 14.928 ;
     RECT  63.853 14.928 64.692 14.952 ;
     RECT  63.853 14.952 64.716 15.024 ;
     RECT  63.853 15.024 64.692 15.048 ;
     RECT  63.853 15.048 64.716 15.12 ;
     RECT  63.853 15.12 64.692 15.144 ;
     RECT  63.853 15.144 64.716 15.216 ;
     RECT  63.853 15.216 64.692 15.24 ;
     RECT  63.853 15.24 64.716 15.312 ;
     RECT  63.853 15.312 64.692 15.336 ;
     RECT  63.853 15.336 64.716 15.408 ;
     RECT  63.853 15.408 64.692 15.432 ;
     RECT  63.853 15.432 64.716 15.504 ;
     RECT  63.853 15.504 64.692 15.528 ;
     RECT  63.853 15.528 64.716 15.6 ;
     RECT  63.853 15.6 64.692 15.624 ;
     RECT  63.853 15.624 64.716 15.696 ;
     RECT  63.853 15.696 64.692 15.72 ;
     RECT  63.853 15.72 64.716 15.792 ;
     RECT  63.853 15.792 64.692 15.816 ;
     RECT  63.853 15.816 64.716 15.888 ;
     RECT  63.853 15.888 64.692 15.912 ;
     RECT  63.853 15.912 64.716 15.984 ;
     RECT  63.853 15.984 64.692 16.008 ;
     RECT  63.853 16.008 64.716 16.08 ;
     RECT  63.853 16.08 64.692 16.104 ;
     RECT  63.853 16.104 64.716 16.176 ;
     RECT  63.853 16.176 64.692 16.2 ;
     RECT  63.853 16.2 64.716 16.272 ;
     RECT  63.853 16.272 64.692 16.296 ;
     RECT  63.853 16.296 64.716 16.368 ;
     RECT  63.853 16.368 64.692 16.392 ;
     RECT  63.853 16.392 64.716 16.464 ;
     RECT  63.853 16.464 64.692 16.488 ;
     RECT  63.853 16.488 64.716 16.56 ;
     RECT  63.853 16.56 64.692 16.584 ;
     RECT  63.853 16.584 64.716 16.656 ;
     RECT  63.853 16.656 64.692 16.68 ;
     RECT  63.853 16.68 64.716 16.752 ;
     RECT  63.853 16.752 64.692 16.776 ;
     RECT  63.853 16.776 64.716 16.848 ;
     RECT  63.853 16.848 64.692 16.872 ;
     RECT  63.853 16.872 64.716 16.944 ;
     RECT  63.853 16.944 64.692 16.968 ;
     RECT  63.853 16.968 64.716 17.04 ;
     RECT  63.853 17.04 64.692 17.064 ;
     RECT  63.853 17.064 64.716 17.136 ;
     RECT  63.853 17.136 64.692 17.16 ;
     RECT  63.853 17.16 64.716 17.232 ;
     RECT  63.853 17.232 64.692 17.256 ;
     RECT  63.853 17.256 64.716 17.328 ;
     RECT  63.853 17.328 64.692 17.352 ;
     RECT  63.853 17.352 64.716 17.424 ;
     RECT  63.853 17.424 64.692 17.448 ;
     RECT  63.853 17.448 64.716 17.52 ;
     RECT  63.853 17.52 64.692 17.544 ;
     RECT  63.853 17.544 64.716 17.616 ;
     RECT  63.853 17.616 64.692 17.64 ;
     RECT  63.853 17.64 64.716 17.712 ;
     RECT  63.853 17.712 64.692 17.736 ;
     RECT  63.853 17.736 64.716 17.808 ;
     RECT  63.853 17.808 64.692 17.832 ;
     RECT  63.853 17.832 64.716 17.904 ;
     RECT  63.853 17.904 64.692 17.928 ;
     RECT  63.853 17.928 64.716 18 ;
     RECT  63.853 18 64.692 18.024 ;
     RECT  63.853 18.024 64.716 18.096 ;
     RECT  63.853 18.096 64.692 18.12 ;
     RECT  63.853 18.12 64.716 18.192 ;
     RECT  63.853 18.192 64.692 18.216 ;
     RECT  63.853 18.216 64.716 18.288 ;
     RECT  63.853 18.288 64.692 18.312 ;
     RECT  63.853 18.312 64.716 18.384 ;
     RECT  63.853 18.384 64.692 18.408 ;
     RECT  63.853 18.408 64.716 18.48 ;
     RECT  63.853 18.48 64.692 18.504 ;
     RECT  63.853 18.504 64.716 18.576 ;
     RECT  63.853 18.576 64.692 18.6 ;
     RECT  63.853 18.6 64.716 18.672 ;
     RECT  63.853 18.672 64.692 18.696 ;
     RECT  63.853 18.696 64.716 18.768 ;
     RECT  63.853 18.768 64.692 18.792 ;
     RECT  63.853 18.792 64.716 18.864 ;
     RECT  63.853 18.864 64.692 18.888 ;
     RECT  63.853 18.888 64.716 18.96 ;
     RECT  63.853 18.96 64.692 18.984 ;
     RECT  63.853 18.984 64.716 19.056 ;
     RECT  63.853 19.056 64.692 19.08 ;
     RECT  63.853 19.08 64.716 19.92 ;
     RECT  63.853 19.92 64.692 19.944 ;
     RECT  63.853 19.944 64.716 20.016 ;
     RECT  63.853 20.016 64.692 20.04 ;
     RECT  63.853 20.04 64.716 20.112 ;
     RECT  63.853 20.112 64.692 20.136 ;
     RECT  63.853 20.136 64.716 20.208 ;
     RECT  63.853 20.208 64.692 20.232 ;
     RECT  63.853 20.232 64.716 20.304 ;
     RECT  63.853 20.304 64.692 20.328 ;
     RECT  63.853 20.328 64.716 20.4 ;
     RECT  63.853 20.4 64.692 20.424 ;
     RECT  63.853 20.424 64.716 20.496 ;
     RECT  63.853 20.496 64.692 20.52 ;
     RECT  63.853 20.52 64.716 20.592 ;
     RECT  63.853 20.592 64.692 20.616 ;
     RECT  63.853 20.616 64.716 20.688 ;
     RECT  63.853 20.688 64.692 20.712 ;
     RECT  63.853 20.712 64.716 20.784 ;
     RECT  63.853 20.784 64.692 20.808 ;
     RECT  63.853 20.808 64.716 20.88 ;
     RECT  63.853 20.88 64.692 20.904 ;
     RECT  63.853 20.904 64.716 20.976 ;
     RECT  63.853 20.976 64.692 21 ;
     RECT  63.853 21 64.716 21.072 ;
     RECT  63.853 21.072 64.692 21.096 ;
     RECT  63.853 21.096 64.716 21.168 ;
     RECT  63.853 21.168 64.692 21.192 ;
     RECT  63.853 21.192 64.716 21.264 ;
     RECT  63.853 21.264 64.692 21.288 ;
     RECT  63.853 21.288 64.716 21.36 ;
     RECT  63.853 21.36 64.692 21.384 ;
     RECT  63.853 21.384 64.716 21.456 ;
     RECT  63.853 21.456 64.692 21.48 ;
     RECT  63.853 21.48 64.716 21.552 ;
     RECT  63.853 21.552 64.692 21.576 ;
     RECT  63.853 21.576 64.716 21.648 ;
     RECT  63.853 21.648 64.692 21.672 ;
     RECT  63.853 21.672 64.716 21.744 ;
     RECT  63.853 21.744 64.692 21.768 ;
     RECT  63.853 21.768 64.716 21.84 ;
     RECT  63.853 21.84 64.692 21.864 ;
     RECT  63.853 21.864 64.716 21.936 ;
     RECT  63.853 21.936 64.692 21.96 ;
     RECT  63.853 21.96 64.716 22.032 ;
     RECT  63.853 22.032 64.692 22.056 ;
     RECT  63.853 22.056 64.716 22.128 ;
     RECT  63.853 22.128 64.692 22.152 ;
     RECT  63.853 22.152 64.716 22.224 ;
     RECT  63.853 22.224 64.692 22.248 ;
     RECT  63.853 22.248 64.716 22.32 ;
     RECT  63.853 22.32 64.692 22.344 ;
     RECT  63.853 22.344 64.716 22.416 ;
     RECT  63.853 22.416 64.692 22.44 ;
     RECT  63.853 22.44 64.716 22.512 ;
     RECT  63.853 22.512 64.692 22.536 ;
     RECT  63.853 22.536 64.716 22.608 ;
     RECT  63.853 22.608 64.692 22.632 ;
     RECT  63.853 22.632 64.716 22.704 ;
     RECT  63.853 22.704 64.692 22.728 ;
     RECT  63.853 22.728 64.716 22.8 ;
     RECT  63.853 22.8 64.692 22.824 ;
     RECT  63.853 22.824 64.716 22.896 ;
     RECT  63.853 22.896 64.692 22.92 ;
     RECT  63.853 22.92 64.716 22.992 ;
     RECT  63.853 22.992 64.692 23.016 ;
     RECT  63.853 23.016 64.716 23.088 ;
     RECT  63.853 23.088 64.692 23.112 ;
     RECT  63.853 23.112 64.716 23.184 ;
     RECT  63.853 23.184 64.692 23.208 ;
     RECT  63.853 23.208 64.716 23.28 ;
     RECT  63.853 23.28 64.692 23.304 ;
     RECT  63.853 23.304 64.716 23.376 ;
     RECT  63.853 23.376 64.692 23.4 ;
     RECT  63.853 23.4 64.716 23.472 ;
     RECT  63.853 23.472 64.692 23.496 ;
     RECT  63.853 23.496 64.716 23.568 ;
     RECT  63.853 23.568 64.692 23.592 ;
     RECT  63.853 23.592 64.716 23.664 ;
     RECT  63.853 23.664 64.692 23.688 ;
     RECT  63.853 23.688 64.716 23.76 ;
     RECT  63.853 23.76 64.692 23.784 ;
     RECT  63.853 23.784 64.716 23.856 ;
     RECT  63.853 23.856 64.692 23.88 ;
     RECT  63.853 23.88 64.716 23.952 ;
     RECT  63.853 23.952 64.692 23.976 ;
     RECT  63.853 23.976 64.716 24.048 ;
     RECT  63.853 24.048 64.692 24.072 ;
     RECT  63.853 24.072 64.716 24.144 ;
     RECT  63.853 24.144 64.692 24.168 ;
     RECT  63.853 24.168 64.716 24.24 ;
     RECT  63.853 24.24 64.692 24.264 ;
     RECT  63.853 24.264 64.716 24.336 ;
     RECT  63.853 24.336 64.692 24.36 ;
     RECT  63.853 24.36 64.716 24.432 ;
     RECT  63.853 24.432 64.692 24.456 ;
     RECT  63.853 24.456 64.716 24.528 ;
     RECT  63.853 24.528 64.692 24.552 ;
     RECT  63.853 24.552 64.716 24.624 ;
     RECT  63.853 24.624 64.692 24.648 ;
     RECT  63.853 24.648 64.716 24.72 ;
     RECT  63.853 24.72 64.692 24.744 ;
     RECT  63.853 24.744 64.716 24.816 ;
     RECT  63.853 24.816 64.692 24.84 ;
     RECT  63.853 24.84 64.716 24.912 ;
     RECT  63.853 24.912 64.692 24.936 ;
     RECT  63.853 24.936 64.716 25.008 ;
     RECT  63.853 25.008 64.692 25.032 ;
     RECT  63.853 25.032 64.716 25.104 ;
     RECT  63.853 25.104 64.692 25.128 ;
     RECT  63.853 25.128 64.716 25.2 ;
     RECT  63.853 25.2 64.692 25.224 ;
     RECT  63.853 25.224 64.716 25.296 ;
     RECT  63.853 25.296 64.692 25.32 ;
     RECT  63.853 25.32 64.716 25.392 ;
     RECT  63.853 25.392 64.692 25.416 ;
     RECT  63.853 25.416 64.716 25.488 ;
     RECT  63.853 25.488 64.692 25.512 ;
     RECT  63.853 25.512 64.716 25.584 ;
     RECT  63.853 25.584 64.692 25.608 ;
     RECT  63.853 25.608 64.716 25.68 ;
     RECT  63.853 25.68 64.692 25.704 ;
     RECT  63.853 25.704 64.716 25.776 ;
     RECT  63.853 25.776 64.692 25.8 ;
     RECT  63.853 25.8 64.716 25.872 ;
     RECT  63.853 25.872 64.692 25.896 ;
     RECT  63.853 25.896 64.716 25.968 ;
     RECT  63.853 25.968 64.692 25.992 ;
     RECT  63.853 25.992 64.716 26.064 ;
     RECT  63.853 26.064 64.692 26.088 ;
     RECT  63.853 26.088 64.716 26.16 ;
     RECT  63.853 26.16 64.692 26.184 ;
     RECT  63.853 26.184 64.716 26.256 ;
     RECT  63.853 26.256 64.692 26.28 ;
     RECT  63.853 26.28 64.716 26.352 ;
     RECT  63.853 26.352 64.692 26.376 ;
     RECT  63.853 26.376 64.716 26.448 ;
     RECT  63.853 26.448 64.692 26.472 ;
     RECT  63.853 26.472 64.716 26.544 ;
     RECT  63.853 26.544 64.692 26.568 ;
     RECT  63.853 26.568 64.716 26.64 ;
     RECT  63.853 26.64 64.692 26.664 ;
     RECT  63.853 26.664 64.716 26.736 ;
     RECT  63.853 26.736 64.692 26.76 ;
     RECT  63.853 26.76 64.716 26.832 ;
     RECT  63.853 26.832 64.692 26.856 ;
     RECT  63.853 26.856 64.716 26.928 ;
     RECT  63.853 26.928 64.692 26.952 ;
     RECT  63.853 26.952 64.716 27.024 ;
     RECT  63.853 27.024 64.692 27.048 ;
     RECT  63.853 27.048 64.716 27.12 ;
     RECT  63.853 27.12 64.692 27.144 ;
     RECT  63.853 27.144 64.716 27.216 ;
     RECT  63.853 27.216 64.692 27.24 ;
     RECT  63.853 27.24 64.716 27.312 ;
     RECT  63.853 27.312 64.692 27.336 ;
     RECT  63.853 27.336 64.716 27.408 ;
     RECT  63.853 27.408 64.692 27.432 ;
     RECT  63.853 27.432 64.716 27.504 ;
     RECT  63.853 27.504 64.692 27.528 ;
     RECT  63.853 27.528 64.716 27.6 ;
     RECT  63.853 27.6 64.692 27.624 ;
     RECT  63.853 27.624 64.716 27.696 ;
     RECT  63.853 27.696 64.692 27.72 ;
     RECT  63.853 27.72 64.716 27.792 ;
     RECT  63.853 27.792 64.692 27.816 ;
     RECT  63.853 27.816 64.716 27.888 ;
     RECT  63.853 27.888 64.692 27.912 ;
     RECT  63.853 27.912 64.716 27.984 ;
     RECT  63.853 27.984 64.692 28.008 ;
     RECT  63.853 28.008 64.716 28.08 ;
     RECT  63.853 28.08 64.692 28.104 ;
     RECT  63.853 28.104 64.716 28.176 ;
     RECT  63.853 28.176 64.692 28.2 ;
     RECT  63.853 28.2 64.716 28.272 ;
     RECT  63.853 28.272 64.692 28.296 ;
     RECT  63.853 28.296 64.716 28.368 ;
     RECT  63.853 28.368 64.692 28.392 ;
     RECT  63.853 28.392 64.716 28.464 ;
     RECT  63.853 28.464 64.692 28.488 ;
     RECT  63.853 28.488 64.716 28.56 ;
     RECT  63.853 28.56 64.692 28.584 ;
     RECT  63.853 28.584 64.716 28.656 ;
     RECT  63.853 28.656 64.692 28.68 ;
     RECT  63.853 28.68 64.716 28.752 ;
     RECT  63.853 28.752 64.692 28.776 ;
     RECT  63.853 28.776 64.716 28.848 ;
     RECT  63.853 28.848 64.692 28.872 ;
     RECT  63.853 28.872 64.716 28.944 ;
     RECT  63.853 28.944 64.692 28.968 ;
     RECT  63.853 28.968 64.716 29.04 ;
     RECT  63.853 29.04 64.692 29.064 ;
     RECT  63.853 29.064 64.716 29.136 ;
     RECT  63.853 29.136 64.692 29.16 ;
     RECT  63.853 29.16 64.716 29.232 ;
     RECT  63.853 29.232 64.692 29.256 ;
     RECT  63.853 29.256 64.716 29.328 ;
     RECT  63.853 29.328 64.692 29.352 ;
     RECT  63.853 29.352 64.716 29.424 ;
     RECT  63.853 29.424 64.692 29.448 ;
     RECT  63.853 29.448 64.716 29.52 ;
     RECT  63.853 29.52 64.692 29.544 ;
     RECT  63.853 29.544 64.716 29.616 ;
     RECT  63.853 29.616 64.692 29.64 ;
     RECT  63.853 29.64 64.716 29.712 ;
     RECT  63.853 29.712 64.692 29.736 ;
     RECT  63.853 29.736 64.716 29.808 ;
     RECT  63.853 29.808 64.692 29.832 ;
     RECT  63.853 29.832 64.716 29.904 ;
     RECT  63.853 29.904 64.692 29.928 ;
     RECT  63.853 29.928 64.716 30 ;
     RECT  63.853 30 64.692 30.024 ;
     RECT  63.853 30.024 64.716 30.096 ;
     RECT  63.853 30.096 64.692 30.12 ;
     RECT  63.853 30.12 64.716 30.192 ;
     RECT  63.853 30.192 64.692 30.216 ;
     RECT  63.853 30.216 64.716 30.288 ;
     RECT  63.853 30.288 64.692 30.312 ;
     RECT  63.853 30.312 64.716 30.384 ;
     RECT  63.853 30.384 64.692 30.408 ;
     RECT  63.853 30.408 64.716 30.48 ;
     RECT  63.853 30.48 64.692 30.504 ;
     RECT  63.853 30.504 64.716 30.576 ;
     RECT  63.853 30.576 64.692 30.6 ;
     RECT  63.853 30.6 64.716 30.672 ;
     RECT  63.853 30.672 64.692 30.696 ;
     RECT  63.853 30.696 64.716 30.768 ;
     RECT  63.853 30.768 64.692 30.792 ;
     RECT  63.853 30.792 64.716 30.864 ;
     RECT  63.853 30.864 64.692 30.888 ;
     RECT  63.853 30.888 64.716 30.96 ;
     RECT  63.853 30.96 64.692 30.984 ;
     RECT  63.853 30.984 64.716 31.056 ;
     RECT  63.853 31.056 64.692 31.08 ;
     RECT  63.853 31.08 64.716 31.152 ;
     RECT  63.853 31.152 64.692 31.176 ;
     RECT  63.853 31.176 64.716 31.248 ;
     RECT  63.853 31.248 64.692 31.272 ;
     RECT  63.853 31.272 64.716 31.344 ;
     RECT  63.853 31.344 64.692 31.368 ;
     RECT  63.853 31.368 64.716 31.44 ;
     RECT  63.853 31.44 64.692 31.464 ;
     RECT  63.853 31.464 64.716 31.536 ;
     RECT  63.853 31.536 64.692 31.56 ;
     RECT  63.853 31.56 64.716 31.632 ;
     RECT  63.853 31.632 64.692 31.656 ;
     RECT  63.853 31.656 64.716 31.728 ;
     RECT  63.853 31.728 64.692 31.752 ;
     RECT  63.853 31.752 64.716 31.824 ;
     RECT  63.853 31.824 64.692 31.848 ;
     RECT  63.853 31.848 64.716 31.92 ;
     RECT  63.853 31.92 64.692 31.944 ;
     RECT  63.853 31.944 64.716 32.016 ;
     RECT  63.853 32.016 64.692 32.04 ;
     RECT  63.853 32.04 64.716 32.112 ;
     RECT  63.853 32.112 64.692 32.136 ;
     RECT  63.853 32.136 64.716 32.208 ;
     RECT  63.853 32.208 64.692 32.232 ;
     RECT  63.853 32.232 64.716 32.304 ;
     RECT  63.853 32.304 64.692 32.328 ;
     RECT  63.853 32.328 64.716 32.4 ;
     RECT  63.853 32.4 64.692 32.424 ;
     RECT  63.853 32.424 64.716 32.496 ;
     RECT  63.853 32.496 64.692 32.52 ;
     RECT  63.853 32.52 64.716 32.592 ;
     RECT  63.853 32.592 64.692 32.616 ;
     RECT  63.853 32.616 64.716 32.688 ;
     RECT  63.853 32.688 64.692 32.712 ;
     RECT  63.853 32.712 64.716 32.784 ;
     RECT  63.853 32.784 64.692 32.808 ;
     RECT  63.853 32.808 64.716 32.88 ;
     RECT  63.853 32.88 64.692 32.904 ;
     RECT  63.853 32.904 64.716 32.976 ;
     RECT  63.853 32.976 64.692 33 ;
     RECT  63.853 33 64.716 33.072 ;
     RECT  63.853 33.072 64.692 33.096 ;
     RECT  63.853 33.096 64.716 33.168 ;
     RECT  63.853 33.168 64.692 33.192 ;
     RECT  63.853 33.192 64.716 33.264 ;
     RECT  63.853 33.264 64.692 33.288 ;
     RECT  63.853 33.288 64.716 33.36 ;
     RECT  63.853 33.36 64.692 33.384 ;
     RECT  63.853 33.384 64.716 33.456 ;
     RECT  63.853 33.456 64.692 33.48 ;
     RECT  63.853 33.48 64.716 33.552 ;
     RECT  63.853 33.552 64.692 33.576 ;
     RECT  63.853 33.576 64.716 33.648 ;
     RECT  63.853 33.648 64.692 33.672 ;
     RECT  63.853 33.672 64.716 33.744 ;
     RECT  63.853 33.744 64.692 33.768 ;
     RECT  63.853 33.768 64.716 33.84 ;
     RECT  63.853 33.84 64.692 33.864 ;
     RECT  63.853 33.864 64.716 33.936 ;
     RECT  63.853 33.936 64.692 33.96 ;
     RECT  63.853 33.96 64.716 34.032 ;
     RECT  63.853 34.032 64.692 34.056 ;
     RECT  63.853 34.056 64.716 34.128 ;
     RECT  63.853 34.128 64.692 34.152 ;
     RECT  63.853 34.152 64.716 34.224 ;
     RECT  63.853 34.224 64.692 34.248 ;
     RECT  63.853 34.248 64.716 34.32 ;
     RECT  63.853 34.32 64.692 34.344 ;
     RECT  63.853 34.344 64.716 34.416 ;
     RECT  63.853 34.416 64.692 34.44 ;
     RECT  63.853 34.44 64.716 34.512 ;
     RECT  63.853 34.512 64.692 34.536 ;
     RECT  63.853 34.536 64.716 34.608 ;
     RECT  63.853 34.608 64.692 34.632 ;
     RECT  63.853 34.632 64.716 34.704 ;
     RECT  63.853 34.704 64.692 34.728 ;
     RECT  63.853 34.728 64.716 34.8 ;
     RECT  63.853 34.8 64.692 34.824 ;
     RECT  63.853 34.824 64.716 34.896 ;
     RECT  63.853 34.896 64.692 34.92 ;
     RECT  63.853 34.92 64.716 34.992 ;
     RECT  63.853 34.992 64.692 35.016 ;
     RECT  63.853 35.016 64.716 35.088 ;
     RECT  63.853 35.088 64.692 35.112 ;
     RECT  63.853 35.112 64.716 35.184 ;
     RECT  63.853 35.184 64.692 35.208 ;
     RECT  63.853 35.208 64.716 35.28 ;
     RECT  63.853 35.28 64.692 35.304 ;
     RECT  63.853 35.304 64.716 35.376 ;
     RECT  63.853 35.376 64.692 35.4 ;
     RECT  63.853 35.4 64.716 35.472 ;
     RECT  63.853 35.472 64.692 35.496 ;
     RECT  63.853 35.496 64.716 35.568 ;
     RECT  63.853 35.568 64.692 35.592 ;
     RECT  63.853 35.592 64.716 35.664 ;
     RECT  63.853 35.664 64.692 35.688 ;
     RECT  63.853 35.688 64.716 35.76 ;
     RECT  63.853 35.76 64.692 35.784 ;
     RECT  63.853 35.784 64.716 35.856 ;
     RECT  63.853 35.856 64.692 35.88 ;
     RECT  63.853 35.88 64.716 35.952 ;
     RECT  63.853 35.952 64.692 35.976 ;
     RECT  63.853 35.976 64.716 36.048 ;
     RECT  63.853 36.048 64.692 36.072 ;
     RECT  63.853 36.072 64.716 36.144 ;
     RECT  63.853 36.144 64.692 36.168 ;
     RECT  63.853 36.168 64.716 36.24 ;
     RECT  63.853 36.24 64.692 36.264 ;
     RECT  63.853 36.264 64.716 36.336 ;
     RECT  63.853 36.336 64.692 36.36 ;
     RECT  63.853 36.36 64.716 36.432 ;
     RECT  63.853 36.432 64.692 36.456 ;
     RECT  63.853 36.456 64.716 36.528 ;
     RECT  63.853 36.528 64.692 36.552 ;
     RECT  63.853 36.552 64.716 36.624 ;
     RECT  63.853 36.624 64.692 36.648 ;
     RECT  63.853 36.648 64.716 36.72 ;
     RECT  63.853 36.72 64.692 36.744 ;
     RECT  63.853 36.744 64.716 36.816 ;
     RECT  63.853 36.816 64.692 36.84 ;
     RECT  63.853 36.84 64.716 36.912 ;
     RECT  63.853 36.912 64.692 36.936 ;
     RECT  63.853 36.936 64.716 37.008 ;
     RECT  63.853 37.008 64.692 37.032 ;
     RECT  63.853 37.032 64.716 37.104 ;
     RECT  63.853 37.104 64.692 37.128 ;
     RECT  63.853 37.128 64.716 37.2 ;
     RECT  63.853 37.2 64.692 37.224 ;
     RECT  63.853 37.224 64.716 37.296 ;
     RECT  63.853 37.296 64.692 37.32 ;
     RECT  63.853 37.32 64.716 37.392 ;
     RECT  63.853 37.392 64.692 37.416 ;
     RECT  63.853 37.416 64.716 37.488 ;
     RECT  63.853 37.488 64.692 37.512 ;
     RECT  63.853 37.512 64.716 37.584 ;
     RECT  63.853 37.584 64.692 37.608 ;
     RECT  63.853 37.608 64.716 37.68 ;
     RECT  63.853 37.68 64.692 37.704 ;
     RECT  63.853 37.704 64.716 37.776 ;
     RECT  63.853 37.776 64.692 37.8 ;
     RECT  63.853 37.8 64.716 37.872 ;
     RECT  63.853 37.872 64.692 37.896 ;
     RECT  63.853 37.896 64.716 37.968 ;
     RECT  63.853 37.968 64.692 37.992 ;
     RECT  63.853 37.992 64.716 38.064 ;
     RECT  63.853 38.064 64.692 38.088 ;
     RECT  63.853 38.088 64.716 38.16 ;
     RECT  63.853 38.16 64.692 38.184 ;
     RECT  63.853 38.184 64.716 38.256 ;
     RECT  63.853 38.256 64.692 38.28 ;
     RECT  63.853 38.28 64.716 38.352 ;
     RECT  63.853 38.352 64.692 38.376 ;
     RECT  63.853 38.376 64.716 38.448 ;
     RECT  63.853 38.448 64.692 38.472 ;
     RECT  63.853 38.472 64.716 38.544 ;
     RECT  63.853 38.544 64.692 38.568 ;
     RECT  63.853 38.568 64.716 38.64 ;
     RECT  63.853 38.64 64.692 38.664 ;
     RECT  63.853 38.664 64.716 39.12 ;
     RECT  63.853 39.12 64.692 39.144 ;
     RECT  63.853 39.144 64.716 39.216 ;
     RECT  63.853 39.216 64.692 39.24 ;
     RECT  63.853 39.24 64.716 39.312 ;
     RECT  63.853 39.312 64.692 39.336 ;
     RECT  63.853 39.336 64.716 39.408 ;
     RECT  63.853 39.408 64.692 39.432 ;
     RECT  63.853 39.432 64.716 39.504 ;
     RECT  63.853 39.504 64.692 39.528 ;
     RECT  63.853 39.528 64.716 39.6 ;
     RECT  63.853 39.6 64.692 39.624 ;
     RECT  63.853 39.624 64.716 39.696 ;
     RECT  63.853 39.696 64.692 39.72 ;
     RECT  63.853 39.72 64.716 39.792 ;
     RECT  63.853 39.792 64.692 39.816 ;
     RECT  63.853 39.816 64.716 39.888 ;
     RECT  63.853 39.888 64.692 39.912 ;
     RECT  63.853 39.912 64.716 39.984 ;
     RECT  63.853 39.984 64.692 40.008 ;
     RECT  63.853 40.008 64.716 40.08 ;
     RECT  63.853 40.08 64.692 40.104 ;
     RECT  63.853 40.104 64.716 40.176 ;
     RECT  63.853 40.176 64.692 40.2 ;
     RECT  63.853 40.2 64.716 40.272 ;
     RECT  63.853 40.272 64.692 40.296 ;
     RECT  63.853 40.296 64.716 40.368 ;
     RECT  63.853 40.368 64.692 40.392 ;
     RECT  63.853 40.392 64.716 40.464 ;
     RECT  63.853 40.464 64.692 40.488 ;
     RECT  63.853 40.488 64.716 40.56 ;
     RECT  63.853 40.56 64.692 40.584 ;
     RECT  63.853 40.584 64.716 40.656 ;
     RECT  63.853 40.656 64.692 40.68 ;
     RECT  63.853 40.68 64.716 40.752 ;
     RECT  63.853 40.752 64.692 40.776 ;
     RECT  63.853 40.776 64.716 40.848 ;
     RECT  63.853 40.848 64.692 40.872 ;
     RECT  63.853 40.872 64.716 40.944 ;
     RECT  63.853 40.944 64.692 40.968 ;
     RECT  63.853 40.968 64.716 41.04 ;
     RECT  63.853 41.04 64.692 41.064 ;
     RECT  63.853 41.064 64.716 41.136 ;
     RECT  63.853 41.136 64.692 41.16 ;
     RECT  63.853 41.16 64.716 41.232 ;
     RECT  63.853 41.232 64.692 41.256 ;
     RECT  63.853 41.256 64.716 41.328 ;
     RECT  63.853 41.328 64.692 41.352 ;
     RECT  63.853 41.352 64.716 41.424 ;
     RECT  63.853 41.424 64.692 41.448 ;
     RECT  63.853 41.448 64.716 41.52 ;
     RECT  63.853 41.52 64.692 41.544 ;
     RECT  63.853 41.544 64.716 41.616 ;
     RECT  63.853 41.616 64.692 41.64 ;
     RECT  63.853 41.64 64.716 41.712 ;
     RECT  63.853 41.712 64.692 41.736 ;
     RECT  63.853 41.736 64.716 41.808 ;
     RECT  63.853 41.808 64.692 41.832 ;
     RECT  63.853 41.832 64.716 41.904 ;
     RECT  63.853 41.904 64.692 41.928 ;
     RECT  63.853 41.928 64.716 42 ;
     RECT  63.853 42 64.692 42.024 ;
     RECT  63.853 42.024 64.716 42.096 ;
     RECT  63.853 42.096 64.692 42.12 ;
     RECT  63.853 42.12 64.716 42.192 ;
     RECT  63.853 42.192 64.692 42.216 ;
     RECT  63.853 42.216 64.716 42.288 ;
     RECT  63.853 42.288 64.692 42.312 ;
     RECT  63.853 42.312 64.716 42.384 ;
     RECT  63.853 42.384 64.692 42.408 ;
     RECT  63.853 42.408 64.716 42.48 ;
     RECT  63.853 42.48 64.692 42.504 ;
     RECT  63.853 42.504 64.716 42.576 ;
     RECT  63.853 42.576 64.692 42.6 ;
     RECT  63.853 42.6 64.716 42.672 ;
     RECT  63.853 42.672 64.692 42.696 ;
     RECT  63.853 42.696 64.716 42.768 ;
     RECT  63.853 42.768 64.692 42.792 ;
     RECT  63.853 42.792 64.716 42.864 ;
     RECT  63.853 42.864 64.692 42.888 ;
     RECT  63.853 42.888 64.716 42.96 ;
     RECT  63.853 42.96 64.692 42.984 ;
     RECT  63.853 42.984 64.716 43.056 ;
     RECT  63.853 43.056 64.692 43.08 ;
     RECT  63.853 43.08 64.716 43.152 ;
     RECT  63.853 43.152 64.692 43.176 ;
     RECT  63.853 43.176 64.716 43.248 ;
     RECT  63.853 43.248 64.692 43.272 ;
     RECT  63.853 43.272 64.716 43.344 ;
     RECT  63.853 43.344 64.692 43.368 ;
     RECT  63.853 43.368 64.716 43.44 ;
     RECT  63.853 43.44 64.692 43.464 ;
     RECT  63.853 43.464 64.716 43.536 ;
     RECT  63.853 43.536 64.692 43.56 ;
     RECT  63.853 43.56 64.716 43.632 ;
     RECT  63.853 43.632 64.692 43.656 ;
     RECT  63.853 43.656 64.716 43.728 ;
     RECT  63.853 43.728 64.692 43.752 ;
     RECT  63.853 43.752 64.716 43.824 ;
     RECT  63.853 43.824 64.692 43.848 ;
     RECT  63.853 43.848 64.716 43.92 ;
     RECT  63.853 43.92 64.692 43.944 ;
     RECT  63.853 43.944 64.716 44.016 ;
     RECT  63.853 44.016 64.692 44.04 ;
     RECT  63.853 44.04 64.716 44.112 ;
     RECT  63.853 44.112 64.692 44.136 ;
     RECT  63.853 44.136 64.716 44.208 ;
     RECT  63.853 44.208 64.692 44.232 ;
     RECT  63.853 44.232 64.716 44.304 ;
     RECT  63.853 44.304 64.692 44.328 ;
     RECT  63.853 44.328 64.716 44.4 ;
     RECT  63.853 44.4 64.692 44.424 ;
     RECT  63.853 44.424 64.716 44.496 ;
     RECT  63.853 44.496 64.692 44.52 ;
     RECT  63.853 44.52 64.716 44.592 ;
     RECT  63.853 44.592 64.692 44.616 ;
     RECT  63.853 44.616 64.716 44.688 ;
     RECT  63.853 44.688 64.692 44.712 ;
     RECT  63.853 44.712 64.716 44.784 ;
     RECT  63.853 44.784 64.692 44.808 ;
     RECT  63.853 44.808 64.716 44.88 ;
     RECT  63.853 44.88 64.692 44.904 ;
     RECT  63.853 44.904 64.716 44.976 ;
     RECT  63.853 44.976 64.692 45 ;
     RECT  63.853 45 64.716 45.072 ;
     RECT  63.853 45.072 64.692 45.096 ;
     RECT  63.853 45.096 64.716 45.168 ;
     RECT  63.853 45.168 64.692 45.192 ;
     RECT  63.853 45.192 64.716 45.264 ;
     RECT  63.853 45.264 64.692 45.288 ;
     RECT  63.853 45.288 64.716 45.36 ;
     RECT  63.853 45.36 64.692 45.384 ;
     RECT  63.853 45.384 64.716 45.456 ;
     RECT  63.853 45.456 64.692 45.48 ;
     RECT  63.853 45.48 64.716 45.552 ;
     RECT  63.853 45.552 64.692 45.576 ;
     RECT  63.853 45.576 64.716 45.648 ;
     RECT  63.853 45.648 64.692 45.672 ;
     RECT  63.853 45.672 64.716 45.744 ;
     RECT  63.853 45.744 64.692 45.768 ;
     RECT  63.853 45.768 64.716 45.84 ;
     RECT  63.853 45.84 64.692 45.864 ;
     RECT  63.853 45.864 64.716 45.936 ;
     RECT  63.853 45.936 64.692 45.96 ;
     RECT  63.853 45.96 64.716 46.032 ;
     RECT  63.853 46.032 64.692 46.056 ;
     RECT  63.853 46.056 64.716 46.128 ;
     RECT  63.853 46.128 64.692 46.152 ;
     RECT  63.853 46.152 64.716 46.224 ;
     RECT  63.853 46.224 64.692 46.248 ;
     RECT  63.853 46.248 64.716 46.32 ;
     RECT  63.853 46.32 64.692 46.344 ;
     RECT  63.853 46.344 64.716 46.416 ;
     RECT  63.853 46.416 64.692 46.44 ;
     RECT  63.853 46.44 64.716 46.512 ;
     RECT  63.853 46.512 64.692 46.536 ;
     RECT  63.853 46.536 64.716 46.608 ;
     RECT  63.853 46.608 64.692 46.632 ;
     RECT  63.853 46.632 64.716 46.704 ;
     RECT  63.853 46.704 64.692 46.728 ;
     RECT  63.853 46.728 64.716 46.8 ;
     RECT  63.853 46.8 64.692 46.824 ;
     RECT  63.853 46.824 64.716 46.896 ;
     RECT  63.853 46.896 64.692 46.92 ;
     RECT  63.853 46.92 64.716 46.992 ;
     RECT  63.853 46.992 64.692 47.016 ;
     RECT  63.853 47.016 64.716 47.088 ;
     RECT  63.853 47.088 64.692 47.112 ;
     RECT  63.853 47.112 64.716 47.184 ;
     RECT  63.853 47.184 64.692 47.208 ;
     RECT  63.853 47.208 64.716 47.28 ;
     RECT  63.853 47.28 64.692 47.304 ;
     RECT  63.853 47.304 64.716 47.376 ;
     RECT  63.853 47.376 64.692 47.4 ;
     RECT  63.853 47.4 64.716 47.472 ;
     RECT  63.853 47.472 64.692 47.496 ;
     RECT  63.853 47.496 64.716 47.568 ;
     RECT  63.853 47.568 64.692 47.592 ;
     RECT  63.853 47.592 64.716 47.664 ;
     RECT  63.853 47.664 64.692 47.688 ;
     RECT  63.853 47.688 64.716 47.76 ;
     RECT  63.853 47.76 64.692 47.784 ;
     RECT  63.853 47.784 64.716 47.856 ;
     RECT  63.853 47.856 64.692 47.88 ;
     RECT  63.853 47.88 64.716 47.952 ;
     RECT  63.853 47.952 64.692 47.976 ;
     RECT  63.853 47.976 64.716 48.048 ;
     RECT  63.853 48.048 64.692 48.072 ;
     RECT  63.853 48.072 64.716 48.144 ;
     RECT  63.853 48.144 64.692 48.168 ;
     RECT  63.853 48.168 64.716 48.24 ;
     RECT  63.853 48.24 64.692 48.264 ;
     RECT  63.853 48.264 64.716 48.336 ;
     RECT  63.853 48.336 64.692 48.36 ;
     RECT  63.853 48.36 64.716 48.432 ;
     RECT  63.853 48.432 64.692 48.456 ;
     RECT  63.853 48.456 64.716 48.528 ;
     RECT  63.853 48.528 64.692 48.552 ;
     RECT  63.853 48.552 64.716 48.624 ;
     RECT  63.853 48.624 64.692 48.648 ;
     RECT  63.853 48.648 64.716 48.72 ;
     RECT  63.853 48.72 64.692 48.744 ;
     RECT  63.853 48.744 64.716 48.816 ;
     RECT  63.853 48.816 64.692 48.84 ;
     RECT  63.853 48.84 64.716 48.912 ;
     RECT  63.853 48.912 64.692 48.936 ;
     RECT  63.853 48.936 64.716 49.008 ;
     RECT  63.853 49.008 64.692 49.032 ;
     RECT  63.853 49.032 64.716 49.104 ;
     RECT  63.853 49.104 64.692 49.128 ;
     RECT  63.853 49.128 64.716 49.2 ;
     RECT  63.853 49.2 64.692 49.224 ;
     RECT  63.853 49.224 64.716 49.296 ;
     RECT  63.853 49.296 64.692 49.32 ;
     RECT  63.853 49.32 64.716 49.392 ;
     RECT  63.853 49.392 64.692 49.416 ;
     RECT  63.853 49.416 64.716 49.488 ;
     RECT  63.853 49.488 64.692 49.512 ;
     RECT  63.853 49.512 64.716 49.584 ;
     RECT  63.853 49.584 64.692 49.608 ;
     RECT  63.853 49.608 64.716 49.68 ;
     RECT  63.853 49.68 64.692 49.704 ;
     RECT  63.853 49.704 64.716 49.776 ;
     RECT  63.853 49.776 64.692 49.8 ;
     RECT  63.853 49.8 64.716 49.872 ;
     RECT  63.853 49.872 64.692 49.896 ;
     RECT  63.853 49.896 64.716 49.968 ;
     RECT  63.853 49.968 64.692 49.992 ;
     RECT  63.853 49.992 64.716 50.064 ;
     RECT  63.853 50.064 64.692 50.088 ;
     RECT  63.853 50.088 64.716 50.16 ;
     RECT  63.853 50.16 64.692 50.184 ;
     RECT  63.853 50.184 64.716 50.256 ;
     RECT  63.853 50.256 64.692 50.28 ;
     RECT  63.853 50.28 64.716 50.352 ;
     RECT  63.853 50.352 64.692 50.376 ;
     RECT  63.853 50.376 64.716 50.448 ;
     RECT  63.853 50.448 64.692 50.472 ;
     RECT  63.853 50.472 64.716 50.544 ;
     RECT  63.853 50.544 64.692 50.568 ;
     RECT  63.853 50.568 64.716 50.64 ;
     RECT  63.853 50.64 64.692 50.664 ;
     RECT  63.853 50.664 64.716 50.736 ;
     RECT  63.853 50.736 64.692 50.76 ;
     RECT  63.853 50.76 64.716 50.832 ;
     RECT  63.853 50.832 64.692 50.856 ;
     RECT  63.853 50.856 64.716 50.928 ;
     RECT  63.853 50.928 64.692 50.952 ;
     RECT  63.853 50.952 64.716 51.024 ;
     RECT  63.853 51.024 64.692 51.048 ;
     RECT  63.853 51.048 64.716 51.12 ;
     RECT  63.853 51.12 64.692 51.144 ;
     RECT  63.853 51.144 64.716 51.216 ;
     RECT  63.853 51.216 64.692 51.24 ;
     RECT  63.853 51.24 64.716 51.312 ;
     RECT  63.853 51.312 64.692 51.336 ;
     RECT  63.853 51.336 64.716 51.408 ;
     RECT  63.853 51.408 64.692 51.432 ;
     RECT  63.853 51.432 64.716 51.504 ;
     RECT  63.853 51.504 64.692 51.528 ;
     RECT  63.853 51.528 64.716 51.6 ;
     RECT  63.853 51.6 64.692 51.624 ;
     RECT  63.853 51.624 64.716 51.696 ;
     RECT  63.853 51.696 64.692 51.72 ;
     RECT  63.853 51.72 64.716 51.792 ;
     RECT  63.853 51.792 64.692 51.816 ;
     RECT  63.853 51.816 64.716 51.888 ;
     RECT  63.853 51.888 64.692 51.912 ;
     RECT  63.853 51.912 64.716 51.984 ;
     RECT  63.853 51.984 64.692 52.008 ;
     RECT  63.853 52.008 64.716 52.08 ;
     RECT  63.853 52.08 64.692 52.104 ;
     RECT  63.853 52.104 64.716 52.176 ;
     RECT  63.853 52.176 64.692 52.2 ;
     RECT  63.853 52.2 64.716 52.272 ;
     RECT  63.853 52.272 64.692 52.296 ;
     RECT  63.853 52.296 64.716 52.368 ;
     RECT  63.853 52.368 64.692 52.392 ;
     RECT  63.853 52.392 64.716 52.464 ;
     RECT  63.853 52.464 64.692 52.488 ;
     RECT  63.853 52.488 64.716 52.56 ;
     RECT  63.853 52.56 64.692 52.584 ;
     RECT  63.853 52.584 64.716 52.656 ;
     RECT  63.853 52.656 64.692 52.68 ;
     RECT  63.853 52.68 64.716 52.752 ;
     RECT  63.853 52.752 64.692 52.776 ;
     RECT  63.853 52.776 64.716 52.848 ;
     RECT  63.853 52.848 64.692 52.872 ;
     RECT  63.853 52.872 64.716 52.944 ;
     RECT  63.853 52.944 64.692 52.968 ;
     RECT  63.853 52.968 64.716 53.04 ;
     RECT  63.853 53.04 64.692 53.064 ;
     RECT  63.853 53.064 64.716 53.136 ;
     RECT  63.853 53.136 64.692 53.16 ;
     RECT  63.853 53.16 64.716 53.232 ;
     RECT  63.853 53.232 64.692 53.256 ;
     RECT  63.853 53.256 64.716 53.328 ;
     RECT  63.853 53.328 64.692 53.352 ;
     RECT  63.853 53.352 64.716 53.424 ;
     RECT  63.853 53.424 64.692 53.448 ;
     RECT  63.853 53.448 64.716 53.52 ;
     RECT  63.853 53.52 64.692 53.544 ;
     RECT  63.853 53.544 64.716 53.616 ;
     RECT  63.853 53.616 64.692 53.64 ;
     RECT  63.853 53.64 64.716 53.712 ;
     RECT  63.853 53.712 64.692 53.736 ;
     RECT  63.853 53.736 64.716 53.808 ;
     RECT  63.853 53.808 64.692 53.832 ;
     RECT  63.853 53.832 64.716 53.904 ;
     RECT  63.853 53.904 64.692 53.928 ;
     RECT  63.853 53.928 64.716 54 ;
     RECT  63.853 54 64.692 54.024 ;
     RECT  63.853 54.024 64.716 54.096 ;
     RECT  63.853 54.096 64.692 54.12 ;
     RECT  63.853 54.12 64.716 54.192 ;
     RECT  63.853 54.192 64.692 54.216 ;
     RECT  63.853 54.216 64.716 54.288 ;
     RECT  63.853 54.288 64.692 54.312 ;
     RECT  63.853 54.312 64.716 54.384 ;
     RECT  63.853 54.384 64.692 54.408 ;
     RECT  63.853 54.408 64.716 54.48 ;
     RECT  63.853 54.48 64.692 54.504 ;
     RECT  63.853 54.504 64.716 54.576 ;
     RECT  63.853 54.576 64.692 54.6 ;
     RECT  63.853 54.6 64.716 54.672 ;
     RECT  63.853 54.672 64.692 54.696 ;
     RECT  63.853 54.696 64.716 54.768 ;
     RECT  63.853 54.768 64.692 54.792 ;
     RECT  63.853 54.792 64.716 54.864 ;
     RECT  63.853 54.864 64.692 54.888 ;
     RECT  63.853 54.888 64.716 54.96 ;
     RECT  63.853 54.96 64.692 54.984 ;
     RECT  63.853 54.984 64.716 55.056 ;
     RECT  63.853 55.056 64.692 55.08 ;
     RECT  63.853 55.08 64.716 55.152 ;
     RECT  63.853 55.152 64.692 55.176 ;
     RECT  63.853 55.176 64.716 55.248 ;
     RECT  63.853 55.248 64.692 55.272 ;
     RECT  63.853 55.272 64.716 55.344 ;
     RECT  63.853 55.344 64.692 55.368 ;
     RECT  63.853 55.368 64.716 55.44 ;
     RECT  63.853 55.44 64.692 55.464 ;
     RECT  63.853 55.464 64.716 55.536 ;
     RECT  63.853 55.536 64.692 55.56 ;
     RECT  63.853 55.56 64.716 55.632 ;
     RECT  63.853 55.632 64.692 55.656 ;
     RECT  63.853 55.656 64.716 55.728 ;
     RECT  63.853 55.728 64.692 55.752 ;
     RECT  63.853 55.752 64.716 55.824 ;
     RECT  63.853 55.824 64.692 55.848 ;
     RECT  63.853 55.848 64.716 55.92 ;
     RECT  63.853 55.92 64.692 55.944 ;
     RECT  63.853 55.944 64.716 56.016 ;
     RECT  63.853 56.016 64.692 56.04 ;
     RECT  63.853 56.04 64.716 56.112 ;
     RECT  63.853 56.112 64.692 56.136 ;
     RECT  63.853 56.136 64.716 56.208 ;
     RECT  63.853 56.208 64.692 56.232 ;
     RECT  63.853 56.232 64.716 56.304 ;
     RECT  63.853 56.304 64.692 56.328 ;
     RECT  63.853 56.328 64.716 56.4 ;
     RECT  63.853 56.4 64.692 56.424 ;
     RECT  63.853 56.424 64.716 56.496 ;
     RECT  63.853 56.496 64.692 56.52 ;
     RECT  63.853 56.52 64.716 56.592 ;
     RECT  63.853 56.592 64.692 56.616 ;
     RECT  63.853 56.616 64.716 56.688 ;
     RECT  63.853 56.688 64.692 56.712 ;
     RECT  63.853 56.712 64.716 56.784 ;
     RECT  63.853 56.784 64.692 56.808 ;
     RECT  63.853 56.808 64.716 56.88 ;
     RECT  63.853 56.88 64.692 56.904 ;
     RECT  63.853 56.904 64.716 56.976 ;
     RECT  63.853 56.976 64.692 57 ;
     RECT  63.853 57 64.716 57.072 ;
     RECT  63.853 57.072 64.692 57.096 ;
     RECT  63.853 57.096 64.716 57.168 ;
     RECT  63.853 57.168 64.692 57.192 ;
     RECT  63.853 57.192 64.716 57.264 ;
     RECT  63.853 57.264 64.692 57.288 ;
     RECT  63.853 57.288 64.716 57.36 ;
     RECT  63.853 57.36 64.692 57.384 ;
     RECT  63.853 57.384 64.716 57.456 ;
     RECT  63.853 57.456 64.692 57.48 ;
     RECT  64.716 4.128 64.757 4.176 ;
     RECT  64.716 4.2 64.757 4.272 ;
     RECT  64.716 4.296 64.757 4.368 ;
     RECT  64.716 4.392 64.757 4.464 ;
     RECT  64.716 4.488 64.757 4.56 ;
     RECT  64.716 4.584 64.757 4.656 ;
     RECT  64.716 4.68 64.757 4.752 ;
     RECT  64.716 4.776 64.757 4.848 ;
     RECT  64.716 4.872 64.757 4.944 ;
     RECT  64.716 4.968 64.757 5.04 ;
     RECT  64.716 5.064 64.757 5.136 ;
     RECT  64.716 5.16 64.757 5.232 ;
     RECT  64.716 5.256 64.757 5.328 ;
     RECT  64.716 5.352 64.757 5.424 ;
     RECT  64.716 5.448 64.757 5.52 ;
     RECT  64.716 5.544 64.757 5.592 ;
     RECT  64.716 9.504 64.757 9.528 ;
     RECT  64.716 12.48 64.757 12.504 ;
     RECT  64.716 18.144 64.757 18.168 ;
     RECT  64.716 20.928 64.757 20.952 ;
     RECT  64.716 23.328 64.757 23.352 ;
     RECT  64.716 25.152 64.757 25.176 ;
     RECT  64.716 27.744 64.757 27.768 ;
     RECT  64.716 30.144 64.757 30.192 ;
     RECT  64.716 30.216 64.757 30.288 ;
     RECT  64.716 30.312 64.757 30.384 ;
     RECT  64.716 30.408 64.757 30.48 ;
     RECT  64.716 30.504 64.757 30.576 ;
     RECT  64.716 30.6 64.757 30.672 ;
     RECT  64.716 30.696 64.757 30.768 ;
     RECT  64.716 30.792 64.757 30.864 ;
     RECT  64.716 30.888 64.757 30.96 ;
     RECT  64.716 30.984 64.757 31.056 ;
     RECT  64.716 31.08 64.757 31.128 ;
     RECT  64.716 50.4 64.757 50.424 ;
    LAYER M5 ;
     RECT  2.4 2.137 2.52 2.151 ;
     RECT  5.1 2.137 5.22 2.151 ;
     RECT  7.8 2.137 7.92 2.151 ;
     RECT  10.5 2.137 10.62 2.151 ;
     RECT  13.2 2.137 13.32 2.151 ;
     RECT  15.9 2.137 16.02 2.151 ;
     RECT  18.6 2.137 18.72 2.151 ;
     RECT  21.3 2.137 21.42 2.151 ;
     RECT  24 2.137 24.12 2.151 ;
     RECT  26.7 2.137 26.82 2.151 ;
     RECT  29.4 2.137 29.52 2.151 ;
     RECT  32.1 2.137 32.22 2.151 ;
     RECT  34.8 2.137 34.92 2.151 ;
     RECT  37.5 2.137 37.62 2.151 ;
     RECT  40.2 2.137 40.32 2.151 ;
     RECT  42.9 2.137 43.02 2.151 ;
     RECT  45.6 2.137 45.72 2.151 ;
     RECT  48.3 2.137 48.42 2.151 ;
     RECT  51 2.137 51.12 2.151 ;
     RECT  53.7 2.137 53.82 2.151 ;
     RECT  56.4 2.137 56.52 2.151 ;
     RECT  59.1 2.137 59.22 2.151 ;
     RECT  61.8 2.137 61.92 2.151 ;
     RECT  59.1 2.151 59.412 3.925 ;
     RECT  56.4 2.151 56.712 4.501 ;
     RECT  55.536 4.501 56.712 4.789 ;
     RECT  58.272 3.925 59.412 4.789 ;
     RECT  55.536 4.789 59.412 5.029 ;
     RECT  60.384 3.925 60.408 5.029 ;
     RECT  55.536 5.029 60.408 5.171 ;
     RECT  58.992 5.171 60.408 5.795 ;
     RECT  55.536 5.171 57.384 5.845 ;
     RECT  55.248 5.845 57.384 6.275 ;
     RECT  58.992 5.795 59.412 6.275 ;
     RECT  60.384 5.795 60.408 6.563 ;
     RECT  45.6 2.151 45.912 6.565 ;
     RECT  45.6 6.565 46.44 6.853 ;
     RECT  59.1 6.275 59.412 7.765 ;
     RECT  55.248 6.275 56.712 8.437 ;
     RECT  59.1 7.765 60.168 8.437 ;
     RECT  58.944 8.437 60.168 9.541 ;
     RECT  55.248 8.437 57.048 9.731 ;
     RECT  58.944 9.541 60.552 10.307 ;
     RECT  45.6 6.853 46.536 10.597 ;
     RECT  55.248 9.731 56.712 10.643 ;
     RECT  58.944 10.307 60.168 10.883 ;
     RECT  55.536 10.643 56.712 10.979 ;
     RECT  58.944 10.883 59.832 10.981 ;
     RECT  2.4 2.151 2.712 11.125 ;
     RECT  55.632 10.979 56.712 11.171 ;
     RECT  45.504 10.597 46.536 12.035 ;
     RECT  45.504 12.035 45.912 12.373 ;
     RECT  58.656 10.981 59.832 12.611 ;
     RECT  58.944 12.611 59.832 13.045 ;
     RECT  58.944 13.045 59.928 13.187 ;
     RECT  58.944 13.187 59.412 14.773 ;
     RECT  56.4 11.171 56.712 15.301 ;
     RECT  58.704 14.773 59.412 16.259 ;
     RECT  53.7 2.151 54.012 16.357 ;
     RECT  53.7 16.357 54.12 16.547 ;
     RECT  56.4 15.301 56.808 16.837 ;
     RECT  61.8 2.151 62.112 16.837 ;
     RECT  45.312 12.373 45.912 16.883 ;
     RECT  58.752 16.259 59.412 17.077 ;
     RECT  60.96 16.837 62.112 17.077 ;
     RECT  56.4 16.837 57.144 17.123 ;
     RECT  58.752 17.077 62.112 17.123 ;
     RECT  51 2.151 51.312 17.413 ;
     RECT  58.752 17.123 60.024 17.651 ;
     RECT  58.752 17.651 59.412 19.045 ;
     RECT  58.752 19.045 59.592 19.091 ;
     RECT  58.992 19.091 59.592 20.339 ;
     RECT  59.1 20.339 59.592 21.973 ;
     RECT  37.5 2.151 37.812 23.557 ;
     RECT  45.6 16.883 45.912 23.893 ;
     RECT  59.1 21.973 59.88 23.987 ;
     RECT  45.504 23.893 45.912 24.085 ;
     RECT  42.9 2.151 43.212 24.469 ;
     RECT  50.832 17.413 51.312 25.381 ;
     RECT  45.456 24.085 45.912 26.197 ;
     RECT  59.1 23.987 59.592 26.533 ;
     RECT  34.8 2.151 35.112 26.677 ;
     RECT  32.1 2.151 32.412 26.725 ;
     RECT  34.176 26.677 35.112 26.725 ;
     RECT  45.456 26.197 46.44 26.725 ;
     RECT  59.1 26.533 59.688 26.915 ;
     RECT  36.336 27.061 36.36 27.157 ;
     RECT  36.336 27.157 36.456 27.349 ;
     RECT  36.24 27.349 36.456 27.685 ;
     RECT  37.5 23.557 38.232 27.685 ;
     RECT  32.1 26.725 35.112 27.781 ;
     RECT  36.24 27.685 38.232 27.781 ;
     RECT  59.1 26.915 59.592 27.973 ;
     RECT  58.704 27.973 59.592 28.019 ;
     RECT  58.704 28.019 59.412 28.355 ;
     RECT  42.432 24.469 43.212 28.405 ;
     RECT  42.432 28.405 43.416 28.453 ;
     RECT  59.1 28.355 59.412 28.981 ;
     RECT  45.216 26.725 46.44 29.605 ;
     RECT  2.4 11.125 3.192 29.699 ;
     RECT  32.1 27.781 38.232 30.181 ;
     RECT  32.1 30.181 39.144 30.709 ;
     RECT  40.2 2.151 40.512 30.709 ;
     RECT  44.976 29.605 46.44 30.757 ;
     RECT  59.1 28.981 59.544 30.851 ;
     RECT  44.976 30.757 46.728 30.899 ;
     RECT  59.1 30.851 59.412 31.141 ;
     RECT  32.1 30.709 40.512 31.525 ;
     RECT  56.4 17.123 56.712 31.621 ;
     RECT  0.144 29.605 0.168 31.763 ;
     RECT  50.736 25.381 51.312 31.811 ;
     RECT  29.4 2.151 29.712 31.861 ;
     RECT  32.1 31.525 40.632 31.861 ;
     RECT  32.1 31.861 41.16 32.293 ;
     RECT  42.432 28.453 43.752 32.293 ;
     RECT  58.992 31.141 59.412 32.533 ;
     RECT  61.8 17.123 62.112 32.581 ;
     RECT  26.7 2.151 27.012 32.965 ;
     RECT  58.704 32.533 59.412 32.965 ;
     RECT  61.536 32.581 62.112 33.251 ;
     RECT  58.704 32.965 60.072 33.299 ;
     RECT  26.7 32.965 27.432 33.637 ;
     RECT  59.1 33.299 60.072 34.357 ;
     RECT  32.1 32.293 43.752 34.501 ;
     RECT  59.1 34.357 60.408 35.365 ;
     RECT  55.536 31.621 56.712 35.509 ;
     RECT  57.84 34.165 57.864 35.509 ;
     RECT  58.992 35.365 60.408 35.651 ;
     RECT  32.1 34.501 43.896 35.797 ;
     RECT  44.976 30.899 46.44 35.797 ;
     RECT  58.992 35.651 59.412 36.515 ;
     RECT  55.536 35.509 57.864 36.709 ;
     RECT  60.384 35.651 60.408 37.091 ;
     RECT  31.008 27.157 31.032 37.381 ;
     RECT  32.1 35.797 46.44 37.381 ;
     RECT  50.832 31.811 51.312 37.667 ;
     RECT  55.536 36.709 57.96 38.149 ;
     RECT  26.592 33.637 27.432 38.629 ;
     RECT  28.656 31.861 29.712 38.629 ;
     RECT  26.592 38.629 29.712 38.677 ;
     RECT  55.344 38.149 57.96 38.819 ;
     RECT  59.1 36.515 59.412 39.061 ;
     RECT  25.968 38.677 29.712 39.541 ;
     RECT  31.008 37.381 46.44 39.541 ;
     RECT  51 37.667 51.312 40.021 ;
     RECT  55.68 38.819 57.96 40.595 ;
     RECT  56.304 40.595 57.96 40.837 ;
     RECT  59.1 39.061 60.024 40.837 ;
     RECT  56.304 40.837 60.024 41.075 ;
     RECT  58.704 41.075 60.024 41.221 ;
     RECT  58.704 41.221 60.216 41.603 ;
     RECT  56.304 41.075 57.384 41.747 ;
     RECT  59.1 41.603 60.216 43.379 ;
     RECT  59.1 43.379 59.412 43.381 ;
     RECT  58.992 43.381 59.412 44.051 ;
     RECT  50.112 40.021 51.312 44.677 ;
     RECT  49.824 44.677 51.312 44.723 ;
     RECT  56.4 41.747 57.384 45.541 ;
     RECT  55.872 45.541 57.384 45.877 ;
     RECT  55.872 45.877 57.912 47.701 ;
     RECT  60.48 46.213 60.504 48.083 ;
     RECT  55.44 47.701 57.912 48.515 ;
     RECT  60.528 48.421 60.552 49.525 ;
     RECT  49.824 44.723 49.848 49.619 ;
     RECT  60.528 49.525 60.6 50.579 ;
     RECT  60.528 50.579 60.552 50.867 ;
     RECT  55.872 48.515 57.912 51.541 ;
     RECT  55.296 51.541 57.912 51.829 ;
     RECT  61.8 33.251 62.112 52.405 ;
     RECT  55.296 51.829 57.96 52.981 ;
     RECT  59.1 44.051 59.412 52.981 ;
     RECT  55.296 52.981 59.412 53.603 ;
     RECT  60.96 52.405 62.112 53.989 ;
     RECT  60.768 53.989 62.112 54.035 ;
     RECT  56.016 53.603 57.96 54.419 ;
     RECT  56.016 54.419 57.24 54.661 ;
     RECT  55.44 54.661 57.24 55.331 ;
     RECT  60.768 54.035 60.792 55.907 ;
     RECT  55.44 55.331 56.808 57.059 ;
     RECT  60.72 56.389 60.744 57.059 ;
     RECT  2.4 29.699 2.712 58.059 ;
     RECT  5.1 2.151 5.412 58.059 ;
     RECT  7.8 2.151 8.112 58.059 ;
     RECT  10.5 2.151 10.812 58.059 ;
     RECT  13.2 2.151 13.512 58.059 ;
     RECT  15.9 2.151 16.212 58.059 ;
     RECT  18.6 2.151 18.912 58.059 ;
     RECT  21.3 2.151 21.612 58.059 ;
     RECT  24 2.151 24.312 58.059 ;
     RECT  48.3 2.151 48.612 58.059 ;
     RECT  51 44.723 51.312 58.059 ;
     RECT  53.7 16.547 54.012 58.059 ;
     RECT  56.4 57.059 56.712 58.059 ;
     RECT  59.1 53.603 59.412 58.059 ;
     RECT  61.8 54.035 62.112 58.059 ;
     RECT  2.592 58.059 2.712 58.073 ;
     RECT  5.292 58.059 5.412 58.073 ;
     RECT  7.992 58.059 8.112 58.073 ;
     RECT  10.692 58.059 10.812 58.073 ;
     RECT  13.392 58.059 13.512 58.073 ;
     RECT  16.092 58.059 16.212 58.073 ;
     RECT  18.792 58.059 18.912 58.073 ;
     RECT  21.492 58.059 21.612 58.073 ;
     RECT  24.192 58.059 24.312 58.073 ;
     RECT  48.492 58.059 48.612 58.073 ;
     RECT  51.192 58.059 51.312 58.073 ;
     RECT  53.892 58.059 54.012 58.073 ;
     RECT  56.592 58.059 56.712 58.073 ;
     RECT  59.292 58.059 59.412 58.073 ;
     RECT  61.992 58.059 62.112 58.073 ;
     RECT  25.968 39.541 46.44 58.691 ;
     RECT  25.968 58.691 45.528 60.181 ;
     RECT  25.488 60.181 45.528 60.275 ;
     RECT  25.488 60.275 45.48 60.323 ;
     RECT  25.968 60.323 45.48 60.371 ;
     RECT  25.968 60.371 44.808 60.372 ;
     RECT  25.992 60.372 26.064 60.432 ;
     RECT  26.088 60.372 26.16 60.432 ;
     RECT  26.184 60.372 26.256 60.432 ;
     RECT  26.28 60.372 26.352 60.432 ;
     RECT  26.376 60.372 26.448 60.432 ;
     RECT  26.472 60.372 26.544 60.432 ;
     RECT  26.568 60.372 26.64 60.432 ;
     RECT  26.664 60.372 26.736 60.432 ;
     RECT  26.76 60.372 26.832 60.432 ;
     RECT  26.856 60.372 26.928 60.432 ;
     RECT  26.952 60.372 27.024 60.432 ;
     RECT  27.048 60.372 27.12 60.432 ;
     RECT  27.144 60.372 27.216 60.432 ;
     RECT  27.24 60.372 27.312 60.432 ;
     RECT  27.336 60.372 27.408 60.432 ;
     RECT  27.432 60.372 27.504 60.432 ;
     RECT  27.528 60.372 27.6 60.432 ;
     RECT  27.624 60.372 27.696 60.432 ;
     RECT  27.72 60.372 27.792 60.432 ;
     RECT  27.816 60.372 27.888 60.432 ;
     RECT  27.912 60.372 27.984 60.432 ;
     RECT  28.008 60.372 28.08 60.432 ;
     RECT  28.104 60.372 28.176 60.432 ;
     RECT  28.2 60.372 28.272 60.432 ;
     RECT  28.296 60.372 28.368 60.432 ;
     RECT  28.392 60.372 28.464 60.432 ;
     RECT  28.488 60.372 28.56 60.432 ;
     RECT  28.584 60.372 28.656 60.432 ;
     RECT  28.68 60.372 28.752 60.432 ;
     RECT  28.776 60.372 28.848 60.432 ;
     RECT  28.872 60.372 28.944 60.432 ;
     RECT  28.968 60.372 29.04 60.432 ;
     RECT  29.064 60.372 29.136 60.432 ;
     RECT  29.16 60.372 29.232 60.432 ;
     RECT  29.256 60.372 29.328 60.432 ;
     RECT  29.352 60.372 29.424 60.432 ;
     RECT  29.448 60.372 29.52 60.432 ;
     RECT  29.544 60.372 29.616 60.432 ;
     RECT  29.64 60.372 29.712 60.432 ;
     RECT  29.736 60.372 29.808 60.432 ;
     RECT  29.832 60.372 29.904 60.432 ;
     RECT  29.928 60.372 30 60.432 ;
     RECT  30.024 60.372 30.096 60.432 ;
     RECT  30.12 60.372 30.192 60.432 ;
     RECT  30.216 60.372 30.288 60.432 ;
     RECT  30.312 60.372 30.384 60.432 ;
     RECT  30.408 60.372 30.48 60.432 ;
     RECT  30.504 60.372 30.576 60.432 ;
     RECT  30.6 60.372 30.672 60.432 ;
     RECT  30.696 60.372 30.768 60.432 ;
     RECT  30.792 60.372 30.864 60.432 ;
     RECT  30.888 60.372 30.96 60.432 ;
     RECT  30.984 60.372 31.056 60.432 ;
     RECT  31.08 60.372 31.152 60.432 ;
     RECT  31.176 60.372 31.248 60.432 ;
     RECT  31.272 60.372 31.344 60.432 ;
     RECT  31.368 60.372 31.44 60.432 ;
     RECT  31.464 60.372 31.536 60.432 ;
     RECT  31.56 60.372 31.632 60.432 ;
     RECT  31.656 60.372 31.728 60.432 ;
     RECT  31.752 60.372 31.824 60.432 ;
     RECT  31.848 60.372 31.92 60.432 ;
     RECT  31.944 60.372 32.016 60.432 ;
     RECT  32.04 60.372 32.112 60.432 ;
     RECT  32.136 60.372 32.208 60.432 ;
     RECT  32.232 60.372 32.304 60.432 ;
     RECT  32.328 60.372 32.4 60.432 ;
     RECT  32.424 60.372 32.496 60.432 ;
     RECT  32.52 60.372 32.592 60.432 ;
     RECT  32.616 60.372 32.688 60.432 ;
     RECT  32.712 60.372 32.784 60.432 ;
     RECT  32.808 60.372 32.88 60.432 ;
     RECT  32.904 60.372 32.976 60.432 ;
     RECT  33 60.372 33.072 60.432 ;
     RECT  33.096 60.372 33.168 60.432 ;
     RECT  33.192 60.372 33.264 60.432 ;
     RECT  33.288 60.372 33.36 60.432 ;
     RECT  33.384 60.372 33.456 60.432 ;
     RECT  33.48 60.372 33.552 60.432 ;
     RECT  33.576 60.372 33.648 60.432 ;
     RECT  33.672 60.372 33.744 60.432 ;
     RECT  33.768 60.372 33.84 60.432 ;
     RECT  33.864 60.372 33.936 60.432 ;
     RECT  33.96 60.372 34.032 60.432 ;
     RECT  34.056 60.372 34.128 60.432 ;
     RECT  34.152 60.372 34.224 60.432 ;
     RECT  34.248 60.372 34.32 60.432 ;
     RECT  34.344 60.372 34.416 60.432 ;
     RECT  34.44 60.372 34.512 60.432 ;
     RECT  34.536 60.372 34.608 60.432 ;
     RECT  34.632 60.372 34.704 60.432 ;
     RECT  34.728 60.372 34.8 60.432 ;
     RECT  34.824 60.372 34.896 60.432 ;
     RECT  34.92 60.372 34.992 60.432 ;
     RECT  35.016 60.372 35.088 60.432 ;
     RECT  35.112 60.372 35.184 60.432 ;
     RECT  35.208 60.372 35.28 60.432 ;
     RECT  35.304 60.372 35.376 60.432 ;
     RECT  35.4 60.372 35.472 60.432 ;
     RECT  35.496 60.372 35.568 60.432 ;
     RECT  35.592 60.372 35.664 60.432 ;
     RECT  35.688 60.372 35.76 60.432 ;
     RECT  35.784 60.372 35.856 60.432 ;
     RECT  35.88 60.372 35.952 60.432 ;
     RECT  35.976 60.372 36.048 60.432 ;
     RECT  36.072 60.372 36.144 60.432 ;
     RECT  36.168 60.372 36.24 60.432 ;
     RECT  36.264 60.372 36.336 60.432 ;
     RECT  36.36 60.372 36.432 60.432 ;
     RECT  36.456 60.372 36.528 60.432 ;
     RECT  36.552 60.372 36.624 60.432 ;
     RECT  36.648 60.372 36.72 60.432 ;
     RECT  36.744 60.372 36.816 60.432 ;
     RECT  36.84 60.372 36.912 60.432 ;
     RECT  36.936 60.372 37.008 60.432 ;
     RECT  37.032 60.372 37.104 60.432 ;
     RECT  37.128 60.372 37.2 60.432 ;
     RECT  37.224 60.372 37.296 60.432 ;
     RECT  37.32 60.372 37.392 60.432 ;
     RECT  37.416 60.372 37.488 60.432 ;
     RECT  37.512 60.372 37.584 60.432 ;
     RECT  37.608 60.372 37.68 60.432 ;
     RECT  37.704 60.372 37.776 60.432 ;
     RECT  37.8 60.372 37.872 60.432 ;
     RECT  37.896 60.372 37.968 60.432 ;
     RECT  37.992 60.372 38.064 60.432 ;
     RECT  38.088 60.372 38.16 60.432 ;
     RECT  38.184 60.372 38.256 60.432 ;
     RECT  38.28 60.372 38.352 60.432 ;
     RECT  38.376 60.372 38.448 60.432 ;
     RECT  38.472 60.372 38.544 60.432 ;
     RECT  38.568 60.372 38.64 60.432 ;
     RECT  38.664 60.372 38.736 60.432 ;
     RECT  38.76 60.372 38.832 60.432 ;
     RECT  38.856 60.372 38.928 60.432 ;
     RECT  38.952 60.372 39.024 60.432 ;
     RECT  39.048 60.372 39.12 60.432 ;
     RECT  39.144 60.372 39.216 60.432 ;
     RECT  39.24 60.372 39.312 60.432 ;
     RECT  39.336 60.372 39.408 60.432 ;
     RECT  39.432 60.372 39.504 60.432 ;
     RECT  39.528 60.372 39.6 60.432 ;
     RECT  39.624 60.372 39.696 60.432 ;
     RECT  39.72 60.372 39.792 60.432 ;
     RECT  39.816 60.372 39.888 60.432 ;
     RECT  39.912 60.372 39.984 60.432 ;
     RECT  40.008 60.372 40.08 60.432 ;
     RECT  40.104 60.372 40.176 60.432 ;
     RECT  40.2 60.372 40.272 60.432 ;
     RECT  40.296 60.372 40.368 60.432 ;
     RECT  40.392 60.372 40.464 60.432 ;
     RECT  40.488 60.372 40.56 60.432 ;
     RECT  40.584 60.372 40.656 60.432 ;
     RECT  40.68 60.372 40.752 60.432 ;
     RECT  40.776 60.372 40.848 60.432 ;
     RECT  40.872 60.372 40.944 60.432 ;
     RECT  40.968 60.372 41.04 60.432 ;
     RECT  41.064 60.372 41.136 60.432 ;
     RECT  41.16 60.372 41.232 60.432 ;
     RECT  41.256 60.372 41.328 60.432 ;
     RECT  41.352 60.372 41.424 60.432 ;
     RECT  41.448 60.372 41.52 60.432 ;
     RECT  41.544 60.372 41.616 60.432 ;
     RECT  41.64 60.372 41.712 60.432 ;
     RECT  41.736 60.372 41.808 60.432 ;
     RECT  41.832 60.372 41.904 60.432 ;
     RECT  41.928 60.372 42 60.432 ;
     RECT  42.024 60.372 42.096 60.432 ;
     RECT  42.12 60.372 42.192 60.432 ;
     RECT  42.216 60.372 42.288 60.432 ;
     RECT  42.312 60.372 42.384 60.432 ;
     RECT  42.408 60.372 42.48 60.432 ;
     RECT  42.504 60.372 42.576 60.432 ;
     RECT  42.6 60.372 42.672 60.432 ;
     RECT  42.696 60.372 42.768 60.432 ;
     RECT  42.792 60.372 42.864 60.432 ;
     RECT  42.888 60.372 42.96 60.432 ;
     RECT  42.984 60.372 43.056 60.432 ;
     RECT  43.08 60.372 43.152 60.432 ;
     RECT  43.176 60.372 43.248 60.432 ;
     RECT  43.272 60.372 43.344 60.432 ;
     RECT  43.368 60.372 43.44 60.432 ;
     RECT  43.464 60.372 43.536 60.432 ;
     RECT  43.56 60.372 43.632 60.432 ;
     RECT  43.656 60.372 43.728 60.432 ;
     RECT  43.752 60.372 43.824 60.432 ;
     RECT  43.848 60.372 43.92 60.432 ;
     RECT  43.944 60.372 44.016 60.432 ;
     RECT  44.04 60.372 44.112 60.432 ;
     RECT  44.136 60.372 44.208 60.432 ;
     RECT  44.232 60.372 44.304 60.432 ;
     RECT  44.328 60.372 44.4 60.432 ;
     RECT  44.424 60.372 44.496 60.432 ;
     RECT  44.52 60.372 44.592 60.432 ;
     RECT  44.616 60.372 44.688 60.432 ;
     RECT  44.712 60.372 44.784 60.432 ;
     RECT  59.412 3.925 60.384 5.029 ;
     RECT  60.408 3.925 61.8 6.563 ;
     RECT  54.012 4.501 55.536 5.845 ;
     RECT  59.412 5.795 60.384 6.563 ;
     RECT  54.012 5.845 55.248 10.643 ;
     RECT  59.412 6.563 60.168 7.765 ;
     RECT  60.552 9.541 61.8 10.307 ;
     RECT  54.012 10.643 55.536 10.979 ;
     RECT  59.412 17.651 59.592 19.045 ;
     RECT  35.112 27.061 36.336 27.349 ;
     RECT  36.36 27.061 37.5 27.157 ;
     RECT  29.712 27.157 31.008 39.541 ;
     RECT  31.032 27.157 32.1 37.381 ;
     RECT  36.456 27.157 37.5 27.685 ;
     RECT  35.112 27.349 36.24 27.781 ;
     RECT  59.412 28.019 59.544 28.981 ;
     RECT  43.752 28.453 45.216 29.605 ;
     RECT  43.752 29.605 44.976 34.501 ;
     RECT  39.144 30.181 40.2 30.709 ;
     RECT  54.012 31.621 55.536 38.149 ;
     RECT  41.16 31.861 42.432 32.293 ;
     RECT  27.432 32.965 28.656 38.629 ;
     RECT  60.072 32.965 61.536 33.251 ;
     RECT  60.072 33.251 61.8 34.357 ;
     RECT  58.704 33.299 59.1 34.165 ;
     RECT  56.712 34.165 57.84 35.509 ;
     RECT  57.864 34.165 59.1 35.365 ;
     RECT  60.408 34.357 61.8 37.091 ;
     RECT  43.896 34.501 44.976 35.797 ;
     RECT  57.864 35.365 58.992 36.515 ;
     RECT  59.412 35.651 60.384 37.091 ;
     RECT  57.864 36.515 59.1 36.709 ;
     RECT  57.96 36.709 59.1 40.837 ;
     RECT  54.012 38.149 55.344 38.819 ;
     RECT  48.612 40.021 50.112 44.677 ;
     RECT  57.384 41.075 58.704 41.603 ;
     RECT  48.612 44.677 49.824 49.619 ;
     RECT  49.848 44.723 51 49.619 ;
     RECT  57.912 45.877 59.1 51.829 ;
     RECT  59.412 46.213 60.48 48.083 ;
     RECT  60.504 46.213 61.8 48.083 ;
     RECT  54.012 47.701 55.44 48.515 ;
     RECT  59.412 48.083 61.8 48.421 ;
     RECT  59.412 48.421 60.528 50.867 ;
     RECT  60.552 48.421 61.8 49.525 ;
     RECT  60.6 49.525 61.8 50.579 ;
     RECT  60.552 50.579 61.8 50.867 ;
     RECT  54.012 51.541 55.296 53.603 ;
     RECT  57.96 51.829 59.1 52.981 ;
     RECT  54.012 53.603 56.016 54.661 ;
     RECT  57.96 53.603 59.1 54.419 ;
     RECT  59.412 53.989 60.768 55.907 ;
     RECT  60.792 54.035 61.8 55.907 ;
     RECT  54.012 54.661 55.44 57.059 ;
     RECT  59.412 55.907 61.8 56.389 ;
     RECT  59.412 56.389 60.72 57.059 ;
     RECT  60.744 56.389 61.8 57.059 ;
  END
END qfd_rlyh0_548_EN_65x60
END LIBRARY
